VERSION 5.8 ;
BUSBITCHARS "[]" ;
DIVIDERCHAR "/" ;
UNITS
    DATABASE MICRONS 1000 ;
END UNITS

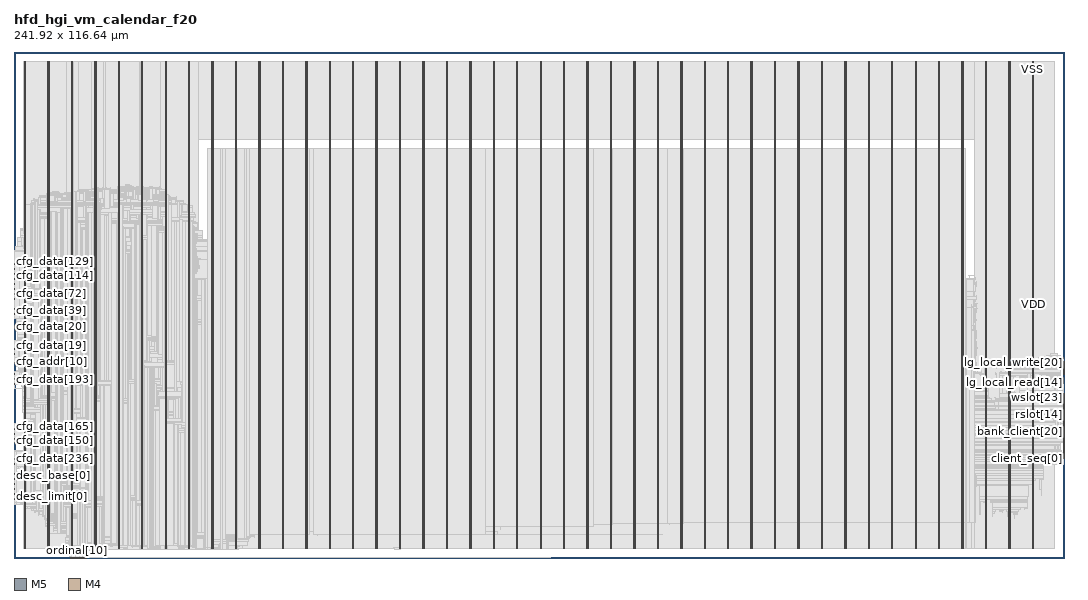
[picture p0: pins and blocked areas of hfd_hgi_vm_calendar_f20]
MACRO hfd_hgi_vm_calendar_f20
  FOREIGN hfd_hgi_vm_calendar_f20 0 0 ;
  CLASS BLOCK ;
  SIZE 241.92 BY 116.64 ;
  PIN active
    DIRECTION OUTPUT ;
    USE SIGNAL ;
    PORT
      LAYER M5 ;
        RECT  13.008 0 13.032 0.084 ;
    END
  END active
  PIN bank_client[0]
    DIRECTION OUTPUT ;
    USE SIGNAL ;
    PORT
      LAYER M4 ;
        RECT  241.836 29.136 241.92 29.16 ;
    END
  END bank_client[0]
  PIN bank_client[10]
    DIRECTION OUTPUT ;
    USE SIGNAL ;
    PORT
      LAYER M4 ;
        RECT  241.836 30.096 241.92 30.12 ;
    END
  END bank_client[10]
  PIN bank_client[11]
    DIRECTION OUTPUT ;
    USE SIGNAL ;
    PORT
      LAYER M4 ;
        RECT  241.836 30.192 241.92 30.216 ;
    END
  END bank_client[11]
  PIN bank_client[12]
    DIRECTION OUTPUT ;
    USE SIGNAL ;
    PORT
      LAYER M4 ;
        RECT  241.836 30.288 241.92 30.312 ;
    END
  END bank_client[12]
  PIN bank_client[13]
    DIRECTION OUTPUT ;
    USE SIGNAL ;
    PORT
      LAYER M4 ;
        RECT  241.836 30.384 241.92 30.408 ;
    END
  END bank_client[13]
  PIN bank_client[14]
    DIRECTION OUTPUT ;
    USE SIGNAL ;
    PORT
      LAYER M4 ;
        RECT  241.836 30.48 241.92 30.504 ;
    END
  END bank_client[14]
  PIN bank_client[15]
    DIRECTION OUTPUT ;
    USE SIGNAL ;
    PORT
      LAYER M4 ;
        RECT  241.836 30.576 241.92 30.6 ;
    END
  END bank_client[15]
  PIN bank_client[16]
    DIRECTION OUTPUT ;
    USE SIGNAL ;
    PORT
      LAYER M4 ;
        RECT  241.836 30.672 241.92 30.696 ;
    END
  END bank_client[16]
  PIN bank_client[17]
    DIRECTION OUTPUT ;
    USE SIGNAL ;
    PORT
      LAYER M4 ;
        RECT  241.836 30.768 241.92 30.792 ;
    END
  END bank_client[17]
  PIN bank_client[18]
    DIRECTION OUTPUT ;
    USE SIGNAL ;
    PORT
      LAYER M4 ;
        RECT  241.836 30.864 241.92 30.888 ;
    END
  END bank_client[18]
  PIN bank_client[19]
    DIRECTION OUTPUT ;
    USE SIGNAL ;
    PORT
      LAYER M4 ;
        RECT  241.836 30.96 241.92 30.984 ;
    END
  END bank_client[19]
  PIN bank_client[1]
    DIRECTION OUTPUT ;
    USE SIGNAL ;
    PORT
      LAYER M4 ;
        RECT  241.836 29.232 241.92 29.256 ;
    END
  END bank_client[1]
  PIN bank_client[20]
    DIRECTION OUTPUT ;
    USE SIGNAL ;
    PORT
      LAYER M4 ;
        RECT  241.836 31.056 241.92 31.08 ;
    END
  END bank_client[20]
  PIN bank_client[21]
    DIRECTION OUTPUT ;
    USE SIGNAL ;
    PORT
      LAYER M4 ;
        RECT  241.836 31.152 241.92 31.176 ;
    END
  END bank_client[21]
  PIN bank_client[22]
    DIRECTION OUTPUT ;
    USE SIGNAL ;
    PORT
      LAYER M4 ;
        RECT  241.836 31.248 241.92 31.272 ;
    END
  END bank_client[22]
  PIN bank_client[23]
    DIRECTION OUTPUT ;
    USE SIGNAL ;
    PORT
      LAYER M4 ;
        RECT  241.836 31.344 241.92 31.368 ;
    END
  END bank_client[23]
  PIN bank_client[2]
    DIRECTION OUTPUT ;
    USE SIGNAL ;
    PORT
      LAYER M4 ;
        RECT  241.836 29.328 241.92 29.352 ;
    END
  END bank_client[2]
  PIN bank_client[3]
    DIRECTION OUTPUT ;
    USE SIGNAL ;
    PORT
      LAYER M4 ;
        RECT  241.836 29.424 241.92 29.448 ;
    END
  END bank_client[3]
  PIN bank_client[4]
    DIRECTION OUTPUT ;
    USE SIGNAL ;
    PORT
      LAYER M4 ;
        RECT  241.836 29.52 241.92 29.544 ;
    END
  END bank_client[4]
  PIN bank_client[5]
    DIRECTION OUTPUT ;
    USE SIGNAL ;
    PORT
      LAYER M4 ;
        RECT  241.836 29.616 241.92 29.64 ;
    END
  END bank_client[5]
  PIN bank_client[6]
    DIRECTION OUTPUT ;
    USE SIGNAL ;
    PORT
      LAYER M4 ;
        RECT  241.836 29.712 241.92 29.736 ;
    END
  END bank_client[6]
  PIN bank_client[7]
    DIRECTION OUTPUT ;
    USE SIGNAL ;
    PORT
      LAYER M4 ;
        RECT  241.836 29.808 241.92 29.832 ;
    END
  END bank_client[7]
  PIN bank_client[8]
    DIRECTION OUTPUT ;
    USE SIGNAL ;
    PORT
      LAYER M4 ;
        RECT  241.836 29.904 241.92 29.928 ;
    END
  END bank_client[8]
  PIN bank_client[9]
    DIRECTION OUTPUT ;
    USE SIGNAL ;
    PORT
      LAYER M4 ;
        RECT  241.836 30 241.92 30.024 ;
    END
  END bank_client[9]
  PIN bank_enable[0]
    DIRECTION OUTPUT ;
    USE SIGNAL ;
    PORT
      LAYER M4 ;
        RECT  241.836 31.44 241.92 31.464 ;
    END
  END bank_enable[0]
  PIN bank_enable[1]
    DIRECTION OUTPUT ;
    USE SIGNAL ;
    PORT
      LAYER M4 ;
        RECT  241.836 31.536 241.92 31.56 ;
    END
  END bank_enable[1]
  PIN bank_enable[2]
    DIRECTION OUTPUT ;
    USE SIGNAL ;
    PORT
      LAYER M4 ;
        RECT  241.836 31.632 241.92 31.656 ;
    END
  END bank_enable[2]
  PIN bank_enable[3]
    DIRECTION OUTPUT ;
    USE SIGNAL ;
    PORT
      LAYER M4 ;
        RECT  241.836 31.728 241.92 31.752 ;
    END
  END bank_enable[3]
  PIN bank_enable[4]
    DIRECTION OUTPUT ;
    USE SIGNAL ;
    PORT
      LAYER M4 ;
        RECT  241.836 31.824 241.92 31.848 ;
    END
  END bank_enable[4]
  PIN bank_enable[5]
    DIRECTION OUTPUT ;
    USE SIGNAL ;
    PORT
      LAYER M4 ;
        RECT  241.836 31.92 241.92 31.944 ;
    END
  END bank_enable[5]
  PIN bank_enable[6]
    DIRECTION OUTPUT ;
    USE SIGNAL ;
    PORT
      LAYER M4 ;
        RECT  241.836 32.016 241.92 32.04 ;
    END
  END bank_enable[6]
  PIN bank_enable[7]
    DIRECTION OUTPUT ;
    USE SIGNAL ;
    PORT
      LAYER M4 ;
        RECT  241.836 32.112 241.92 32.136 ;
    END
  END bank_enable[7]
  PIN calendar_v
    DIRECTION OUTPUT ;
    USE SIGNAL ;
    PORT
      LAYER M5 ;
        RECT  13.104 0 13.128 0.084 ;
    END
  END calendar_v
  PIN cfg_addr[0]
    DIRECTION INPUT ;
    USE SIGNAL ;
    PORT
      LAYER M4 ;
        RECT  0 46.032 0.084 46.056 ;
    END
  END cfg_addr[0]
  PIN cfg_addr[10]
    DIRECTION INPUT ;
    USE SIGNAL ;
    PORT
      LAYER M4 ;
        RECT  0 46.992 0.084 47.016 ;
    END
  END cfg_addr[10]
  PIN cfg_addr[11]
    DIRECTION INPUT ;
    USE SIGNAL ;
    PORT
      LAYER M4 ;
        RECT  0 47.088 0.084 47.112 ;
    END
  END cfg_addr[11]
  PIN cfg_addr[1]
    DIRECTION INPUT ;
    USE SIGNAL ;
    PORT
      LAYER M4 ;
        RECT  0 46.128 0.084 46.152 ;
    END
  END cfg_addr[1]
  PIN cfg_addr[2]
    DIRECTION INPUT ;
    USE SIGNAL ;
    PORT
      LAYER M4 ;
        RECT  0 46.224 0.084 46.248 ;
    END
  END cfg_addr[2]
  PIN cfg_addr[3]
    DIRECTION INPUT ;
    USE SIGNAL ;
    PORT
      LAYER M4 ;
        RECT  0 46.32 0.084 46.344 ;
    END
  END cfg_addr[3]
  PIN cfg_addr[4]
    DIRECTION INPUT ;
    USE SIGNAL ;
    PORT
      LAYER M4 ;
        RECT  0 46.416 0.084 46.44 ;
    END
  END cfg_addr[4]
  PIN cfg_addr[5]
    DIRECTION INPUT ;
    USE SIGNAL ;
    PORT
      LAYER M4 ;
        RECT  0 46.512 0.084 46.536 ;
    END
  END cfg_addr[5]
  PIN cfg_addr[6]
    DIRECTION INPUT ;
    USE SIGNAL ;
    PORT
      LAYER M4 ;
        RECT  0 46.608 0.084 46.632 ;
    END
  END cfg_addr[6]
  PIN cfg_addr[7]
    DIRECTION INPUT ;
    USE SIGNAL ;
    PORT
      LAYER M4 ;
        RECT  0 46.704 0.084 46.728 ;
    END
  END cfg_addr[7]
  PIN cfg_addr[8]
    DIRECTION INPUT ;
    USE SIGNAL ;
    PORT
      LAYER M4 ;
        RECT  0 46.8 0.084 46.824 ;
    END
  END cfg_addr[8]
  PIN cfg_addr[9]
    DIRECTION INPUT ;
    USE SIGNAL ;
    PORT
      LAYER M4 ;
        RECT  0 46.896 0.084 46.92 ;
    END
  END cfg_addr[9]
  PIN cfg_data[0]
    DIRECTION INPUT ;
    USE SIGNAL ;
    PORT
      LAYER M4 ;
        RECT  0 47.184 0.084 47.208 ;
    END
  END cfg_data[0]
  PIN cfg_data[100]
    DIRECTION INPUT ;
    USE SIGNAL ;
    PORT
      LAYER M4 ;
        RECT  0 63.696 0.084 63.72 ;
    END
  END cfg_data[100]
  PIN cfg_data[101]
    DIRECTION INPUT ;
    USE SIGNAL ;
    PORT
      LAYER M4 ;
        RECT  0 63.792 0.084 63.816 ;
    END
  END cfg_data[101]
  PIN cfg_data[102]
    DIRECTION INPUT ;
    USE SIGNAL ;
    PORT
      LAYER M4 ;
        RECT  0 63.888 0.084 63.912 ;
    END
  END cfg_data[102]
  PIN cfg_data[103]
    DIRECTION INPUT ;
    USE SIGNAL ;
    PORT
      LAYER M4 ;
        RECT  0 63.984 0.084 64.008 ;
    END
  END cfg_data[103]
  PIN cfg_data[104]
    DIRECTION INPUT ;
    USE SIGNAL ;
    PORT
      LAYER M4 ;
        RECT  0 64.08 0.084 64.104 ;
    END
  END cfg_data[104]
  PIN cfg_data[105]
    DIRECTION INPUT ;
    USE SIGNAL ;
    PORT
      LAYER M4 ;
        RECT  0 64.176 0.084 64.2 ;
    END
  END cfg_data[105]
  PIN cfg_data[106]
    DIRECTION INPUT ;
    USE SIGNAL ;
    PORT
      LAYER M4 ;
        RECT  0 64.272 0.084 64.296 ;
    END
  END cfg_data[106]
  PIN cfg_data[107]
    DIRECTION INPUT ;
    USE SIGNAL ;
    PORT
      LAYER M4 ;
        RECT  0 64.368 0.084 64.392 ;
    END
  END cfg_data[107]
  PIN cfg_data[108]
    DIRECTION INPUT ;
    USE SIGNAL ;
    PORT
      LAYER M4 ;
        RECT  0 64.464 0.084 64.488 ;
    END
  END cfg_data[108]
  PIN cfg_data[109]
    DIRECTION INPUT ;
    USE SIGNAL ;
    PORT
      LAYER M4 ;
        RECT  0 64.56 0.084 64.584 ;
    END
  END cfg_data[109]
  PIN cfg_data[10]
    DIRECTION INPUT ;
    USE SIGNAL ;
    PORT
      LAYER M4 ;
        RECT  0 48.144 0.084 48.168 ;
    END
  END cfg_data[10]
  PIN cfg_data[110]
    DIRECTION INPUT ;
    USE SIGNAL ;
    PORT
      LAYER M4 ;
        RECT  0 64.656 0.084 64.68 ;
    END
  END cfg_data[110]
  PIN cfg_data[111]
    DIRECTION INPUT ;
    USE SIGNAL ;
    PORT
      LAYER M4 ;
        RECT  0 64.752 0.084 64.776 ;
    END
  END cfg_data[111]
  PIN cfg_data[112]
    DIRECTION INPUT ;
    USE SIGNAL ;
    PORT
      LAYER M4 ;
        RECT  0 64.848 0.084 64.872 ;
    END
  END cfg_data[112]
  PIN cfg_data[113]
    DIRECTION INPUT ;
    USE SIGNAL ;
    PORT
      LAYER M4 ;
        RECT  0 64.944 0.084 64.968 ;
    END
  END cfg_data[113]
  PIN cfg_data[114]
    DIRECTION INPUT ;
    USE SIGNAL ;
    PORT
      LAYER M4 ;
        RECT  0 65.04 0.084 65.064 ;
    END
  END cfg_data[114]
  PIN cfg_data[115]
    DIRECTION INPUT ;
    USE SIGNAL ;
    PORT
      LAYER M4 ;
        RECT  0 65.136 0.084 65.16 ;
    END
  END cfg_data[115]
  PIN cfg_data[116]
    DIRECTION INPUT ;
    USE SIGNAL ;
    PORT
      LAYER M4 ;
        RECT  0 65.232 0.084 65.256 ;
    END
  END cfg_data[116]
  PIN cfg_data[117]
    DIRECTION INPUT ;
    USE SIGNAL ;
    PORT
      LAYER M4 ;
        RECT  0 65.328 0.084 65.352 ;
    END
  END cfg_data[117]
  PIN cfg_data[118]
    DIRECTION INPUT ;
    USE SIGNAL ;
    PORT
      LAYER M4 ;
        RECT  0 65.424 0.084 65.448 ;
    END
  END cfg_data[118]
  PIN cfg_data[119]
    DIRECTION INPUT ;
    USE SIGNAL ;
    PORT
      LAYER M4 ;
        RECT  0 65.52 0.084 65.544 ;
    END
  END cfg_data[119]
  PIN cfg_data[11]
    DIRECTION INPUT ;
    USE SIGNAL ;
    PORT
      LAYER M4 ;
        RECT  0 48.24 0.084 48.264 ;
    END
  END cfg_data[11]
  PIN cfg_data[120]
    DIRECTION INPUT ;
    USE SIGNAL ;
    PORT
      LAYER M4 ;
        RECT  0 65.616 0.084 65.64 ;
    END
  END cfg_data[120]
  PIN cfg_data[121]
    DIRECTION INPUT ;
    USE SIGNAL ;
    PORT
      LAYER M4 ;
        RECT  0 65.712 0.084 65.736 ;
    END
  END cfg_data[121]
  PIN cfg_data[122]
    DIRECTION INPUT ;
    USE SIGNAL ;
    PORT
      LAYER M4 ;
        RECT  0 65.808 0.084 65.832 ;
    END
  END cfg_data[122]
  PIN cfg_data[123]
    DIRECTION INPUT ;
    USE SIGNAL ;
    PORT
      LAYER M4 ;
        RECT  0 65.904 0.084 65.928 ;
    END
  END cfg_data[123]
  PIN cfg_data[124]
    DIRECTION INPUT ;
    USE SIGNAL ;
    PORT
      LAYER M4 ;
        RECT  0 66 0.084 66.024 ;
    END
  END cfg_data[124]
  PIN cfg_data[125]
    DIRECTION INPUT ;
    USE SIGNAL ;
    PORT
      LAYER M4 ;
        RECT  0 66.096 0.084 66.12 ;
    END
  END cfg_data[125]
  PIN cfg_data[126]
    DIRECTION INPUT ;
    USE SIGNAL ;
    PORT
      LAYER M4 ;
        RECT  0 66.192 0.084 66.216 ;
    END
  END cfg_data[126]
  PIN cfg_data[127]
    DIRECTION INPUT ;
    USE SIGNAL ;
    PORT
      LAYER M4 ;
        RECT  0 66.288 0.084 66.312 ;
    END
  END cfg_data[127]
  PIN cfg_data[128]
    DIRECTION INPUT ;
    USE SIGNAL ;
    PORT
      LAYER M4 ;
        RECT  0 66.384 0.084 66.408 ;
    END
  END cfg_data[128]
  PIN cfg_data[129]
    DIRECTION INPUT ;
    USE SIGNAL ;
    PORT
      LAYER M4 ;
        RECT  0 66.48 0.084 66.504 ;
    END
  END cfg_data[129]
  PIN cfg_data[12]
    DIRECTION INPUT ;
    USE SIGNAL ;
    PORT
      LAYER M4 ;
        RECT  0 48.336 0.084 48.36 ;
    END
  END cfg_data[12]
  PIN cfg_data[130]
    DIRECTION INPUT ;
    USE SIGNAL ;
    PORT
      LAYER M4 ;
        RECT  0 66.576 0.084 66.6 ;
    END
  END cfg_data[130]
  PIN cfg_data[131]
    DIRECTION INPUT ;
    USE SIGNAL ;
    PORT
      LAYER M4 ;
        RECT  0 66.672 0.084 66.696 ;
    END
  END cfg_data[131]
  PIN cfg_data[132]
    DIRECTION INPUT ;
    USE SIGNAL ;
    PORT
      LAYER M4 ;
        RECT  0 66.768 0.084 66.792 ;
    END
  END cfg_data[132]
  PIN cfg_data[133]
    DIRECTION INPUT ;
    USE SIGNAL ;
    PORT
      LAYER M4 ;
        RECT  0 66.864 0.084 66.888 ;
    END
  END cfg_data[133]
  PIN cfg_data[134]
    DIRECTION INPUT ;
    USE SIGNAL ;
    PORT
      LAYER M4 ;
        RECT  0 66.96 0.084 66.984 ;
    END
  END cfg_data[134]
  PIN cfg_data[135]
    DIRECTION INPUT ;
    USE SIGNAL ;
    PORT
      LAYER M4 ;
        RECT  0 67.056 0.084 67.08 ;
    END
  END cfg_data[135]
  PIN cfg_data[136]
    DIRECTION INPUT ;
    USE SIGNAL ;
    PORT
      LAYER M4 ;
        RECT  0 67.152 0.084 67.176 ;
    END
  END cfg_data[136]
  PIN cfg_data[137]
    DIRECTION INPUT ;
    USE SIGNAL ;
    PORT
      LAYER M4 ;
        RECT  0 67.248 0.084 67.272 ;
    END
  END cfg_data[137]
  PIN cfg_data[138]
    DIRECTION INPUT ;
    USE SIGNAL ;
    PORT
      LAYER M4 ;
        RECT  0 67.344 0.084 67.368 ;
    END
  END cfg_data[138]
  PIN cfg_data[139]
    DIRECTION INPUT ;
    USE SIGNAL ;
    PORT
      LAYER M4 ;
        RECT  0 67.44 0.084 67.464 ;
    END
  END cfg_data[139]
  PIN cfg_data[13]
    DIRECTION INPUT ;
    USE SIGNAL ;
    PORT
      LAYER M4 ;
        RECT  0 48.432 0.084 48.456 ;
    END
  END cfg_data[13]
  PIN cfg_data[140]
    DIRECTION INPUT ;
    USE SIGNAL ;
    PORT
      LAYER M4 ;
        RECT  0 67.536 0.084 67.56 ;
    END
  END cfg_data[140]
  PIN cfg_data[141]
    DIRECTION INPUT ;
    USE SIGNAL ;
    PORT
      LAYER M4 ;
        RECT  0 67.632 0.084 67.656 ;
    END
  END cfg_data[141]
  PIN cfg_data[142]
    DIRECTION INPUT ;
    USE SIGNAL ;
    PORT
      LAYER M4 ;
        RECT  0 67.728 0.084 67.752 ;
    END
  END cfg_data[142]
  PIN cfg_data[143]
    DIRECTION INPUT ;
    USE SIGNAL ;
    PORT
      LAYER M4 ;
        RECT  0 67.824 0.084 67.848 ;
    END
  END cfg_data[143]
  PIN cfg_data[144]
    DIRECTION INPUT ;
    USE SIGNAL ;
    PORT
      LAYER M4 ;
        RECT  0 67.92 0.084 67.944 ;
    END
  END cfg_data[144]
  PIN cfg_data[145]
    DIRECTION INPUT ;
    USE SIGNAL ;
    PORT
      LAYER M4 ;
        RECT  0 68.016 0.084 68.04 ;
    END
  END cfg_data[145]
  PIN cfg_data[146]
    DIRECTION INPUT ;
    USE SIGNAL ;
    PORT
      LAYER M4 ;
        RECT  0 68.112 0.084 68.136 ;
    END
  END cfg_data[146]
  PIN cfg_data[147]
    DIRECTION INPUT ;
    USE SIGNAL ;
    PORT
      LAYER M4 ;
        RECT  0 68.208 0.084 68.232 ;
    END
  END cfg_data[147]
  PIN cfg_data[148]
    DIRECTION INPUT ;
    USE SIGNAL ;
    PORT
      LAYER M4 ;
        RECT  0 26.832 0.084 26.856 ;
    END
  END cfg_data[148]
  PIN cfg_data[149]
    DIRECTION INPUT ;
    USE SIGNAL ;
    PORT
      LAYER M4 ;
        RECT  0 26.928 0.084 26.952 ;
    END
  END cfg_data[149]
  PIN cfg_data[14]
    DIRECTION INPUT ;
    USE SIGNAL ;
    PORT
      LAYER M4 ;
        RECT  0 48.528 0.084 48.552 ;
    END
  END cfg_data[14]
  PIN cfg_data[150]
    DIRECTION INPUT ;
    USE SIGNAL ;
    PORT
      LAYER M4 ;
        RECT  0 27.024 0.084 27.048 ;
    END
  END cfg_data[150]
  PIN cfg_data[151]
    DIRECTION INPUT ;
    USE SIGNAL ;
    PORT
      LAYER M4 ;
        RECT  0 27.12 0.084 27.144 ;
    END
  END cfg_data[151]
  PIN cfg_data[152]
    DIRECTION INPUT ;
    USE SIGNAL ;
    PORT
      LAYER M4 ;
        RECT  0 27.216 0.084 27.24 ;
    END
  END cfg_data[152]
  PIN cfg_data[153]
    DIRECTION INPUT ;
    USE SIGNAL ;
    PORT
      LAYER M4 ;
        RECT  0 27.312 0.084 27.336 ;
    END
  END cfg_data[153]
  PIN cfg_data[154]
    DIRECTION INPUT ;
    USE SIGNAL ;
    PORT
      LAYER M4 ;
        RECT  0 27.408 0.084 27.432 ;
    END
  END cfg_data[154]
  PIN cfg_data[155]
    DIRECTION INPUT ;
    USE SIGNAL ;
    PORT
      LAYER M4 ;
        RECT  0 27.504 0.084 27.528 ;
    END
  END cfg_data[155]
  PIN cfg_data[156]
    DIRECTION INPUT ;
    USE SIGNAL ;
    PORT
      LAYER M4 ;
        RECT  0 27.6 0.084 27.624 ;
    END
  END cfg_data[156]
  PIN cfg_data[157]
    DIRECTION INPUT ;
    USE SIGNAL ;
    PORT
      LAYER M4 ;
        RECT  0 27.696 0.084 27.72 ;
    END
  END cfg_data[157]
  PIN cfg_data[158]
    DIRECTION INPUT ;
    USE SIGNAL ;
    PORT
      LAYER M4 ;
        RECT  0 27.792 0.084 27.816 ;
    END
  END cfg_data[158]
  PIN cfg_data[159]
    DIRECTION INPUT ;
    USE SIGNAL ;
    PORT
      LAYER M4 ;
        RECT  0 27.888 0.084 27.912 ;
    END
  END cfg_data[159]
  PIN cfg_data[15]
    DIRECTION INPUT ;
    USE SIGNAL ;
    PORT
      LAYER M4 ;
        RECT  0 48.624 0.084 48.648 ;
    END
  END cfg_data[15]
  PIN cfg_data[160]
    DIRECTION INPUT ;
    USE SIGNAL ;
    PORT
      LAYER M4 ;
        RECT  0 27.984 0.084 28.008 ;
    END
  END cfg_data[160]
  PIN cfg_data[161]
    DIRECTION INPUT ;
    USE SIGNAL ;
    PORT
      LAYER M4 ;
        RECT  0 28.08 0.084 28.104 ;
    END
  END cfg_data[161]
  PIN cfg_data[162]
    DIRECTION INPUT ;
    USE SIGNAL ;
    PORT
      LAYER M4 ;
        RECT  0 28.176 0.084 28.2 ;
    END
  END cfg_data[162]
  PIN cfg_data[163]
    DIRECTION INPUT ;
    USE SIGNAL ;
    PORT
      LAYER M4 ;
        RECT  0 28.272 0.084 28.296 ;
    END
  END cfg_data[163]
  PIN cfg_data[164]
    DIRECTION INPUT ;
    USE SIGNAL ;
    PORT
      LAYER M4 ;
        RECT  0 28.368 0.084 28.392 ;
    END
  END cfg_data[164]
  PIN cfg_data[165]
    DIRECTION INPUT ;
    USE SIGNAL ;
    PORT
      LAYER M4 ;
        RECT  0 28.464 0.084 28.488 ;
    END
  END cfg_data[165]
  PIN cfg_data[166]
    DIRECTION INPUT ;
    USE SIGNAL ;
    PORT
      LAYER M4 ;
        RECT  0 28.56 0.084 28.584 ;
    END
  END cfg_data[166]
  PIN cfg_data[167]
    DIRECTION INPUT ;
    USE SIGNAL ;
    PORT
      LAYER M4 ;
        RECT  0 28.656 0.084 28.68 ;
    END
  END cfg_data[167]
  PIN cfg_data[168]
    DIRECTION INPUT ;
    USE SIGNAL ;
    PORT
      LAYER M4 ;
        RECT  0 28.752 0.084 28.776 ;
    END
  END cfg_data[168]
  PIN cfg_data[169]
    DIRECTION INPUT ;
    USE SIGNAL ;
    PORT
      LAYER M4 ;
        RECT  0 28.848 0.084 28.872 ;
    END
  END cfg_data[169]
  PIN cfg_data[16]
    DIRECTION INPUT ;
    USE SIGNAL ;
    PORT
      LAYER M4 ;
        RECT  0 48.72 0.084 48.744 ;
    END
  END cfg_data[16]
  PIN cfg_data[170]
    DIRECTION INPUT ;
    USE SIGNAL ;
    PORT
      LAYER M4 ;
        RECT  0 28.944 0.084 28.968 ;
    END
  END cfg_data[170]
  PIN cfg_data[171]
    DIRECTION INPUT ;
    USE SIGNAL ;
    PORT
      LAYER M4 ;
        RECT  0 29.04 0.084 29.064 ;
    END
  END cfg_data[171]
  PIN cfg_data[172]
    DIRECTION INPUT ;
    USE SIGNAL ;
    PORT
      LAYER M4 ;
        RECT  0 29.136 0.084 29.16 ;
    END
  END cfg_data[172]
  PIN cfg_data[173]
    DIRECTION INPUT ;
    USE SIGNAL ;
    PORT
      LAYER M4 ;
        RECT  0 29.232 0.084 29.256 ;
    END
  END cfg_data[173]
  PIN cfg_data[174]
    DIRECTION INPUT ;
    USE SIGNAL ;
    PORT
      LAYER M4 ;
        RECT  0 29.328 0.084 29.352 ;
    END
  END cfg_data[174]
  PIN cfg_data[175]
    DIRECTION INPUT ;
    USE SIGNAL ;
    PORT
      LAYER M4 ;
        RECT  0 29.424 0.084 29.448 ;
    END
  END cfg_data[175]
  PIN cfg_data[176]
    DIRECTION INPUT ;
    USE SIGNAL ;
    PORT
      LAYER M4 ;
        RECT  0 29.52 0.084 29.544 ;
    END
  END cfg_data[176]
  PIN cfg_data[177]
    DIRECTION INPUT ;
    USE SIGNAL ;
    PORT
      LAYER M4 ;
        RECT  0 29.616 0.084 29.64 ;
    END
  END cfg_data[177]
  PIN cfg_data[178]
    DIRECTION INPUT ;
    USE SIGNAL ;
    PORT
      LAYER M4 ;
        RECT  0 29.712 0.084 29.736 ;
    END
  END cfg_data[178]
  PIN cfg_data[179]
    DIRECTION INPUT ;
    USE SIGNAL ;
    PORT
      LAYER M4 ;
        RECT  0 29.808 0.084 29.832 ;
    END
  END cfg_data[179]
  PIN cfg_data[17]
    DIRECTION INPUT ;
    USE SIGNAL ;
    PORT
      LAYER M4 ;
        RECT  0 48.816 0.084 48.84 ;
    END
  END cfg_data[17]
  PIN cfg_data[180]
    DIRECTION INPUT ;
    USE SIGNAL ;
    PORT
      LAYER M4 ;
        RECT  0 39.888 0.084 39.912 ;
    END
  END cfg_data[180]
  PIN cfg_data[181]
    DIRECTION INPUT ;
    USE SIGNAL ;
    PORT
      LAYER M4 ;
        RECT  0 39.984 0.084 40.008 ;
    END
  END cfg_data[181]
  PIN cfg_data[182]
    DIRECTION INPUT ;
    USE SIGNAL ;
    PORT
      LAYER M4 ;
        RECT  0 40.08 0.084 40.104 ;
    END
  END cfg_data[182]
  PIN cfg_data[183]
    DIRECTION INPUT ;
    USE SIGNAL ;
    PORT
      LAYER M4 ;
        RECT  0 40.176 0.084 40.2 ;
    END
  END cfg_data[183]
  PIN cfg_data[184]
    DIRECTION INPUT ;
    USE SIGNAL ;
    PORT
      LAYER M4 ;
        RECT  0 40.272 0.084 40.296 ;
    END
  END cfg_data[184]
  PIN cfg_data[185]
    DIRECTION INPUT ;
    USE SIGNAL ;
    PORT
      LAYER M4 ;
        RECT  0 40.368 0.084 40.392 ;
    END
  END cfg_data[185]
  PIN cfg_data[186]
    DIRECTION INPUT ;
    USE SIGNAL ;
    PORT
      LAYER M4 ;
        RECT  0 40.464 0.084 40.488 ;
    END
  END cfg_data[186]
  PIN cfg_data[187]
    DIRECTION INPUT ;
    USE SIGNAL ;
    PORT
      LAYER M4 ;
        RECT  0 40.56 0.084 40.584 ;
    END
  END cfg_data[187]
  PIN cfg_data[188]
    DIRECTION INPUT ;
    USE SIGNAL ;
    PORT
      LAYER M4 ;
        RECT  0 40.656 0.084 40.68 ;
    END
  END cfg_data[188]
  PIN cfg_data[189]
    DIRECTION INPUT ;
    USE SIGNAL ;
    PORT
      LAYER M4 ;
        RECT  0 40.752 0.084 40.776 ;
    END
  END cfg_data[189]
  PIN cfg_data[18]
    DIRECTION INPUT ;
    USE SIGNAL ;
    PORT
      LAYER M4 ;
        RECT  0 48.912 0.084 48.936 ;
    END
  END cfg_data[18]
  PIN cfg_data[190]
    DIRECTION INPUT ;
    USE SIGNAL ;
    PORT
      LAYER M4 ;
        RECT  0 40.848 0.084 40.872 ;
    END
  END cfg_data[190]
  PIN cfg_data[191]
    DIRECTION INPUT ;
    USE SIGNAL ;
    PORT
      LAYER M4 ;
        RECT  0 40.944 0.084 40.968 ;
    END
  END cfg_data[191]
  PIN cfg_data[192]
    DIRECTION INPUT ;
    USE SIGNAL ;
    PORT
      LAYER M4 ;
        RECT  0 41.04 0.084 41.064 ;
    END
  END cfg_data[192]
  PIN cfg_data[193]
    DIRECTION INPUT ;
    USE SIGNAL ;
    PORT
      LAYER M4 ;
        RECT  0 41.136 0.084 41.16 ;
    END
  END cfg_data[193]
  PIN cfg_data[194]
    DIRECTION INPUT ;
    USE SIGNAL ;
    PORT
      LAYER M4 ;
        RECT  0 41.232 0.084 41.256 ;
    END
  END cfg_data[194]
  PIN cfg_data[195]
    DIRECTION INPUT ;
    USE SIGNAL ;
    PORT
      LAYER M4 ;
        RECT  0 41.328 0.084 41.352 ;
    END
  END cfg_data[195]
  PIN cfg_data[196]
    DIRECTION INPUT ;
    USE SIGNAL ;
    PORT
      LAYER M4 ;
        RECT  0 41.424 0.084 41.448 ;
    END
  END cfg_data[196]
  PIN cfg_data[197]
    DIRECTION INPUT ;
    USE SIGNAL ;
    PORT
      LAYER M4 ;
        RECT  0 41.52 0.084 41.544 ;
    END
  END cfg_data[197]
  PIN cfg_data[198]
    DIRECTION INPUT ;
    USE SIGNAL ;
    PORT
      LAYER M4 ;
        RECT  0 41.616 0.084 41.64 ;
    END
  END cfg_data[198]
  PIN cfg_data[199]
    DIRECTION INPUT ;
    USE SIGNAL ;
    PORT
      LAYER M4 ;
        RECT  0 41.712 0.084 41.736 ;
    END
  END cfg_data[199]
  PIN cfg_data[19]
    DIRECTION INPUT ;
    USE SIGNAL ;
    PORT
      LAYER M4 ;
        RECT  0 49.008 0.084 49.032 ;
    END
  END cfg_data[19]
  PIN cfg_data[1]
    DIRECTION INPUT ;
    USE SIGNAL ;
    PORT
      LAYER M4 ;
        RECT  0 47.28 0.084 47.304 ;
    END
  END cfg_data[1]
  PIN cfg_data[200]
    DIRECTION INPUT ;
    USE SIGNAL ;
    PORT
      LAYER M4 ;
        RECT  0 41.808 0.084 41.832 ;
    END
  END cfg_data[200]
  PIN cfg_data[201]
    DIRECTION INPUT ;
    USE SIGNAL ;
    PORT
      LAYER M4 ;
        RECT  0 41.904 0.084 41.928 ;
    END
  END cfg_data[201]
  PIN cfg_data[202]
    DIRECTION INPUT ;
    USE SIGNAL ;
    PORT
      LAYER M4 ;
        RECT  0 42 0.084 42.024 ;
    END
  END cfg_data[202]
  PIN cfg_data[203]
    DIRECTION INPUT ;
    USE SIGNAL ;
    PORT
      LAYER M4 ;
        RECT  0 42.096 0.084 42.12 ;
    END
  END cfg_data[203]
  PIN cfg_data[204]
    DIRECTION INPUT ;
    USE SIGNAL ;
    PORT
      LAYER M4 ;
        RECT  0 42.192 0.084 42.216 ;
    END
  END cfg_data[204]
  PIN cfg_data[205]
    DIRECTION INPUT ;
    USE SIGNAL ;
    PORT
      LAYER M4 ;
        RECT  0 42.288 0.084 42.312 ;
    END
  END cfg_data[205]
  PIN cfg_data[206]
    DIRECTION INPUT ;
    USE SIGNAL ;
    PORT
      LAYER M4 ;
        RECT  0 42.384 0.084 42.408 ;
    END
  END cfg_data[206]
  PIN cfg_data[207]
    DIRECTION INPUT ;
    USE SIGNAL ;
    PORT
      LAYER M4 ;
        RECT  0 42.48 0.084 42.504 ;
    END
  END cfg_data[207]
  PIN cfg_data[208]
    DIRECTION INPUT ;
    USE SIGNAL ;
    PORT
      LAYER M4 ;
        RECT  0 42.576 0.084 42.6 ;
    END
  END cfg_data[208]
  PIN cfg_data[209]
    DIRECTION INPUT ;
    USE SIGNAL ;
    PORT
      LAYER M4 ;
        RECT  0 42.672 0.084 42.696 ;
    END
  END cfg_data[209]
  PIN cfg_data[20]
    DIRECTION INPUT ;
    USE SIGNAL ;
    PORT
      LAYER M4 ;
        RECT  0 55.248 0.084 55.272 ;
    END
  END cfg_data[20]
  PIN cfg_data[210]
    DIRECTION INPUT ;
    USE SIGNAL ;
    PORT
      LAYER M4 ;
        RECT  0 42.768 0.084 42.792 ;
    END
  END cfg_data[210]
  PIN cfg_data[211]
    DIRECTION INPUT ;
    USE SIGNAL ;
    PORT
      LAYER M4 ;
        RECT  0 42.864 0.084 42.888 ;
    END
  END cfg_data[211]
  PIN cfg_data[212]
    DIRECTION INPUT ;
    USE SIGNAL ;
    PORT
      LAYER M4 ;
        RECT  0 20.688 0.084 20.712 ;
    END
  END cfg_data[212]
  PIN cfg_data[213]
    DIRECTION INPUT ;
    USE SIGNAL ;
    PORT
      LAYER M4 ;
        RECT  0 20.784 0.084 20.808 ;
    END
  END cfg_data[213]
  PIN cfg_data[214]
    DIRECTION INPUT ;
    USE SIGNAL ;
    PORT
      LAYER M4 ;
        RECT  0 20.88 0.084 20.904 ;
    END
  END cfg_data[214]
  PIN cfg_data[215]
    DIRECTION INPUT ;
    USE SIGNAL ;
    PORT
      LAYER M4 ;
        RECT  0 20.976 0.084 21 ;
    END
  END cfg_data[215]
  PIN cfg_data[216]
    DIRECTION INPUT ;
    USE SIGNAL ;
    PORT
      LAYER M4 ;
        RECT  0 21.072 0.084 21.096 ;
    END
  END cfg_data[216]
  PIN cfg_data[217]
    DIRECTION INPUT ;
    USE SIGNAL ;
    PORT
      LAYER M4 ;
        RECT  0 21.168 0.084 21.192 ;
    END
  END cfg_data[217]
  PIN cfg_data[218]
    DIRECTION INPUT ;
    USE SIGNAL ;
    PORT
      LAYER M4 ;
        RECT  0 21.264 0.084 21.288 ;
    END
  END cfg_data[218]
  PIN cfg_data[219]
    DIRECTION INPUT ;
    USE SIGNAL ;
    PORT
      LAYER M4 ;
        RECT  0 21.36 0.084 21.384 ;
    END
  END cfg_data[219]
  PIN cfg_data[21]
    DIRECTION INPUT ;
    USE SIGNAL ;
    PORT
      LAYER M4 ;
        RECT  0 55.344 0.084 55.368 ;
    END
  END cfg_data[21]
  PIN cfg_data[220]
    DIRECTION INPUT ;
    USE SIGNAL ;
    PORT
      LAYER M4 ;
        RECT  0 21.456 0.084 21.48 ;
    END
  END cfg_data[220]
  PIN cfg_data[221]
    DIRECTION INPUT ;
    USE SIGNAL ;
    PORT
      LAYER M4 ;
        RECT  0 21.552 0.084 21.576 ;
    END
  END cfg_data[221]
  PIN cfg_data[222]
    DIRECTION INPUT ;
    USE SIGNAL ;
    PORT
      LAYER M4 ;
        RECT  0 21.648 0.084 21.672 ;
    END
  END cfg_data[222]
  PIN cfg_data[223]
    DIRECTION INPUT ;
    USE SIGNAL ;
    PORT
      LAYER M4 ;
        RECT  0 21.744 0.084 21.768 ;
    END
  END cfg_data[223]
  PIN cfg_data[224]
    DIRECTION INPUT ;
    USE SIGNAL ;
    PORT
      LAYER M4 ;
        RECT  0 21.84 0.084 21.864 ;
    END
  END cfg_data[224]
  PIN cfg_data[225]
    DIRECTION INPUT ;
    USE SIGNAL ;
    PORT
      LAYER M4 ;
        RECT  0 21.936 0.084 21.96 ;
    END
  END cfg_data[225]
  PIN cfg_data[226]
    DIRECTION INPUT ;
    USE SIGNAL ;
    PORT
      LAYER M4 ;
        RECT  0 22.032 0.084 22.056 ;
    END
  END cfg_data[226]
  PIN cfg_data[227]
    DIRECTION INPUT ;
    USE SIGNAL ;
    PORT
      LAYER M4 ;
        RECT  0 22.128 0.084 22.152 ;
    END
  END cfg_data[227]
  PIN cfg_data[228]
    DIRECTION INPUT ;
    USE SIGNAL ;
    PORT
      LAYER M4 ;
        RECT  0 22.224 0.084 22.248 ;
    END
  END cfg_data[228]
  PIN cfg_data[229]
    DIRECTION INPUT ;
    USE SIGNAL ;
    PORT
      LAYER M4 ;
        RECT  0 22.32 0.084 22.344 ;
    END
  END cfg_data[229]
  PIN cfg_data[22]
    DIRECTION INPUT ;
    USE SIGNAL ;
    PORT
      LAYER M4 ;
        RECT  0 55.44 0.084 55.464 ;
    END
  END cfg_data[22]
  PIN cfg_data[230]
    DIRECTION INPUT ;
    USE SIGNAL ;
    PORT
      LAYER M4 ;
        RECT  0 22.416 0.084 22.44 ;
    END
  END cfg_data[230]
  PIN cfg_data[231]
    DIRECTION INPUT ;
    USE SIGNAL ;
    PORT
      LAYER M4 ;
        RECT  0 22.512 0.084 22.536 ;
    END
  END cfg_data[231]
  PIN cfg_data[232]
    DIRECTION INPUT ;
    USE SIGNAL ;
    PORT
      LAYER M4 ;
        RECT  0 22.608 0.084 22.632 ;
    END
  END cfg_data[232]
  PIN cfg_data[233]
    DIRECTION INPUT ;
    USE SIGNAL ;
    PORT
      LAYER M4 ;
        RECT  0 22.704 0.084 22.728 ;
    END
  END cfg_data[233]
  PIN cfg_data[234]
    DIRECTION INPUT ;
    USE SIGNAL ;
    PORT
      LAYER M4 ;
        RECT  0 22.8 0.084 22.824 ;
    END
  END cfg_data[234]
  PIN cfg_data[235]
    DIRECTION INPUT ;
    USE SIGNAL ;
    PORT
      LAYER M4 ;
        RECT  0 22.896 0.084 22.92 ;
    END
  END cfg_data[235]
  PIN cfg_data[236]
    DIRECTION INPUT ;
    USE SIGNAL ;
    PORT
      LAYER M4 ;
        RECT  0 22.992 0.084 23.016 ;
    END
  END cfg_data[236]
  PIN cfg_data[237]
    DIRECTION INPUT ;
    USE SIGNAL ;
    PORT
      LAYER M4 ;
        RECT  0 23.088 0.084 23.112 ;
    END
  END cfg_data[237]
  PIN cfg_data[238]
    DIRECTION INPUT ;
    USE SIGNAL ;
    PORT
      LAYER M4 ;
        RECT  0 23.184 0.084 23.208 ;
    END
  END cfg_data[238]
  PIN cfg_data[239]
    DIRECTION INPUT ;
    USE SIGNAL ;
    PORT
      LAYER M4 ;
        RECT  0 23.28 0.084 23.304 ;
    END
  END cfg_data[239]
  PIN cfg_data[23]
    DIRECTION INPUT ;
    USE SIGNAL ;
    PORT
      LAYER M4 ;
        RECT  0 55.536 0.084 55.56 ;
    END
  END cfg_data[23]
  PIN cfg_data[240]
    DIRECTION INPUT ;
    USE SIGNAL ;
    PORT
      LAYER M4 ;
        RECT  0 23.376 0.084 23.4 ;
    END
  END cfg_data[240]
  PIN cfg_data[241]
    DIRECTION INPUT ;
    USE SIGNAL ;
    PORT
      LAYER M4 ;
        RECT  0 23.472 0.084 23.496 ;
    END
  END cfg_data[241]
  PIN cfg_data[242]
    DIRECTION INPUT ;
    USE SIGNAL ;
    PORT
      LAYER M4 ;
        RECT  0 23.568 0.084 23.592 ;
    END
  END cfg_data[242]
  PIN cfg_data[243]
    DIRECTION INPUT ;
    USE SIGNAL ;
    PORT
      LAYER M4 ;
        RECT  0 23.664 0.084 23.688 ;
    END
  END cfg_data[243]
  PIN cfg_data[244]
    DIRECTION INPUT ;
    USE SIGNAL ;
    PORT
      LAYER M4 ;
        RECT  0 16.848 0.084 16.872 ;
    END
  END cfg_data[244]
  PIN cfg_data[245]
    DIRECTION INPUT ;
    USE SIGNAL ;
    PORT
      LAYER M4 ;
        RECT  0 16.944 0.084 16.968 ;
    END
  END cfg_data[245]
  PIN cfg_data[246]
    DIRECTION INPUT ;
    USE SIGNAL ;
    PORT
      LAYER M4 ;
        RECT  0 17.04 0.084 17.064 ;
    END
  END cfg_data[246]
  PIN cfg_data[247]
    DIRECTION INPUT ;
    USE SIGNAL ;
    PORT
      LAYER M4 ;
        RECT  0 17.136 0.084 17.16 ;
    END
  END cfg_data[247]
  PIN cfg_data[248]
    DIRECTION INPUT ;
    USE SIGNAL ;
    PORT
      LAYER M4 ;
        RECT  0 17.232 0.084 17.256 ;
    END
  END cfg_data[248]
  PIN cfg_data[249]
    DIRECTION INPUT ;
    USE SIGNAL ;
    PORT
      LAYER M4 ;
        RECT  0 17.328 0.084 17.352 ;
    END
  END cfg_data[249]
  PIN cfg_data[24]
    DIRECTION INPUT ;
    USE SIGNAL ;
    PORT
      LAYER M4 ;
        RECT  0 55.632 0.084 55.656 ;
    END
  END cfg_data[24]
  PIN cfg_data[250]
    DIRECTION INPUT ;
    USE SIGNAL ;
    PORT
      LAYER M4 ;
        RECT  0 17.424 0.084 17.448 ;
    END
  END cfg_data[250]
  PIN cfg_data[251]
    DIRECTION INPUT ;
    USE SIGNAL ;
    PORT
      LAYER M4 ;
        RECT  0 17.52 0.084 17.544 ;
    END
  END cfg_data[251]
  PIN cfg_data[252]
    DIRECTION INPUT ;
    USE SIGNAL ;
    PORT
      LAYER M4 ;
        RECT  0 17.616 0.084 17.64 ;
    END
  END cfg_data[252]
  PIN cfg_data[253]
    DIRECTION INPUT ;
    USE SIGNAL ;
    PORT
      LAYER M4 ;
        RECT  0 17.712 0.084 17.736 ;
    END
  END cfg_data[253]
  PIN cfg_data[254]
    DIRECTION INPUT ;
    USE SIGNAL ;
    PORT
      LAYER M4 ;
        RECT  0 17.808 0.084 17.832 ;
    END
  END cfg_data[254]
  PIN cfg_data[255]
    DIRECTION INPUT ;
    USE SIGNAL ;
    PORT
      LAYER M4 ;
        RECT  0 17.904 0.084 17.928 ;
    END
  END cfg_data[255]
  PIN cfg_data[25]
    DIRECTION INPUT ;
    USE SIGNAL ;
    PORT
      LAYER M4 ;
        RECT  0 55.728 0.084 55.752 ;
    END
  END cfg_data[25]
  PIN cfg_data[26]
    DIRECTION INPUT ;
    USE SIGNAL ;
    PORT
      LAYER M4 ;
        RECT  0 55.824 0.084 55.848 ;
    END
  END cfg_data[26]
  PIN cfg_data[27]
    DIRECTION INPUT ;
    USE SIGNAL ;
    PORT
      LAYER M4 ;
        RECT  0 55.92 0.084 55.944 ;
    END
  END cfg_data[27]
  PIN cfg_data[28]
    DIRECTION INPUT ;
    USE SIGNAL ;
    PORT
      LAYER M4 ;
        RECT  0 56.016 0.084 56.04 ;
    END
  END cfg_data[28]
  PIN cfg_data[29]
    DIRECTION INPUT ;
    USE SIGNAL ;
    PORT
      LAYER M4 ;
        RECT  0 56.112 0.084 56.136 ;
    END
  END cfg_data[29]
  PIN cfg_data[2]
    DIRECTION INPUT ;
    USE SIGNAL ;
    PORT
      LAYER M4 ;
        RECT  0 47.376 0.084 47.4 ;
    END
  END cfg_data[2]
  PIN cfg_data[30]
    DIRECTION INPUT ;
    USE SIGNAL ;
    PORT
      LAYER M4 ;
        RECT  0 56.208 0.084 56.232 ;
    END
  END cfg_data[30]
  PIN cfg_data[31]
    DIRECTION INPUT ;
    USE SIGNAL ;
    PORT
      LAYER M4 ;
        RECT  0 56.304 0.084 56.328 ;
    END
  END cfg_data[31]
  PIN cfg_data[32]
    DIRECTION INPUT ;
    USE SIGNAL ;
    PORT
      LAYER M4 ;
        RECT  0 56.4 0.084 56.424 ;
    END
  END cfg_data[32]
  PIN cfg_data[33]
    DIRECTION INPUT ;
    USE SIGNAL ;
    PORT
      LAYER M4 ;
        RECT  0 56.496 0.084 56.52 ;
    END
  END cfg_data[33]
  PIN cfg_data[34]
    DIRECTION INPUT ;
    USE SIGNAL ;
    PORT
      LAYER M4 ;
        RECT  0 56.592 0.084 56.616 ;
    END
  END cfg_data[34]
  PIN cfg_data[35]
    DIRECTION INPUT ;
    USE SIGNAL ;
    PORT
      LAYER M4 ;
        RECT  0 56.688 0.084 56.712 ;
    END
  END cfg_data[35]
  PIN cfg_data[36]
    DIRECTION INPUT ;
    USE SIGNAL ;
    PORT
      LAYER M4 ;
        RECT  0 56.784 0.084 56.808 ;
    END
  END cfg_data[36]
  PIN cfg_data[37]
    DIRECTION INPUT ;
    USE SIGNAL ;
    PORT
      LAYER M4 ;
        RECT  0 56.88 0.084 56.904 ;
    END
  END cfg_data[37]
  PIN cfg_data[38]
    DIRECTION INPUT ;
    USE SIGNAL ;
    PORT
      LAYER M4 ;
        RECT  0 56.976 0.084 57 ;
    END
  END cfg_data[38]
  PIN cfg_data[39]
    DIRECTION INPUT ;
    USE SIGNAL ;
    PORT
      LAYER M4 ;
        RECT  0 57.072 0.084 57.096 ;
    END
  END cfg_data[39]
  PIN cfg_data[3]
    DIRECTION INPUT ;
    USE SIGNAL ;
    PORT
      LAYER M4 ;
        RECT  0 47.472 0.084 47.496 ;
    END
  END cfg_data[3]
  PIN cfg_data[40]
    DIRECTION INPUT ;
    USE SIGNAL ;
    PORT
      LAYER M4 ;
        RECT  0 57.168 0.084 57.192 ;
    END
  END cfg_data[40]
  PIN cfg_data[41]
    DIRECTION INPUT ;
    USE SIGNAL ;
    PORT
      LAYER M4 ;
        RECT  0 57.264 0.084 57.288 ;
    END
  END cfg_data[41]
  PIN cfg_data[42]
    DIRECTION INPUT ;
    USE SIGNAL ;
    PORT
      LAYER M4 ;
        RECT  0 57.36 0.084 57.384 ;
    END
  END cfg_data[42]
  PIN cfg_data[43]
    DIRECTION INPUT ;
    USE SIGNAL ;
    PORT
      LAYER M4 ;
        RECT  0 57.456 0.084 57.48 ;
    END
  END cfg_data[43]
  PIN cfg_data[44]
    DIRECTION INPUT ;
    USE SIGNAL ;
    PORT
      LAYER M4 ;
        RECT  0 57.552 0.084 57.576 ;
    END
  END cfg_data[44]
  PIN cfg_data[45]
    DIRECTION INPUT ;
    USE SIGNAL ;
    PORT
      LAYER M4 ;
        RECT  0 57.648 0.084 57.672 ;
    END
  END cfg_data[45]
  PIN cfg_data[46]
    DIRECTION INPUT ;
    USE SIGNAL ;
    PORT
      LAYER M4 ;
        RECT  0 57.744 0.084 57.768 ;
    END
  END cfg_data[46]
  PIN cfg_data[47]
    DIRECTION INPUT ;
    USE SIGNAL ;
    PORT
      LAYER M4 ;
        RECT  0 57.84 0.084 57.864 ;
    END
  END cfg_data[47]
  PIN cfg_data[48]
    DIRECTION INPUT ;
    USE SIGNAL ;
    PORT
      LAYER M4 ;
        RECT  0 57.936 0.084 57.96 ;
    END
  END cfg_data[48]
  PIN cfg_data[49]
    DIRECTION INPUT ;
    USE SIGNAL ;
    PORT
      LAYER M4 ;
        RECT  0 58.032 0.084 58.056 ;
    END
  END cfg_data[49]
  PIN cfg_data[4]
    DIRECTION INPUT ;
    USE SIGNAL ;
    PORT
      LAYER M4 ;
        RECT  0 47.568 0.084 47.592 ;
    END
  END cfg_data[4]
  PIN cfg_data[50]
    DIRECTION INPUT ;
    USE SIGNAL ;
    PORT
      LAYER M4 ;
        RECT  0 58.128 0.084 58.152 ;
    END
  END cfg_data[50]
  PIN cfg_data[51]
    DIRECTION INPUT ;
    USE SIGNAL ;
    PORT
      LAYER M4 ;
        RECT  0 58.224 0.084 58.248 ;
    END
  END cfg_data[51]
  PIN cfg_data[52]
    DIRECTION INPUT ;
    USE SIGNAL ;
    PORT
      LAYER M4 ;
        RECT  0 59.088 0.084 59.112 ;
    END
  END cfg_data[52]
  PIN cfg_data[53]
    DIRECTION INPUT ;
    USE SIGNAL ;
    PORT
      LAYER M4 ;
        RECT  0 59.184 0.084 59.208 ;
    END
  END cfg_data[53]
  PIN cfg_data[54]
    DIRECTION INPUT ;
    USE SIGNAL ;
    PORT
      LAYER M4 ;
        RECT  0 59.28 0.084 59.304 ;
    END
  END cfg_data[54]
  PIN cfg_data[55]
    DIRECTION INPUT ;
    USE SIGNAL ;
    PORT
      LAYER M4 ;
        RECT  0 59.376 0.084 59.4 ;
    END
  END cfg_data[55]
  PIN cfg_data[56]
    DIRECTION INPUT ;
    USE SIGNAL ;
    PORT
      LAYER M4 ;
        RECT  0 59.472 0.084 59.496 ;
    END
  END cfg_data[56]
  PIN cfg_data[57]
    DIRECTION INPUT ;
    USE SIGNAL ;
    PORT
      LAYER M4 ;
        RECT  0 59.568 0.084 59.592 ;
    END
  END cfg_data[57]
  PIN cfg_data[58]
    DIRECTION INPUT ;
    USE SIGNAL ;
    PORT
      LAYER M4 ;
        RECT  0 59.664 0.084 59.688 ;
    END
  END cfg_data[58]
  PIN cfg_data[59]
    DIRECTION INPUT ;
    USE SIGNAL ;
    PORT
      LAYER M4 ;
        RECT  0 59.76 0.084 59.784 ;
    END
  END cfg_data[59]
  PIN cfg_data[5]
    DIRECTION INPUT ;
    USE SIGNAL ;
    PORT
      LAYER M4 ;
        RECT  0 47.664 0.084 47.688 ;
    END
  END cfg_data[5]
  PIN cfg_data[60]
    DIRECTION INPUT ;
    USE SIGNAL ;
    PORT
      LAYER M4 ;
        RECT  0 59.856 0.084 59.88 ;
    END
  END cfg_data[60]
  PIN cfg_data[61]
    DIRECTION INPUT ;
    USE SIGNAL ;
    PORT
      LAYER M4 ;
        RECT  0 59.952 0.084 59.976 ;
    END
  END cfg_data[61]
  PIN cfg_data[62]
    DIRECTION INPUT ;
    USE SIGNAL ;
    PORT
      LAYER M4 ;
        RECT  0 60.048 0.084 60.072 ;
    END
  END cfg_data[62]
  PIN cfg_data[63]
    DIRECTION INPUT ;
    USE SIGNAL ;
    PORT
      LAYER M4 ;
        RECT  0 60.144 0.084 60.168 ;
    END
  END cfg_data[63]
  PIN cfg_data[64]
    DIRECTION INPUT ;
    USE SIGNAL ;
    PORT
      LAYER M4 ;
        RECT  0 60.24 0.084 60.264 ;
    END
  END cfg_data[64]
  PIN cfg_data[65]
    DIRECTION INPUT ;
    USE SIGNAL ;
    PORT
      LAYER M4 ;
        RECT  0 60.336 0.084 60.36 ;
    END
  END cfg_data[65]
  PIN cfg_data[66]
    DIRECTION INPUT ;
    USE SIGNAL ;
    PORT
      LAYER M4 ;
        RECT  0 60.432 0.084 60.456 ;
    END
  END cfg_data[66]
  PIN cfg_data[67]
    DIRECTION INPUT ;
    USE SIGNAL ;
    PORT
      LAYER M4 ;
        RECT  0 60.528 0.084 60.552 ;
    END
  END cfg_data[67]
  PIN cfg_data[68]
    DIRECTION INPUT ;
    USE SIGNAL ;
    PORT
      LAYER M4 ;
        RECT  0 60.624 0.084 60.648 ;
    END
  END cfg_data[68]
  PIN cfg_data[69]
    DIRECTION INPUT ;
    USE SIGNAL ;
    PORT
      LAYER M4 ;
        RECT  0 60.72 0.084 60.744 ;
    END
  END cfg_data[69]
  PIN cfg_data[6]
    DIRECTION INPUT ;
    USE SIGNAL ;
    PORT
      LAYER M4 ;
        RECT  0 47.76 0.084 47.784 ;
    END
  END cfg_data[6]
  PIN cfg_data[70]
    DIRECTION INPUT ;
    USE SIGNAL ;
    PORT
      LAYER M4 ;
        RECT  0 60.816 0.084 60.84 ;
    END
  END cfg_data[70]
  PIN cfg_data[71]
    DIRECTION INPUT ;
    USE SIGNAL ;
    PORT
      LAYER M4 ;
        RECT  0 60.912 0.084 60.936 ;
    END
  END cfg_data[71]
  PIN cfg_data[72]
    DIRECTION INPUT ;
    USE SIGNAL ;
    PORT
      LAYER M4 ;
        RECT  0 61.008 0.084 61.032 ;
    END
  END cfg_data[72]
  PIN cfg_data[73]
    DIRECTION INPUT ;
    USE SIGNAL ;
    PORT
      LAYER M4 ;
        RECT  0 61.104 0.084 61.128 ;
    END
  END cfg_data[73]
  PIN cfg_data[74]
    DIRECTION INPUT ;
    USE SIGNAL ;
    PORT
      LAYER M4 ;
        RECT  0 61.2 0.084 61.224 ;
    END
  END cfg_data[74]
  PIN cfg_data[75]
    DIRECTION INPUT ;
    USE SIGNAL ;
    PORT
      LAYER M4 ;
        RECT  0 61.296 0.084 61.32 ;
    END
  END cfg_data[75]
  PIN cfg_data[76]
    DIRECTION INPUT ;
    USE SIGNAL ;
    PORT
      LAYER M4 ;
        RECT  0 61.392 0.084 61.416 ;
    END
  END cfg_data[76]
  PIN cfg_data[77]
    DIRECTION INPUT ;
    USE SIGNAL ;
    PORT
      LAYER M4 ;
        RECT  0 61.488 0.084 61.512 ;
    END
  END cfg_data[77]
  PIN cfg_data[78]
    DIRECTION INPUT ;
    USE SIGNAL ;
    PORT
      LAYER M4 ;
        RECT  0 61.584 0.084 61.608 ;
    END
  END cfg_data[78]
  PIN cfg_data[79]
    DIRECTION INPUT ;
    USE SIGNAL ;
    PORT
      LAYER M4 ;
        RECT  0 61.68 0.084 61.704 ;
    END
  END cfg_data[79]
  PIN cfg_data[7]
    DIRECTION INPUT ;
    USE SIGNAL ;
    PORT
      LAYER M4 ;
        RECT  0 47.856 0.084 47.88 ;
    END
  END cfg_data[7]
  PIN cfg_data[80]
    DIRECTION INPUT ;
    USE SIGNAL ;
    PORT
      LAYER M4 ;
        RECT  0 61.776 0.084 61.8 ;
    END
  END cfg_data[80]
  PIN cfg_data[81]
    DIRECTION INPUT ;
    USE SIGNAL ;
    PORT
      LAYER M4 ;
        RECT  0 61.872 0.084 61.896 ;
    END
  END cfg_data[81]
  PIN cfg_data[82]
    DIRECTION INPUT ;
    USE SIGNAL ;
    PORT
      LAYER M4 ;
        RECT  0 61.968 0.084 61.992 ;
    END
  END cfg_data[82]
  PIN cfg_data[83]
    DIRECTION INPUT ;
    USE SIGNAL ;
    PORT
      LAYER M4 ;
        RECT  0 62.064 0.084 62.088 ;
    END
  END cfg_data[83]
  PIN cfg_data[84]
    DIRECTION INPUT ;
    USE SIGNAL ;
    PORT
      LAYER M4 ;
        RECT  0 62.16 0.084 62.184 ;
    END
  END cfg_data[84]
  PIN cfg_data[85]
    DIRECTION INPUT ;
    USE SIGNAL ;
    PORT
      LAYER M4 ;
        RECT  0 62.256 0.084 62.28 ;
    END
  END cfg_data[85]
  PIN cfg_data[86]
    DIRECTION INPUT ;
    USE SIGNAL ;
    PORT
      LAYER M4 ;
        RECT  0 62.352 0.084 62.376 ;
    END
  END cfg_data[86]
  PIN cfg_data[87]
    DIRECTION INPUT ;
    USE SIGNAL ;
    PORT
      LAYER M4 ;
        RECT  0 62.448 0.084 62.472 ;
    END
  END cfg_data[87]
  PIN cfg_data[88]
    DIRECTION INPUT ;
    USE SIGNAL ;
    PORT
      LAYER M4 ;
        RECT  0 62.544 0.084 62.568 ;
    END
  END cfg_data[88]
  PIN cfg_data[89]
    DIRECTION INPUT ;
    USE SIGNAL ;
    PORT
      LAYER M4 ;
        RECT  0 62.64 0.084 62.664 ;
    END
  END cfg_data[89]
  PIN cfg_data[8]
    DIRECTION INPUT ;
    USE SIGNAL ;
    PORT
      LAYER M4 ;
        RECT  0 47.952 0.084 47.976 ;
    END
  END cfg_data[8]
  PIN cfg_data[90]
    DIRECTION INPUT ;
    USE SIGNAL ;
    PORT
      LAYER M4 ;
        RECT  0 62.736 0.084 62.76 ;
    END
  END cfg_data[90]
  PIN cfg_data[91]
    DIRECTION INPUT ;
    USE SIGNAL ;
    PORT
      LAYER M4 ;
        RECT  0 62.832 0.084 62.856 ;
    END
  END cfg_data[91]
  PIN cfg_data[92]
    DIRECTION INPUT ;
    USE SIGNAL ;
    PORT
      LAYER M4 ;
        RECT  0 62.928 0.084 62.952 ;
    END
  END cfg_data[92]
  PIN cfg_data[93]
    DIRECTION INPUT ;
    USE SIGNAL ;
    PORT
      LAYER M4 ;
        RECT  0 63.024 0.084 63.048 ;
    END
  END cfg_data[93]
  PIN cfg_data[94]
    DIRECTION INPUT ;
    USE SIGNAL ;
    PORT
      LAYER M4 ;
        RECT  0 63.12 0.084 63.144 ;
    END
  END cfg_data[94]
  PIN cfg_data[95]
    DIRECTION INPUT ;
    USE SIGNAL ;
    PORT
      LAYER M4 ;
        RECT  0 63.216 0.084 63.24 ;
    END
  END cfg_data[95]
  PIN cfg_data[96]
    DIRECTION INPUT ;
    USE SIGNAL ;
    PORT
      LAYER M4 ;
        RECT  0 63.312 0.084 63.336 ;
    END
  END cfg_data[96]
  PIN cfg_data[97]
    DIRECTION INPUT ;
    USE SIGNAL ;
    PORT
      LAYER M4 ;
        RECT  0 63.408 0.084 63.432 ;
    END
  END cfg_data[97]
  PIN cfg_data[98]
    DIRECTION INPUT ;
    USE SIGNAL ;
    PORT
      LAYER M4 ;
        RECT  0 63.504 0.084 63.528 ;
    END
  END cfg_data[98]
  PIN cfg_data[99]
    DIRECTION INPUT ;
    USE SIGNAL ;
    PORT
      LAYER M4 ;
        RECT  0 63.6 0.084 63.624 ;
    END
  END cfg_data[99]
  PIN cfg_data[9]
    DIRECTION INPUT ;
    USE SIGNAL ;
    PORT
      LAYER M4 ;
        RECT  0 48.048 0.084 48.072 ;
    END
  END cfg_data[9]
  PIN cfg_target[0]
    DIRECTION INPUT ;
    USE SIGNAL ;
    PORT
      LAYER M4 ;
        RECT  0 18 0.084 18.024 ;
    END
  END cfg_target[0]
  PIN cfg_target[1]
    DIRECTION INPUT ;
    USE SIGNAL ;
    PORT
      LAYER M4 ;
        RECT  0 18.096 0.084 18.12 ;
    END
  END cfg_target[1]
  PIN cfg_target[2]
    DIRECTION INPUT ;
    USE SIGNAL ;
    PORT
      LAYER M4 ;
        RECT  0 18.192 0.084 18.216 ;
    END
  END cfg_target[2]
  PIN cfg_target[3]
    DIRECTION INPUT ;
    USE SIGNAL ;
    PORT
      LAYER M4 ;
        RECT  0 18.288 0.084 18.312 ;
    END
  END cfg_target[3]
  PIN cfg_target[4]
    DIRECTION INPUT ;
    USE SIGNAL ;
    PORT
      LAYER M4 ;
        RECT  0 18.384 0.084 18.408 ;
    END
  END cfg_target[4]
  PIN cfg_target[5]
    DIRECTION INPUT ;
    USE SIGNAL ;
    PORT
      LAYER M4 ;
        RECT  0 18.48 0.084 18.504 ;
    END
  END cfg_target[5]
  PIN cfg_target[6]
    DIRECTION INPUT ;
    USE SIGNAL ;
    PORT
      LAYER M4 ;
        RECT  0 18.576 0.084 18.6 ;
    END
  END cfg_target[6]
  PIN cfg_target[7]
    DIRECTION INPUT ;
    USE SIGNAL ;
    PORT
      LAYER M4 ;
        RECT  0 18.672 0.084 18.696 ;
    END
  END cfg_target[7]
  PIN cfg_v
    DIRECTION INPUT ;
    USE SIGNAL ;
    PORT
      LAYER M4 ;
        RECT  0 18.768 0.084 18.792 ;
    END
  END cfg_v
  PIN client_seq[0]
    DIRECTION OUTPUT ;
    USE SIGNAL ;
    PORT
      LAYER M4 ;
        RECT  241.836 22.992 241.92 23.016 ;
    END
  END client_seq[0]
  PIN client_seq[1]
    DIRECTION OUTPUT ;
    USE SIGNAL ;
    PORT
      LAYER M4 ;
        RECT  241.836 23.088 241.92 23.112 ;
    END
  END client_seq[1]
  PIN client_seq[2]
    DIRECTION OUTPUT ;
    USE SIGNAL ;
    PORT
      LAYER M4 ;
        RECT  241.836 23.184 241.92 23.208 ;
    END
  END client_seq[2]
  PIN client_seq[3]
    DIRECTION OUTPUT ;
    USE SIGNAL ;
    PORT
      LAYER M4 ;
        RECT  241.836 23.28 241.92 23.304 ;
    END
  END client_seq[3]
  PIN client_seq[4]
    DIRECTION OUTPUT ;
    USE SIGNAL ;
    PORT
      LAYER M4 ;
        RECT  241.836 23.376 241.92 23.4 ;
    END
  END client_seq[4]
  PIN client_seq[5]
    DIRECTION OUTPUT ;
    USE SIGNAL ;
    PORT
      LAYER M4 ;
        RECT  241.836 23.472 241.92 23.496 ;
    END
  END client_seq[5]
  PIN client_seq[6]
    DIRECTION OUTPUT ;
    USE SIGNAL ;
    PORT
      LAYER M4 ;
        RECT  241.836 23.568 241.92 23.592 ;
    END
  END client_seq[6]
  PIN client_seq[7]
    DIRECTION OUTPUT ;
    USE SIGNAL ;
    PORT
      LAYER M4 ;
        RECT  241.836 23.664 241.92 23.688 ;
    END
  END client_seq[7]
  PIN client_seq[8]
    DIRECTION OUTPUT ;
    USE SIGNAL ;
    PORT
      LAYER M4 ;
        RECT  241.836 23.76 241.92 23.784 ;
    END
  END client_seq[8]
  PIN client_seq[9]
    DIRECTION OUTPUT ;
    USE SIGNAL ;
    PORT
      LAYER M4 ;
        RECT  241.836 23.856 241.92 23.88 ;
    END
  END client_seq[9]
  PIN clk
    DIRECTION INPUT ;
    USE SIGNAL ;
    PORT
      LAYER M5 ;
        RECT  13.2 0 13.224 0.084 ;
    END
  END clk
  PIN clk_cap
    DIRECTION INPUT ;
    USE SIGNAL ;
    PORT
      LAYER M4 ;
        RECT  0 18.864 0.084 18.888 ;
    END
  END clk_cap
  PIN clk_mem
    DIRECTION INPUT ;
    USE SIGNAL ;
    PORT
      LAYER M4 ;
        RECT  0 18.96 0.084 18.984 ;
    END
  END clk_mem
  PIN clk_tgt
    DIRECTION INPUT ;
    USE SIGNAL ;
    PORT
      LAYER M5 ;
        RECT  13.296 0 13.32 0.084 ;
    END
  END clk_tgt
  PIN desc_base[0]
    DIRECTION INPUT ;
    USE SIGNAL ;
    PORT
      LAYER M4 ;
        RECT  0 19.056 0.084 19.08 ;
    END
  END desc_base[0]
  PIN desc_base[10]
    DIRECTION INPUT ;
    USE SIGNAL ;
    PORT
      LAYER M4 ;
        RECT  0 13.872 0.084 13.896 ;
    END
  END desc_base[10]
  PIN desc_base[11]
    DIRECTION INPUT ;
    USE SIGNAL ;
    PORT
      LAYER M4 ;
        RECT  0 13.968 0.084 13.992 ;
    END
  END desc_base[11]
  PIN desc_base[1]
    DIRECTION INPUT ;
    USE SIGNAL ;
    PORT
      LAYER M4 ;
        RECT  0 19.152 0.084 19.176 ;
    END
  END desc_base[1]
  PIN desc_base[2]
    DIRECTION INPUT ;
    USE SIGNAL ;
    PORT
      LAYER M4 ;
        RECT  0 19.248 0.084 19.272 ;
    END
  END desc_base[2]
  PIN desc_base[3]
    DIRECTION INPUT ;
    USE SIGNAL ;
    PORT
      LAYER M4 ;
        RECT  0 19.344 0.084 19.368 ;
    END
  END desc_base[3]
  PIN desc_base[4]
    DIRECTION INPUT ;
    USE SIGNAL ;
    PORT
      LAYER M4 ;
        RECT  0 19.44 0.084 19.464 ;
    END
  END desc_base[4]
  PIN desc_base[5]
    DIRECTION INPUT ;
    USE SIGNAL ;
    PORT
      LAYER M4 ;
        RECT  0 19.536 0.084 19.56 ;
    END
  END desc_base[5]
  PIN desc_base[6]
    DIRECTION INPUT ;
    USE SIGNAL ;
    PORT
      LAYER M4 ;
        RECT  0 19.632 0.084 19.656 ;
    END
  END desc_base[6]
  PIN desc_base[7]
    DIRECTION INPUT ;
    USE SIGNAL ;
    PORT
      LAYER M4 ;
        RECT  0 19.728 0.084 19.752 ;
    END
  END desc_base[7]
  PIN desc_base[8]
    DIRECTION INPUT ;
    USE SIGNAL ;
    PORT
      LAYER M4 ;
        RECT  0 19.824 0.084 19.848 ;
    END
  END desc_base[8]
  PIN desc_base[9]
    DIRECTION INPUT ;
    USE SIGNAL ;
    PORT
      LAYER M4 ;
        RECT  0 13.776 0.084 13.8 ;
    END
  END desc_base[9]
  PIN desc_limit[0]
    DIRECTION INPUT ;
    USE SIGNAL ;
    PORT
      LAYER M4 ;
        RECT  0 14.064 0.084 14.088 ;
    END
  END desc_limit[0]
  PIN desc_limit[10]
    DIRECTION INPUT ;
    USE SIGNAL ;
    PORT
      LAYER M4 ;
        RECT  0 15.024 0.084 15.048 ;
    END
  END desc_limit[10]
  PIN desc_limit[11]
    DIRECTION INPUT ;
    USE SIGNAL ;
    PORT
      LAYER M4 ;
        RECT  0 15.12 0.084 15.144 ;
    END
  END desc_limit[11]
  PIN desc_limit[12]
    DIRECTION INPUT ;
    USE SIGNAL ;
    PORT
      LAYER M4 ;
        RECT  0 15.216 0.084 15.24 ;
    END
  END desc_limit[12]
  PIN desc_limit[1]
    DIRECTION INPUT ;
    USE SIGNAL ;
    PORT
      LAYER M4 ;
        RECT  0 14.16 0.084 14.184 ;
    END
  END desc_limit[1]
  PIN desc_limit[2]
    DIRECTION INPUT ;
    USE SIGNAL ;
    PORT
      LAYER M4 ;
        RECT  0 14.256 0.084 14.28 ;
    END
  END desc_limit[2]
  PIN desc_limit[3]
    DIRECTION INPUT ;
    USE SIGNAL ;
    PORT
      LAYER M4 ;
        RECT  0 14.352 0.084 14.376 ;
    END
  END desc_limit[3]
  PIN desc_limit[4]
    DIRECTION INPUT ;
    USE SIGNAL ;
    PORT
      LAYER M4 ;
        RECT  0 14.448 0.084 14.472 ;
    END
  END desc_limit[4]
  PIN desc_limit[5]
    DIRECTION INPUT ;
    USE SIGNAL ;
    PORT
      LAYER M4 ;
        RECT  0 14.544 0.084 14.568 ;
    END
  END desc_limit[5]
  PIN desc_limit[6]
    DIRECTION INPUT ;
    USE SIGNAL ;
    PORT
      LAYER M4 ;
        RECT  0 14.64 0.084 14.664 ;
    END
  END desc_limit[6]
  PIN desc_limit[7]
    DIRECTION INPUT ;
    USE SIGNAL ;
    PORT
      LAYER M4 ;
        RECT  0 14.736 0.084 14.76 ;
    END
  END desc_limit[7]
  PIN desc_limit[8]
    DIRECTION INPUT ;
    USE SIGNAL ;
    PORT
      LAYER M4 ;
        RECT  0 14.832 0.084 14.856 ;
    END
  END desc_limit[8]
  PIN desc_limit[9]
    DIRECTION INPUT ;
    USE SIGNAL ;
    PORT
      LAYER M4 ;
        RECT  0 14.928 0.084 14.952 ;
    END
  END desc_limit[9]
  PIN desc_loops[0]
    DIRECTION INPUT ;
    USE SIGNAL ;
    PORT
      LAYER M4 ;
        RECT  0 15.312 0.084 15.336 ;
    END
  END desc_loops[0]
  PIN desc_loops[10]
    DIRECTION INPUT ;
    USE SIGNAL ;
    PORT
      LAYER M4 ;
        RECT  0 16.272 0.084 16.296 ;
    END
  END desc_loops[10]
  PIN desc_loops[11]
    DIRECTION INPUT ;
    USE SIGNAL ;
    PORT
      LAYER M4 ;
        RECT  0 16.368 0.084 16.392 ;
    END
  END desc_loops[11]
  PIN desc_loops[12]
    DIRECTION INPUT ;
    USE SIGNAL ;
    PORT
      LAYER M4 ;
        RECT  0 16.464 0.084 16.488 ;
    END
  END desc_loops[12]
  PIN desc_loops[13]
    DIRECTION INPUT ;
    USE SIGNAL ;
    PORT
      LAYER M4 ;
        RECT  0 16.56 0.084 16.584 ;
    END
  END desc_loops[13]
  PIN desc_loops[14]
    DIRECTION INPUT ;
    USE SIGNAL ;
    PORT
      LAYER M4 ;
        RECT  0 16.656 0.084 16.68 ;
    END
  END desc_loops[14]
  PIN desc_loops[15]
    DIRECTION INPUT ;
    USE SIGNAL ;
    PORT
      LAYER M4 ;
        RECT  0 16.752 0.084 16.776 ;
    END
  END desc_loops[15]
  PIN desc_loops[1]
    DIRECTION INPUT ;
    USE SIGNAL ;
    PORT
      LAYER M4 ;
        RECT  0 15.408 0.084 15.432 ;
    END
  END desc_loops[1]
  PIN desc_loops[2]
    DIRECTION INPUT ;
    USE SIGNAL ;
    PORT
      LAYER M4 ;
        RECT  0 15.504 0.084 15.528 ;
    END
  END desc_loops[2]
  PIN desc_loops[3]
    DIRECTION INPUT ;
    USE SIGNAL ;
    PORT
      LAYER M4 ;
        RECT  0 15.6 0.084 15.624 ;
    END
  END desc_loops[3]
  PIN desc_loops[4]
    DIRECTION INPUT ;
    USE SIGNAL ;
    PORT
      LAYER M4 ;
        RECT  0 15.696 0.084 15.72 ;
    END
  END desc_loops[4]
  PIN desc_loops[5]
    DIRECTION INPUT ;
    USE SIGNAL ;
    PORT
      LAYER M4 ;
        RECT  0 15.792 0.084 15.816 ;
    END
  END desc_loops[5]
  PIN desc_loops[6]
    DIRECTION INPUT ;
    USE SIGNAL ;
    PORT
      LAYER M4 ;
        RECT  0 15.888 0.084 15.912 ;
    END
  END desc_loops[6]
  PIN desc_loops[7]
    DIRECTION INPUT ;
    USE SIGNAL ;
    PORT
      LAYER M4 ;
        RECT  0 15.984 0.084 16.008 ;
    END
  END desc_loops[7]
  PIN desc_loops[8]
    DIRECTION INPUT ;
    USE SIGNAL ;
    PORT
      LAYER M4 ;
        RECT  0 16.08 0.084 16.104 ;
    END
  END desc_loops[8]
  PIN desc_loops[9]
    DIRECTION INPUT ;
    USE SIGNAL ;
    PORT
      LAYER M4 ;
        RECT  0 16.176 0.084 16.2 ;
    END
  END desc_loops[9]
  PIN desc_v
    DIRECTION INPUT ;
    USE SIGNAL ;
    PORT
      LAYER M4 ;
        RECT  0 12.72 0.084 12.744 ;
    END
  END desc_v
  PIN done
    DIRECTION OUTPUT ;
    USE SIGNAL ;
    PORT
      LAYER M5 ;
        RECT  13.392 0 13.416 0.084 ;
    END
  END done
  PIN fault
    DIRECTION OUTPUT ;
    USE SIGNAL ;
    PORT
      LAYER M5 ;
        RECT  13.488 0 13.512 0.084 ;
    END
  END fault
  PIN hub_ring_client[0]
    DIRECTION OUTPUT ;
    USE SIGNAL ;
    PORT
      LAYER M4 ;
        RECT  241.836 23.952 241.92 23.976 ;
    END
  END hub_ring_client[0]
  PIN hub_ring_client[1]
    DIRECTION OUTPUT ;
    USE SIGNAL ;
    PORT
      LAYER M4 ;
        RECT  241.836 24.048 241.92 24.072 ;
    END
  END hub_ring_client[1]
  PIN hub_ring_client[2]
    DIRECTION OUTPUT ;
    USE SIGNAL ;
    PORT
      LAYER M4 ;
        RECT  241.836 24.144 241.92 24.168 ;
    END
  END hub_ring_client[2]
  PIN hub_ring_client[3]
    DIRECTION OUTPUT ;
    USE SIGNAL ;
    PORT
      LAYER M4 ;
        RECT  241.836 24.24 241.92 24.264 ;
    END
  END hub_ring_client[3]
  PIN hub_ring_client[4]
    DIRECTION OUTPUT ;
    USE SIGNAL ;
    PORT
      LAYER M4 ;
        RECT  241.836 24.336 241.92 24.36 ;
    END
  END hub_ring_client[4]
  PIN hub_ring_client[5]
    DIRECTION OUTPUT ;
    USE SIGNAL ;
    PORT
      LAYER M4 ;
        RECT  241.836 24.432 241.92 24.456 ;
    END
  END hub_ring_client[5]
  PIN hub_ring_enable[0]
    DIRECTION OUTPUT ;
    USE SIGNAL ;
    PORT
      LAYER M4 ;
        RECT  241.836 24.528 241.92 24.552 ;
    END
  END hub_ring_enable[0]
  PIN hub_ring_enable[1]
    DIRECTION OUTPUT ;
    USE SIGNAL ;
    PORT
      LAYER M4 ;
        RECT  241.836 24.624 241.92 24.648 ;
    END
  END hub_ring_enable[1]
  PIN launch_v
    DIRECTION INPUT ;
    USE SIGNAL ;
    PORT
      LAYER M4 ;
        RECT  0 12.816 0.084 12.84 ;
    END
  END launch_v
  PIN lg_local_read[0]
    DIRECTION OUTPUT ;
    USE SIGNAL ;
    PORT
      LAYER M4 ;
        RECT  241.836 24.72 241.92 24.744 ;
    END
  END lg_local_read[0]
  PIN lg_local_read[10]
    DIRECTION OUTPUT ;
    USE SIGNAL ;
    PORT
      LAYER M4 ;
        RECT  241.836 25.68 241.92 25.704 ;
    END
  END lg_local_read[10]
  PIN lg_local_read[11]
    DIRECTION OUTPUT ;
    USE SIGNAL ;
    PORT
      LAYER M4 ;
        RECT  241.836 25.776 241.92 25.8 ;
    END
  END lg_local_read[11]
  PIN lg_local_read[12]
    DIRECTION OUTPUT ;
    USE SIGNAL ;
    PORT
      LAYER M4 ;
        RECT  241.836 25.872 241.92 25.896 ;
    END
  END lg_local_read[12]
  PIN lg_local_read[13]
    DIRECTION OUTPUT ;
    USE SIGNAL ;
    PORT
      LAYER M4 ;
        RECT  241.836 25.968 241.92 25.992 ;
    END
  END lg_local_read[13]
  PIN lg_local_read[14]
    DIRECTION OUTPUT ;
    USE SIGNAL ;
    PORT
      LAYER M4 ;
        RECT  241.836 42.192 241.92 42.216 ;
    END
  END lg_local_read[14]
  PIN lg_local_read[15]
    DIRECTION OUTPUT ;
    USE SIGNAL ;
    PORT
      LAYER M4 ;
        RECT  241.836 42.288 241.92 42.312 ;
    END
  END lg_local_read[15]
  PIN lg_local_read[16]
    DIRECTION OUTPUT ;
    USE SIGNAL ;
    PORT
      LAYER M4 ;
        RECT  241.836 42.384 241.92 42.408 ;
    END
  END lg_local_read[16]
  PIN lg_local_read[17]
    DIRECTION OUTPUT ;
    USE SIGNAL ;
    PORT
      LAYER M4 ;
        RECT  241.836 42.48 241.92 42.504 ;
    END
  END lg_local_read[17]
  PIN lg_local_read[18]
    DIRECTION OUTPUT ;
    USE SIGNAL ;
    PORT
      LAYER M4 ;
        RECT  241.836 42.576 241.92 42.6 ;
    END
  END lg_local_read[18]
  PIN lg_local_read[19]
    DIRECTION OUTPUT ;
    USE SIGNAL ;
    PORT
      LAYER M4 ;
        RECT  241.836 42.672 241.92 42.696 ;
    END
  END lg_local_read[19]
  PIN lg_local_read[1]
    DIRECTION OUTPUT ;
    USE SIGNAL ;
    PORT
      LAYER M4 ;
        RECT  241.836 24.816 241.92 24.84 ;
    END
  END lg_local_read[1]
  PIN lg_local_read[20]
    DIRECTION OUTPUT ;
    USE SIGNAL ;
    PORT
      LAYER M4 ;
        RECT  241.836 42.768 241.92 42.792 ;
    END
  END lg_local_read[20]
  PIN lg_local_read[21]
    DIRECTION OUTPUT ;
    USE SIGNAL ;
    PORT
      LAYER M4 ;
        RECT  241.836 42.864 241.92 42.888 ;
    END
  END lg_local_read[21]
  PIN lg_local_read[22]
    DIRECTION OUTPUT ;
    USE SIGNAL ;
    PORT
      LAYER M4 ;
        RECT  241.836 42.96 241.92 42.984 ;
    END
  END lg_local_read[22]
  PIN lg_local_read[23]
    DIRECTION OUTPUT ;
    USE SIGNAL ;
    PORT
      LAYER M4 ;
        RECT  241.836 43.056 241.92 43.08 ;
    END
  END lg_local_read[23]
  PIN lg_local_read[2]
    DIRECTION OUTPUT ;
    USE SIGNAL ;
    PORT
      LAYER M4 ;
        RECT  241.836 24.912 241.92 24.936 ;
    END
  END lg_local_read[2]
  PIN lg_local_read[3]
    DIRECTION OUTPUT ;
    USE SIGNAL ;
    PORT
      LAYER M4 ;
        RECT  241.836 25.008 241.92 25.032 ;
    END
  END lg_local_read[3]
  PIN lg_local_read[4]
    DIRECTION OUTPUT ;
    USE SIGNAL ;
    PORT
      LAYER M4 ;
        RECT  241.836 25.104 241.92 25.128 ;
    END
  END lg_local_read[4]
  PIN lg_local_read[5]
    DIRECTION OUTPUT ;
    USE SIGNAL ;
    PORT
      LAYER M4 ;
        RECT  241.836 25.2 241.92 25.224 ;
    END
  END lg_local_read[5]
  PIN lg_local_read[6]
    DIRECTION OUTPUT ;
    USE SIGNAL ;
    PORT
      LAYER M4 ;
        RECT  241.836 25.296 241.92 25.32 ;
    END
  END lg_local_read[6]
  PIN lg_local_read[7]
    DIRECTION OUTPUT ;
    USE SIGNAL ;
    PORT
      LAYER M4 ;
        RECT  241.836 25.392 241.92 25.416 ;
    END
  END lg_local_read[7]
  PIN lg_local_read[8]
    DIRECTION OUTPUT ;
    USE SIGNAL ;
    PORT
      LAYER M4 ;
        RECT  241.836 25.488 241.92 25.512 ;
    END
  END lg_local_read[8]
  PIN lg_local_read[9]
    DIRECTION OUTPUT ;
    USE SIGNAL ;
    PORT
      LAYER M4 ;
        RECT  241.836 25.584 241.92 25.608 ;
    END
  END lg_local_read[9]
  PIN lg_local_write[0]
    DIRECTION OUTPUT ;
    USE SIGNAL ;
    PORT
      LAYER M4 ;
        RECT  241.836 43.152 241.92 43.176 ;
    END
  END lg_local_write[0]
  PIN lg_local_write[10]
    DIRECTION OUTPUT ;
    USE SIGNAL ;
    PORT
      LAYER M4 ;
        RECT  241.836 44.112 241.92 44.136 ;
    END
  END lg_local_write[10]
  PIN lg_local_write[11]
    DIRECTION OUTPUT ;
    USE SIGNAL ;
    PORT
      LAYER M4 ;
        RECT  241.836 44.208 241.92 44.232 ;
    END
  END lg_local_write[11]
  PIN lg_local_write[12]
    DIRECTION OUTPUT ;
    USE SIGNAL ;
    PORT
      LAYER M4 ;
        RECT  241.836 44.304 241.92 44.328 ;
    END
  END lg_local_write[12]
  PIN lg_local_write[13]
    DIRECTION OUTPUT ;
    USE SIGNAL ;
    PORT
      LAYER M4 ;
        RECT  241.836 44.4 241.92 44.424 ;
    END
  END lg_local_write[13]
  PIN lg_local_write[14]
    DIRECTION OUTPUT ;
    USE SIGNAL ;
    PORT
      LAYER M4 ;
        RECT  241.836 44.496 241.92 44.52 ;
    END
  END lg_local_write[14]
  PIN lg_local_write[15]
    DIRECTION OUTPUT ;
    USE SIGNAL ;
    PORT
      LAYER M4 ;
        RECT  241.836 44.592 241.92 44.616 ;
    END
  END lg_local_write[15]
  PIN lg_local_write[16]
    DIRECTION OUTPUT ;
    USE SIGNAL ;
    PORT
      LAYER M4 ;
        RECT  241.836 44.688 241.92 44.712 ;
    END
  END lg_local_write[16]
  PIN lg_local_write[17]
    DIRECTION OUTPUT ;
    USE SIGNAL ;
    PORT
      LAYER M4 ;
        RECT  241.836 44.784 241.92 44.808 ;
    END
  END lg_local_write[17]
  PIN lg_local_write[18]
    DIRECTION OUTPUT ;
    USE SIGNAL ;
    PORT
      LAYER M4 ;
        RECT  241.836 44.88 241.92 44.904 ;
    END
  END lg_local_write[18]
  PIN lg_local_write[19]
    DIRECTION OUTPUT ;
    USE SIGNAL ;
    PORT
      LAYER M4 ;
        RECT  241.836 44.976 241.92 45 ;
    END
  END lg_local_write[19]
  PIN lg_local_write[1]
    DIRECTION OUTPUT ;
    USE SIGNAL ;
    PORT
      LAYER M4 ;
        RECT  241.836 43.248 241.92 43.272 ;
    END
  END lg_local_write[1]
  PIN lg_local_write[20]
    DIRECTION OUTPUT ;
    USE SIGNAL ;
    PORT
      LAYER M4 ;
        RECT  241.836 45.072 241.92 45.096 ;
    END
  END lg_local_write[20]
  PIN lg_local_write[21]
    DIRECTION OUTPUT ;
    USE SIGNAL ;
    PORT
      LAYER M4 ;
        RECT  241.836 45.168 241.92 45.192 ;
    END
  END lg_local_write[21]
  PIN lg_local_write[22]
    DIRECTION OUTPUT ;
    USE SIGNAL ;
    PORT
      LAYER M4 ;
        RECT  241.836 26.064 241.92 26.088 ;
    END
  END lg_local_write[22]
  PIN lg_local_write[23]
    DIRECTION OUTPUT ;
    USE SIGNAL ;
    PORT
      LAYER M4 ;
        RECT  241.836 26.16 241.92 26.184 ;
    END
  END lg_local_write[23]
  PIN lg_local_write[2]
    DIRECTION OUTPUT ;
    USE SIGNAL ;
    PORT
      LAYER M4 ;
        RECT  241.836 43.344 241.92 43.368 ;
    END
  END lg_local_write[2]
  PIN lg_local_write[3]
    DIRECTION OUTPUT ;
    USE SIGNAL ;
    PORT
      LAYER M4 ;
        RECT  241.836 43.44 241.92 43.464 ;
    END
  END lg_local_write[3]
  PIN lg_local_write[4]
    DIRECTION OUTPUT ;
    USE SIGNAL ;
    PORT
      LAYER M4 ;
        RECT  241.836 43.536 241.92 43.56 ;
    END
  END lg_local_write[4]
  PIN lg_local_write[5]
    DIRECTION OUTPUT ;
    USE SIGNAL ;
    PORT
      LAYER M4 ;
        RECT  241.836 43.632 241.92 43.656 ;
    END
  END lg_local_write[5]
  PIN lg_local_write[6]
    DIRECTION OUTPUT ;
    USE SIGNAL ;
    PORT
      LAYER M4 ;
        RECT  241.836 43.728 241.92 43.752 ;
    END
  END lg_local_write[6]
  PIN lg_local_write[7]
    DIRECTION OUTPUT ;
    USE SIGNAL ;
    PORT
      LAYER M4 ;
        RECT  241.836 43.824 241.92 43.848 ;
    END
  END lg_local_write[7]
  PIN lg_local_write[8]
    DIRECTION OUTPUT ;
    USE SIGNAL ;
    PORT
      LAYER M4 ;
        RECT  241.836 43.92 241.92 43.944 ;
    END
  END lg_local_write[8]
  PIN lg_local_write[9]
    DIRECTION OUTPUT ;
    USE SIGNAL ;
    PORT
      LAYER M4 ;
        RECT  241.836 44.016 241.92 44.04 ;
    END
  END lg_local_write[9]
  PIN ordinal[0]
    DIRECTION OUTPUT ;
    USE SIGNAL ;
    PORT
      LAYER M5 ;
        RECT  13.584 0 13.608 0.084 ;
    END
  END ordinal[0]
  PIN ordinal[10]
    DIRECTION OUTPUT ;
    USE SIGNAL ;
    PORT
      LAYER M5 ;
        RECT  14.544 0 14.568 0.084 ;
    END
  END ordinal[10]
  PIN ordinal[11]
    DIRECTION OUTPUT ;
    USE SIGNAL ;
    PORT
      LAYER M5 ;
        RECT  14.64 0 14.664 0.084 ;
    END
  END ordinal[11]
  PIN ordinal[12]
    DIRECTION OUTPUT ;
    USE SIGNAL ;
    PORT
      LAYER M5 ;
        RECT  14.736 0 14.76 0.084 ;
    END
  END ordinal[12]
  PIN ordinal[13]
    DIRECTION OUTPUT ;
    USE SIGNAL ;
    PORT
      LAYER M5 ;
        RECT  14.832 0 14.856 0.084 ;
    END
  END ordinal[13]
  PIN ordinal[14]
    DIRECTION OUTPUT ;
    USE SIGNAL ;
    PORT
      LAYER M5 ;
        RECT  14.928 0 14.952 0.084 ;
    END
  END ordinal[14]
  PIN ordinal[15]
    DIRECTION OUTPUT ;
    USE SIGNAL ;
    PORT
      LAYER M5 ;
        RECT  15.024 0 15.048 0.084 ;
    END
  END ordinal[15]
  PIN ordinal[16]
    DIRECTION OUTPUT ;
    USE SIGNAL ;
    PORT
      LAYER M5 ;
        RECT  15.12 0 15.144 0.084 ;
    END
  END ordinal[16]
  PIN ordinal[17]
    DIRECTION OUTPUT ;
    USE SIGNAL ;
    PORT
      LAYER M5 ;
        RECT  15.216 0 15.24 0.084 ;
    END
  END ordinal[17]
  PIN ordinal[18]
    DIRECTION OUTPUT ;
    USE SIGNAL ;
    PORT
      LAYER M5 ;
        RECT  15.312 0 15.336 0.084 ;
    END
  END ordinal[18]
  PIN ordinal[19]
    DIRECTION OUTPUT ;
    USE SIGNAL ;
    PORT
      LAYER M5 ;
        RECT  15.408 0 15.432 0.084 ;
    END
  END ordinal[19]
  PIN ordinal[1]
    DIRECTION OUTPUT ;
    USE SIGNAL ;
    PORT
      LAYER M5 ;
        RECT  13.68 0 13.704 0.084 ;
    END
  END ordinal[1]
  PIN ordinal[20]
    DIRECTION OUTPUT ;
    USE SIGNAL ;
    PORT
      LAYER M5 ;
        RECT  15.504 0 15.528 0.084 ;
    END
  END ordinal[20]
  PIN ordinal[21]
    DIRECTION OUTPUT ;
    USE SIGNAL ;
    PORT
      LAYER M5 ;
        RECT  15.6 0 15.624 0.084 ;
    END
  END ordinal[21]
  PIN ordinal[22]
    DIRECTION OUTPUT ;
    USE SIGNAL ;
    PORT
      LAYER M5 ;
        RECT  15.696 0 15.72 0.084 ;
    END
  END ordinal[22]
  PIN ordinal[23]
    DIRECTION OUTPUT ;
    USE SIGNAL ;
    PORT
      LAYER M5 ;
        RECT  15.792 0 15.816 0.084 ;
    END
  END ordinal[23]
  PIN ordinal[24]
    DIRECTION OUTPUT ;
    USE SIGNAL ;
    PORT
      LAYER M5 ;
        RECT  15.888 0 15.912 0.084 ;
    END
  END ordinal[24]
  PIN ordinal[25]
    DIRECTION OUTPUT ;
    USE SIGNAL ;
    PORT
      LAYER M5 ;
        RECT  15.984 0 16.008 0.084 ;
    END
  END ordinal[25]
  PIN ordinal[26]
    DIRECTION OUTPUT ;
    USE SIGNAL ;
    PORT
      LAYER M5 ;
        RECT  16.08 0 16.104 0.084 ;
    END
  END ordinal[26]
  PIN ordinal[27]
    DIRECTION OUTPUT ;
    USE SIGNAL ;
    PORT
      LAYER M5 ;
        RECT  16.176 0 16.2 0.084 ;
    END
  END ordinal[27]
  PIN ordinal[28]
    DIRECTION OUTPUT ;
    USE SIGNAL ;
    PORT
      LAYER M5 ;
        RECT  16.272 0 16.296 0.084 ;
    END
  END ordinal[28]
  PIN ordinal[29]
    DIRECTION OUTPUT ;
    USE SIGNAL ;
    PORT
      LAYER M5 ;
        RECT  16.368 0 16.392 0.084 ;
    END
  END ordinal[29]
  PIN ordinal[2]
    DIRECTION OUTPUT ;
    USE SIGNAL ;
    PORT
      LAYER M5 ;
        RECT  13.776 0 13.8 0.084 ;
    END
  END ordinal[2]
  PIN ordinal[30]
    DIRECTION OUTPUT ;
    USE SIGNAL ;
    PORT
      LAYER M5 ;
        RECT  16.464 0 16.488 0.084 ;
    END
  END ordinal[30]
  PIN ordinal[31]
    DIRECTION OUTPUT ;
    USE SIGNAL ;
    PORT
      LAYER M5 ;
        RECT  16.56 0 16.584 0.084 ;
    END
  END ordinal[31]
  PIN ordinal[3]
    DIRECTION OUTPUT ;
    USE SIGNAL ;
    PORT
      LAYER M5 ;
        RECT  13.872 0 13.896 0.084 ;
    END
  END ordinal[3]
  PIN ordinal[4]
    DIRECTION OUTPUT ;
    USE SIGNAL ;
    PORT
      LAYER M5 ;
        RECT  13.968 0 13.992 0.084 ;
    END
  END ordinal[4]
  PIN ordinal[5]
    DIRECTION OUTPUT ;
    USE SIGNAL ;
    PORT
      LAYER M5 ;
        RECT  14.064 0 14.088 0.084 ;
    END
  END ordinal[5]
  PIN ordinal[6]
    DIRECTION OUTPUT ;
    USE SIGNAL ;
    PORT
      LAYER M5 ;
        RECT  14.16 0 14.184 0.084 ;
    END
  END ordinal[6]
  PIN ordinal[7]
    DIRECTION OUTPUT ;
    USE SIGNAL ;
    PORT
      LAYER M5 ;
        RECT  14.256 0 14.28 0.084 ;
    END
  END ordinal[7]
  PIN ordinal[8]
    DIRECTION OUTPUT ;
    USE SIGNAL ;
    PORT
      LAYER M5 ;
        RECT  14.352 0 14.376 0.084 ;
    END
  END ordinal[8]
  PIN ordinal[9]
    DIRECTION OUTPUT ;
    USE SIGNAL ;
    PORT
      LAYER M5 ;
        RECT  14.448 0 14.472 0.084 ;
    END
  END ordinal[9]
  PIN replay_enable
    DIRECTION OUTPUT ;
    USE SIGNAL ;
    PORT
      LAYER M4 ;
        RECT  241.836 26.256 241.92 26.28 ;
    END
  END replay_enable
  PIN replay_source
    DIRECTION OUTPUT ;
    USE SIGNAL ;
    PORT
      LAYER M4 ;
        RECT  241.836 26.352 241.92 26.376 ;
    END
  END replay_source
  PIN response_enable[0]
    DIRECTION OUTPUT ;
    USE SIGNAL ;
    PORT
      LAYER M4 ;
        RECT  241.836 26.448 241.92 26.472 ;
    END
  END response_enable[0]
  PIN response_enable[1]
    DIRECTION OUTPUT ;
    USE SIGNAL ;
    PORT
      LAYER M4 ;
        RECT  241.836 26.544 241.92 26.568 ;
    END
  END response_enable[1]
  PIN response_enable[2]
    DIRECTION OUTPUT ;
    USE SIGNAL ;
    PORT
      LAYER M4 ;
        RECT  241.836 26.64 241.92 26.664 ;
    END
  END response_enable[2]
  PIN response_enable[3]
    DIRECTION OUTPUT ;
    USE SIGNAL ;
    PORT
      LAYER M4 ;
        RECT  241.836 26.736 241.92 26.76 ;
    END
  END response_enable[3]
  PIN response_enable[4]
    DIRECTION OUTPUT ;
    USE SIGNAL ;
    PORT
      LAYER M4 ;
        RECT  241.836 26.832 241.92 26.856 ;
    END
  END response_enable[4]
  PIN response_seq[0]
    DIRECTION OUTPUT ;
    USE SIGNAL ;
    PORT
      LAYER M4 ;
        RECT  241.836 26.928 241.92 26.952 ;
    END
  END response_seq[0]
  PIN response_seq[1]
    DIRECTION OUTPUT ;
    USE SIGNAL ;
    PORT
      LAYER M4 ;
        RECT  241.836 27.024 241.92 27.048 ;
    END
  END response_seq[1]
  PIN response_seq[2]
    DIRECTION OUTPUT ;
    USE SIGNAL ;
    PORT
      LAYER M4 ;
        RECT  241.836 27.12 241.92 27.144 ;
    END
  END response_seq[2]
  PIN response_seq[3]
    DIRECTION OUTPUT ;
    USE SIGNAL ;
    PORT
      LAYER M4 ;
        RECT  241.836 27.216 241.92 27.24 ;
    END
  END response_seq[3]
  PIN response_seq[4]
    DIRECTION OUTPUT ;
    USE SIGNAL ;
    PORT
      LAYER M4 ;
        RECT  241.836 27.312 241.92 27.336 ;
    END
  END response_seq[4]
  PIN response_seq[5]
    DIRECTION OUTPUT ;
    USE SIGNAL ;
    PORT
      LAYER M4 ;
        RECT  241.836 27.408 241.92 27.432 ;
    END
  END response_seq[5]
  PIN response_seq[6]
    DIRECTION OUTPUT ;
    USE SIGNAL ;
    PORT
      LAYER M4 ;
        RECT  241.836 27.504 241.92 27.528 ;
    END
  END response_seq[6]
  PIN response_seq[7]
    DIRECTION OUTPUT ;
    USE SIGNAL ;
    PORT
      LAYER M4 ;
        RECT  241.836 27.6 241.92 27.624 ;
    END
  END response_seq[7]
  PIN response_seq[8]
    DIRECTION OUTPUT ;
    USE SIGNAL ;
    PORT
      LAYER M4 ;
        RECT  241.836 27.696 241.92 27.72 ;
    END
  END response_seq[8]
  PIN response_seq[9]
    DIRECTION OUTPUT ;
    USE SIGNAL ;
    PORT
      LAYER M4 ;
        RECT  241.836 27.792 241.92 27.816 ;
    END
  END response_seq[9]
  PIN ring_tx_enable[0]
    DIRECTION OUTPUT ;
    USE SIGNAL ;
    PORT
      LAYER M4 ;
        RECT  241.836 27.888 241.92 27.912 ;
    END
  END ring_tx_enable[0]
  PIN ring_tx_enable[1]
    DIRECTION OUTPUT ;
    USE SIGNAL ;
    PORT
      LAYER M4 ;
        RECT  241.836 27.984 241.92 28.008 ;
    END
  END ring_tx_enable[1]
  PIN ring_tx_source[0]
    DIRECTION OUTPUT ;
    USE SIGNAL ;
    PORT
      LAYER M4 ;
        RECT  241.836 28.08 241.92 28.104 ;
    END
  END ring_tx_source[0]
  PIN ring_tx_source[1]
    DIRECTION OUTPUT ;
    USE SIGNAL ;
    PORT
      LAYER M4 ;
        RECT  241.836 28.176 241.92 28.2 ;
    END
  END ring_tx_source[1]
  PIN ring_tx_source[2]
    DIRECTION OUTPUT ;
    USE SIGNAL ;
    PORT
      LAYER M4 ;
        RECT  241.836 28.272 241.92 28.296 ;
    END
  END ring_tx_source[2]
  PIN ring_tx_source[3]
    DIRECTION OUTPUT ;
    USE SIGNAL ;
    PORT
      LAYER M4 ;
        RECT  241.836 28.368 241.92 28.392 ;
    END
  END ring_tx_source[3]
  PIN ring_tx_source[4]
    DIRECTION OUTPUT ;
    USE SIGNAL ;
    PORT
      LAYER M4 ;
        RECT  241.836 28.464 241.92 28.488 ;
    END
  END ring_tx_source[4]
  PIN ring_tx_source[5]
    DIRECTION OUTPUT ;
    USE SIGNAL ;
    PORT
      LAYER M4 ;
        RECT  241.836 28.56 241.92 28.584 ;
    END
  END ring_tx_source[5]
  PIN rslot[0]
    DIRECTION OUTPUT ;
    USE SIGNAL ;
    PORT
      LAYER M4 ;
        RECT  241.836 28.656 241.92 28.68 ;
    END
  END rslot[0]
  PIN rslot[10]
    DIRECTION OUTPUT ;
    USE SIGNAL ;
    PORT
      LAYER M4 ;
        RECT  241.836 32.688 241.92 32.712 ;
    END
  END rslot[10]
  PIN rslot[11]
    DIRECTION OUTPUT ;
    USE SIGNAL ;
    PORT
      LAYER M4 ;
        RECT  241.836 32.784 241.92 32.808 ;
    END
  END rslot[11]
  PIN rslot[12]
    DIRECTION OUTPUT ;
    USE SIGNAL ;
    PORT
      LAYER M4 ;
        RECT  241.836 32.88 241.92 32.904 ;
    END
  END rslot[12]
  PIN rslot[13]
    DIRECTION OUTPUT ;
    USE SIGNAL ;
    PORT
      LAYER M4 ;
        RECT  241.836 32.976 241.92 33 ;
    END
  END rslot[13]
  PIN rslot[14]
    DIRECTION OUTPUT ;
    USE SIGNAL ;
    PORT
      LAYER M4 ;
        RECT  241.836 33.072 241.92 33.096 ;
    END
  END rslot[14]
  PIN rslot[15]
    DIRECTION OUTPUT ;
    USE SIGNAL ;
    PORT
      LAYER M4 ;
        RECT  241.836 33.168 241.92 33.192 ;
    END
  END rslot[15]
  PIN rslot[16]
    DIRECTION OUTPUT ;
    USE SIGNAL ;
    PORT
      LAYER M4 ;
        RECT  241.836 33.264 241.92 33.288 ;
    END
  END rslot[16]
  PIN rslot[17]
    DIRECTION OUTPUT ;
    USE SIGNAL ;
    PORT
      LAYER M4 ;
        RECT  241.836 33.36 241.92 33.384 ;
    END
  END rslot[17]
  PIN rslot[18]
    DIRECTION OUTPUT ;
    USE SIGNAL ;
    PORT
      LAYER M4 ;
        RECT  241.836 33.456 241.92 33.48 ;
    END
  END rslot[18]
  PIN rslot[19]
    DIRECTION OUTPUT ;
    USE SIGNAL ;
    PORT
      LAYER M4 ;
        RECT  241.836 33.552 241.92 33.576 ;
    END
  END rslot[19]
  PIN rslot[1]
    DIRECTION OUTPUT ;
    USE SIGNAL ;
    PORT
      LAYER M4 ;
        RECT  241.836 28.752 241.92 28.776 ;
    END
  END rslot[1]
  PIN rslot[20]
    DIRECTION OUTPUT ;
    USE SIGNAL ;
    PORT
      LAYER M4 ;
        RECT  241.836 33.648 241.92 33.672 ;
    END
  END rslot[20]
  PIN rslot[21]
    DIRECTION OUTPUT ;
    USE SIGNAL ;
    PORT
      LAYER M4 ;
        RECT  241.836 33.744 241.92 33.768 ;
    END
  END rslot[21]
  PIN rslot[22]
    DIRECTION OUTPUT ;
    USE SIGNAL ;
    PORT
      LAYER M4 ;
        RECT  241.836 33.84 241.92 33.864 ;
    END
  END rslot[22]
  PIN rslot[23]
    DIRECTION OUTPUT ;
    USE SIGNAL ;
    PORT
      LAYER M4 ;
        RECT  241.836 33.936 241.92 33.96 ;
    END
  END rslot[23]
  PIN rslot[2]
    DIRECTION OUTPUT ;
    USE SIGNAL ;
    PORT
      LAYER M4 ;
        RECT  241.836 28.848 241.92 28.872 ;
    END
  END rslot[2]
  PIN rslot[3]
    DIRECTION OUTPUT ;
    USE SIGNAL ;
    PORT
      LAYER M4 ;
        RECT  241.836 28.944 241.92 28.968 ;
    END
  END rslot[3]
  PIN rslot[4]
    DIRECTION OUTPUT ;
    USE SIGNAL ;
    PORT
      LAYER M4 ;
        RECT  241.836 29.04 241.92 29.064 ;
    END
  END rslot[4]
  PIN rslot[5]
    DIRECTION OUTPUT ;
    USE SIGNAL ;
    PORT
      LAYER M4 ;
        RECT  241.836 32.208 241.92 32.232 ;
    END
  END rslot[5]
  PIN rslot[6]
    DIRECTION OUTPUT ;
    USE SIGNAL ;
    PORT
      LAYER M4 ;
        RECT  241.836 32.304 241.92 32.328 ;
    END
  END rslot[6]
  PIN rslot[7]
    DIRECTION OUTPUT ;
    USE SIGNAL ;
    PORT
      LAYER M4 ;
        RECT  241.836 32.4 241.92 32.424 ;
    END
  END rslot[7]
  PIN rslot[8]
    DIRECTION OUTPUT ;
    USE SIGNAL ;
    PORT
      LAYER M4 ;
        RECT  241.836 32.496 241.92 32.52 ;
    END
  END rslot[8]
  PIN rslot[9]
    DIRECTION OUTPUT ;
    USE SIGNAL ;
    PORT
      LAYER M4 ;
        RECT  241.836 32.592 241.92 32.616 ;
    END
  END rslot[9]
  PIN rslot_v[0]
    DIRECTION OUTPUT ;
    USE SIGNAL ;
    PORT
      LAYER M4 ;
        RECT  241.836 34.032 241.92 34.056 ;
    END
  END rslot_v[0]
  PIN rslot_v[1]
    DIRECTION OUTPUT ;
    USE SIGNAL ;
    PORT
      LAYER M4 ;
        RECT  241.836 34.128 241.92 34.152 ;
    END
  END rslot_v[1]
  PIN rslot_v[2]
    DIRECTION OUTPUT ;
    USE SIGNAL ;
    PORT
      LAYER M4 ;
        RECT  241.836 34.224 241.92 34.248 ;
    END
  END rslot_v[2]
  PIN rslot_v[3]
    DIRECTION OUTPUT ;
    USE SIGNAL ;
    PORT
      LAYER M4 ;
        RECT  241.836 34.32 241.92 34.344 ;
    END
  END rslot_v[3]
  PIN rslot_v[4]
    DIRECTION OUTPUT ;
    USE SIGNAL ;
    PORT
      LAYER M4 ;
        RECT  241.836 34.416 241.92 34.44 ;
    END
  END rslot_v[4]
  PIN rslot_v[5]
    DIRECTION OUTPUT ;
    USE SIGNAL ;
    PORT
      LAYER M4 ;
        RECT  241.836 34.512 241.92 34.536 ;
    END
  END rslot_v[5]
  PIN rslot_v[6]
    DIRECTION OUTPUT ;
    USE SIGNAL ;
    PORT
      LAYER M4 ;
        RECT  241.836 34.608 241.92 34.632 ;
    END
  END rslot_v[6]
  PIN rslot_v[7]
    DIRECTION OUTPUT ;
    USE SIGNAL ;
    PORT
      LAYER M4 ;
        RECT  241.836 34.704 241.92 34.728 ;
    END
  END rslot_v[7]
  PIN rst_n
    DIRECTION INPUT ;
    USE SIGNAL ;
    PORT
      LAYER M4 ;
        RECT  0 12.912 0.084 12.936 ;
    END
  END rst_n
  PIN tgt[0]
    DIRECTION INPUT ;
    USE SIGNAL ;
    PORT
      LAYER M4 ;
        RECT  0 13.008 0.084 13.032 ;
    END
  END tgt[0]
  PIN tgt[1]
    DIRECTION INPUT ;
    USE SIGNAL ;
    PORT
      LAYER M4 ;
        RECT  0 13.104 0.084 13.128 ;
    END
  END tgt[1]
  PIN tgt[2]
    DIRECTION INPUT ;
    USE SIGNAL ;
    PORT
      LAYER M4 ;
        RECT  0 13.2 0.084 13.224 ;
    END
  END tgt[2]
  PIN tgt[3]
    DIRECTION INPUT ;
    USE SIGNAL ;
    PORT
      LAYER M4 ;
        RECT  0 13.296 0.084 13.32 ;
    END
  END tgt[3]
  PIN tgt[4]
    DIRECTION INPUT ;
    USE SIGNAL ;
    PORT
      LAYER M4 ;
        RECT  0 13.392 0.084 13.416 ;
    END
  END tgt[4]
  PIN tgt[5]
    DIRECTION INPUT ;
    USE SIGNAL ;
    PORT
      LAYER M4 ;
        RECT  0 13.488 0.084 13.512 ;
    END
  END tgt[5]
  PIN tgt[6]
    DIRECTION INPUT ;
    USE SIGNAL ;
    PORT
      LAYER M4 ;
        RECT  0 13.584 0.084 13.608 ;
    END
  END tgt[6]
  PIN tgt[7]
    DIRECTION INPUT ;
    USE SIGNAL ;
    PORT
      LAYER M4 ;
        RECT  0 13.68 0.084 13.704 ;
    END
  END tgt[7]
  PIN tgt_configured
    DIRECTION OUTPUT ;
    USE SIGNAL ;
    PORT
      LAYER M5 ;
        RECT  16.656 0 16.68 0.084 ;
    END
  END tgt_configured
  PIN tgt_fault
    DIRECTION OUTPUT ;
    USE SIGNAL ;
    PORT
      LAYER M5 ;
        RECT  16.752 0 16.776 0.084 ;
    END
  END tgt_fault
  PIN wslot[0]
    DIRECTION OUTPUT ;
    USE SIGNAL ;
    PORT
      LAYER M4 ;
        RECT  241.836 34.8 241.92 34.824 ;
    END
  END wslot[0]
  PIN wslot[10]
    DIRECTION OUTPUT ;
    USE SIGNAL ;
    PORT
      LAYER M4 ;
        RECT  241.836 35.76 241.92 35.784 ;
    END
  END wslot[10]
  PIN wslot[11]
    DIRECTION OUTPUT ;
    USE SIGNAL ;
    PORT
      LAYER M4 ;
        RECT  241.836 35.856 241.92 35.88 ;
    END
  END wslot[11]
  PIN wslot[12]
    DIRECTION OUTPUT ;
    USE SIGNAL ;
    PORT
      LAYER M4 ;
        RECT  241.836 35.952 241.92 35.976 ;
    END
  END wslot[12]
  PIN wslot[13]
    DIRECTION OUTPUT ;
    USE SIGNAL ;
    PORT
      LAYER M4 ;
        RECT  241.836 36.048 241.92 36.072 ;
    END
  END wslot[13]
  PIN wslot[14]
    DIRECTION OUTPUT ;
    USE SIGNAL ;
    PORT
      LAYER M4 ;
        RECT  241.836 36.144 241.92 36.168 ;
    END
  END wslot[14]
  PIN wslot[15]
    DIRECTION OUTPUT ;
    USE SIGNAL ;
    PORT
      LAYER M4 ;
        RECT  241.836 36.24 241.92 36.264 ;
    END
  END wslot[15]
  PIN wslot[16]
    DIRECTION OUTPUT ;
    USE SIGNAL ;
    PORT
      LAYER M4 ;
        RECT  241.836 36.336 241.92 36.36 ;
    END
  END wslot[16]
  PIN wslot[17]
    DIRECTION OUTPUT ;
    USE SIGNAL ;
    PORT
      LAYER M4 ;
        RECT  241.836 36.432 241.92 36.456 ;
    END
  END wslot[17]
  PIN wslot[18]
    DIRECTION OUTPUT ;
    USE SIGNAL ;
    PORT
      LAYER M4 ;
        RECT  241.836 36.528 241.92 36.552 ;
    END
  END wslot[18]
  PIN wslot[19]
    DIRECTION OUTPUT ;
    USE SIGNAL ;
    PORT
      LAYER M4 ;
        RECT  241.836 36.624 241.92 36.648 ;
    END
  END wslot[19]
  PIN wslot[1]
    DIRECTION OUTPUT ;
    USE SIGNAL ;
    PORT
      LAYER M4 ;
        RECT  241.836 34.896 241.92 34.92 ;
    END
  END wslot[1]
  PIN wslot[20]
    DIRECTION OUTPUT ;
    USE SIGNAL ;
    PORT
      LAYER M4 ;
        RECT  241.836 36.72 241.92 36.744 ;
    END
  END wslot[20]
  PIN wslot[21]
    DIRECTION OUTPUT ;
    USE SIGNAL ;
    PORT
      LAYER M4 ;
        RECT  241.836 36.816 241.92 36.84 ;
    END
  END wslot[21]
  PIN wslot[22]
    DIRECTION OUTPUT ;
    USE SIGNAL ;
    PORT
      LAYER M4 ;
        RECT  241.836 36.912 241.92 36.936 ;
    END
  END wslot[22]
  PIN wslot[23]
    DIRECTION OUTPUT ;
    USE SIGNAL ;
    PORT
      LAYER M4 ;
        RECT  241.836 37.008 241.92 37.032 ;
    END
  END wslot[23]
  PIN wslot[2]
    DIRECTION OUTPUT ;
    USE SIGNAL ;
    PORT
      LAYER M4 ;
        RECT  241.836 34.992 241.92 35.016 ;
    END
  END wslot[2]
  PIN wslot[3]
    DIRECTION OUTPUT ;
    USE SIGNAL ;
    PORT
      LAYER M4 ;
        RECT  241.836 35.088 241.92 35.112 ;
    END
  END wslot[3]
  PIN wslot[4]
    DIRECTION OUTPUT ;
    USE SIGNAL ;
    PORT
      LAYER M4 ;
        RECT  241.836 35.184 241.92 35.208 ;
    END
  END wslot[4]
  PIN wslot[5]
    DIRECTION OUTPUT ;
    USE SIGNAL ;
    PORT
      LAYER M4 ;
        RECT  241.836 35.28 241.92 35.304 ;
    END
  END wslot[5]
  PIN wslot[6]
    DIRECTION OUTPUT ;
    USE SIGNAL ;
    PORT
      LAYER M4 ;
        RECT  241.836 35.376 241.92 35.4 ;
    END
  END wslot[6]
  PIN wslot[7]
    DIRECTION OUTPUT ;
    USE SIGNAL ;
    PORT
      LAYER M4 ;
        RECT  241.836 35.472 241.92 35.496 ;
    END
  END wslot[7]
  PIN wslot[8]
    DIRECTION OUTPUT ;
    USE SIGNAL ;
    PORT
      LAYER M4 ;
        RECT  241.836 35.568 241.92 35.592 ;
    END
  END wslot[8]
  PIN wslot[9]
    DIRECTION OUTPUT ;
    USE SIGNAL ;
    PORT
      LAYER M4 ;
        RECT  241.836 35.664 241.92 35.688 ;
    END
  END wslot[9]
  PIN wslot_v[0]
    DIRECTION OUTPUT ;
    USE SIGNAL ;
    PORT
      LAYER M4 ;
        RECT  241.836 37.104 241.92 37.128 ;
    END
  END wslot_v[0]
  PIN wslot_v[1]
    DIRECTION OUTPUT ;
    USE SIGNAL ;
    PORT
      LAYER M4 ;
        RECT  241.836 37.2 241.92 37.224 ;
    END
  END wslot_v[1]
  PIN wslot_v[2]
    DIRECTION OUTPUT ;
    USE SIGNAL ;
    PORT
      LAYER M4 ;
        RECT  241.836 37.296 241.92 37.32 ;
    END
  END wslot_v[2]
  PIN wslot_v[3]
    DIRECTION OUTPUT ;
    USE SIGNAL ;
    PORT
      LAYER M4 ;
        RECT  241.836 37.392 241.92 37.416 ;
    END
  END wslot_v[3]
  PIN wslot_v[4]
    DIRECTION OUTPUT ;
    USE SIGNAL ;
    PORT
      LAYER M4 ;
        RECT  241.836 37.488 241.92 37.512 ;
    END
  END wslot_v[4]
  PIN wslot_v[5]
    DIRECTION OUTPUT ;
    USE SIGNAL ;
    PORT
      LAYER M4 ;
        RECT  241.836 37.584 241.92 37.608 ;
    END
  END wslot_v[5]
  PIN wslot_v[6]
    DIRECTION OUTPUT ;
    USE SIGNAL ;
    PORT
      LAYER M4 ;
        RECT  241.836 37.68 241.92 37.704 ;
    END
  END wslot_v[6]
  PIN wslot_v[7]
    DIRECTION OUTPUT ;
    USE SIGNAL ;
    PORT
      LAYER M4 ;
        RECT  241.836 37.776 241.92 37.8 ;
    END
  END wslot_v[7]
  PIN VDD
    DIRECTION INOUT ;
    USE POWER ;
    PORT
      LAYER M5 ;
        RECT  234.792 2.151 234.912 114.489 ;
        RECT  229.392 2.151 229.512 114.489 ;
        RECT  223.992 2.151 224.112 114.489 ;
        RECT  218.592 2.151 218.712 114.489 ;
        RECT  213.192 2.151 213.312 114.489 ;
        RECT  207.792 2.151 207.912 114.489 ;
        RECT  202.392 2.151 202.512 114.489 ;
        RECT  196.992 2.151 197.112 114.489 ;
        RECT  191.592 2.151 191.712 114.489 ;
        RECT  186.192 2.151 186.312 114.489 ;
        RECT  180.792 2.151 180.912 114.489 ;
        RECT  175.392 2.151 175.512 114.489 ;
        RECT  169.992 2.151 170.112 114.489 ;
        RECT  164.592 2.151 164.712 114.489 ;
        RECT  159.192 2.151 159.312 114.489 ;
        RECT  153.792 2.151 153.912 114.489 ;
        RECT  148.392 2.151 148.512 114.489 ;
        RECT  142.992 2.151 143.112 114.489 ;
        RECT  137.592 2.151 137.712 114.489 ;
        RECT  132.192 2.151 132.312 114.489 ;
        RECT  126.792 2.151 126.912 114.489 ;
        RECT  121.392 2.151 121.512 114.489 ;
        RECT  115.992 2.151 116.112 114.489 ;
        RECT  110.592 2.151 110.712 114.489 ;
        RECT  105.192 2.151 105.312 114.489 ;
        RECT  99.792 2.151 99.912 114.489 ;
        RECT  94.392 2.151 94.512 114.489 ;
        RECT  88.992 2.151 89.112 114.489 ;
        RECT  83.592 2.151 83.712 114.489 ;
        RECT  78.192 2.151 78.312 114.489 ;
        RECT  72.792 2.151 72.912 114.489 ;
        RECT  67.392 2.151 67.512 114.489 ;
        RECT  61.992 2.151 62.112 114.489 ;
        RECT  56.592 2.151 56.712 114.489 ;
        RECT  51.192 2.151 51.312 114.489 ;
        RECT  45.792 2.151 45.912 114.489 ;
        RECT  40.392 2.151 40.512 114.489 ;
        RECT  34.992 2.151 35.112 114.489 ;
        RECT  29.592 2.151 29.712 114.489 ;
        RECT  24.192 2.151 24.312 114.489 ;
        RECT  18.792 2.151 18.912 114.489 ;
        RECT  13.392 2.151 13.512 114.489 ;
        RECT  7.992 2.151 8.112 114.489 ;
        RECT  2.592 2.151 2.712 114.489 ;
    END
  END VDD
  PIN VSS
    DIRECTION INOUT ;
    USE GROUND ;
    PORT
      LAYER M5 ;
        RECT  234.6 2.137 234.72 114.503 ;
        RECT  229.2 2.137 229.32 114.503 ;
        RECT  223.8 2.137 223.92 114.503 ;
        RECT  218.4 2.137 218.52 114.503 ;
        RECT  213 2.137 213.12 114.503 ;
        RECT  207.6 2.137 207.72 114.503 ;
        RECT  202.2 2.137 202.32 114.503 ;
        RECT  196.8 2.137 196.92 114.503 ;
        RECT  191.4 2.137 191.52 114.503 ;
        RECT  186 2.137 186.12 114.503 ;
        RECT  180.6 2.137 180.72 114.503 ;
        RECT  175.2 2.137 175.32 114.503 ;
        RECT  169.8 2.137 169.92 114.503 ;
        RECT  164.4 2.137 164.52 114.503 ;
        RECT  159 2.137 159.12 114.503 ;
        RECT  153.6 2.137 153.72 114.503 ;
        RECT  148.2 2.137 148.32 114.503 ;
        RECT  142.8 2.137 142.92 114.503 ;
        RECT  137.4 2.137 137.52 114.503 ;
        RECT  132 2.137 132.12 114.503 ;
        RECT  126.6 2.137 126.72 114.503 ;
        RECT  121.2 2.137 121.32 114.503 ;
        RECT  115.8 2.137 115.92 114.503 ;
        RECT  110.4 2.137 110.52 114.503 ;
        RECT  105 2.137 105.12 114.503 ;
        RECT  99.6 2.137 99.72 114.503 ;
        RECT  94.2 2.137 94.32 114.503 ;
        RECT  88.8 2.137 88.92 114.503 ;
        RECT  83.4 2.137 83.52 114.503 ;
        RECT  78 2.137 78.12 114.503 ;
        RECT  72.6 2.137 72.72 114.503 ;
        RECT  67.2 2.137 67.32 114.503 ;
        RECT  61.8 2.137 61.92 114.503 ;
        RECT  56.4 2.137 56.52 114.503 ;
        RECT  51 2.137 51.12 114.503 ;
        RECT  45.6 2.137 45.72 114.503 ;
        RECT  40.2 2.137 40.32 114.503 ;
        RECT  34.8 2.137 34.92 114.503 ;
        RECT  29.4 2.137 29.52 114.503 ;
        RECT  24 2.137 24.12 114.503 ;
        RECT  18.6 2.137 18.72 114.503 ;
        RECT  13.2 2.137 13.32 114.503 ;
        RECT  7.8 2.137 7.92 114.503 ;
        RECT  2.4 2.137 2.52 114.503 ;
    END
  END VSS
  OBS
    LAYER LVTN ;
     RECT  6.696 18.225 7.02 18.36 ;
     RECT  8.1 19.98 8.694 20.115 ;
     RECT  5.4 21.06 5.778 21.195 ;
     RECT  8.1 21.06 8.856 21.195 ;
     RECT  6.912 21.6 7.182 21.735 ;
     RECT  6.804 23.085 7.452 23.22 ;
     RECT  8.478 23.22 8.748 23.355 ;
     RECT  7.83 23.625 8.1 23.76 ;
     RECT  6.858 24.3 7.452 24.435 ;
     RECT  8.532 24.3 8.802 24.435 ;
     RECT  3.402 45.9 3.78 46.035 ;
     RECT  5.562 46.98 5.886 47.115 ;
     RECT  8.802 47.385 9.342 47.52 ;
     RECT  5.67 49.68 6.048 49.815 ;
     RECT  3.618 50.22 3.888 50.355 ;
     RECT  3.51 50.76 3.834 50.895 ;
     RECT  3.78 51.165 4.05 51.3 ;
     RECT  6.156 51.3 6.426 51.435 ;
     RECT  2.646 52.92 2.916 53.055 ;
     RECT  3.672 53.46 3.942 53.595 ;
     RECT  6.426 54 6.696 54.135 ;
     RECT  3.618 54.405 3.888 54.54 ;
     RECT  3.726 54.54 3.996 54.675 ;
     RECT  6.75 54.945 7.02 55.08 ;
     RECT  5.886 55.08 6.156 55.215 ;
     RECT  5.886 55.485 6.156 55.62 ;
     RECT  5.67 56.565 5.94 56.7 ;
     RECT  5.4 57.105 5.724 57.24 ;
    LAYER LVTP ;
     RECT  6.696 18.09 7.02 18.225 ;
     RECT  8.1 20.115 8.694 20.25 ;
     RECT  5.4 21.195 5.778 21.33 ;
     RECT  8.1 21.195 8.856 21.33 ;
     RECT  6.912 21.735 7.182 21.87 ;
     RECT  6.804 22.95 7.452 23.085 ;
     RECT  8.478 23.355 8.748 23.49 ;
     RECT  7.83 23.49 8.1 23.625 ;
     RECT  6.858 24.435 7.452 24.57 ;
     RECT  8.532 24.435 8.802 24.57 ;
     RECT  3.402 46.035 3.78 46.17 ;
     RECT  5.562 47.115 5.886 47.25 ;
     RECT  8.802 47.25 9.342 47.385 ;
     RECT  5.67 49.815 6.048 49.95 ;
     RECT  3.618 50.355 3.888 50.49 ;
     RECT  3.51 50.895 3.834 51.03 ;
     RECT  3.78 51.03 4.05 51.165 ;
     RECT  6.156 51.435 6.426 51.57 ;
     RECT  2.646 53.055 2.916 53.19 ;
     RECT  3.672 53.595 3.942 53.73 ;
     RECT  6.426 54.135 6.696 54.27 ;
     RECT  3.618 54.27 3.888 54.405 ;
     RECT  3.726 54.675 3.996 54.81 ;
     RECT  6.75 54.81 7.02 54.945 ;
     RECT  5.886 55.215 6.156 55.485 ;
     RECT  5.67 56.43 5.94 56.565 ;
     RECT  5.4 56.97 5.724 57.105 ;
    LAYER RVTN ;
     RECT  2.16 2.16 239.76 2.295 ;
     RECT  2.16 2.565 239.76 2.835 ;
     RECT  2.16 3.105 239.76 3.375 ;
     RECT  2.16 3.645 239.76 3.915 ;
     RECT  2.16 4.185 239.76 4.455 ;
     RECT  2.16 4.725 239.76 4.995 ;
     RECT  2.16 5.265 239.76 5.535 ;
     RECT  2.16 5.805 239.76 6.075 ;
     RECT  2.16 6.345 239.76 6.615 ;
     RECT  2.16 6.885 239.76 7.155 ;
     RECT  2.16 7.425 239.76 7.695 ;
     RECT  2.16 7.965 239.76 8.235 ;
     RECT  2.16 8.505 239.76 8.775 ;
     RECT  2.16 9.045 239.76 9.315 ;
     RECT  2.16 9.585 239.76 9.855 ;
     RECT  2.16 10.125 239.76 10.395 ;
     RECT  2.16 10.665 239.76 10.935 ;
     RECT  2.16 11.205 239.76 11.475 ;
     RECT  2.16 11.745 239.76 12.015 ;
     RECT  2.16 12.285 239.76 12.555 ;
     RECT  2.16 12.825 239.76 13.095 ;
     RECT  2.16 13.365 239.76 13.635 ;
     RECT  2.16 13.905 239.76 14.175 ;
     RECT  2.16 14.445 239.76 14.715 ;
     RECT  2.16 14.985 239.76 15.255 ;
     RECT  2.16 15.525 239.76 15.795 ;
     RECT  2.16 16.065 239.76 16.335 ;
     RECT  2.16 16.605 239.76 16.875 ;
     RECT  2.16 17.145 239.76 17.415 ;
     RECT  2.16 17.685 239.76 17.955 ;
     RECT  2.16 18.225 6.696 18.36 ;
     RECT  7.02 18.225 239.76 18.36 ;
     RECT  2.16 18.36 239.76 18.495 ;
     RECT  2.16 18.765 239.76 19.035 ;
     RECT  2.16 19.305 239.76 19.575 ;
     RECT  2.16 19.845 239.76 19.98 ;
     RECT  2.16 19.98 8.1 20.115 ;
     RECT  8.694 19.98 239.76 20.115 ;
     RECT  2.16 20.385 239.76 20.655 ;
     RECT  2.16 20.925 239.76 21.06 ;
     RECT  2.16 21.06 5.4 21.195 ;
     RECT  5.778 21.06 8.1 21.195 ;
     RECT  8.856 21.06 239.76 21.195 ;
     RECT  2.16 21.465 239.76 21.6 ;
     RECT  2.16 21.6 6.912 21.735 ;
     RECT  7.182 21.6 42.444 21.735 ;
     RECT  221.292 21.6 239.76 21.735 ;
     RECT  2.16 22.005 42.444 22.275 ;
     RECT  221.292 22.005 239.76 22.275 ;
     RECT  2.16 22.545 42.444 22.815 ;
     RECT  221.292 22.545 239.76 22.815 ;
     RECT  2.16 23.085 6.804 23.22 ;
     RECT  7.452 23.085 42.444 23.22 ;
     RECT  2.16 23.22 8.478 23.355 ;
     RECT  8.748 23.22 42.444 23.355 ;
     RECT  221.292 23.085 239.76 23.355 ;
     RECT  2.16 23.625 7.83 23.76 ;
     RECT  8.1 23.625 42.444 23.76 ;
     RECT  2.16 23.76 42.444 23.895 ;
     RECT  221.292 23.625 239.76 23.895 ;
     RECT  2.16 24.165 42.444 24.3 ;
     RECT  2.16 24.3 6.858 24.435 ;
     RECT  7.452 24.3 8.532 24.435 ;
     RECT  8.802 24.3 42.444 24.435 ;
     RECT  221.292 24.165 239.76 24.435 ;
     RECT  2.16 24.705 42.444 24.975 ;
     RECT  221.292 24.705 239.76 24.975 ;
     RECT  2.16 25.245 42.444 25.515 ;
     RECT  221.292 25.245 239.76 25.515 ;
     RECT  2.16 25.785 42.444 26.055 ;
     RECT  221.292 25.785 239.76 26.055 ;
     RECT  2.16 26.325 42.444 26.595 ;
     RECT  221.292 26.325 239.76 26.595 ;
     RECT  2.16 26.865 42.444 27.135 ;
     RECT  221.292 26.865 239.76 27.135 ;
     RECT  2.16 27.405 42.444 27.675 ;
     RECT  221.292 27.405 239.76 27.675 ;
     RECT  2.16 27.945 42.444 28.215 ;
     RECT  221.292 27.945 239.76 28.215 ;
     RECT  2.16 28.485 42.444 28.755 ;
     RECT  221.292 28.485 239.76 28.755 ;
     RECT  2.16 29.025 42.444 29.295 ;
     RECT  221.292 29.025 239.76 29.295 ;
     RECT  2.16 29.565 42.444 29.835 ;
     RECT  221.292 29.565 239.76 29.835 ;
     RECT  2.16 30.105 42.444 30.375 ;
     RECT  221.292 30.105 239.76 30.375 ;
     RECT  2.16 30.645 42.444 30.915 ;
     RECT  221.292 30.645 239.76 30.915 ;
     RECT  2.16 31.185 42.444 31.455 ;
     RECT  221.292 31.185 239.76 31.455 ;
     RECT  2.16 31.725 42.444 31.995 ;
     RECT  221.292 31.725 239.76 31.995 ;
     RECT  2.16 32.265 42.444 32.535 ;
     RECT  221.292 32.265 239.76 32.535 ;
     RECT  2.16 32.805 42.444 33.075 ;
     RECT  221.292 32.805 239.76 33.075 ;
     RECT  2.16 33.345 42.444 33.615 ;
     RECT  221.292 33.345 239.76 33.615 ;
     RECT  2.16 33.885 42.444 34.155 ;
     RECT  221.292 33.885 239.76 34.155 ;
     RECT  2.16 34.425 42.444 34.695 ;
     RECT  221.292 34.425 239.76 34.695 ;
     RECT  2.16 34.965 42.444 35.235 ;
     RECT  221.292 34.965 239.76 35.235 ;
     RECT  2.16 35.505 42.444 35.775 ;
     RECT  221.292 35.505 239.76 35.775 ;
     RECT  2.16 36.045 42.444 36.315 ;
     RECT  221.292 36.045 239.76 36.315 ;
     RECT  2.16 36.585 42.444 36.855 ;
     RECT  221.292 36.585 239.76 36.855 ;
     RECT  2.16 37.125 42.444 37.395 ;
     RECT  221.292 37.125 239.76 37.395 ;
     RECT  2.16 37.665 42.444 37.935 ;
     RECT  221.292 37.665 239.76 37.935 ;
     RECT  2.16 38.205 42.444 38.475 ;
     RECT  221.292 38.205 239.76 38.475 ;
     RECT  2.16 38.745 42.444 39.015 ;
     RECT  221.292 38.745 239.76 39.015 ;
     RECT  2.16 39.285 42.444 39.555 ;
     RECT  221.292 39.285 239.76 39.555 ;
     RECT  2.16 39.825 42.444 40.095 ;
     RECT  221.292 39.825 239.76 40.095 ;
     RECT  2.16 40.365 42.444 40.635 ;
     RECT  221.292 40.365 239.76 40.635 ;
     RECT  2.16 40.905 42.444 41.175 ;
     RECT  221.292 40.905 239.76 41.175 ;
     RECT  2.16 41.445 42.444 41.715 ;
     RECT  221.292 41.445 239.76 41.715 ;
     RECT  2.16 41.985 42.444 42.255 ;
     RECT  221.292 41.985 239.76 42.255 ;
     RECT  2.16 42.525 42.444 42.795 ;
     RECT  221.292 42.525 239.76 42.795 ;
     RECT  2.16 43.065 42.444 43.335 ;
     RECT  221.292 43.065 239.76 43.335 ;
     RECT  2.16 43.605 42.444 43.875 ;
     RECT  221.292 43.605 239.76 43.875 ;
     RECT  2.16 44.145 42.444 44.415 ;
     RECT  221.292 44.145 239.76 44.415 ;
     RECT  2.16 44.685 42.444 44.955 ;
     RECT  221.292 44.685 239.76 44.955 ;
     RECT  2.16 45.225 42.444 45.495 ;
     RECT  221.292 45.225 239.76 45.495 ;
     RECT  2.16 45.765 42.444 45.9 ;
     RECT  2.16 45.9 3.402 46.035 ;
     RECT  3.78 45.9 42.444 46.035 ;
     RECT  221.292 45.765 239.76 46.035 ;
     RECT  2.16 46.305 42.444 46.575 ;
     RECT  221.292 46.305 239.76 46.575 ;
     RECT  2.16 46.845 42.444 46.98 ;
     RECT  2.16 46.98 5.562 47.115 ;
     RECT  5.886 46.98 42.444 47.115 ;
     RECT  221.292 46.845 239.76 47.115 ;
     RECT  2.16 47.385 8.802 47.52 ;
     RECT  9.342 47.385 42.444 47.52 ;
     RECT  2.16 47.52 42.444 47.655 ;
     RECT  221.292 47.385 239.76 47.655 ;
     RECT  2.16 47.925 42.444 48.195 ;
     RECT  221.292 47.925 239.76 48.195 ;
     RECT  2.16 48.465 42.444 48.735 ;
     RECT  221.292 48.465 239.76 48.735 ;
     RECT  2.16 49.005 42.444 49.275 ;
     RECT  221.292 49.005 239.76 49.275 ;
     RECT  2.16 49.545 42.444 49.68 ;
     RECT  2.16 49.68 5.67 49.815 ;
     RECT  6.048 49.68 42.444 49.815 ;
     RECT  221.292 49.545 239.76 49.815 ;
     RECT  2.16 50.085 42.444 50.22 ;
     RECT  2.16 50.22 3.618 50.355 ;
     RECT  3.888 50.22 42.444 50.355 ;
     RECT  221.292 50.085 239.76 50.355 ;
     RECT  2.16 50.625 42.444 50.76 ;
     RECT  2.16 50.76 3.51 50.895 ;
     RECT  3.834 50.76 42.444 50.895 ;
     RECT  221.292 50.625 239.76 50.895 ;
     RECT  2.16 51.165 3.78 51.3 ;
     RECT  4.05 51.165 42.444 51.3 ;
     RECT  2.16 51.3 6.156 51.435 ;
     RECT  6.426 51.3 42.444 51.435 ;
     RECT  221.292 51.165 239.76 51.435 ;
     RECT  2.16 51.705 42.444 51.975 ;
     RECT  221.292 51.705 239.76 51.975 ;
     RECT  2.16 52.245 42.444 52.515 ;
     RECT  221.292 52.245 239.76 52.515 ;
     RECT  2.16 52.785 42.444 52.92 ;
     RECT  2.16 52.92 2.646 53.055 ;
     RECT  2.916 52.92 42.444 53.055 ;
     RECT  221.292 52.785 239.76 53.055 ;
     RECT  2.16 53.325 42.444 53.46 ;
     RECT  2.16 53.46 3.672 53.595 ;
     RECT  3.942 53.46 42.444 53.595 ;
     RECT  221.292 53.325 239.76 53.595 ;
     RECT  2.16 53.865 42.444 54 ;
     RECT  2.16 54 6.426 54.135 ;
     RECT  6.696 54 42.444 54.135 ;
     RECT  221.292 53.865 239.76 54.135 ;
     RECT  2.16 54.405 3.618 54.54 ;
     RECT  3.888 54.405 42.444 54.54 ;
     RECT  2.16 54.54 3.726 54.675 ;
     RECT  3.996 54.54 42.444 54.675 ;
     RECT  221.292 54.405 239.76 54.675 ;
     RECT  2.16 54.945 6.75 55.08 ;
     RECT  7.02 54.945 42.444 55.08 ;
     RECT  2.16 55.08 5.886 55.215 ;
     RECT  6.156 55.08 42.444 55.215 ;
     RECT  221.292 54.945 239.76 55.215 ;
     RECT  2.16 55.485 5.886 55.62 ;
     RECT  6.156 55.485 42.444 55.62 ;
     RECT  2.16 55.62 42.444 55.755 ;
     RECT  221.292 55.485 239.76 55.755 ;
     RECT  2.16 56.025 42.444 56.295 ;
     RECT  221.292 56.025 239.76 56.295 ;
     RECT  2.16 56.565 5.67 56.7 ;
     RECT  5.94 56.565 42.444 56.7 ;
     RECT  2.16 56.7 42.444 56.835 ;
     RECT  221.292 56.565 239.76 56.835 ;
     RECT  2.16 57.105 5.4 57.24 ;
     RECT  5.724 57.105 42.444 57.24 ;
     RECT  2.16 57.24 42.444 57.375 ;
     RECT  221.292 57.105 239.76 57.375 ;
     RECT  2.16 57.645 42.444 57.915 ;
     RECT  221.292 57.645 239.76 57.915 ;
     RECT  2.16 58.185 42.444 58.455 ;
     RECT  221.292 58.185 239.76 58.455 ;
     RECT  2.16 58.725 42.444 58.995 ;
     RECT  221.292 58.725 239.76 58.995 ;
     RECT  2.16 59.265 42.444 59.535 ;
     RECT  221.292 59.265 239.76 59.535 ;
     RECT  2.16 59.805 42.444 60.075 ;
     RECT  221.292 59.805 239.76 60.075 ;
     RECT  2.16 60.345 42.444 60.615 ;
     RECT  221.292 60.345 239.76 60.615 ;
     RECT  2.16 60.885 42.444 61.155 ;
     RECT  221.292 60.885 239.76 61.155 ;
     RECT  2.16 61.425 42.444 61.695 ;
     RECT  221.292 61.425 239.76 61.695 ;
     RECT  2.16 61.965 42.444 62.235 ;
     RECT  221.292 61.965 239.76 62.235 ;
     RECT  2.16 62.505 42.444 62.775 ;
     RECT  221.292 62.505 239.76 62.775 ;
     RECT  2.16 63.045 42.444 63.315 ;
     RECT  221.292 63.045 239.76 63.315 ;
     RECT  2.16 63.585 42.444 63.855 ;
     RECT  221.292 63.585 239.76 63.855 ;
     RECT  2.16 64.125 42.444 64.395 ;
     RECT  221.292 64.125 239.76 64.395 ;
     RECT  2.16 64.665 42.444 64.935 ;
     RECT  221.292 64.665 239.76 64.935 ;
     RECT  2.16 65.205 42.444 65.475 ;
     RECT  221.292 65.205 239.76 65.475 ;
     RECT  2.16 65.745 42.444 66.015 ;
     RECT  221.292 65.745 239.76 66.015 ;
     RECT  2.16 66.285 42.444 66.555 ;
     RECT  221.292 66.285 239.76 66.555 ;
     RECT  2.16 66.825 42.444 67.095 ;
     RECT  221.292 66.825 239.76 67.095 ;
     RECT  2.16 67.365 42.444 67.635 ;
     RECT  221.292 67.365 239.76 67.635 ;
     RECT  2.16 67.905 42.444 68.175 ;
     RECT  221.292 67.905 239.76 68.175 ;
     RECT  2.16 68.445 42.444 68.715 ;
     RECT  221.292 68.445 239.76 68.715 ;
     RECT  2.16 68.985 42.444 69.255 ;
     RECT  221.292 68.985 239.76 69.255 ;
     RECT  2.16 69.525 42.444 69.795 ;
     RECT  221.292 69.525 239.76 69.795 ;
     RECT  2.16 70.065 42.444 70.335 ;
     RECT  221.292 70.065 239.76 70.335 ;
     RECT  2.16 70.605 42.444 70.875 ;
     RECT  221.292 70.605 239.76 70.875 ;
     RECT  2.16 71.145 42.444 71.415 ;
     RECT  221.292 71.145 239.76 71.415 ;
     RECT  2.16 71.685 42.444 71.955 ;
     RECT  221.292 71.685 239.76 71.955 ;
     RECT  2.16 72.225 42.444 72.495 ;
     RECT  221.292 72.225 239.76 72.495 ;
     RECT  2.16 72.765 42.444 73.035 ;
     RECT  221.292 72.765 239.76 73.035 ;
     RECT  2.16 73.305 42.444 73.575 ;
     RECT  221.292 73.305 239.76 73.575 ;
     RECT  2.16 73.845 42.444 74.115 ;
     RECT  221.292 73.845 239.76 74.115 ;
     RECT  2.16 74.385 42.444 74.655 ;
     RECT  221.292 74.385 239.76 74.655 ;
     RECT  2.16 74.925 42.444 75.195 ;
     RECT  221.292 74.925 239.76 75.195 ;
     RECT  2.16 75.465 42.444 75.735 ;
     RECT  221.292 75.465 239.76 75.735 ;
     RECT  2.16 76.005 42.444 76.275 ;
     RECT  221.292 76.005 239.76 76.275 ;
     RECT  2.16 76.545 42.444 76.815 ;
     RECT  221.292 76.545 239.76 76.815 ;
     RECT  2.16 77.085 42.444 77.355 ;
     RECT  221.292 77.085 239.76 77.355 ;
     RECT  2.16 77.625 42.444 77.895 ;
     RECT  221.292 77.625 239.76 77.895 ;
     RECT  2.16 78.165 42.444 78.435 ;
     RECT  221.292 78.165 239.76 78.435 ;
     RECT  2.16 78.705 42.444 78.975 ;
     RECT  221.292 78.705 239.76 78.975 ;
     RECT  2.16 79.245 42.444 79.515 ;
     RECT  221.292 79.245 239.76 79.515 ;
     RECT  2.16 79.785 42.444 80.055 ;
     RECT  221.292 79.785 239.76 80.055 ;
     RECT  2.16 80.325 42.444 80.595 ;
     RECT  221.292 80.325 239.76 80.595 ;
     RECT  2.16 80.865 42.444 81.135 ;
     RECT  221.292 80.865 239.76 81.135 ;
     RECT  2.16 81.405 42.444 81.675 ;
     RECT  221.292 81.405 239.76 81.675 ;
     RECT  2.16 81.945 42.444 82.215 ;
     RECT  221.292 81.945 239.76 82.215 ;
     RECT  2.16 82.485 42.444 82.755 ;
     RECT  221.292 82.485 239.76 82.755 ;
     RECT  2.16 83.025 42.444 83.295 ;
     RECT  221.292 83.025 239.76 83.295 ;
     RECT  2.16 83.565 42.444 83.835 ;
     RECT  221.292 83.565 239.76 83.835 ;
     RECT  2.16 84.105 42.444 84.375 ;
     RECT  221.292 84.105 239.76 84.375 ;
     RECT  2.16 84.645 42.444 84.915 ;
     RECT  221.292 84.645 239.76 84.915 ;
     RECT  2.16 85.185 42.444 85.455 ;
     RECT  221.292 85.185 239.76 85.455 ;
     RECT  2.16 85.725 42.444 85.995 ;
     RECT  221.292 85.725 239.76 85.995 ;
     RECT  2.16 86.265 42.444 86.535 ;
     RECT  221.292 86.265 239.76 86.535 ;
     RECT  2.16 86.805 42.444 87.075 ;
     RECT  221.292 86.805 239.76 87.075 ;
     RECT  2.16 87.345 42.444 87.615 ;
     RECT  221.292 87.345 239.76 87.615 ;
     RECT  2.16 87.885 42.444 88.155 ;
     RECT  221.292 87.885 239.76 88.155 ;
     RECT  2.16 88.425 42.444 88.695 ;
     RECT  221.292 88.425 239.76 88.695 ;
     RECT  2.16 88.965 42.444 89.235 ;
     RECT  221.292 88.965 239.76 89.235 ;
     RECT  2.16 89.505 42.444 89.775 ;
     RECT  221.292 89.505 239.76 89.775 ;
     RECT  2.16 90.045 42.444 90.315 ;
     RECT  221.292 90.045 239.76 90.315 ;
     RECT  2.16 90.585 42.444 90.855 ;
     RECT  221.292 90.585 239.76 90.855 ;
     RECT  2.16 91.125 42.444 91.395 ;
     RECT  221.292 91.125 239.76 91.395 ;
     RECT  2.16 91.665 42.444 91.935 ;
     RECT  221.292 91.665 239.76 91.935 ;
     RECT  2.16 92.205 42.444 92.475 ;
     RECT  221.292 92.205 239.76 92.475 ;
     RECT  2.16 92.745 42.444 93.015 ;
     RECT  221.292 92.745 239.76 93.015 ;
     RECT  2.16 93.285 42.444 93.555 ;
     RECT  221.292 93.285 239.76 93.555 ;
     RECT  2.16 93.825 42.444 94.095 ;
     RECT  221.292 93.825 239.76 94.095 ;
     RECT  2.16 94.365 42.444 94.635 ;
     RECT  221.292 94.365 239.76 94.635 ;
     RECT  2.16 94.905 42.444 95.175 ;
     RECT  221.292 94.905 239.76 95.175 ;
     RECT  2.16 95.445 42.444 95.715 ;
     RECT  221.292 95.445 239.76 95.715 ;
     RECT  2.16 95.985 42.444 96.255 ;
     RECT  221.292 95.985 239.76 96.255 ;
     RECT  2.16 96.525 239.76 96.795 ;
     RECT  2.16 97.065 239.76 97.335 ;
     RECT  2.16 97.605 239.76 97.875 ;
     RECT  2.16 98.145 239.76 98.415 ;
     RECT  2.16 98.685 239.76 98.955 ;
     RECT  2.16 99.225 239.76 99.495 ;
     RECT  2.16 99.765 239.76 100.035 ;
     RECT  2.16 100.305 239.76 100.575 ;
     RECT  2.16 100.845 239.76 101.115 ;
     RECT  2.16 101.385 239.76 101.655 ;
     RECT  2.16 101.925 239.76 102.195 ;
     RECT  2.16 102.465 239.76 102.735 ;
     RECT  2.16 103.005 239.76 103.275 ;
     RECT  2.16 103.545 239.76 103.815 ;
     RECT  2.16 104.085 239.76 104.355 ;
     RECT  2.16 104.625 239.76 104.895 ;
     RECT  2.16 105.165 239.76 105.435 ;
     RECT  2.16 105.705 239.76 105.975 ;
     RECT  2.16 106.245 239.76 106.515 ;
     RECT  2.16 106.785 239.76 107.055 ;
     RECT  2.16 107.325 239.76 107.595 ;
     RECT  2.16 107.865 239.76 108.135 ;
     RECT  2.16 108.405 239.76 108.675 ;
     RECT  2.16 108.945 239.76 109.215 ;
     RECT  2.16 109.485 239.76 109.755 ;
     RECT  2.16 110.025 239.76 110.295 ;
     RECT  2.16 110.565 239.76 110.835 ;
     RECT  2.16 111.105 239.76 111.375 ;
     RECT  2.16 111.645 239.76 111.915 ;
     RECT  2.16 112.185 239.76 112.455 ;
     RECT  2.16 112.725 239.76 112.995 ;
     RECT  2.16 113.265 239.76 113.535 ;
     RECT  2.16 113.805 239.76 114.075 ;
     RECT  2.16 114.345 239.76 114.48 ;
    LAYER RVTP ;
     RECT  2.16 2.295 239.76 2.565 ;
     RECT  2.16 2.835 239.76 3.105 ;
     RECT  2.16 3.375 239.76 3.645 ;
     RECT  2.16 3.915 239.76 4.185 ;
     RECT  2.16 4.455 239.76 4.725 ;
     RECT  2.16 4.995 239.76 5.265 ;
     RECT  2.16 5.535 239.76 5.805 ;
     RECT  2.16 6.075 239.76 6.345 ;
     RECT  2.16 6.615 239.76 6.885 ;
     RECT  2.16 7.155 239.76 7.425 ;
     RECT  2.16 7.695 239.76 7.965 ;
     RECT  2.16 8.235 239.76 8.505 ;
     RECT  2.16 8.775 239.76 9.045 ;
     RECT  2.16 9.315 239.76 9.585 ;
     RECT  2.16 9.855 239.76 10.125 ;
     RECT  2.16 10.395 239.76 10.665 ;
     RECT  2.16 10.935 239.76 11.205 ;
     RECT  2.16 11.475 239.76 11.745 ;
     RECT  2.16 12.015 239.76 12.285 ;
     RECT  2.16 12.555 239.76 12.825 ;
     RECT  2.16 13.095 239.76 13.365 ;
     RECT  2.16 13.635 239.76 13.905 ;
     RECT  2.16 14.175 239.76 14.445 ;
     RECT  2.16 14.715 239.76 14.985 ;
     RECT  2.16 15.255 239.76 15.525 ;
     RECT  2.16 15.795 239.76 16.065 ;
     RECT  2.16 16.335 239.76 16.605 ;
     RECT  2.16 16.875 239.76 17.145 ;
     RECT  2.16 17.415 239.76 17.685 ;
     RECT  2.16 17.955 239.76 18.09 ;
     RECT  2.16 18.09 6.696 18.225 ;
     RECT  7.02 18.09 239.76 18.225 ;
     RECT  2.16 18.495 239.76 18.765 ;
     RECT  2.16 19.035 239.76 19.305 ;
     RECT  2.16 19.575 239.76 19.845 ;
     RECT  2.16 20.115 8.1 20.25 ;
     RECT  8.694 20.115 239.76 20.25 ;
     RECT  2.16 20.25 239.76 20.385 ;
     RECT  2.16 20.655 239.76 20.925 ;
     RECT  2.16 21.195 5.4 21.33 ;
     RECT  5.778 21.195 8.1 21.33 ;
     RECT  8.856 21.195 239.76 21.33 ;
     RECT  2.16 21.33 239.76 21.465 ;
     RECT  2.16 21.735 6.912 21.87 ;
     RECT  7.182 21.735 42.444 21.87 ;
     RECT  2.16 21.87 42.444 22.005 ;
     RECT  221.292 21.735 239.76 22.005 ;
     RECT  2.16 22.275 42.444 22.545 ;
     RECT  221.292 22.275 239.76 22.545 ;
     RECT  2.16 22.815 42.444 22.95 ;
     RECT  2.16 22.95 6.804 23.085 ;
     RECT  7.452 22.95 42.444 23.085 ;
     RECT  221.292 22.815 239.76 23.085 ;
     RECT  2.16 23.355 8.478 23.49 ;
     RECT  8.748 23.355 42.444 23.49 ;
     RECT  2.16 23.49 7.83 23.625 ;
     RECT  8.1 23.49 42.444 23.625 ;
     RECT  221.292 23.355 239.76 23.625 ;
     RECT  2.16 23.895 42.444 24.165 ;
     RECT  221.292 23.895 239.76 24.165 ;
     RECT  2.16 24.435 6.858 24.57 ;
     RECT  7.452 24.435 8.532 24.57 ;
     RECT  8.802 24.435 42.444 24.57 ;
     RECT  2.16 24.57 42.444 24.705 ;
     RECT  221.292 24.435 239.76 24.705 ;
     RECT  2.16 24.975 42.444 25.245 ;
     RECT  221.292 24.975 239.76 25.245 ;
     RECT  2.16 25.515 42.444 25.785 ;
     RECT  221.292 25.515 239.76 25.785 ;
     RECT  2.16 26.055 42.444 26.325 ;
     RECT  221.292 26.055 239.76 26.325 ;
     RECT  2.16 26.595 42.444 26.865 ;
     RECT  221.292 26.595 239.76 26.865 ;
     RECT  2.16 27.135 42.444 27.405 ;
     RECT  221.292 27.135 239.76 27.405 ;
     RECT  2.16 27.675 42.444 27.945 ;
     RECT  221.292 27.675 239.76 27.945 ;
     RECT  2.16 28.215 42.444 28.485 ;
     RECT  221.292 28.215 239.76 28.485 ;
     RECT  2.16 28.755 42.444 29.025 ;
     RECT  221.292 28.755 239.76 29.025 ;
     RECT  2.16 29.295 42.444 29.565 ;
     RECT  221.292 29.295 239.76 29.565 ;
     RECT  2.16 29.835 42.444 30.105 ;
     RECT  221.292 29.835 239.76 30.105 ;
     RECT  2.16 30.375 42.444 30.645 ;
     RECT  221.292 30.375 239.76 30.645 ;
     RECT  2.16 30.915 42.444 31.185 ;
     RECT  221.292 30.915 239.76 31.185 ;
     RECT  2.16 31.455 42.444 31.725 ;
     RECT  221.292 31.455 239.76 31.725 ;
     RECT  2.16 31.995 42.444 32.265 ;
     RECT  221.292 31.995 239.76 32.265 ;
     RECT  2.16 32.535 42.444 32.805 ;
     RECT  221.292 32.535 239.76 32.805 ;
     RECT  2.16 33.075 42.444 33.345 ;
     RECT  221.292 33.075 239.76 33.345 ;
     RECT  2.16 33.615 42.444 33.885 ;
     RECT  221.292 33.615 239.76 33.885 ;
     RECT  2.16 34.155 42.444 34.425 ;
     RECT  221.292 34.155 239.76 34.425 ;
     RECT  2.16 34.695 42.444 34.965 ;
     RECT  221.292 34.695 239.76 34.965 ;
     RECT  2.16 35.235 42.444 35.505 ;
     RECT  221.292 35.235 239.76 35.505 ;
     RECT  2.16 35.775 42.444 36.045 ;
     RECT  221.292 35.775 239.76 36.045 ;
     RECT  2.16 36.315 42.444 36.585 ;
     RECT  221.292 36.315 239.76 36.585 ;
     RECT  2.16 36.855 42.444 37.125 ;
     RECT  221.292 36.855 239.76 37.125 ;
     RECT  2.16 37.395 42.444 37.665 ;
     RECT  221.292 37.395 239.76 37.665 ;
     RECT  2.16 37.935 42.444 38.205 ;
     RECT  221.292 37.935 239.76 38.205 ;
     RECT  2.16 38.475 42.444 38.745 ;
     RECT  221.292 38.475 239.76 38.745 ;
     RECT  2.16 39.015 42.444 39.285 ;
     RECT  221.292 39.015 239.76 39.285 ;
     RECT  2.16 39.555 42.444 39.825 ;
     RECT  221.292 39.555 239.76 39.825 ;
     RECT  2.16 40.095 42.444 40.365 ;
     RECT  221.292 40.095 239.76 40.365 ;
     RECT  2.16 40.635 42.444 40.905 ;
     RECT  221.292 40.635 239.76 40.905 ;
     RECT  2.16 41.175 42.444 41.445 ;
     RECT  221.292 41.175 239.76 41.445 ;
     RECT  2.16 41.715 42.444 41.985 ;
     RECT  221.292 41.715 239.76 41.985 ;
     RECT  2.16 42.255 42.444 42.525 ;
     RECT  221.292 42.255 239.76 42.525 ;
     RECT  2.16 42.795 42.444 43.065 ;
     RECT  221.292 42.795 239.76 43.065 ;
     RECT  2.16 43.335 42.444 43.605 ;
     RECT  221.292 43.335 239.76 43.605 ;
     RECT  2.16 43.875 42.444 44.145 ;
     RECT  221.292 43.875 239.76 44.145 ;
     RECT  2.16 44.415 42.444 44.685 ;
     RECT  221.292 44.415 239.76 44.685 ;
     RECT  2.16 44.955 42.444 45.225 ;
     RECT  221.292 44.955 239.76 45.225 ;
     RECT  2.16 45.495 42.444 45.765 ;
     RECT  221.292 45.495 239.76 45.765 ;
     RECT  2.16 46.035 3.402 46.17 ;
     RECT  3.78 46.035 42.444 46.17 ;
     RECT  2.16 46.17 42.444 46.305 ;
     RECT  221.292 46.035 239.76 46.305 ;
     RECT  2.16 46.575 42.444 46.845 ;
     RECT  221.292 46.575 239.76 46.845 ;
     RECT  2.16 47.115 5.562 47.25 ;
     RECT  5.886 47.115 42.444 47.25 ;
     RECT  2.16 47.25 8.802 47.385 ;
     RECT  9.342 47.25 42.444 47.385 ;
     RECT  221.292 47.115 239.76 47.385 ;
     RECT  2.16 47.655 42.444 47.925 ;
     RECT  221.292 47.655 239.76 47.925 ;
     RECT  2.16 48.195 42.444 48.465 ;
     RECT  221.292 48.195 239.76 48.465 ;
     RECT  2.16 48.735 42.444 49.005 ;
     RECT  221.292 48.735 239.76 49.005 ;
     RECT  2.16 49.275 42.444 49.545 ;
     RECT  221.292 49.275 239.76 49.545 ;
     RECT  2.16 49.815 5.67 49.95 ;
     RECT  6.048 49.815 42.444 49.95 ;
     RECT  2.16 49.95 42.444 50.085 ;
     RECT  221.292 49.815 239.76 50.085 ;
     RECT  2.16 50.355 3.618 50.49 ;
     RECT  3.888 50.355 42.444 50.49 ;
     RECT  2.16 50.49 42.444 50.625 ;
     RECT  221.292 50.355 239.76 50.625 ;
     RECT  2.16 50.895 3.51 51.03 ;
     RECT  3.834 50.895 42.444 51.03 ;
     RECT  2.16 51.03 3.78 51.165 ;
     RECT  4.05 51.03 42.444 51.165 ;
     RECT  221.292 50.895 239.76 51.165 ;
     RECT  2.16 51.435 6.156 51.57 ;
     RECT  6.426 51.435 42.444 51.57 ;
     RECT  2.16 51.57 42.444 51.705 ;
     RECT  221.292 51.435 239.76 51.705 ;
     RECT  2.16 51.975 42.444 52.245 ;
     RECT  221.292 51.975 239.76 52.245 ;
     RECT  2.16 52.515 42.444 52.785 ;
     RECT  221.292 52.515 239.76 52.785 ;
     RECT  2.16 53.055 2.646 53.19 ;
     RECT  2.916 53.055 42.444 53.19 ;
     RECT  2.16 53.19 42.444 53.325 ;
     RECT  221.292 53.055 239.76 53.325 ;
     RECT  2.16 53.595 3.672 53.73 ;
     RECT  3.942 53.595 42.444 53.73 ;
     RECT  2.16 53.73 42.444 53.865 ;
     RECT  221.292 53.595 239.76 53.865 ;
     RECT  2.16 54.135 6.426 54.27 ;
     RECT  6.696 54.135 42.444 54.27 ;
     RECT  2.16 54.27 3.618 54.405 ;
     RECT  3.888 54.27 42.444 54.405 ;
     RECT  221.292 54.135 239.76 54.405 ;
     RECT  2.16 54.675 3.726 54.81 ;
     RECT  3.996 54.675 42.444 54.81 ;
     RECT  2.16 54.81 6.75 54.945 ;
     RECT  7.02 54.81 42.444 54.945 ;
     RECT  221.292 54.675 239.76 54.945 ;
     RECT  2.16 55.215 5.886 55.485 ;
     RECT  6.156 55.215 42.444 55.485 ;
     RECT  221.292 55.215 239.76 55.485 ;
     RECT  2.16 55.755 42.444 56.025 ;
     RECT  221.292 55.755 239.76 56.025 ;
     RECT  2.16 56.295 42.444 56.43 ;
     RECT  2.16 56.43 5.67 56.565 ;
     RECT  5.94 56.43 42.444 56.565 ;
     RECT  221.292 56.295 239.76 56.565 ;
     RECT  2.16 56.835 42.444 56.97 ;
     RECT  2.16 56.97 5.4 57.105 ;
     RECT  5.724 56.97 42.444 57.105 ;
     RECT  221.292 56.835 239.76 57.105 ;
     RECT  2.16 57.375 42.444 57.645 ;
     RECT  221.292 57.375 239.76 57.645 ;
     RECT  2.16 57.915 42.444 58.185 ;
     RECT  221.292 57.915 239.76 58.185 ;
     RECT  2.16 58.455 42.444 58.725 ;
     RECT  221.292 58.455 239.76 58.725 ;
     RECT  2.16 58.995 42.444 59.265 ;
     RECT  221.292 58.995 239.76 59.265 ;
     RECT  2.16 59.535 42.444 59.805 ;
     RECT  221.292 59.535 239.76 59.805 ;
     RECT  2.16 60.075 42.444 60.345 ;
     RECT  221.292 60.075 239.76 60.345 ;
     RECT  2.16 60.615 42.444 60.885 ;
     RECT  221.292 60.615 239.76 60.885 ;
     RECT  2.16 61.155 42.444 61.425 ;
     RECT  221.292 61.155 239.76 61.425 ;
     RECT  2.16 61.695 42.444 61.965 ;
     RECT  221.292 61.695 239.76 61.965 ;
     RECT  2.16 62.235 42.444 62.505 ;
     RECT  221.292 62.235 239.76 62.505 ;
     RECT  2.16 62.775 42.444 63.045 ;
     RECT  221.292 62.775 239.76 63.045 ;
     RECT  2.16 63.315 42.444 63.585 ;
     RECT  221.292 63.315 239.76 63.585 ;
     RECT  2.16 63.855 42.444 64.125 ;
     RECT  221.292 63.855 239.76 64.125 ;
     RECT  2.16 64.395 42.444 64.665 ;
     RECT  221.292 64.395 239.76 64.665 ;
     RECT  2.16 64.935 42.444 65.205 ;
     RECT  221.292 64.935 239.76 65.205 ;
     RECT  2.16 65.475 42.444 65.745 ;
     RECT  221.292 65.475 239.76 65.745 ;
     RECT  2.16 66.015 42.444 66.285 ;
     RECT  221.292 66.015 239.76 66.285 ;
     RECT  2.16 66.555 42.444 66.825 ;
     RECT  221.292 66.555 239.76 66.825 ;
     RECT  2.16 67.095 42.444 67.365 ;
     RECT  221.292 67.095 239.76 67.365 ;
     RECT  2.16 67.635 42.444 67.905 ;
     RECT  221.292 67.635 239.76 67.905 ;
     RECT  2.16 68.175 42.444 68.445 ;
     RECT  221.292 68.175 239.76 68.445 ;
     RECT  2.16 68.715 42.444 68.985 ;
     RECT  221.292 68.715 239.76 68.985 ;
     RECT  2.16 69.255 42.444 69.525 ;
     RECT  221.292 69.255 239.76 69.525 ;
     RECT  2.16 69.795 42.444 70.065 ;
     RECT  221.292 69.795 239.76 70.065 ;
     RECT  2.16 70.335 42.444 70.605 ;
     RECT  221.292 70.335 239.76 70.605 ;
     RECT  2.16 70.875 42.444 71.145 ;
     RECT  221.292 70.875 239.76 71.145 ;
     RECT  2.16 71.415 42.444 71.685 ;
     RECT  221.292 71.415 239.76 71.685 ;
     RECT  2.16 71.955 42.444 72.225 ;
     RECT  221.292 71.955 239.76 72.225 ;
     RECT  2.16 72.495 42.444 72.765 ;
     RECT  221.292 72.495 239.76 72.765 ;
     RECT  2.16 73.035 42.444 73.305 ;
     RECT  221.292 73.035 239.76 73.305 ;
     RECT  2.16 73.575 42.444 73.845 ;
     RECT  221.292 73.575 239.76 73.845 ;
     RECT  2.16 74.115 42.444 74.385 ;
     RECT  221.292 74.115 239.76 74.385 ;
     RECT  2.16 74.655 42.444 74.925 ;
     RECT  221.292 74.655 239.76 74.925 ;
     RECT  2.16 75.195 42.444 75.465 ;
     RECT  221.292 75.195 239.76 75.465 ;
     RECT  2.16 75.735 42.444 76.005 ;
     RECT  221.292 75.735 239.76 76.005 ;
     RECT  2.16 76.275 42.444 76.545 ;
     RECT  221.292 76.275 239.76 76.545 ;
     RECT  2.16 76.815 42.444 77.085 ;
     RECT  221.292 76.815 239.76 77.085 ;
     RECT  2.16 77.355 42.444 77.625 ;
     RECT  221.292 77.355 239.76 77.625 ;
     RECT  2.16 77.895 42.444 78.165 ;
     RECT  221.292 77.895 239.76 78.165 ;
     RECT  2.16 78.435 42.444 78.705 ;
     RECT  221.292 78.435 239.76 78.705 ;
     RECT  2.16 78.975 42.444 79.245 ;
     RECT  221.292 78.975 239.76 79.245 ;
     RECT  2.16 79.515 42.444 79.785 ;
     RECT  221.292 79.515 239.76 79.785 ;
     RECT  2.16 80.055 42.444 80.325 ;
     RECT  221.292 80.055 239.76 80.325 ;
     RECT  2.16 80.595 42.444 80.865 ;
     RECT  221.292 80.595 239.76 80.865 ;
     RECT  2.16 81.135 42.444 81.405 ;
     RECT  221.292 81.135 239.76 81.405 ;
     RECT  2.16 81.675 42.444 81.945 ;
     RECT  221.292 81.675 239.76 81.945 ;
     RECT  2.16 82.215 42.444 82.485 ;
     RECT  221.292 82.215 239.76 82.485 ;
     RECT  2.16 82.755 42.444 83.025 ;
     RECT  221.292 82.755 239.76 83.025 ;
     RECT  2.16 83.295 42.444 83.565 ;
     RECT  221.292 83.295 239.76 83.565 ;
     RECT  2.16 83.835 42.444 84.105 ;
     RECT  221.292 83.835 239.76 84.105 ;
     RECT  2.16 84.375 42.444 84.645 ;
     RECT  221.292 84.375 239.76 84.645 ;
     RECT  2.16 84.915 42.444 85.185 ;
     RECT  221.292 84.915 239.76 85.185 ;
     RECT  2.16 85.455 42.444 85.725 ;
     RECT  221.292 85.455 239.76 85.725 ;
     RECT  2.16 85.995 42.444 86.265 ;
     RECT  221.292 85.995 239.76 86.265 ;
     RECT  2.16 86.535 42.444 86.805 ;
     RECT  221.292 86.535 239.76 86.805 ;
     RECT  2.16 87.075 42.444 87.345 ;
     RECT  221.292 87.075 239.76 87.345 ;
     RECT  2.16 87.615 42.444 87.885 ;
     RECT  221.292 87.615 239.76 87.885 ;
     RECT  2.16 88.155 42.444 88.425 ;
     RECT  221.292 88.155 239.76 88.425 ;
     RECT  2.16 88.695 42.444 88.965 ;
     RECT  221.292 88.695 239.76 88.965 ;
     RECT  2.16 89.235 42.444 89.505 ;
     RECT  221.292 89.235 239.76 89.505 ;
     RECT  2.16 89.775 42.444 90.045 ;
     RECT  221.292 89.775 239.76 90.045 ;
     RECT  2.16 90.315 42.444 90.585 ;
     RECT  221.292 90.315 239.76 90.585 ;
     RECT  2.16 90.855 42.444 91.125 ;
     RECT  221.292 90.855 239.76 91.125 ;
     RECT  2.16 91.395 42.444 91.665 ;
     RECT  221.292 91.395 239.76 91.665 ;
     RECT  2.16 91.935 42.444 92.205 ;
     RECT  221.292 91.935 239.76 92.205 ;
     RECT  2.16 92.475 42.444 92.745 ;
     RECT  221.292 92.475 239.76 92.745 ;
     RECT  2.16 93.015 42.444 93.285 ;
     RECT  221.292 93.015 239.76 93.285 ;
     RECT  2.16 93.555 42.444 93.825 ;
     RECT  221.292 93.555 239.76 93.825 ;
     RECT  2.16 94.095 42.444 94.365 ;
     RECT  221.292 94.095 239.76 94.365 ;
     RECT  2.16 94.635 42.444 94.905 ;
     RECT  221.292 94.635 239.76 94.905 ;
     RECT  2.16 95.175 42.444 95.445 ;
     RECT  221.292 95.175 239.76 95.445 ;
     RECT  2.16 95.715 42.444 95.985 ;
     RECT  221.292 95.715 239.76 95.985 ;
     RECT  2.16 96.255 42.444 96.39 ;
     RECT  221.292 96.255 239.76 96.39 ;
     RECT  2.16 96.39 239.76 96.525 ;
     RECT  2.16 96.795 239.76 97.065 ;
     RECT  2.16 97.335 239.76 97.605 ;
     RECT  2.16 97.875 239.76 98.145 ;
     RECT  2.16 98.415 239.76 98.685 ;
     RECT  2.16 98.955 239.76 99.225 ;
     RECT  2.16 99.495 239.76 99.765 ;
     RECT  2.16 100.035 239.76 100.305 ;
     RECT  2.16 100.575 239.76 100.845 ;
     RECT  2.16 101.115 239.76 101.385 ;
     RECT  2.16 101.655 239.76 101.925 ;
     RECT  2.16 102.195 239.76 102.465 ;
     RECT  2.16 102.735 239.76 103.005 ;
     RECT  2.16 103.275 239.76 103.545 ;
     RECT  2.16 103.815 239.76 104.085 ;
     RECT  2.16 104.355 239.76 104.625 ;
     RECT  2.16 104.895 239.76 105.165 ;
     RECT  2.16 105.435 239.76 105.705 ;
     RECT  2.16 105.975 239.76 106.245 ;
     RECT  2.16 106.515 239.76 106.785 ;
     RECT  2.16 107.055 239.76 107.325 ;
     RECT  2.16 107.595 239.76 107.865 ;
     RECT  2.16 108.135 239.76 108.405 ;
     RECT  2.16 108.675 239.76 108.945 ;
     RECT  2.16 109.215 239.76 109.485 ;
     RECT  2.16 109.755 239.76 110.025 ;
     RECT  2.16 110.295 239.76 110.565 ;
     RECT  2.16 110.835 239.76 111.105 ;
     RECT  2.16 111.375 239.76 111.645 ;
     RECT  2.16 111.915 239.76 112.185 ;
     RECT  2.16 112.455 239.76 112.725 ;
     RECT  2.16 112.995 239.76 113.265 ;
     RECT  2.16 113.535 239.76 113.805 ;
     RECT  2.16 114.075 239.76 114.345 ;
    LAYER M1 ;
     RECT  2.16 2.151 239.76 21.609 ;
     RECT  44.496 23.76 219.24 94.248 ;
     RECT  2.16 21.609 42.444 96.381 ;
     RECT  221.292 21.609 239.76 96.381 ;
     RECT  2.16 96.381 239.76 114.489 ;
    LAYER M2 ;
     RECT  0.067 61.974 0.103 61.992 ;
     RECT  0.103 12.834 0.139 15.48 ;
     RECT  0.103 20.862 0.139 23.184 ;
     RECT  0.103 24.642 0.139 24.66 ;
     RECT  0.103 27.072 0.139 29.52 ;
     RECT  0.103 40.302 0.139 41.049 ;
     RECT  0.103 41.922 0.139 41.94 ;
     RECT  0.103 42.732 0.139 42.75 ;
     RECT  0.103 45.81 0.139 47.178 ;
     RECT  0.103 55.8 0.139 55.818 ;
     RECT  0.103 61.902 0.139 63.108 ;
     RECT  0.031 64.098 0.167 64.116 ;
     RECT  0.103 16.38 0.175 18.72 ;
     RECT  0.139 55.26 0.175 55.818 ;
     RECT  0.103 56.61 0.175 57.06 ;
     RECT  0.103 70.542 0.175 70.56 ;
     RECT  0.175 59.04 0.211 59.058 ;
     RECT  0.103 66.222 0.211 66.24 ;
     RECT  0.067 67.14 0.211 67.158 ;
     RECT  0.031 68.652 0.211 68.67 ;
     RECT  0.139 69.462 0.211 69.48 ;
     RECT  0.175 70.272 0.211 70.56 ;
     RECT  0.175 16.38 0.247 18.99 ;
     RECT  0.103 19.782 0.247 19.8 ;
     RECT  0.211 68.652 0.283 69.48 ;
     RECT  0.211 66.222 0.319 67.158 ;
     RECT  0.283 68.382 0.319 69.48 ;
     RECT  0.211 70.272 0.319 70.902 ;
     RECT  0.319 68.382 0.391 70.902 ;
     RECT  0.247 71.73 0.391 71.748 ;
     RECT  0.139 12.258 0.535 15.588 ;
     RECT  0.247 16.38 0.535 19.8 ;
     RECT  0.139 27.072 0.535 29.862 ;
     RECT  0.103 30.852 0.535 30.87 ;
     RECT  0.139 40.302 0.535 42.75 ;
     RECT  0.139 45.27 0.535 47.178 ;
     RECT  0.139 61.47 0.535 63.108 ;
     RECT  0.535 45.27 0.571 47.754 ;
     RECT  0.175 55.26 0.607 57.06 ;
     RECT  0.607 55.26 0.707 57.744 ;
     RECT  0.707 55.26 0.787 57.438 ;
     RECT  0.571 52.29 0.859 52.308 ;
     RECT  0.859 52.29 0.895 52.47 ;
     RECT  0.895 52.254 0.931 52.47 ;
     RECT  0.823 73.89 0.931 73.908 ;
     RECT  0.787 54.612 0.967 57.438 ;
     RECT  0.895 64.944 1.003 64.962 ;
     RECT  0.391 68.382 1.003 71.748 ;
     RECT  0.895 72.504 1.003 72.522 ;
     RECT  0.319 66.222 1.039 67.356 ;
     RECT  1.003 68.382 1.039 72.522 ;
     RECT  0.931 52.254 1.075 52.848 ;
     RECT  0.967 53.91 1.075 57.438 ;
     RECT  1.003 64.944 1.075 65.034 ;
     RECT  1.039 66.222 1.075 72.522 ;
     RECT  0.535 40.302 1.111 43.128 ;
     RECT  0.607 44.19 1.111 44.208 ;
     RECT  0.139 20.7 1.147 24.66 ;
     RECT  0.535 61.47 1.147 63.144 ;
     RECT  0.535 30.852 1.183 30.942 ;
     RECT  0.823 49.212 1.183 49.23 ;
     RECT  0.103 50.022 1.183 50.04 ;
     RECT  0.535 26.91 1.219 29.862 ;
     RECT  1.183 30.618 1.219 30.942 ;
     RECT  1.183 49.212 1.255 50.04 ;
     RECT  1.255 48.816 1.291 50.04 ;
     RECT  1.147 50.832 1.291 50.85 ;
     RECT  1.075 64.944 1.363 72.522 ;
     RECT  0.535 12.258 1.399 19.872 ;
     RECT  1.147 20.628 1.399 24.66 ;
     RECT  1.291 48.816 1.399 50.85 ;
     RECT  1.075 52.254 1.507 57.438 ;
     RECT  1.507 52.182 1.543 57.438 ;
     RECT  1.363 64.944 1.543 72.72 ;
     RECT  0.931 73.782 1.543 73.908 ;
     RECT  0.571 45 1.651 47.754 ;
     RECT  1.399 48.708 1.651 50.85 ;
     RECT  1.543 64.944 1.651 73.908 ;
     RECT  1.435 74.7 1.651 74.718 ;
     RECT  1.219 26.91 1.723 30.942 ;
     RECT  1.111 40.302 1.795 44.208 ;
     RECT  1.651 45 1.795 50.85 ;
     RECT  1.795 40.302 1.831 50.85 ;
     RECT  1.651 64.944 1.903 74.718 ;
     RECT  1.399 75.942 1.903 75.96 ;
     RECT  1.831 40.302 1.975 50.994 ;
     RECT  1.543 52.182 1.975 57.978 ;
     RECT  1.975 40.302 2.083 57.978 ;
     RECT  0.211 59.04 2.083 59.598 ;
     RECT  1.903 64.944 2.083 75.96 ;
     RECT  1.399 12.258 2.16 24.66 ;
     RECT  1.723 26.64 2.16 30.942 ;
     RECT  1.903 33.552 2.16 33.57 ;
     RECT  0.139 39.06 2.16 39.078 ;
     RECT  2.083 40.302 2.16 59.598 ;
     RECT  1.831 60.354 2.16 60.372 ;
     RECT  1.147 61.47 2.16 63.27 ;
     RECT  1.147 64.134 2.16 64.152 ;
     RECT  2.083 64.944 2.16 76.032 ;
     RECT  2.155 77.436 2.16 77.454 ;
     RECT  2.16 2.151 12.163 114.489 ;
     RECT  12.163 2.106 13.711 114.489 ;
     RECT  13.711 2.07 14.819 114.489 ;
     RECT  14.819 2.106 17.743 114.489 ;
     RECT  17.743 2.07 18.859 114.489 ;
     RECT  18.859 2.034 20.695 114.489 ;
     RECT  20.695 1.962 20.975 114.489 ;
     RECT  20.975 2.07 28.975 114.489 ;
     RECT  28.975 1.998 29.083 114.489 ;
     RECT  29.083 1.926 33.647 114.489 ;
     RECT  33.647 1.998 42.444 114.489 ;
     RECT  42.444 1.998 42.575 75.456 ;
     RECT  42.575 65.214 42.611 75.456 ;
     RECT  42.611 65.214 42.647 69.444 ;
     RECT  42.647 65.376 42.683 69.444 ;
     RECT  42.611 70.506 42.719 75.456 ;
     RECT  42.575 1.998 42.791 64.386 ;
     RECT  42.719 70.65 42.791 75.456 ;
     RECT  42.683 65.376 42.827 69.174 ;
     RECT  42.791 1.998 42.971 60.264 ;
     RECT  42.791 70.65 42.971 75.384 ;
     RECT  42.971 1.998 43.007 54.396 ;
     RECT  42.971 70.65 43.007 74.304 ;
     RECT  42.827 65.376 43.079 67.284 ;
     RECT  43.007 70.65 43.115 73.224 ;
     RECT  43.007 74.196 43.151 74.304 ;
     RECT  43.115 70.65 43.187 70.668 ;
     RECT  42.791 61.398 43.223 64.386 ;
     RECT  43.223 61.434 43.259 64.386 ;
     RECT  43.007 1.998 43.331 54.324 ;
     RECT  43.259 61.596 43.331 64.386 ;
     RECT  42.971 75.366 43.331 75.384 ;
     RECT  43.331 24.714 43.367 54.324 ;
     RECT  43.367 29.034 43.403 39.348 ;
     RECT  43.151 74.196 43.403 74.214 ;
     RECT  43.403 29.106 43.439 39.348 ;
     RECT  42.971 55.224 43.475 60.264 ;
     RECT  43.367 40.374 43.583 54.324 ;
     RECT  43.583 40.374 43.619 51.084 ;
     RECT  43.115 71.496 43.619 73.224 ;
     RECT  43.583 52.182 43.655 54.324 ;
     RECT  42.827 68.076 43.655 69.174 ;
     RECT  43.655 69.03 43.691 69.174 ;
     RECT  43.439 29.196 43.727 30.474 ;
     RECT  43.331 61.776 43.727 63.954 ;
     RECT  43.655 52.182 43.763 53.928 ;
     RECT  43.331 1.998 44.496 23.886 ;
     RECT  43.367 24.714 44.496 28.206 ;
     RECT  43.727 29.574 44.496 30.474 ;
     RECT  43.439 31.266 44.496 39.348 ;
     RECT  43.619 40.374 44.496 50.994 ;
     RECT  43.763 52.326 44.496 53.928 ;
     RECT  43.475 55.224 44.496 55.782 ;
     RECT  43.475 56.61 44.496 60.264 ;
     RECT  43.727 61.776 44.496 63.576 ;
     RECT  43.079 65.376 44.496 66.888 ;
     RECT  43.655 68.076 44.496 68.094 ;
     RECT  43.691 69.03 44.496 69.048 ;
     RECT  43.619 71.496 44.496 72.414 ;
     RECT  43.619 73.206 44.496 73.224 ;
     RECT  44.496 1.998 46.463 94.248 ;
     RECT  46.463 2.151 219.24 94.248 ;
     RECT  219.24 2.151 219.371 31.374 ;
     RECT  219.371 25.866 219.623 31.374 ;
     RECT  219.24 34.506 220.027 36.414 ;
     RECT  220.027 34.506 220.099 37.044 ;
     RECT  219.623 25.866 220.387 29.394 ;
     RECT  219.623 30.186 220.387 31.374 ;
     RECT  219.371 2.151 220.603 25.074 ;
     RECT  220.387 25.866 220.603 31.374 ;
     RECT  219.24 38.412 221.143 64.314 ;
     RECT  220.099 34.506 221.179 37.314 ;
     RECT  221.143 38.25 221.179 64.314 ;
     RECT  220.027 33.516 221.287 33.534 ;
     RECT  221.179 34.506 221.287 64.314 ;
     RECT  220.603 2.151 221.292 31.374 ;
     RECT  221.287 33.516 221.292 64.314 ;
     RECT  220.027 65.142 221.292 65.16 ;
     RECT  42.444 96.381 221.292 114.489 ;
     RECT  221.292 2.151 239.76 114.489 ;
     RECT  239.76 40.914 239.891 47.214 ;
     RECT  239.891 40.914 239.927 47.142 ;
     RECT  239.76 21.546 239.999 40.014 ;
     RECT  239.927 42.534 239.999 47.034 ;
     RECT  239.999 23.706 240.467 40.014 ;
     RECT  239.999 42.606 240.503 47.034 ;
     RECT  240.467 23.706 240.539 35.496 ;
     RECT  240.467 36.486 240.539 40.014 ;
     RECT  240.503 42.606 240.539 46.602 ;
     RECT  240.539 24.246 240.575 35.496 ;
     RECT  239.927 40.914 240.575 41.742 ;
     RECT  240.539 45.666 240.575 46.602 ;
     RECT  240.575 24.246 240.611 35.424 ;
     RECT  240.539 42.606 240.611 43.704 ;
     RECT  240.611 42.696 240.683 43.704 ;
     RECT  240.539 36.486 240.827 36.504 ;
     RECT  240.539 37.296 240.971 40.014 ;
     RECT  240.611 24.246 241.043 27.666 ;
     RECT  241.043 24.246 241.115 24.462 ;
     RECT  240.611 28.836 241.115 35.424 ;
     RECT  240.683 42.696 241.115 42.714 ;
     RECT  240.539 44.586 241.115 44.604 ;
     RECT  239.999 21.546 241.151 22.914 ;
     RECT  241.043 25.326 241.151 27.666 ;
     RECT  240.971 37.638 241.151 40.014 ;
     RECT  240.575 40.914 241.151 41.202 ;
     RECT  240.575 46.584 241.151 46.602 ;
     RECT  241.151 41.184 241.187 41.202 ;
     RECT  241.151 21.636 241.223 22.914 ;
     RECT  241.151 26.136 241.223 27.468 ;
     RECT  241.223 22.716 241.259 22.914 ;
     RECT  241.223 26.568 241.295 27.468 ;
     RECT  241.151 39.186 241.727 40.014 ;
     RECT  241.259 22.716 241.763 22.806 ;
     RECT  241.115 33.246 241.763 35.424 ;
     RECT  241.727 39.186 241.763 39.204 ;
     RECT  241.115 28.836 241.799 30.438 ;
     RECT  241.115 31.194 241.799 31.914 ;
     RECT  241.763 34.326 241.799 34.344 ;
     RECT  241.763 35.244 241.799 35.424 ;
     RECT  241.151 37.638 241.799 38.304 ;
     RECT  241.763 22.788 241.835 22.806 ;
     RECT  241.295 26.568 241.835 27.126 ;
     RECT  241.799 28.836 241.835 28.854 ;
     RECT  241.799 30.186 241.835 30.204 ;
     RECT  241.799 31.194 241.835 31.446 ;
     RECT  241.763 33.246 241.835 33.264 ;
     RECT  241.799 35.244 241.835 35.262 ;
     RECT  241.799 37.638 241.835 37.656 ;
     RECT  240.683 43.686 241.835 43.704 ;
     RECT  240.575 45.666 241.835 45.684 ;
     RECT  241.223 21.636 241.907 21.654 ;
     RECT  241.807 24.21 241.907 24.228 ;
     RECT  241.771 36.441 241.907 36.459 ;
     RECT  241.727 39.996 241.907 40.014 ;
    LAYER M3 ;
     RECT  13.212 0.043 13.23 0.187 ;
     RECT  13.212 0.187 13.338 0.235 ;
     RECT  12.816 0.235 13.338 0.283 ;
     RECT  12.816 0.283 13.842 0.317 ;
     RECT  13.68 0.317 13.842 0.475 ;
     RECT  13.68 0.475 13.95 0.523 ;
     RECT  14.868 0.283 14.886 0.571 ;
     RECT  13.68 0.523 14.058 1.051 ;
     RECT  13.644 1.051 14.058 1.099 ;
     RECT  12.816 0.317 12.834 1.147 ;
     RECT  13.572 1.099 14.058 1.147 ;
     RECT  14.868 0.571 15.246 1.147 ;
     RECT  16.056 0.571 16.074 1.147 ;
     RECT  12.816 1.147 16.398 1.723 ;
     RECT  12.816 1.723 16.902 1.771 ;
     RECT  12.816 1.771 17.226 1.819 ;
     RECT  12.816 1.819 17.838 1.867 ;
     RECT  29.088 1.921 29.106 1.993 ;
     RECT  33.624 1.921 33.642 1.993 ;
     RECT  46.44 1.993 46.458 2.059 ;
     RECT  18.864 2.029 18.882 2.065 ;
     RECT  20.7 1.957 20.97 2.093 ;
     RECT  12.816 1.867 17.91 2.101 ;
     RECT  18.864 2.065 19.314 2.101 ;
     RECT  34.956 2.065 34.974 2.101 ;
     RECT  12.168 2.101 17.91 2.143 ;
     RECT  18.864 2.101 19.674 2.143 ;
     RECT  28.98 1.993 29.106 2.143 ;
     RECT  45.468 2.029 45.486 2.143 ;
     RECT  88.992 2.059 89.01 2.143 ;
     RECT  32.976 1.993 33.642 2.191 ;
     RECT  34.776 2.101 34.974 2.191 ;
     RECT  38.736 2.101 38.754 2.191 ;
     RECT  99.615 2.143 99.705 2.191 ;
     RECT  110.415 2.143 110.505 2.191 ;
     RECT  30.888 2.065 30.906 2.227 ;
     RECT  31.824 2.191 33.642 2.227 ;
     RECT  42.516 2.101 42.894 2.227 ;
     RECT  45.468 2.143 45.705 2.227 ;
     RECT  46.44 2.059 47.07 2.227 ;
     RECT  99.504 2.191 99.81 2.237 ;
     RECT  110.304 2.191 110.61 2.237 ;
     RECT  112.284 2.191 112.626 2.237 ;
     RECT  12.168 2.143 19.674 2.251 ;
     RECT  25.308 2.191 25.326 2.263 ;
     RECT  34.776 2.191 35.226 2.263 ;
     RECT  38.736 2.191 39.33 2.263 ;
     RECT  112.608 2.237 112.626 2.285 ;
     RECT  30.888 2.227 33.642 2.293 ;
     RECT  25.308 2.263 25.542 2.299 ;
     RECT  42.372 2.227 42.894 2.299 ;
     RECT  44.064 2.227 44.082 2.299 ;
     RECT  45.468 2.227 47.07 2.299 ;
     RECT  48.492 2.191 48.51 2.299 ;
     RECT  37.944 2.263 39.33 2.335 ;
     RECT  45.36 2.299 47.07 2.335 ;
     RECT  41.724 2.299 42.894 2.347 ;
     RECT  43.632 2.299 44.082 2.347 ;
     RECT  45.324 2.335 47.07 2.347 ;
     RECT  12.168 2.251 19.854 2.371 ;
     RECT  20.7 2.093 20.898 2.371 ;
     RECT  25.308 2.299 26.226 2.371 ;
     RECT  37.836 2.335 39.402 2.371 ;
     RECT  40.215 2.143 40.305 2.371 ;
     RECT  41.724 2.347 44.082 2.371 ;
     RECT  44.856 2.347 47.07 2.371 ;
     RECT  51.015 2.143 51.105 2.371 ;
     RECT  2.415 2.143 2.505 2.413 ;
     RECT  7.815 2.143 7.905 2.413 ;
     RECT  24.015 2.143 24.105 2.413 ;
     RECT  24.876 2.371 26.226 2.413 ;
     RECT  28.98 2.143 29.505 2.413 ;
     RECT  37.836 2.371 40.305 2.413 ;
     RECT  51.015 2.371 51.174 2.413 ;
     RECT  56.415 2.143 56.505 2.413 ;
     RECT  61.815 2.143 61.905 2.413 ;
     RECT  67.215 2.143 67.305 2.413 ;
     RECT  72.615 2.143 72.705 2.413 ;
     RECT  78.015 2.143 78.105 2.413 ;
     RECT  83.415 2.143 83.505 2.413 ;
     RECT  88.815 2.143 89.01 2.413 ;
     RECT  94.215 2.143 94.305 2.413 ;
     RECT  99.615 2.237 99.81 2.413 ;
     RECT  105.015 2.143 105.105 2.413 ;
     RECT  110.415 2.237 110.61 2.413 ;
     RECT  115.815 2.143 115.905 2.413 ;
     RECT  121.215 2.143 121.305 2.413 ;
     RECT  126.615 2.143 126.705 2.413 ;
     RECT  132.015 2.143 132.105 2.413 ;
     RECT  137.415 2.143 137.505 2.413 ;
     RECT  142.815 2.143 142.905 2.413 ;
     RECT  148.215 2.143 148.305 2.413 ;
     RECT  153.615 2.143 153.705 2.413 ;
     RECT  159.015 2.143 159.105 2.413 ;
     RECT  164.415 2.143 164.505 2.413 ;
     RECT  169.815 2.143 169.905 2.413 ;
     RECT  175.215 2.143 175.305 2.413 ;
     RECT  180.615 2.143 180.705 2.413 ;
     RECT  186.015 2.143 186.105 2.413 ;
     RECT  191.415 2.143 191.505 2.413 ;
     RECT  196.815 2.143 196.905 2.413 ;
     RECT  202.215 2.143 202.305 2.413 ;
     RECT  207.615 2.143 207.705 2.413 ;
     RECT  213.015 2.143 213.105 2.413 ;
     RECT  218.415 2.143 218.505 2.413 ;
     RECT  223.815 2.143 223.905 2.413 ;
     RECT  229.215 2.143 229.305 2.413 ;
     RECT  234.615 2.143 234.705 2.413 ;
     RECT  88.02 2.371 88.038 2.443 ;
     RECT  30.852 2.293 33.642 2.461 ;
     RECT  87.732 2.443 88.038 2.489 ;
     RECT  48.492 2.299 48.798 2.497 ;
     RECT  51.015 2.413 51.297 2.497 ;
     RECT  88.02 2.489 88.038 2.525 ;
     RECT  47.952 2.497 48.798 2.533 ;
     RECT  30.852 2.461 33.714 2.539 ;
     RECT  28.98 2.413 29.697 2.569 ;
     RECT  37.836 2.413 40.497 2.569 ;
     RECT  50.256 2.371 50.274 2.569 ;
     RECT  51.015 2.497 51.606 2.569 ;
     RECT  27.252 2.497 27.27 2.605 ;
     RECT  28.476 2.569 29.697 2.605 ;
     RECT  30.708 2.539 33.714 2.605 ;
     RECT  27.252 2.605 27.558 2.641 ;
     RECT  28.476 2.605 33.714 2.641 ;
     RECT  37.62 2.569 40.497 2.641 ;
     RECT  41.22 2.371 47.07 2.641 ;
     RECT  47.88 2.533 48.798 2.641 ;
     RECT  50.256 2.569 51.606 2.641 ;
     RECT  22.32 2.569 22.338 2.731 ;
     RECT  34.776 2.263 35.442 2.731 ;
     RECT  37.62 2.641 48.798 2.731 ;
     RECT  50.256 2.641 51.894 2.731 ;
     RECT  22.32 2.731 22.806 2.767 ;
     RECT  27.108 2.641 33.714 2.803 ;
     RECT  24.015 2.413 26.226 2.827 ;
     RECT  11.916 2.371 20.898 2.839 ;
     RECT  22.248 2.767 22.806 2.839 ;
     RECT  23.796 2.827 26.226 2.839 ;
     RECT  37.62 2.731 51.894 2.839 ;
     RECT  52.704 2.371 52.722 2.839 ;
     RECT  36.936 2.839 51.894 2.869 ;
     RECT  52.704 2.839 53.046 2.869 ;
     RECT  11.916 2.839 21.33 2.875 ;
     RECT  22.248 2.839 26.226 2.875 ;
     RECT  27.108 2.803 34.002 2.875 ;
     RECT  34.74 2.731 35.442 2.875 ;
     RECT  36.936 2.869 53.046 2.875 ;
     RECT  11.916 2.875 26.226 2.911 ;
     RECT  27.108 2.875 35.442 2.911 ;
     RECT  36.684 2.875 53.262 2.911 ;
     RECT  11.916 2.911 35.442 3.073 ;
     RECT  11.916 3.073 35.946 3.407 ;
     RECT  11.916 3.407 35.55 3.649 ;
     RECT  36.684 2.911 53.694 3.721 ;
     RECT  36.684 3.721 54.126 3.811 ;
     RECT  11.844 3.649 35.55 3.983 ;
     RECT  36.54 3.811 54.126 4.189 ;
     RECT  28.764 3.983 35.55 4.225 ;
     RECT  36.36 4.189 54.126 4.225 ;
     RECT  28.764 4.225 54.126 4.531 ;
     RECT  11.916 3.983 28.026 4.721 ;
     RECT  28.764 4.531 54.162 4.765 ;
     RECT  12.024 4.721 28.026 4.891 ;
     RECT  28.764 4.765 54.558 4.891 ;
     RECT  55.404 4.801 55.422 4.891 ;
     RECT  12.024 4.891 55.422 5.099 ;
     RECT  12.024 5.099 55.242 5.117 ;
     RECT  67.215 2.413 67.497 5.467 ;
     RECT  69.12 5.431 69.138 5.501 ;
     RECT  67.215 5.467 68.022 5.504 ;
     RECT  46.944 5.117 55.242 5.603 ;
     RECT  46.944 5.603 55.098 5.729 ;
     RECT  11.016 5.755 11.034 5.809 ;
     RECT  12.024 5.117 46.206 5.845 ;
     RECT  46.944 5.729 55.062 5.845 ;
     RECT  61.815 2.413 62.097 5.851 ;
     RECT  10.332 5.809 11.034 5.881 ;
     RECT  12.024 5.845 55.062 5.881 ;
     RECT  10.08 5.881 55.062 5.999 ;
     RECT  10.08 5.999 54.594 6.077 ;
     RECT  106.596 6.043 106.614 6.173 ;
     RECT  9.18 6.007 9.198 6.421 ;
     RECT  10.08 6.077 33.642 6.421 ;
     RECT  9.18 6.421 33.642 6.817 ;
     RECT  34.38 6.077 54.594 6.853 ;
     RECT  105.015 2.413 105.297 6.859 ;
     RECT  9.036 6.817 33.642 6.907 ;
     RECT  34.38 6.853 54.63 6.907 ;
     RECT  56.415 2.413 56.697 6.952 ;
     RECT  67.215 5.504 67.497 6.952 ;
     RECT  78.015 2.413 78.297 6.952 ;
     RECT  88.815 2.413 89.097 6.952 ;
     RECT  99.615 2.413 99.897 6.952 ;
     RECT  7.815 2.413 8.097 7.051 ;
     RECT  9.036 6.907 54.63 7.079 ;
     RECT  102.708 6.955 102.726 7.195 ;
     RECT  108.576 6.907 108.594 7.195 ;
     RECT  102.6 7.195 102.726 7.229 ;
     RECT  104.94 6.859 105.297 7.231 ;
     RECT  7.776 7.051 8.097 7.321 ;
     RECT  56.304 6.952 56.697 7.321 ;
     RECT  56.124 7.321 56.697 7.393 ;
     RECT  102.6 7.229 102.618 7.421 ;
     RECT  106.2 7.195 106.326 7.421 ;
     RECT  9.036 7.079 33.894 7.465 ;
     RECT  55.98 7.393 56.697 7.465 ;
     RECT  121.215 2.413 121.497 7.483 ;
     RECT  7.308 7.321 8.097 7.501 ;
     RECT  8.82 7.465 33.894 7.501 ;
     RECT  55.62 7.465 56.697 7.501 ;
     RECT  67.104 6.952 67.497 7.529 ;
     RECT  77.904 6.952 78.297 7.529 ;
     RECT  88.704 6.952 89.097 7.529 ;
     RECT  99.504 6.952 99.897 7.529 ;
     RECT  121.104 7.483 121.497 7.529 ;
     RECT  104.58 7.231 105.297 7.627 ;
     RECT  106.2 7.421 106.218 7.627 ;
     RECT  130.536 7.483 130.554 7.661 ;
     RECT  34.668 7.079 54.63 7.675 ;
     RECT  55.62 7.501 56.826 7.675 ;
     RECT  34.668 7.675 56.826 7.699 ;
     RECT  57.564 7.675 57.69 7.699 ;
     RECT  137.415 2.413 137.697 7.723 ;
     RECT  148.215 2.413 148.497 7.771 ;
     RECT  7.308 7.501 33.894 7.861 ;
     RECT  34.668 7.699 57.69 7.861 ;
     RECT  150.984 7.735 151.002 7.867 ;
     RECT  58.5 7.861 58.518 7.901 ;
     RECT  7.308 7.861 57.69 7.949 ;
     RECT  150.48 7.867 151.002 7.997 ;
     RECT  102.096 8.011 102.114 8.041 ;
     RECT  70.02 5.071 70.038 8.155 ;
     RECT  101.988 8.041 102.114 8.155 ;
     RECT  102.996 8.011 103.014 8.155 ;
     RECT  94.215 2.413 94.497 8.203 ;
     RECT  69.588 8.155 70.038 8.251 ;
     RECT  59.4 6.385 59.418 8.347 ;
     RECT  61.344 5.851 62.097 8.347 ;
     RECT  67.215 7.529 67.497 8.347 ;
     RECT  72.615 2.413 72.897 8.395 ;
     RECT  78.015 7.529 78.297 8.395 ;
     RECT  83.415 2.413 83.697 8.395 ;
     RECT  88.815 7.529 89.097 8.395 ;
     RECT  99.615 7.529 99.897 8.395 ;
     RECT  107.928 7.195 108.594 8.395 ;
     RECT  69.588 8.251 70.722 8.429 ;
     RECT  83.415 8.395 83.79 8.435 ;
     RECT  88.815 8.395 89.19 8.435 ;
     RECT  93.6 8.203 94.59 8.435 ;
     RECT  99.615 8.395 99.99 8.435 ;
     RECT  58.716 8.347 59.418 8.477 ;
     RECT  61.344 8.347 62.73 8.477 ;
     RECT  67.215 8.347 67.662 8.477 ;
     RECT  70.02 8.429 70.722 8.477 ;
     RECT  222.3 8.299 222.318 8.477 ;
     RECT  107.748 8.395 108.594 8.491 ;
     RECT  104.58 7.627 106.218 8.509 ;
     RECT  72.615 8.395 72.99 8.581 ;
     RECT  74.268 8.251 74.286 8.581 ;
     RECT  7.308 7.949 41.886 8.707 ;
     RECT  42.624 7.949 57.006 8.707 ;
     RECT  104.4 8.509 106.218 8.779 ;
     RECT  137.415 7.723 137.862 8.827 ;
     RECT  7.308 8.707 57.006 8.851 ;
     RECT  78.015 8.395 78.39 8.971 ;
     RECT  80.784 8.941 80.802 9.005 ;
     RECT  107.64 8.491 108.594 9.013 ;
     RECT  109.548 8.311 109.566 9.013 ;
     RECT  78.015 8.971 78.462 9.041 ;
     RECT  78.015 9.041 78.39 9.053 ;
     RECT  79.2 8.941 79.218 9.053 ;
     RECT  7.128 8.851 57.258 9.085 ;
     RECT  67.215 8.477 67.497 9.112 ;
     RECT  78.015 9.053 78.297 9.112 ;
     RECT  88.815 8.435 89.097 9.112 ;
     RECT  99.615 8.435 99.897 9.112 ;
     RECT  121.215 7.529 121.497 9.112 ;
     RECT  132.015 2.413 132.297 9.112 ;
     RECT  79.884 9.067 79.902 9.113 ;
     RECT  142.815 2.413 143.097 9.115 ;
     RECT  67.104 9.112 67.497 9.149 ;
     RECT  153.615 2.413 153.897 9.211 ;
     RECT  164.415 2.413 164.697 9.211 ;
     RECT  175.215 2.413 175.497 9.211 ;
     RECT  186.015 2.413 186.297 9.211 ;
     RECT  196.815 2.413 197.097 9.211 ;
     RECT  207.615 2.413 207.897 9.211 ;
     RECT  218.415 2.413 218.697 9.211 ;
     RECT  175.104 9.211 175.497 9.248 ;
     RECT  185.904 9.211 186.297 9.248 ;
     RECT  196.704 9.211 197.097 9.248 ;
     RECT  207.504 9.211 207.897 9.248 ;
     RECT  83.415 8.435 83.697 9.307 ;
     RECT  218.304 9.211 218.697 9.341 ;
     RECT  7.092 9.085 57.258 9.355 ;
     RECT  107.64 9.013 109.566 9.355 ;
     RECT  101.988 8.155 103.014 9.391 ;
     RECT  99.504 9.112 99.897 9.451 ;
     RECT  110.415 2.413 110.697 9.451 ;
     RECT  115.815 2.413 116.097 9.451 ;
     RECT  121.104 9.112 121.497 9.451 ;
     RECT  125.244 7.675 125.262 9.451 ;
     RECT  131.904 9.112 132.297 9.451 ;
     RECT  6.984 9.355 57.258 9.481 ;
     RECT  114.444 7.435 114.462 9.481 ;
     RECT  114.444 9.481 115.038 9.499 ;
     RECT  83.415 9.307 83.79 9.509 ;
     RECT  110.415 9.451 110.79 9.509 ;
     RECT  121.104 9.451 121.59 9.509 ;
     RECT  125.244 9.451 125.658 9.509 ;
     RECT  131.904 9.451 132.498 9.509 ;
     RECT  113.904 9.499 115.038 9.533 ;
     RECT  68.976 9.499 68.994 9.545 ;
     RECT  82.656 9.544 82.674 9.581 ;
     RECT  99.504 9.451 99.99 9.581 ;
     RECT  116.928 9.544 116.946 9.581 ;
     RECT  118.044 9.481 118.062 9.581 ;
     RECT  59.4 8.477 59.418 9.589 ;
     RECT  133.596 7.147 133.614 9.589 ;
     RECT  136.908 8.827 137.862 9.589 ;
     RECT  150.984 7.997 151.002 9.589 ;
     RECT  6.552 9.481 57.258 9.625 ;
     RECT  59.4 9.589 59.598 9.625 ;
     RECT  60.408 9.595 60.426 9.625 ;
     RECT  113.904 9.533 114.93 9.625 ;
     RECT  148.215 7.771 148.554 9.625 ;
     RECT  70.02 8.477 70.038 9.643 ;
     RECT  104.4 8.779 106.614 9.661 ;
     RECT  133.416 9.589 133.614 9.661 ;
     RECT  229.215 2.413 229.497 9.661 ;
     RECT  59.4 9.625 60.426 9.689 ;
     RECT  70.02 9.643 70.074 9.689 ;
     RECT  77.904 9.112 78.297 9.689 ;
     RECT  88.704 9.112 89.097 9.689 ;
     RECT  99.504 9.581 99.897 9.689 ;
     RECT  118.584 9.589 118.602 9.689 ;
     RECT  121.104 9.509 121.497 9.689 ;
     RECT  130.536 9.589 130.554 9.689 ;
     RECT  131.904 9.509 132.297 9.689 ;
     RECT  136.908 9.589 138.546 9.689 ;
     RECT  150.48 9.589 151.002 9.689 ;
     RECT  153.504 9.211 153.897 9.689 ;
     RECT  162.468 9.589 162.486 9.689 ;
     RECT  164.304 9.211 164.697 9.689 ;
     RECT  6.552 9.625 57.33 9.739 ;
     RECT  115.815 9.451 116.19 9.787 ;
     RECT  117.828 9.751 117.846 9.821 ;
     RECT  115.815 9.787 116.73 9.824 ;
     RECT  107.604 9.355 109.566 9.835 ;
     RECT  110.415 9.509 110.697 9.835 ;
     RECT  133.344 9.661 133.614 9.859 ;
     RECT  101.772 9.391 103.014 9.895 ;
     RECT  5.652 9.895 5.67 9.931 ;
     RECT  5.652 9.931 5.814 9.965 ;
     RECT  6.552 9.739 57.942 10.021 ;
     RECT  123.408 7.339 123.426 10.021 ;
     RECT  148.215 9.625 148.806 10.021 ;
     RECT  171.036 9.835 171.054 10.021 ;
     RECT  166.464 9.835 166.482 10.027 ;
     RECT  159.015 2.413 159.297 10.057 ;
     RECT  230.508 9.085 230.526 10.057 ;
     RECT  6.552 10.021 58.41 10.061 ;
     RECT  59.4 9.689 59.742 10.075 ;
     RECT  122.328 10.021 122.346 10.109 ;
     RECT  123.408 10.021 123.462 10.109 ;
     RECT  230.292 10.057 230.526 10.123 ;
     RECT  230.292 10.123 230.67 10.129 ;
     RECT  166.464 10.027 166.59 10.157 ;
     RECT  171.036 10.021 171.414 10.157 ;
     RECT  225.36 9.625 225.378 10.165 ;
     RECT  77.076 10.093 77.094 10.171 ;
     RECT  230.292 10.129 231.282 10.171 ;
     RECT  6.552 10.061 57.762 10.349 ;
     RECT  57.744 10.349 57.762 10.391 ;
     RECT  125.244 9.509 125.262 10.399 ;
     RECT  146.304 10.093 146.322 10.399 ;
     RECT  91.152 9.859 91.17 10.435 ;
     RECT  146.232 10.399 146.358 10.435 ;
     RECT  148.215 10.021 148.842 10.435 ;
     RECT  133.344 9.859 133.65 10.471 ;
     RECT  99.615 9.689 99.897 10.561 ;
     RECT  107.604 9.835 110.697 10.561 ;
     RECT  133.344 10.471 133.902 10.561 ;
     RECT  228.96 9.661 229.497 10.561 ;
     RECT  230.256 10.171 231.282 10.561 ;
     RECT  72.615 8.581 74.286 10.597 ;
     RECT  98.568 9.895 98.586 10.597 ;
     RECT  186.015 9.248 186.297 10.597 ;
     RECT  118.404 10.411 118.422 10.603 ;
     RECT  225.36 10.165 225.99 10.633 ;
     RECT  100.728 10.597 100.818 10.637 ;
     RECT  118.296 10.603 118.422 10.637 ;
     RECT  72.615 10.597 74.502 10.669 ;
     RECT  100.8 10.637 100.818 10.697 ;
     RECT  101.772 9.895 103.158 10.699 ;
     RECT  104.004 9.661 106.614 10.699 ;
     RECT  228.96 10.561 231.282 10.699 ;
     RECT  4.824 10.561 4.842 10.705 ;
     RECT  5.796 9.965 5.814 10.705 ;
     RECT  227.016 10.669 227.034 10.705 ;
     RECT  227.772 10.435 227.79 10.705 ;
     RECT  4.824 10.705 5.814 10.741 ;
     RECT  6.552 10.349 57.006 10.741 ;
     RECT  101.772 10.699 106.614 10.741 ;
     RECT  228.708 10.699 231.282 10.741 ;
     RECT  67.215 9.149 67.497 10.831 ;
     RECT  78.015 9.689 78.297 10.831 ;
     RECT  88.815 9.689 89.097 10.831 ;
     RECT  99.612 10.561 99.897 10.831 ;
     RECT  101.772 10.741 106.686 10.831 ;
     RECT  227.016 10.705 227.79 10.975 ;
     RECT  59.148 10.075 59.742 10.987 ;
     RECT  63.612 10.057 63.63 10.987 ;
     RECT  4.032 10.975 4.05 11.011 ;
     RECT  4.824 10.741 57.006 11.011 ;
     RECT  101.7 10.831 106.758 11.011 ;
     RECT  63.252 10.987 63.63 11.101 ;
     RECT  136.908 9.689 137.862 11.101 ;
     RECT  146.124 10.435 146.358 11.101 ;
     RECT  63.252 11.101 63.846 11.165 ;
     RECT  63.252 11.165 63.81 11.173 ;
     RECT  88.704 10.831 89.097 11.173 ;
     RECT  142.128 9.115 143.097 11.173 ;
     RECT  150.984 9.689 151.002 11.173 ;
     RECT  159.015 10.057 159.462 11.173 ;
     RECT  227.016 10.975 227.898 11.173 ;
     RECT  228.708 10.741 231.354 11.173 ;
     RECT  87.264 10.363 87.282 11.179 ;
     RECT  218.415 9.341 218.697 11.179 ;
     RECT  135.936 10.561 135.954 11.209 ;
     RECT  136.908 11.101 138.186 11.209 ;
     RECT  144.792 10.093 144.81 11.209 ;
     RECT  146.124 11.101 146.43 11.209 ;
     RECT  225.36 10.633 226.062 11.209 ;
     RECT  227.016 11.173 231.354 11.209 ;
     RECT  115.815 9.824 116.334 11.227 ;
     RECT  225.36 11.209 231.354 11.227 ;
     RECT  234.615 2.413 234.897 11.245 ;
     RECT  121.215 9.689 121.497 11.272 ;
     RECT  132.015 9.689 132.297 11.272 ;
     RECT  153.615 9.689 153.897 11.272 ;
     RECT  164.415 9.689 164.697 11.272 ;
     RECT  175.215 9.248 175.497 11.272 ;
     RECT  196.815 9.248 197.097 11.272 ;
     RECT  207.615 9.248 207.897 11.272 ;
     RECT  98.568 10.597 98.622 11.309 ;
     RECT  146.124 11.209 146.574 11.309 ;
     RECT  2.415 2.413 2.697 11.365 ;
     RECT  4.032 11.011 57.006 11.371 ;
     RECT  121.104 11.272 121.497 11.371 ;
     RECT  131.904 11.272 132.297 11.371 ;
     RECT  164.304 11.272 164.697 11.371 ;
     RECT  175.104 11.272 175.497 11.371 ;
     RECT  196.704 11.272 197.097 11.371 ;
     RECT  207.504 11.272 207.897 11.371 ;
     RECT  218.304 11.179 218.697 11.371 ;
     RECT  150.48 11.173 151.002 11.399 ;
     RECT  153.504 11.272 153.897 11.408 ;
     RECT  115.776 11.227 116.334 11.467 ;
     RECT  117.324 11.245 117.342 11.467 ;
     RECT  121.032 11.371 121.497 11.467 ;
     RECT  121.032 11.467 121.842 11.471 ;
     RECT  131.832 11.371 132.297 11.471 ;
     RECT  164.232 11.371 164.697 11.471 ;
     RECT  175.032 11.371 175.497 11.471 ;
     RECT  196.632 11.371 197.097 11.471 ;
     RECT  207.432 11.371 207.897 11.471 ;
     RECT  61.344 8.477 62.097 11.515 ;
     RECT  63.144 11.173 63.81 11.515 ;
     RECT  113.544 9.625 114.93 11.515 ;
     RECT  232.74 11.275 232.758 11.515 ;
     RECT  200.916 10.399 200.934 11.641 ;
     RECT  57.78 11.551 57.798 11.669 ;
     RECT  3.888 11.371 57.006 11.677 ;
     RECT  65.988 11.641 66.006 11.693 ;
     RECT  61.344 11.515 63.81 11.705 ;
     RECT  118.296 10.637 118.314 11.707 ;
     RECT  119.088 11.245 119.106 11.707 ;
     RECT  225.36 11.227 231.858 11.707 ;
     RECT  232.74 11.515 233.406 11.707 ;
     RECT  153.615 11.408 153.897 11.713 ;
     RECT  177.516 11.137 177.534 11.713 ;
     RECT  65.088 11.707 65.106 11.747 ;
     RECT  98.568 11.309 98.586 11.755 ;
     RECT  101.628 11.011 106.758 11.755 ;
     RECT  107.604 10.561 111.078 11.755 ;
     RECT  2.415 11.365 3.114 11.785 ;
     RECT  3.888 11.677 57.402 11.785 ;
     RECT  123.408 10.109 123.426 11.785 ;
     RECT  155.484 11.011 155.502 11.785 ;
     RECT  171.396 10.157 171.414 11.785 ;
     RECT  175.215 11.471 175.497 11.785 ;
     RECT  203.868 11.677 203.886 11.785 ;
     RECT  121.215 11.471 121.842 11.789 ;
     RECT  153.615 11.713 154.602 11.813 ;
     RECT  70.02 9.689 70.038 11.851 ;
     RECT  77.904 10.831 78.297 11.851 ;
     RECT  90.108 10.411 90.126 11.851 ;
     RECT  91.152 10.435 91.458 11.851 ;
     RECT  72.615 10.669 75.222 11.899 ;
     RECT  83.415 9.509 83.697 11.899 ;
     RECT  113.544 11.515 115.002 11.899 ;
     RECT  115.776 11.467 117.342 11.899 ;
     RECT  95.436 11.137 95.454 11.947 ;
     RECT  113.544 11.899 117.342 11.947 ;
     RECT  150.984 11.399 151.002 11.947 ;
     RECT  179.28 10.057 179.298 11.947 ;
     RECT  2.415 11.785 57.402 11.975 ;
     RECT  86.652 11.179 87.282 11.981 ;
     RECT  90.108 11.851 91.458 11.981 ;
     RECT  163.224 11.101 163.242 11.983 ;
     RECT  185.292 10.597 186.297 11.983 ;
     RECT  63.612 11.705 63.81 11.995 ;
     RECT  167.112 11.137 167.13 12.019 ;
     RECT  123.048 11.785 123.426 12.043 ;
     RECT  93.6 8.435 94.497 12.055 ;
     RECT  113.544 11.947 117.378 12.055 ;
     RECT  141.696 11.173 143.097 12.055 ;
     RECT  193.752 11.749 193.77 12.055 ;
     RECT  148.215 10.435 149.346 12.091 ;
     RECT  203.256 11.785 203.886 12.091 ;
     RECT  67.104 10.831 67.497 12.139 ;
     RECT  70.02 11.851 70.722 12.139 ;
     RECT  76.86 10.171 77.094 12.139 ;
     RECT  77.904 11.851 78.678 12.139 ;
     RECT  67.104 12.139 67.59 12.181 ;
     RECT  101.628 11.755 111.078 12.181 ;
     RECT  133.128 10.561 133.902 12.181 ;
     RECT  141.696 12.055 143.73 12.181 ;
     RECT  182.34 11.641 182.358 12.181 ;
     RECT  200.16 11.713 200.178 12.181 ;
     RECT  200.916 11.641 201.294 12.181 ;
     RECT  202.215 2.413 202.497 12.181 ;
     RECT  203.256 12.091 203.922 12.181 ;
     RECT  218.232 11.371 218.697 12.181 ;
     RECT  155.484 11.785 155.61 12.217 ;
     RECT  184.284 11.677 184.302 12.217 ;
     RECT  185.292 11.983 186.714 12.217 ;
     RECT  101.628 12.181 111.15 12.221 ;
     RECT  123.048 12.043 123.462 12.253 ;
     RECT  135.072 12.217 135.09 12.253 ;
     RECT  135.936 11.209 138.186 12.253 ;
     RECT  169.815 2.413 170.097 12.253 ;
     RECT  171.144 11.785 171.414 12.253 ;
     RECT  207.615 11.471 207.897 12.253 ;
     RECT  61.344 11.705 62.802 12.269 ;
     RECT  67.104 12.181 67.698 12.269 ;
     RECT  70.02 12.139 70.83 12.269 ;
     RECT  58.716 10.987 59.742 12.283 ;
     RECT  60.48 9.895 60.498 12.283 ;
     RECT  85.104 10.165 85.122 12.289 ;
     RECT  125.244 10.399 125.298 12.289 ;
     RECT  196.815 11.471 197.097 12.289 ;
     RECT  2.415 11.975 57.006 12.325 ;
     RECT  72.504 11.899 75.222 12.325 ;
     RECT  125.208 12.289 125.298 12.325 ;
     RECT  152.352 10.651 152.37 12.325 ;
     RECT  167.076 12.019 167.13 12.325 ;
     RECT  196.668 12.289 197.586 12.325 ;
     RECT  217.908 12.181 218.697 12.325 ;
     RECT  146.124 11.309 146.394 12.331 ;
     RECT  150.984 11.947 151.182 12.331 ;
     RECT  175.215 11.785 175.878 12.361 ;
     RECT  72.504 12.325 75.87 12.413 ;
     RECT  83.304 11.899 83.697 12.413 ;
     RECT  113.544 12.055 117.486 12.413 ;
     RECT  163.152 11.983 163.242 12.451 ;
     RECT  164.415 11.471 164.697 12.451 ;
     RECT  188.172 11.101 188.19 12.451 ;
     RECT  217.872 12.325 218.697 12.451 ;
     RECT  2.376 12.325 57.006 12.487 ;
     RECT  99.504 10.831 99.897 12.487 ;
     RECT  140.436 11.419 140.454 12.487 ;
     RECT  217.8 12.451 218.697 12.487 ;
     RECT  125.208 12.325 125.658 12.523 ;
     RECT  132.015 11.471 132.297 12.523 ;
     RECT  133.128 12.181 133.938 12.523 ;
     RECT  135.072 12.253 138.186 12.523 ;
     RECT  148.215 12.091 149.85 12.523 ;
     RECT  165.744 12.055 165.762 12.523 ;
     RECT  196.164 12.325 197.622 12.523 ;
     RECT  115.776 12.413 117.486 12.571 ;
     RECT  118.296 11.707 119.106 12.571 ;
     RECT  97.884 11.755 98.586 12.595 ;
     RECT  205.164 12.217 205.182 12.721 ;
     RECT  172.62 11.947 172.638 12.757 ;
     RECT  196.164 12.523 197.694 12.757 ;
     RECT  180.615 2.413 180.897 12.793 ;
     RECT  153.615 11.813 154.53 12.811 ;
     RECT  155.484 12.217 155.826 12.811 ;
     RECT  0.144 12.253 0.162 12.829 ;
     RECT  147.6 12.523 149.85 12.829 ;
     RECT  174.312 12.091 174.33 12.829 ;
     RECT  175.176 12.361 175.878 12.829 ;
     RECT  225.36 11.707 233.406 12.829 ;
     RECT  124.488 12.523 125.658 12.865 ;
     RECT  126.615 2.413 126.897 12.865 ;
     RECT  187.632 12.451 188.19 12.865 ;
     RECT  112.032 6.619 112.05 12.901 ;
     RECT  132.015 12.523 138.186 12.901 ;
     RECT  153.615 12.811 155.826 12.901 ;
     RECT  158.508 11.173 159.462 12.901 ;
     RECT  223.815 2.413 224.097 12.901 ;
     RECT  88.38 11.173 89.097 12.955 ;
     RECT  121.215 11.789 121.734 12.991 ;
     RECT  224.964 12.829 233.406 13.003 ;
     RECT  131.832 12.901 138.546 13.019 ;
     RECT  153.324 12.901 155.826 13.019 ;
     RECT  67.104 12.269 67.497 13.027 ;
     RECT  140.364 12.487 140.526 13.027 ;
     RECT  222.552 10.093 222.57 13.027 ;
     RECT  223.344 12.901 224.097 13.027 ;
     RECT  153.504 13.019 155.826 13.037 ;
     RECT  85.104 12.289 85.662 13.063 ;
     RECT  204.984 12.721 205.182 13.063 ;
     RECT  61.344 12.269 62.73 13.085 ;
     RECT  70.02 12.269 70.722 13.085 ;
     RECT  76.86 12.139 78.678 13.085 ;
     RECT  88.344 12.955 89.097 13.085 ;
     RECT  70.02 13.085 70.038 13.147 ;
     RECT  58.716 12.283 60.498 13.171 ;
     RECT  61.344 13.085 62.097 13.171 ;
     RECT  1.728 12.487 57.006 13.229 ;
     RECT  180.615 12.793 181.35 13.261 ;
     RECT  101.628 12.221 111.078 13.297 ;
     RECT  127.8 11.749 127.818 13.297 ;
     RECT  169.815 12.253 171.414 13.297 ;
     RECT  193.572 12.055 193.77 13.297 ;
     RECT  194.688 12.361 194.706 13.297 ;
     RECT  66.672 13.027 67.497 13.333 ;
     RECT  97.884 12.595 98.622 13.333 ;
     RECT  99.36 12.487 99.897 13.333 ;
     RECT  224.964 13.003 233.442 13.333 ;
     RECT  65.196 12.859 65.214 13.369 ;
     RECT  66.672 13.333 67.59 13.369 ;
     RECT  180.576 13.261 181.35 13.369 ;
     RECT  182.34 12.181 182.682 13.369 ;
     RECT  222.552 13.027 224.097 13.369 ;
     RECT  224.892 13.333 233.442 13.369 ;
     RECT  72.615 12.413 75.87 13.387 ;
     RECT  58.716 13.171 62.097 13.405 ;
     RECT  85.104 13.063 86.202 13.405 ;
     RECT  87.048 11.981 87.282 13.405 ;
     RECT  88.38 13.085 89.097 13.405 ;
     RECT  130.536 13.297 130.554 13.441 ;
     RECT  130.536 13.441 130.626 13.469 ;
     RECT  0.108 12.829 0.162 13.483 ;
     RECT  1.8 13.229 57.006 13.531 ;
     RECT  57.852 13.405 57.87 13.531 ;
     RECT  139.752 13.027 140.526 13.531 ;
     RECT  222.552 13.369 233.442 13.531 ;
     RECT  58.68 13.405 62.097 13.559 ;
     RECT  130.608 13.469 130.626 13.559 ;
     RECT  121.104 12.991 121.734 13.568 ;
     RECT  1.8 13.531 57.87 13.613 ;
     RECT  76.86 13.085 78.354 13.631 ;
     RECT  85.104 13.405 87.282 13.639 ;
     RECT  85.104 13.639 87.462 13.667 ;
     RECT  88.38 13.405 89.19 13.667 ;
     RECT  2.304 13.613 57.87 13.675 ;
     RECT  211.968 12.361 211.986 13.801 ;
     RECT  92.268 12.865 92.286 13.837 ;
     RECT  93.096 12.055 94.497 13.837 ;
     RECT  2.304 13.675 58.194 13.853 ;
     RECT  95.436 11.947 95.67 13.873 ;
     RECT  124.488 12.865 126.897 13.873 ;
     RECT  156.816 12.043 156.834 13.873 ;
     RECT  174.312 12.829 175.878 13.873 ;
     RECT  193.572 13.297 194.706 13.873 ;
     RECT  66.672 13.369 67.626 13.909 ;
     RECT  193.392 13.873 194.706 13.909 ;
     RECT  217.764 12.487 218.697 13.909 ;
     RECT  120.276 13.837 120.294 13.945 ;
     RECT  2.304 13.853 57.906 13.973 ;
     RECT  180.576 13.369 182.682 13.981 ;
     RECT  199.224 11.137 199.242 13.981 ;
     RECT  200.16 12.181 201.294 13.981 ;
     RECT  222.552 13.531 233.586 14.071 ;
     RECT  97.884 13.333 99.897 14.107 ;
     RECT  211.968 13.801 212.202 14.143 ;
     RECT  69.696 13.147 70.038 14.155 ;
     RECT  70.812 13.435 70.83 14.155 ;
     RECT  95.436 13.873 96.21 14.203 ;
     RECT  112.032 12.901 112.626 14.395 ;
     RECT  2.304 13.973 57.474 14.405 ;
     RECT  146.052 12.331 146.394 14.443 ;
     RECT  150.984 12.331 151.29 14.443 ;
     RECT  121.215 13.568 121.734 14.491 ;
     RECT  2.34 14.405 57.474 14.513 ;
     RECT  184.284 12.217 186.714 14.521 ;
     RECT  59.148 13.559 62.097 14.539 ;
     RECT  83.415 12.413 83.697 14.587 ;
     RECT  113.544 12.413 115.002 14.587 ;
     RECT  115.776 12.571 119.106 14.587 ;
     RECT  121.215 14.491 122.058 14.587 ;
     RECT  146.052 14.443 146.502 14.587 ;
     RECT  83.304 14.587 83.697 14.611 ;
     RECT  85.104 13.667 86.202 14.611 ;
     RECT  87.048 13.667 87.462 14.611 ;
     RECT  90.108 11.981 90.126 14.611 ;
     RECT  90.864 11.981 91.458 14.611 ;
     RECT  63.612 11.995 64.17 14.635 ;
     RECT  113.544 14.587 119.106 14.635 ;
     RECT  119.988 13.945 120.294 14.635 ;
     RECT  83.304 14.611 83.754 14.639 ;
     RECT  206.208 13.567 206.226 14.647 ;
     RECT  58.716 14.539 62.097 14.669 ;
     RECT  113.544 14.635 120.294 14.675 ;
     RECT  76.86 13.631 78.297 14.683 ;
     RECT  79.128 14.521 79.146 14.683 ;
     RECT  83.34 14.639 83.754 14.683 ;
     RECT  147.6 12.829 150.102 14.683 ;
     RECT  150.84 14.443 151.29 14.683 ;
     RECT  152.316 12.325 152.37 14.683 ;
     RECT  85.104 14.611 87.462 14.711 ;
     RECT  90.108 14.611 91.458 14.711 ;
     RECT  146.052 14.587 146.61 14.717 ;
     RECT  127.692 13.297 127.818 14.719 ;
     RECT  129.024 12.991 129.042 14.719 ;
     RECT  2.415 14.513 57.474 14.765 ;
     RECT  80.64 11.209 80.658 14.779 ;
     RECT  2.415 14.765 57.402 14.819 ;
     RECT  76.86 14.683 79.146 14.819 ;
     RECT  83.34 14.683 83.826 14.819 ;
     RECT  66.672 13.909 67.734 14.881 ;
     RECT  69.696 14.155 70.83 14.881 ;
     RECT  92.268 13.837 94.497 14.881 ;
     RECT  152.316 14.683 152.514 14.881 ;
     RECT  69.696 14.881 70.902 14.909 ;
     RECT  111.996 14.395 112.626 14.909 ;
     RECT  127.692 14.719 129.042 14.909 ;
     RECT  66.672 14.881 67.77 14.953 ;
     RECT  112.032 14.909 112.626 14.981 ;
     RECT  202.215 12.181 203.922 14.989 ;
     RECT  123.048 12.253 123.75 15.025 ;
     RECT  124.488 13.873 126.954 15.025 ;
     RECT  173.592 13.873 175.878 15.025 ;
     RECT  206.028 14.647 206.226 15.025 ;
     RECT  207.108 12.253 207.897 15.025 ;
     RECT  131.832 13.019 138.186 15.061 ;
     RECT  156.816 13.873 157.014 15.061 ;
     RECT  206.028 15.025 207.897 15.061 ;
     RECT  208.8 11.101 208.818 15.061 ;
     RECT  152.316 14.881 152.586 15.163 ;
     RECT  167.076 12.325 167.166 15.187 ;
     RECT  167.076 15.187 167.634 15.211 ;
     RECT  95.4 14.203 96.21 15.259 ;
     RECT  65.196 13.369 65.898 15.295 ;
     RECT  66.672 14.953 67.806 15.295 ;
     RECT  88.38 13.667 89.097 15.307 ;
     RECT  90.108 14.711 90.126 15.307 ;
     RECT  113.544 14.675 119.106 15.451 ;
     RECT  119.988 14.675 120.294 15.451 ;
     RECT  217.764 13.909 218.79 15.547 ;
     RECT  1.296 14.731 1.314 15.557 ;
     RECT  204.984 13.063 205.29 15.595 ;
     RECT  206.028 15.061 208.818 15.595 ;
     RECT  2.415 14.819 57.042 15.601 ;
     RECT  152.316 15.163 152.694 15.601 ;
     RECT  153.576 13.037 155.826 15.601 ;
     RECT  163.152 12.451 164.697 15.601 ;
     RECT  130.536 15.025 130.554 15.691 ;
     RECT  139.5 13.531 140.526 15.691 ;
     RECT  146.052 14.717 146.394 15.691 ;
     RECT  214.524 15.595 214.542 15.691 ;
     RECT  162.468 15.601 164.697 15.719 ;
     RECT  113.544 15.451 120.294 15.763 ;
     RECT  121.104 14.587 122.058 15.763 ;
     RECT  144.612 11.209 144.81 15.763 ;
     RECT  145.584 15.691 146.394 15.763 ;
     RECT  214.416 15.691 214.542 15.773 ;
     RECT  130.536 15.691 130.626 15.791 ;
     RECT  131.832 15.061 138.546 15.791 ;
     RECT  214.416 15.773 214.434 15.821 ;
     RECT  217.764 15.547 219.114 15.821 ;
     RECT  113.544 15.763 122.058 15.835 ;
     RECT  236.628 14.491 236.646 15.835 ;
     RECT  2.415 15.601 57.078 15.997 ;
     RECT  85.104 14.711 86.202 16.069 ;
     RECT  87.048 14.711 87.462 16.069 ;
     RECT  2.415 15.997 57.294 16.075 ;
     RECT  2.304 16.075 57.294 16.141 ;
     RECT  123.048 15.025 126.954 16.141 ;
     RECT  127.764 14.909 129.042 16.141 ;
     RECT  139.5 15.691 140.886 16.141 ;
     RECT  141.696 12.181 143.838 16.141 ;
     RECT  167.04 15.211 167.634 16.141 ;
     RECT  85.104 16.069 87.462 16.169 ;
     RECT  123.048 16.141 129.042 16.231 ;
     RECT  180.576 13.981 183.15 16.231 ;
     RECT  184.284 14.521 186.894 16.231 ;
     RECT  131.832 15.791 138.186 16.303 ;
     RECT  177.516 11.713 178.038 16.303 ;
     RECT  179.064 11.947 179.298 16.303 ;
     RECT  101.196 13.297 111.078 16.315 ;
     RECT  112.104 14.981 112.626 16.315 ;
     RECT  59.148 14.669 62.097 16.339 ;
     RECT  147.6 14.683 151.29 16.339 ;
     RECT  167.04 16.141 167.706 16.339 ;
     RECT  168.984 12.991 169.002 16.339 ;
     RECT  169.815 13.297 171.522 16.339 ;
     RECT  88.38 15.307 90.126 16.375 ;
     RECT  90.864 14.711 91.458 16.375 ;
     RECT  2.304 16.141 57.834 16.439 ;
     RECT  87.048 16.169 87.462 16.501 ;
     RECT  88.38 16.375 91.458 16.501 ;
     RECT  92.196 14.881 94.497 16.501 ;
     RECT  95.22 15.259 96.21 16.501 ;
     RECT  139.5 16.141 143.838 16.501 ;
     RECT  144.612 15.763 146.394 16.501 ;
     RECT  152.316 15.601 155.826 16.573 ;
     RECT  156.816 15.061 157.698 16.573 ;
     RECT  176.724 12.181 176.742 16.645 ;
     RECT  2.304 16.439 57.006 16.673 ;
     RECT  76.86 14.819 78.297 16.681 ;
     RECT  139.5 16.501 146.394 16.681 ;
     RECT  147.24 16.339 151.326 16.681 ;
     RECT  163.152 15.719 164.697 16.681 ;
     RECT  172.512 12.757 172.638 16.681 ;
     RECT  221.724 16.501 221.742 16.681 ;
     RECT  222.552 14.071 233.802 16.681 ;
     RECT  172.476 16.681 172.638 16.771 ;
     RECT  211.644 14.143 212.202 16.771 ;
     RECT  213.015 2.413 213.297 16.771 ;
     RECT  123.048 16.231 129.69 16.807 ;
     RECT  130.68 16.411 130.698 16.807 ;
     RECT  152.316 16.573 157.698 16.807 ;
     RECT  158.508 12.901 160.038 16.807 ;
     RECT  214.236 16.771 214.254 16.829 ;
     RECT  101.196 16.315 112.626 16.843 ;
     RECT  113.544 15.835 122.31 16.843 ;
     RECT  221.724 16.681 233.802 16.879 ;
     RECT  58.68 16.339 62.097 16.907 ;
     RECT  221.724 16.879 233.874 16.939 ;
     RECT  234.615 11.245 234.99 16.939 ;
     RECT  72.432 13.387 75.87 17.077 ;
     RECT  76.608 16.681 78.297 17.077 ;
     RECT  123.048 16.807 130.698 17.077 ;
     RECT  85.104 16.169 86.202 17.113 ;
     RECT  211.644 16.771 213.297 17.117 ;
     RECT  97.164 14.107 99.897 17.149 ;
     RECT  217.764 15.821 218.79 17.176 ;
     RECT  217.764 17.176 218.898 17.179 ;
     RECT  2.415 16.673 57.006 17.185 ;
     RECT  57.744 16.439 57.834 17.185 ;
     RECT  92.196 16.501 96.21 17.185 ;
     RECT  97.128 17.149 99.897 17.185 ;
     RECT  101.196 16.843 122.31 17.185 ;
     RECT  217.764 17.179 219.186 17.219 ;
     RECT  100.62 17.185 122.31 17.221 ;
     RECT  123.048 17.077 130.77 17.221 ;
     RECT  2.415 17.185 57.834 17.311 ;
     RECT  92.196 17.185 99.897 17.347 ;
     RECT  100.62 17.221 130.77 17.347 ;
     RECT  69.696 14.909 70.146 17.371 ;
     RECT  70.884 14.909 70.902 17.371 ;
     RECT  162.828 16.681 164.697 17.383 ;
     RECT  165.564 12.523 165.762 17.383 ;
     RECT  167.04 16.339 168.102 17.383 ;
     RECT  191.415 2.413 191.697 17.383 ;
     RECT  131.652 16.303 138.186 17.419 ;
     RECT  139.5 16.681 151.326 17.419 ;
     RECT  220.86 15.223 220.878 17.419 ;
     RECT  0.108 13.483 0.558 17.447 ;
     RECT  65.196 15.295 67.806 17.491 ;
     RECT  68.688 13.981 68.706 17.491 ;
     RECT  92.196 17.347 130.77 17.491 ;
     RECT  131.652 17.419 151.326 17.491 ;
     RECT  65.196 17.491 68.706 17.515 ;
     RECT  69.696 17.371 70.902 17.515 ;
     RECT  72.432 17.077 78.297 17.515 ;
     RECT  79.128 14.819 79.146 17.515 ;
     RECT  83.34 14.819 83.697 17.515 ;
     RECT  85.104 17.113 86.274 17.515 ;
     RECT  2.415 17.311 57.87 17.563 ;
     RECT  2.376 17.563 57.87 17.611 ;
     RECT  191.415 17.383 192.402 17.617 ;
     RECT  162.828 17.383 168.102 17.653 ;
     RECT  168.984 16.339 171.522 17.653 ;
     RECT  2.304 17.611 57.87 17.689 ;
     RECT  87.048 16.501 91.458 17.725 ;
     RECT  92.196 17.491 151.326 17.725 ;
     RECT  82.656 17.515 83.862 17.755 ;
     RECT  173.592 15.025 175.914 17.761 ;
     RECT  176.724 16.645 176.778 17.761 ;
     RECT  216.828 11.749 216.846 17.851 ;
     RECT  221.724 16.939 234.99 17.887 ;
     RECT  173.592 17.761 176.778 17.923 ;
     RECT  177.516 16.303 179.298 17.923 ;
     RECT  196.164 12.757 197.802 17.923 ;
     RECT  211.644 17.117 212.202 17.923 ;
     RECT  87.048 17.725 151.326 17.959 ;
     RECT  152.316 16.807 160.038 17.959 ;
     RECT  0.108 17.447 0.486 17.981 ;
     RECT  199.224 13.981 201.294 17.995 ;
     RECT  202.215 14.989 204.066 17.995 ;
     RECT  172.476 16.771 172.854 18.031 ;
     RECT  173.592 17.923 179.298 18.031 ;
     RECT  59.148 16.907 62.097 18.091 ;
     RECT  62.892 14.635 64.17 18.091 ;
     RECT  80.64 14.779 81.378 18.121 ;
     RECT  82.656 17.755 83.934 18.121 ;
     RECT  180.576 16.231 186.894 18.121 ;
     RECT  59.148 18.091 64.17 18.149 ;
     RECT  62.892 18.149 64.17 18.157 ;
     RECT  65.196 17.515 70.902 18.157 ;
     RECT  162.828 17.653 171.522 18.157 ;
     RECT  190.98 17.617 192.402 18.157 ;
     RECT  236.196 15.835 236.646 18.187 ;
     RECT  84.924 17.515 86.274 18.193 ;
     RECT  161.532 16.843 161.802 18.193 ;
     RECT  190.764 18.157 192.654 18.193 ;
     RECT  221.724 17.887 235.35 18.301 ;
     RECT  236.196 18.187 237.15 18.301 ;
     RECT  84.852 18.193 86.274 18.391 ;
     RECT  87.048 17.959 160.146 18.391 ;
     RECT  193.392 13.909 194.814 18.463 ;
     RECT  195.984 17.923 197.802 18.463 ;
     RECT  180.468 18.121 186.894 18.499 ;
     RECT  187.632 12.865 188.334 18.499 ;
     RECT  210.42 18.391 210.438 18.499 ;
     RECT  80.64 18.121 83.934 18.535 ;
     RECT  84.852 18.391 160.146 18.535 ;
     RECT  199.224 17.995 204.066 18.535 ;
     RECT  204.984 15.595 208.818 18.535 ;
     RECT  211.32 17.923 212.202 18.535 ;
     RECT  213.015 17.117 213.297 18.535 ;
     RECT  220.356 17.419 220.878 18.535 ;
     RECT  72.432 17.515 79.146 18.661 ;
     RECT  80.64 18.535 160.146 18.661 ;
     RECT  217.764 17.219 218.697 18.661 ;
     RECT  219.78 18.535 220.878 18.661 ;
     RECT  0.108 17.981 0.126 18.725 ;
     RECT  193.392 18.463 197.802 18.769 ;
     RECT  211.32 18.535 213.297 18.769 ;
     RECT  72.432 18.661 79.686 18.805 ;
     RECT  193.392 18.769 197.838 18.805 ;
     RECT  210.348 18.499 210.438 18.805 ;
     RECT  72.432 18.805 79.794 18.841 ;
     RECT  80.532 18.661 160.146 18.841 ;
     RECT  172.476 18.031 179.298 18.841 ;
     RECT  193.392 18.805 198.486 18.907 ;
     RECT  199.224 18.535 208.818 18.907 ;
     RECT  210.348 18.805 210.474 18.907 ;
     RECT  59.148 18.149 62.097 18.931 ;
     RECT  62.892 18.157 70.902 18.931 ;
     RECT  72.432 18.841 160.146 18.931 ;
     RECT  162.828 18.157 171.558 18.931 ;
     RECT  0.18 18.955 0.198 18.967 ;
     RECT  59.148 18.931 70.902 18.967 ;
     RECT  59.148 18.967 71.406 19.003 ;
     RECT  161.532 18.193 161.982 19.039 ;
     RECT  216.612 17.851 216.846 19.039 ;
     RECT  217.764 18.661 220.878 19.039 ;
     RECT  180.468 18.499 188.334 19.075 ;
     RECT  215.1 18.421 215.118 19.085 ;
     RECT  216.612 19.039 220.878 19.111 ;
     RECT  221.724 18.301 237.15 19.111 ;
     RECT  2.304 17.689 57.906 19.147 ;
     RECT  211.284 18.769 213.297 19.195 ;
     RECT  59.148 19.003 71.586 19.201 ;
     RECT  72.396 18.931 160.146 19.201 ;
     RECT  161.496 19.039 161.982 19.201 ;
     RECT  162.828 18.931 171.702 19.201 ;
     RECT  210.312 18.907 210.474 19.237 ;
     RECT  211.284 19.195 213.39 19.237 ;
     RECT  193.392 18.907 208.818 19.243 ;
     RECT  59.148 19.201 160.146 19.277 ;
     RECT  161.496 19.201 171.702 19.345 ;
     RECT  138.816 19.277 160.146 19.381 ;
     RECT  190.296 18.193 192.654 19.381 ;
     RECT  0.18 18.967 0.342 19.435 ;
     RECT  138.816 19.381 160.722 19.471 ;
     RECT  161.496 19.345 171.738 19.471 ;
     RECT  190.044 19.381 192.654 19.471 ;
     RECT  193.392 19.243 209.394 19.471 ;
     RECT  214.344 18.571 214.362 19.471 ;
     RECT  2.304 19.147 58.086 19.507 ;
     RECT  172.476 18.841 179.442 19.507 ;
     RECT  190.044 19.471 209.394 19.531 ;
     RECT  210.312 19.237 213.39 19.531 ;
     RECT  190.044 19.531 213.39 19.543 ;
     RECT  172.476 19.507 179.658 19.579 ;
     RECT  180.396 19.075 188.334 19.579 ;
     RECT  214.344 19.471 214.614 19.579 ;
     RECT  216.612 19.111 237.15 19.579 ;
     RECT  2.304 19.507 58.194 19.615 ;
     RECT  59.148 19.277 137.97 19.615 ;
     RECT  0.18 19.435 0.558 19.627 ;
     RECT  1.404 18.187 1.422 19.627 ;
     RECT  189.972 19.543 213.39 19.651 ;
     RECT  214.236 19.579 214.614 19.651 ;
     RECT  0.18 19.627 1.422 19.723 ;
     RECT  189.972 19.651 214.614 19.769 ;
     RECT  0.108 19.723 1.422 19.805 ;
     RECT  138.816 19.471 171.738 19.813 ;
     RECT  172.476 19.579 188.334 19.813 ;
     RECT  215.352 19.813 215.37 19.867 ;
     RECT  0.54 19.805 1.422 19.877 ;
     RECT  138.816 19.813 188.37 19.901 ;
     RECT  2.304 19.615 137.97 20.011 ;
     RECT  138.816 19.901 160.758 20.011 ;
     RECT  161.496 19.901 188.37 20.011 ;
     RECT  189.972 19.769 192.654 20.011 ;
     RECT  193.392 19.769 214.614 20.047 ;
     RECT  215.352 19.867 215.478 20.047 ;
     RECT  2.304 20.011 160.758 20.111 ;
     RECT  161.496 20.011 188.442 20.119 ;
     RECT  161.496 20.119 188.73 20.155 ;
     RECT  189.54 20.011 192.654 20.155 ;
     RECT  193.392 20.047 215.478 20.155 ;
     RECT  216.216 19.579 237.15 20.155 ;
     RECT  1.152 19.877 1.422 20.345 ;
     RECT  161.496 20.155 192.654 20.551 ;
     RECT  193.392 20.155 237.15 20.551 ;
     RECT  1.152 20.345 1.17 20.651 ;
     RECT  158.94 20.111 160.758 20.659 ;
     RECT  161.496 20.551 237.15 20.659 ;
     RECT  2.304 20.111 158.202 20.687 ;
     RECT  0.108 20.683 0.126 20.695 ;
     RECT  0.108 20.695 0.162 20.779 ;
     RECT  2.304 20.687 151.398 20.849 ;
     RECT  158.94 20.659 237.15 20.849 ;
     RECT  152.208 20.687 158.202 20.885 ;
     RECT  0.108 20.779 0.558 20.957 ;
     RECT  130.536 20.849 151.398 20.957 ;
     RECT  152.208 20.885 155.07 20.957 ;
     RECT  2.304 20.849 129.726 20.993 ;
     RECT  2.304 20.993 128.826 21.005 ;
     RECT  2.304 21.005 128.754 21.029 ;
     RECT  152.208 20.957 154.962 21.029 ;
     RECT  161.208 20.849 237.15 21.029 ;
     RECT  2.304 21.029 128.394 21.067 ;
     RECT  155.808 20.885 158.202 21.067 ;
     RECT  158.94 20.849 160.47 21.067 ;
     RECT  2.268 21.067 128.394 21.101 ;
     RECT  172.404 21.029 237.15 21.101 ;
     RECT  130.536 20.957 140.922 21.119 ;
     RECT  141.66 20.957 151.398 21.119 ;
     RECT  2.268 21.101 72.954 21.155 ;
     RECT  73.728 21.101 128.394 21.155 ;
     RECT  130.536 21.119 139.518 21.155 ;
     RECT  144.9 21.119 151.398 21.155 ;
     RECT  155.808 21.067 160.47 21.155 ;
     RECT  161.208 21.029 171.522 21.155 ;
     RECT  141.948 21.119 143.982 21.191 ;
     RECT  164.376 21.155 171.522 21.197 ;
     RECT  73.728 21.155 91.854 21.227 ;
     RECT  130.536 21.155 139.158 21.227 ;
     RECT  172.404 21.101 179.622 21.227 ;
     RECT  92.628 21.155 128.394 21.263 ;
     RECT  161.208 21.155 163.386 21.263 ;
     RECT  172.98 21.227 179.37 21.263 ;
     RECT  180.504 21.101 237.15 21.263 ;
     RECT  73.728 21.227 89.766 21.293 ;
     RECT  73.764 21.293 89.766 21.299 ;
     RECT  109.44 21.263 128.394 21.299 ;
     RECT  187.524 21.263 237.15 21.299 ;
     RECT  146.052 21.155 150.93 21.341 ;
     RECT  109.44 21.299 121.497 21.347 ;
     RECT  2.268 21.155 57.69 21.389 ;
     RECT  58.536 21.155 72.954 21.389 ;
     RECT  73.764 21.299 79.65 21.389 ;
     RECT  80.46 21.299 89.55 21.389 ;
     RECT  90.504 21.227 91.854 21.389 ;
     RECT  92.628 21.263 108.666 21.389 ;
     RECT  122.292 21.299 128.394 21.389 ;
     RECT  149.688 21.341 150.93 21.389 ;
     RECT  156.456 21.155 160.47 21.389 ;
     RECT  161.208 21.263 163.35 21.389 ;
     RECT  172.98 21.263 173.178 21.389 ;
     RECT  174.06 21.263 179.37 21.389 ;
     RECT  180.504 21.263 186.642 21.389 ;
     RECT  58.644 21.389 72.954 21.425 ;
     RECT  73.764 21.389 79.038 21.425 ;
     RECT  80.82 21.389 84.978 21.425 ;
     RECT  92.628 21.389 100.206 21.425 ;
     RECT  109.44 21.347 121.41 21.425 ;
     RECT  122.292 21.389 128.178 21.425 ;
     RECT  130.536 21.227 138.69 21.425 ;
     RECT  142.488 21.191 143.73 21.425 ;
     RECT  144.9 21.155 145.098 21.425 ;
     RECT  146.052 21.341 148.77 21.425 ;
     RECT  149.832 21.389 150.75 21.425 ;
     RECT  152.352 21.029 154.962 21.425 ;
     RECT  156.456 21.389 156.474 21.425 ;
     RECT  174.06 21.389 179.226 21.425 ;
     RECT  180.504 21.389 181.71 21.425 ;
     RECT  187.524 21.299 193.59 21.425 ;
     RECT  194.328 21.299 237.15 21.425 ;
     RECT  123.588 21.425 128.142 21.437 ;
     RECT  133.308 21.425 138.69 21.437 ;
     RECT  152.424 21.425 154.962 21.437 ;
     RECT  164.415 21.197 171.522 21.437 ;
     RECT  182.592 21.389 186.606 21.437 ;
     RECT  187.524 21.425 190.566 21.437 ;
     RECT  58.644 21.425 69.138 21.461 ;
     RECT  86.328 21.389 89.55 21.461 ;
     RECT  127.944 21.437 128.142 21.461 ;
     RECT  133.308 21.437 133.398 21.461 ;
     RECT  134.388 21.437 138.69 21.461 ;
     RECT  146.16 21.425 148.77 21.461 ;
     RECT  149.868 21.425 150.678 21.461 ;
     RECT  152.424 21.437 154.746 21.461 ;
     RECT  161.316 21.389 162.558 21.461 ;
     RECT  165.996 21.437 171.522 21.461 ;
     RECT  176.652 21.425 179.226 21.461 ;
     RECT  189.684 21.437 190.566 21.461 ;
     RECT  191.304 21.425 193.59 21.461 ;
     RECT  194.328 21.425 195.066 21.461 ;
     RECT  196.056 21.425 237.15 21.461 ;
     RECT  130.536 21.425 132.462 21.485 ;
     RECT  182.7 21.437 186.606 21.485 ;
     RECT  86.328 21.461 87.246 21.497 ;
     RECT  90.54 21.389 91.854 21.497 ;
     RECT  123.588 21.437 126.81 21.497 ;
     RECT  134.388 21.461 134.982 21.497 ;
     RECT  144.972 21.425 145.098 21.497 ;
     RECT  158.904 21.389 160.47 21.497 ;
     RECT  163.296 21.389 163.35 21.497 ;
     RECT  174.06 21.425 175.842 21.497 ;
     RECT  180.504 21.425 181.35 21.497 ;
     RECT  196.056 21.461 197.55 21.497 ;
     RECT  198.36 21.461 237.15 21.497 ;
     RECT  239.292 21.469 239.31 21.505 ;
     RECT  2.268 21.389 57.402 21.533 ;
     RECT  59.796 21.461 69.138 21.533 ;
     RECT  69.876 21.425 72.954 21.533 ;
     RECT  82.656 21.425 84.834 21.533 ;
     RECT  86.652 21.497 87.246 21.533 ;
     RECT  97.524 21.425 99.954 21.533 ;
     RECT  100.944 21.389 104.13 21.533 ;
     RECT  118.584 21.425 121.41 21.533 ;
     RECT  123.66 21.497 126.81 21.533 ;
     RECT  136.044 21.461 138.69 21.533 ;
     RECT  146.412 21.461 148.77 21.533 ;
     RECT  149.868 21.461 150.642 21.533 ;
     RECT  152.64 21.461 154.746 21.533 ;
     RECT  157.212 21.389 158.058 21.533 ;
     RECT  163.296 21.497 163.314 21.533 ;
     RECT  182.7 21.485 186.57 21.533 ;
     RECT  187.524 21.437 188.73 21.533 ;
     RECT  194.328 21.461 194.994 21.533 ;
     RECT  198.36 21.497 204.93 21.533 ;
     RECT  176.652 21.461 176.778 21.539 ;
     RECT  239.292 21.505 239.454 21.541 ;
     RECT  2.268 21.533 53.01 21.569 ;
     RECT  58.644 21.461 58.986 21.569 ;
     RECT  70.344 21.533 72.954 21.569 ;
     RECT  80.82 21.425 81.558 21.569 ;
     RECT  86.688 21.533 87.246 21.569 ;
     RECT  92.628 21.425 96.75 21.569 ;
     RECT  122.292 21.425 122.706 21.569 ;
     RECT  123.66 21.533 124.974 21.569 ;
     RECT  134.892 21.497 134.982 21.569 ;
     RECT  136.836 21.533 138.69 21.569 ;
     RECT  140.256 21.119 140.922 21.569 ;
     RECT  146.484 21.533 148.77 21.569 ;
     RECT  154.62 21.533 154.746 21.569 ;
     RECT  174.42 21.497 175.305 21.569 ;
     RECT  177.516 21.461 179.226 21.569 ;
     RECT  182.7 21.533 184.662 21.569 ;
     RECT  185.796 21.533 186.57 21.569 ;
     RECT  187.524 21.533 188.694 21.569 ;
     RECT  190.152 21.461 190.566 21.569 ;
     RECT  196.056 21.497 197.478 21.569 ;
     RECT  206.136 21.497 237.15 21.569 ;
     RECT  54.036 21.533 57.402 21.581 ;
     RECT  58.68 21.569 58.986 21.581 ;
     RECT  92.808 21.569 96.75 21.581 ;
     RECT  118.584 21.533 120.114 21.581 ;
     RECT  120.852 21.533 121.41 21.581 ;
     RECT  123.66 21.569 124.866 21.581 ;
     RECT  125.784 21.533 126.81 21.581 ;
     RECT  137.304 21.569 138.69 21.581 ;
     RECT  146.484 21.569 146.934 21.581 ;
     RECT  149.94 21.533 150.642 21.581 ;
     RECT  166.212 21.461 171.522 21.581 ;
     RECT  178.704 21.569 179.226 21.581 ;
     RECT  185.796 21.569 186.105 21.581 ;
     RECT  206.136 21.569 214.974 21.581 ;
     RECT  61.092 21.533 69.138 21.617 ;
     RECT  94.215 21.581 96.75 21.617 ;
     RECT  109.44 21.425 117.81 21.617 ;
     RECT  120.852 21.581 121.305 21.617 ;
     RECT  125.784 21.581 126.705 21.617 ;
     RECT  130.572 21.485 132.462 21.617 ;
     RECT  137.415 21.581 138.69 21.617 ;
     RECT  142.488 21.425 143.694 21.617 ;
     RECT  164.415 21.437 164.79 21.617 ;
     RECT  174.492 21.569 175.305 21.617 ;
     RECT  185.832 21.581 186.105 21.617 ;
     RECT  191.415 21.461 193.59 21.617 ;
     RECT  206.136 21.581 214.902 21.617 ;
     RECT  2.268 21.569 52.47 21.629 ;
     RECT  84.816 21.533 84.834 21.629 ;
     RECT  86.796 21.569 87.246 21.629 ;
     RECT  130.572 21.617 131.67 21.629 ;
     RECT  143.28 21.617 143.694 21.629 ;
     RECT  152.784 21.533 153.81 21.629 ;
     RECT  161.856 21.461 162.558 21.629 ;
     RECT  177.516 21.569 177.966 21.629 ;
     RECT  194.544 21.533 194.994 21.629 ;
     RECT  198.36 21.533 199.674 21.629 ;
     RECT  200.592 21.533 204.93 21.629 ;
     RECT  2.268 21.629 52.218 21.659 ;
     RECT  70.488 21.569 72.954 21.659 ;
     RECT  90.54 21.497 91.746 21.659 ;
     RECT  104.904 21.389 106.686 21.659 ;
     RECT  118.656 21.581 120.114 21.659 ;
     RECT  130.572 21.629 130.662 21.659 ;
     RECT  137.556 21.617 138.69 21.659 ;
     RECT  143.28 21.629 143.442 21.659 ;
     RECT  149.94 21.581 150.606 21.659 ;
     RECT  157.536 21.533 158.058 21.659 ;
     RECT  161.856 21.629 161.946 21.659 ;
     RECT  167.004 21.581 170.514 21.659 ;
     RECT  177.588 21.629 177.966 21.659 ;
     RECT  183.204 21.569 184.662 21.659 ;
     RECT  190.152 21.569 190.53 21.659 ;
     RECT  191.664 21.617 193.59 21.659 ;
     RECT  200.592 21.629 204.714 21.659 ;
     RECT  94.644 21.617 96.75 21.677 ;
     RECT  146.52 21.581 146.934 21.677 ;
     RECT  200.7 21.659 204.714 21.677 ;
     RECT  62.424 21.617 66.834 21.695 ;
     RECT  82.656 21.533 83.682 21.695 ;
     RECT  88.092 21.461 89.55 21.695 ;
     RECT  92.808 21.581 93.474 21.695 ;
     RECT  104.904 21.659 106.038 21.695 ;
     RECT  148.104 21.569 148.77 21.695 ;
     RECT  158.904 21.497 159.642 21.695 ;
     RECT  167.292 21.659 170.514 21.695 ;
     RECT  180.504 21.497 181.098 21.695 ;
     RECT  62.604 21.695 66.834 21.725 ;
     RECT  88.092 21.695 88.11 21.725 ;
     RECT  198.576 21.629 199.674 21.725 ;
     RECT  206.136 21.617 212.49 21.725 ;
     RECT  2.268 21.659 47.862 21.731 ;
     RECT  101.268 21.533 103.986 21.731 ;
     RECT  122.616 21.569 122.706 21.731 ;
     RECT  179.208 21.581 179.226 21.731 ;
     RECT  190.44 21.659 190.458 21.731 ;
     RECT  191.844 21.659 193.59 21.731 ;
     RECT  196.2 21.569 197.478 21.731 ;
     RECT  200.736 21.677 204.714 21.731 ;
     RECT  207.216 21.725 212.49 21.731 ;
     RECT  0.108 20.957 0.126 21.739 ;
     RECT  54.036 21.581 56.97 21.767 ;
     RECT  58.68 21.581 58.95 21.767 ;
     RECT  70.488 21.659 71.622 21.767 ;
     RECT  98.064 21.533 99.954 21.767 ;
     RECT  133.344 21.461 133.398 21.767 ;
     RECT  137.556 21.659 138.438 21.767 ;
     RECT  203.832 21.731 204.714 21.767 ;
     RECT  207.36 21.731 208.242 21.767 ;
     RECT  59.796 21.533 60.138 21.773 ;
     RECT  82.656 21.695 82.998 21.773 ;
     RECT  200.736 21.731 203.058 21.773 ;
     RECT  204.588 21.767 204.714 21.773 ;
     RECT  238.86 21.541 239.454 21.775 ;
     RECT  62.64 21.725 62.802 21.803 ;
     RECT  63.576 21.725 66.834 21.803 ;
     RECT  73.8 21.425 79.038 21.803 ;
     RECT  90.54 21.659 91.674 21.803 ;
     RECT  122.616 21.731 122.67 21.803 ;
     RECT  132.444 21.617 132.462 21.803 ;
     RECT  137.556 21.767 137.574 21.803 ;
     RECT  159.444 21.695 159.642 21.803 ;
     RECT  160.452 21.497 160.47 21.803 ;
     RECT  168.264 21.695 169.398 21.803 ;
     RECT  174.492 21.617 175.014 21.803 ;
     RECT  187.524 21.569 187.542 21.803 ;
     RECT  191.844 21.731 193.302 21.803 ;
     RECT  203.832 21.767 203.85 21.803 ;
     RECT  204.624 21.773 204.714 21.803 ;
     RECT  238.644 21.775 239.454 21.811 ;
     RECT  213.516 21.617 214.902 21.821 ;
     RECT  0.108 21.739 0.162 21.835 ;
     RECT  45.864 21.731 47.862 21.839 ;
     RECT  54.144 21.767 56.286 21.839 ;
     RECT  65.736 21.803 66.834 21.839 ;
     RECT  90.72 21.803 91.674 21.839 ;
     RECT  120.852 21.617 121.05 21.839 ;
     RECT  128.124 21.461 128.142 21.839 ;
     RECT  149.94 21.659 150.102 21.839 ;
     RECT  172.98 21.389 172.998 21.839 ;
     RECT  183.564 21.659 184.122 21.839 ;
     RECT  188.676 21.569 188.694 21.839 ;
     RECT  201.096 21.773 203.058 21.839 ;
     RECT  209.268 21.731 212.49 21.839 ;
     RECT  63.576 21.803 64.998 21.884 ;
     RECT  95.292 21.677 96.75 21.884 ;
     RECT  107.64 21.389 108.522 21.884 ;
     RECT  129.708 20.993 129.726 21.884 ;
     RECT  142.488 21.617 142.506 21.884 ;
     RECT  204.624 21.803 204.642 21.884 ;
     RECT  209.268 21.839 210.186 21.884 ;
     RECT  148.752 21.695 148.77 21.917 ;
     RECT  191.844 21.803 193.266 21.929 ;
     RECT  213.516 21.821 214.506 21.929 ;
     RECT  2.268 21.731 44.982 21.965 ;
     RECT  86.796 21.629 87.138 21.965 ;
     RECT  110.808 21.617 117.81 21.965 ;
     RECT  133.344 21.767 133.362 21.965 ;
     RECT  210.924 21.839 212.49 21.965 ;
     RECT  73.8 21.803 78.174 22.001 ;
     RECT  119.124 21.659 120.114 22.001 ;
     RECT  171.504 21.581 171.522 22.009 ;
     RECT  241.128 21.541 241.146 22.009 ;
     RECT  241.884 21.631 241.902 22.009 ;
     RECT  46.188 21.839 47.862 22.013 ;
     RECT  98.496 21.767 99.954 22.013 ;
     RECT  0.108 21.835 0.558 22.037 ;
     RECT  2.304 21.965 44.982 22.037 ;
     RECT  90.792 21.839 91.674 22.037 ;
     RECT  122.652 21.803 122.67 22.037 ;
     RECT  164.772 21.617 164.79 22.037 ;
     RECT  238.644 21.811 239.634 22.045 ;
     RECT  103.32 21.731 103.986 22.061 ;
     RECT  98.568 22.013 99.954 22.073 ;
     RECT  120.852 21.839 120.87 22.073 ;
     RECT  198.576 21.725 198.846 22.073 ;
     RECT  201.096 21.839 201.294 22.073 ;
     RECT  0.108 22.037 0.198 22.109 ;
     RECT  66.708 21.839 66.834 22.109 ;
     RECT  107.856 21.884 108.522 22.109 ;
     RECT  111.312 21.965 117.81 22.109 ;
     RECT  170.424 21.695 170.514 22.154 ;
     RECT  211.896 21.965 212.49 22.154 ;
     RECT  123.66 21.581 124.47 22.157 ;
     RECT  202.176 21.839 202.806 22.157 ;
     RECT  215.964 21.569 237.15 22.171 ;
     RECT  238.104 22.045 239.634 22.171 ;
     RECT  143.28 21.659 143.298 22.199 ;
     RECT  98.568 22.073 99.774 22.205 ;
     RECT  46.188 22.013 47.502 22.235 ;
     RECT  123.66 22.157 123.678 22.235 ;
     RECT  54.144 21.839 55.926 22.271 ;
     RECT  64.08 21.884 64.998 22.271 ;
     RECT  73.8 22.001 77.742 22.271 ;
     RECT  90.792 22.037 91.386 22.271 ;
     RECT  101.268 21.731 102.582 22.271 ;
     RECT  109.44 21.617 110.034 22.271 ;
     RECT  168.264 21.803 168.282 22.271 ;
     RECT  183.564 21.839 183.69 22.271 ;
     RECT  192.42 21.929 193.266 22.271 ;
     RECT  206.136 21.725 206.478 22.271 ;
     RECT  67.752 21.617 69.138 22.307 ;
     RECT  80.82 21.569 81.486 22.307 ;
     RECT  171.504 22.009 171.666 22.307 ;
     RECT  213.66 21.929 214.506 22.307 ;
     RECT  77.148 22.271 77.742 22.343 ;
     RECT  111.312 22.109 115.722 22.343 ;
     RECT  199.656 21.725 199.674 22.343 ;
     RECT  66.708 22.109 66.798 22.349 ;
     RECT  152.784 21.629 152.982 22.349 ;
     RECT  70.488 21.767 70.758 22.379 ;
     RECT  140.256 21.569 140.274 22.379 ;
     RECT  150.084 21.839 150.102 22.379 ;
     RECT  210.924 21.965 210.942 22.379 ;
     RECT  212.436 22.154 212.49 22.379 ;
     RECT  65.736 21.839 65.862 22.424 ;
     RECT  70.74 22.379 70.758 22.424 ;
     RECT  105.408 21.695 106.038 22.424 ;
     RECT  169.272 21.803 169.398 22.424 ;
     RECT  183.672 22.271 183.69 22.424 ;
     RECT  192.42 22.271 192.438 22.424 ;
     RECT  48.816 21.659 52.218 22.445 ;
     RECT  59.868 21.773 60.138 22.469 ;
     RECT  66.708 22.349 66.762 22.469 ;
     RECT  116.604 22.109 117.81 22.469 ;
     RECT  131.652 21.629 131.67 22.469 ;
     RECT  152.964 22.349 152.982 22.469 ;
     RECT  101.952 22.271 102.366 22.505 ;
     RECT  111.312 22.343 112.302 22.505 ;
     RECT  138.42 21.767 138.438 22.505 ;
     RECT  159.444 21.803 159.462 22.505 ;
     RECT  81.072 22.307 81.486 22.541 ;
     RECT  89.244 21.695 89.55 22.541 ;
     RECT  105.408 22.424 105.426 22.541 ;
     RECT  72.396 21.659 72.954 22.577 ;
     RECT  95.292 21.884 96.138 22.577 ;
     RECT  124.452 22.157 124.47 22.577 ;
     RECT  157.536 21.659 157.554 22.577 ;
     RECT  169.38 22.424 169.398 22.589 ;
     RECT  207.576 21.767 208.242 22.589 ;
     RECT  54.144 22.271 54.738 22.613 ;
     RECT  59.868 22.469 60.066 22.613 ;
     RECT  72.396 22.577 72.522 22.613 ;
     RECT  79.02 21.803 79.038 22.613 ;
     RECT  194.724 21.629 194.994 22.613 ;
     RECT  206.46 22.271 206.478 22.613 ;
     RECT  117.252 22.469 117.81 22.637 ;
     RECT  119.124 22.001 119.754 22.637 ;
     RECT  72.396 22.613 72.414 22.649 ;
     RECT  73.8 22.271 76.41 22.649 ;
     RECT  174.492 21.803 174.51 22.649 ;
     RECT  198.828 22.073 198.846 22.649 ;
     RECT  73.8 22.649 75.294 22.685 ;
     RECT  49.608 22.445 52.218 22.694 ;
     RECT  54.144 22.613 54.162 22.694 ;
     RECT  67.86 22.307 69.138 22.694 ;
     RECT  109.44 22.271 109.746 22.694 ;
     RECT  202.176 22.157 202.194 22.694 ;
     RECT  214.488 22.307 214.506 22.694 ;
     RECT  59.868 22.613 59.886 22.733 ;
     RECT  55.872 22.271 55.926 22.739 ;
     RECT  215.964 22.171 239.634 22.775 ;
     RECT  113.472 22.343 115.722 22.781 ;
     RECT  62.64 21.803 62.766 22.795 ;
     RECT  98.568 22.205 98.802 22.795 ;
     RECT  185.832 21.617 185.958 22.811 ;
     RECT  209.268 21.884 210.078 22.811 ;
     RECT  2.304 22.037 13.626 22.819 ;
     RECT  14.4 22.037 44.982 22.819 ;
     RECT  65.772 22.424 65.862 22.847 ;
     RECT  73.8 22.685 74.826 22.847 ;
     RECT  102.096 22.505 102.366 22.847 ;
     RECT  113.472 22.781 115.074 22.847 ;
     RECT  196.2 21.731 196.218 22.847 ;
     RECT  207.576 22.589 208.062 22.847 ;
     RECT  62.568 22.795 62.766 22.883 ;
     RECT  77.148 22.343 77.526 22.883 ;
     RECT  193.248 22.271 193.266 22.883 ;
     RECT  212.436 22.379 212.454 22.883 ;
     RECT  48.816 22.445 48.834 22.919 ;
     RECT  62.748 22.883 62.766 22.919 ;
     RECT  66.744 22.469 66.762 22.919 ;
     RECT  119.736 22.637 119.754 22.919 ;
     RECT  167.292 21.695 167.31 22.919 ;
     RECT  185.904 22.811 185.958 22.919 ;
     RECT  194.724 22.613 194.742 22.919 ;
     RECT  46.296 22.235 47.502 22.925 ;
     RECT  61.092 21.617 61.11 22.925 ;
     RECT  49.86 22.694 52.218 22.964 ;
     RECT  102.096 22.847 102.114 22.964 ;
     RECT  113.472 22.847 113.814 22.964 ;
     RECT  125.784 21.617 125.91 22.964 ;
     RECT  185.94 22.919 185.958 22.964 ;
     RECT  207.756 22.847 208.062 22.964 ;
     RECT  50.076 22.964 52.218 23.009 ;
     RECT  67.86 22.694 69.066 23.009 ;
     RECT  107.964 22.109 108.522 23.009 ;
     RECT  114.552 22.847 115.074 23.009 ;
     RECT  125.784 22.964 125.802 23.009 ;
     RECT  170.424 22.154 170.442 23.009 ;
     RECT  216.612 22.775 239.634 23.161 ;
     RECT  2.304 22.819 44.982 23.179 ;
     RECT  2.268 23.179 44.982 23.387 ;
     RECT  2.304 23.387 44.982 23.431 ;
     RECT  0.108 22.109 0.162 23.467 ;
     RECT  216.612 23.161 239.994 23.701 ;
     RECT  241.128 22.009 241.902 23.701 ;
     RECT  2.304 23.431 45.054 23.76 ;
     RECT  46.332 22.925 47.502 23.76 ;
     RECT  50.076 23.009 50.094 23.76 ;
     RECT  50.832 23.009 52.218 23.76 ;
     RECT  55.908 22.739 55.926 23.76 ;
     RECT  58.68 21.767 58.698 23.76 ;
     RECT  64.188 22.271 64.998 23.76 ;
     RECT  65.844 22.847 65.862 23.76 ;
     RECT  67.86 23.009 68.994 23.76 ;
     RECT  71.604 21.767 71.622 23.76 ;
     RECT  73.8 22.847 74.646 23.76 ;
     RECT  76.392 22.649 76.41 23.76 ;
     RECT  81.468 22.541 81.486 23.76 ;
     RECT  82.98 21.773 82.998 23.76 ;
     RECT  87.12 21.965 87.138 23.76 ;
     RECT  89.532 22.541 89.55 23.76 ;
     RECT  90.792 22.271 90.81 23.76 ;
     RECT  92.808 21.695 93.402 23.76 ;
     RECT  96.12 22.577 96.138 23.76 ;
     RECT  98.496 22.795 98.802 23.76 ;
     RECT  99.756 22.205 99.774 23.76 ;
     RECT  103.32 22.061 103.626 23.76 ;
     RECT  108.504 23.009 108.522 23.76 ;
     RECT  109.728 22.694 109.746 23.76 ;
     RECT  111.312 22.505 111.33 23.76 ;
     RECT  112.284 22.505 112.302 23.76 ;
     RECT  113.796 22.964 113.814 23.76 ;
     RECT  115.056 23.009 115.074 23.76 ;
     RECT  117.252 22.637 117.27 23.76 ;
     RECT  136.044 21.533 136.062 23.76 ;
     RECT  154.62 21.569 154.638 23.76 ;
     RECT  171.648 22.307 171.666 23.76 ;
     RECT  176.76 21.539 176.778 23.76 ;
     RECT  181.08 21.695 181.098 23.76 ;
     RECT  197.136 21.731 197.478 23.76 ;
     RECT  201.276 22.073 201.294 23.76 ;
     RECT  207.756 22.964 208.026 23.76 ;
     RECT  209.268 22.811 209.286 23.76 ;
     RECT  210.06 22.811 210.078 23.76 ;
     RECT  213.66 22.307 213.678 23.76 ;
     RECT  216.612 23.701 241.902 23.76 ;
     RECT  0.108 23.467 0.198 23.855 ;
     RECT  0.108 23.855 0.162 23.927 ;
     RECT  1.152 23.083 1.17 24.125 ;
     RECT  2.304 23.76 241.902 24.233 ;
     RECT  2.304 24.233 241.83 24.269 ;
     RECT  2.304 24.269 241.254 24.395 ;
     RECT  2.376 24.395 241.254 24.467 ;
     RECT  0.108 23.927 0.126 24.665 ;
     RECT  2.415 24.467 241.254 24.749 ;
     RECT  2.415 24.749 241.146 24.941 ;
     RECT  2.415 24.941 239.742 25.861 ;
     RECT  240.588 24.941 241.146 25.861 ;
     RECT  2.415 25.861 241.146 26.131 ;
     RECT  2.415 26.131 241.218 26.563 ;
     RECT  2.415 26.563 241.83 26.635 ;
     RECT  1.728 26.635 241.83 26.861 ;
     RECT  0.54 26.905 0.558 27.019 ;
     RECT  0.108 27.019 0.558 27.245 ;
     RECT  1.764 26.861 241.83 27.437 ;
     RECT  2.415 27.437 241.83 28.109 ;
     RECT  2.415 28.109 241.29 28.171 ;
     RECT  2.304 28.171 241.29 28.493 ;
     RECT  0.108 27.245 0.198 28.555 ;
     RECT  2.304 28.493 240.606 28.589 ;
     RECT  0.108 28.555 0.558 29.035 ;
     RECT  0.108 29.035 1.17 29.131 ;
     RECT  2.304 28.589 240.534 29.261 ;
     RECT  0.108 29.131 1.206 29.323 ;
     RECT  2.304 29.261 239.706 29.327 ;
     RECT  2.34 29.327 239.706 29.357 ;
     RECT  240.516 29.261 240.534 29.371 ;
     RECT  241.776 28.831 241.83 29.371 ;
     RECT  240.516 29.371 241.83 29.867 ;
     RECT  2.34 29.357 239.634 30.065 ;
     RECT  0.108 29.323 1.242 30.335 ;
     RECT  2.415 30.065 239.634 30.451 ;
     RECT  0.108 30.335 1.206 30.641 ;
     RECT  0.108 30.641 0.558 30.875 ;
     RECT  0.54 30.875 0.558 30.947 ;
     RECT  241.092 29.867 241.83 30.955 ;
     RECT  2.415 30.451 239.994 31.181 ;
     RECT  241.056 30.955 241.83 31.459 ;
     RECT  2.415 31.181 239.418 31.495 ;
     RECT  240.552 31.459 241.83 31.661 ;
     RECT  2.34 31.495 239.418 32.035 ;
     RECT  241.056 31.661 241.83 32.875 ;
     RECT  2.34 32.035 239.454 32.971 ;
     RECT  240.516 32.875 241.83 32.971 ;
     RECT  2.34 32.971 241.83 33.101 ;
     RECT  2.34 33.101 220.446 33.485 ;
     RECT  2.34 33.485 220.086 33.547 ;
     RECT  221.364 33.101 241.83 33.961 ;
     RECT  221.292 33.961 241.83 34.115 ;
     RECT  1.908 33.547 220.086 34.253 ;
     RECT  221.292 34.115 226.062 34.507 ;
     RECT  220.356 34.603 220.374 34.699 ;
     RECT  220.356 34.699 220.446 34.891 ;
     RECT  221.256 34.507 226.062 34.891 ;
     RECT  1.908 34.253 219.51 34.925 ;
     RECT  220.356 34.891 226.062 34.933 ;
     RECT  226.872 34.115 241.83 34.933 ;
     RECT  1.908 34.925 219.402 35.021 ;
     RECT  220.356 34.933 241.83 35.033 ;
     RECT  226.872 35.033 241.83 35.117 ;
     RECT  241.632 35.117 241.83 35.267 ;
     RECT  1.908 35.021 219.33 35.851 ;
     RECT  220.356 35.033 225.81 35.851 ;
     RECT  226.872 35.117 240.822 35.947 ;
     RECT  241.632 35.267 241.794 35.947 ;
     RECT  220.104 35.851 225.81 35.977 ;
     RECT  226.872 35.947 241.794 35.977 ;
     RECT  220.104 35.977 241.794 36.139 ;
     RECT  220.104 36.139 241.83 36.239 ;
     RECT  1.908 35.851 219.366 36.319 ;
     RECT  220.104 36.239 225.306 36.319 ;
     RECT  226.152 36.239 241.83 36.436 ;
     RECT  1.908 36.319 225.306 36.779 ;
     RECT  1.908 36.779 225.054 36.815 ;
     RECT  226.152 36.436 241.902 36.851 ;
     RECT  227.124 36.851 241.902 36.959 ;
     RECT  226.152 36.851 226.17 37.048 ;
     RECT  1.908 36.815 224.802 37.049 ;
     RECT  225.9 37.048 226.17 37.049 ;
     RECT  225.9 37.049 225.918 37.085 ;
     RECT  1.908 37.049 224.622 37.193 ;
     RECT  43.776 37.193 224.622 37.325 ;
     RECT  43.776 37.325 219.24 37.769 ;
     RECT  227.16 36.959 241.902 37.859 ;
     RECT  227.16 37.859 230.85 37.931 ;
     RECT  228.708 37.931 230.85 38.189 ;
     RECT  44.028 37.769 219.24 38.237 ;
     RECT  1.908 37.193 43.038 38.309 ;
     RECT  44.388 38.237 219.24 38.407 ;
     RECT  220.032 37.325 224.622 38.407 ;
     RECT  44.388 38.407 224.622 38.543 ;
     RECT  44.388 38.543 220.05 38.579 ;
     RECT  228.708 38.189 230.598 38.579 ;
     RECT  231.696 37.859 241.902 38.669 ;
     RECT  231.696 38.669 239.706 38.705 ;
     RECT  1.908 38.309 42.75 38.939 ;
     RECT  221.184 38.543 224.622 38.975 ;
     RECT  44.388 38.579 219.438 38.983 ;
     RECT  240.516 38.669 241.902 39.011 ;
     RECT  221.184 38.975 222.75 39.047 ;
     RECT  1.908 38.939 42.39 39.119 ;
     RECT  221.184 39.047 222.318 39.209 ;
     RECT  43.884 38.983 219.438 39.289 ;
     RECT  1.908 39.119 37.674 39.341 ;
     RECT  43.308 39.289 219.438 39.341 ;
     RECT  223.668 38.975 224.622 39.479 ;
     RECT  241.704 39.011 241.902 39.479 ;
     RECT  221.184 39.209 221.994 39.515 ;
     RECT  44.244 39.341 219.438 39.533 ;
     RECT  221.184 39.515 221.202 39.587 ;
     RECT  234.615 38.705 239.706 39.587 ;
     RECT  240.516 39.011 240.534 39.749 ;
     RECT  44.388 39.533 219.438 39.787 ;
     RECT  234.615 39.587 239.526 39.821 ;
     RECT  237.888 39.821 239.526 39.857 ;
     RECT  38.484 39.119 42.39 39.865 ;
     RECT  43.308 39.341 43.362 39.865 ;
     RECT  237.888 39.857 239.454 39.893 ;
     RECT  1.908 39.341 37.494 39.917 ;
     RECT  0.144 39.055 0.162 39.979 ;
     RECT  237.888 39.893 239.418 40.019 ;
     RECT  241.884 39.479 241.902 40.019 ;
     RECT  239.148 40.019 239.418 40.055 ;
     RECT  238.068 40.019 238.086 40.091 ;
     RECT  0.108 39.979 0.162 40.123 ;
     RECT  239.4 40.055 239.418 40.199 ;
     RECT  0.108 40.123 0.234 40.301 ;
     RECT  38.412 39.865 43.362 40.369 ;
     RECT  44.388 39.787 220.05 40.369 ;
     RECT  38.412 40.369 220.05 40.595 ;
     RECT  1.908 39.917 37.458 40.711 ;
     RECT  38.412 40.595 219.438 40.711 ;
     RECT  239.112 40.909 239.13 40.945 ;
     RECT  238.968 40.945 239.454 40.981 ;
     RECT  0.108 40.301 0.198 41.035 ;
     RECT  38.34 40.711 219.438 41.107 ;
     RECT  234.615 39.821 237.15 41.135 ;
     RECT  234.615 41.135 235.026 41.143 ;
     RECT  236.196 41.135 237.15 41.143 ;
     RECT  236.196 41.143 237.438 41.179 ;
     RECT  241.128 40.909 241.146 41.179 ;
     RECT  1.908 40.711 37.494 41.215 ;
     RECT  238.968 40.981 239.634 41.215 ;
     RECT  236.196 41.179 237.834 41.243 ;
     RECT  1.728 41.215 37.494 41.275 ;
     RECT  38.268 41.107 219.438 41.275 ;
     RECT  237.816 41.243 237.834 41.279 ;
     RECT  238.86 41.215 239.634 41.449 ;
     RECT  238.86 41.449 239.67 41.485 ;
     RECT  238.032 41.485 239.67 41.521 ;
     RECT  231.696 38.705 233.442 41.683 ;
     RECT  238.032 41.521 239.958 41.719 ;
     RECT  241.128 41.179 241.182 41.719 ;
     RECT  221.184 40.939 221.202 41.747 ;
     RECT  231.696 41.683 233.478 41.783 ;
     RECT  228.708 38.579 230.382 41.791 ;
     RECT  231.696 41.783 233.442 42.025 ;
     RECT  228.708 41.791 230.814 42.061 ;
     RECT  231.624 42.025 233.442 42.061 ;
     RECT  1.728 41.275 219.438 42.125 ;
     RECT  227.16 37.931 227.826 42.151 ;
     RECT  228.708 42.061 233.442 42.151 ;
     RECT  234.288 41.143 235.026 42.151 ;
     RECT  238.032 41.719 241.182 42.151 ;
     RECT  222.588 42.061 222.606 42.178 ;
     RECT  1.908 42.125 219.438 42.187 ;
     RECT  220.572 41.995 220.59 42.187 ;
     RECT  222.552 42.178 222.606 42.187 ;
     RECT  223.668 39.479 224.097 42.187 ;
     RECT  226.296 41.659 226.314 42.235 ;
     RECT  237.816 42.151 241.182 42.295 ;
     RECT  226.08 42.235 226.314 42.331 ;
     RECT  236.196 41.243 236.646 42.331 ;
     RECT  237.528 42.295 241.182 42.331 ;
     RECT  234.252 42.151 235.026 42.421 ;
     RECT  226.08 42.331 226.386 42.449 ;
     RECT  1.908 42.187 220.59 42.485 ;
     RECT  222.336 42.187 224.097 42.485 ;
     RECT  226.08 42.449 226.314 42.521 ;
     RECT  227.16 42.151 233.442 42.529 ;
     RECT  234.252 42.421 235.134 42.529 ;
     RECT  0.108 41.035 0.558 42.571 ;
     RECT  221.508 42.571 221.526 42.601 ;
     RECT  222.336 42.485 222.858 42.601 ;
     RECT  227.16 42.529 235.422 42.601 ;
     RECT  236.196 42.331 241.182 42.601 ;
     RECT  227.16 42.601 241.182 42.719 ;
     RECT  38.772 42.485 220.59 42.727 ;
     RECT  0.108 42.571 1.17 42.755 ;
     RECT  221.508 42.601 222.858 42.755 ;
     RECT  226.08 42.521 226.098 42.755 ;
     RECT  227.16 42.719 227.574 42.755 ;
     RECT  0.54 42.755 1.17 42.859 ;
     RECT  1.908 42.485 37.962 42.859 ;
     RECT  227.232 42.755 227.574 42.989 ;
     RECT  227.232 42.989 227.25 43.025 ;
     RECT  0.54 42.859 37.962 43.133 ;
     RECT  38.772 42.727 220.626 43.147 ;
     RECT  221.508 42.755 222.03 43.147 ;
     RECT  38.772 43.147 222.03 43.373 ;
     RECT  228.528 42.719 241.182 43.373 ;
     RECT  1.116 43.133 37.962 43.411 ;
     RECT  38.772 43.373 220.05 43.411 ;
     RECT  221.184 43.373 222.03 43.601 ;
     RECT  228.528 43.373 240.534 43.609 ;
     RECT  1.116 43.411 220.05 43.709 ;
     RECT  223.668 42.485 224.097 43.709 ;
     RECT  222.84 42.755 222.858 43.799 ;
     RECT  221.688 43.601 222.03 43.835 ;
     RECT  226.296 43.681 226.314 43.871 ;
     RECT  228.492 43.609 240.534 43.901 ;
     RECT  225.108 43.915 225.126 43.951 ;
     RECT  225.108 43.951 225.378 44.069 ;
     RECT  225.108 44.069 225.126 44.105 ;
     RECT  1.116 43.709 219.438 44.185 ;
     RECT  228.672 43.901 240.534 44.203 ;
     RECT  241.812 43.681 241.83 44.203 ;
     RECT  228.672 44.203 241.83 44.213 ;
     RECT  221.688 43.835 221.706 44.395 ;
     RECT  229.176 44.213 241.83 44.609 ;
     RECT  221.184 44.395 221.706 44.681 ;
     RECT  232.92 44.609 241.83 44.681 ;
     RECT  229.215 44.609 232.074 44.879 ;
     RECT  232.92 44.681 236.286 44.915 ;
     RECT  0.612 44.185 219.438 44.995 ;
     RECT  221.688 44.681 221.706 45.149 ;
     RECT  229.215 44.879 231.93 45.149 ;
     RECT  229.215 45.149 231.714 45.197 ;
     RECT  0.576 44.995 219.438 45.265 ;
     RECT  229.215 45.197 231.066 45.419 ;
     RECT  230.508 45.419 230.526 45.455 ;
     RECT  232.92 44.915 233.658 45.455 ;
     RECT  235.908 44.915 236.286 45.571 ;
     RECT  237.132 44.681 241.83 45.571 ;
     RECT  234.396 44.915 234.954 45.689 ;
     RECT  235.908 45.571 241.83 45.689 ;
     RECT  233.136 45.455 233.658 45.725 ;
     RECT  0.144 45.265 219.438 45.805 ;
     RECT  233.172 45.725 233.298 45.869 ;
     RECT  233.172 45.869 233.19 45.959 ;
     RECT  234.615 45.689 234.954 45.995 ;
     RECT  235.98 45.689 236.286 46.067 ;
     RECT  236.016 46.067 236.034 46.139 ;
     RECT  0.108 45.805 219.438 46.157 ;
     RECT  237.132 45.689 241.146 46.229 ;
     RECT  237.42 46.229 241.146 46.499 ;
     RECT  221.508 45.451 221.526 46.603 ;
     RECT  237.96 46.499 241.146 46.607 ;
     RECT  221.508 46.603 221.67 46.699 ;
     RECT  237.96 46.607 240.498 46.769 ;
     RECT  238.86 46.769 240.498 47.039 ;
     RECT  238.86 47.039 239.922 47.075 ;
     RECT  0.108 46.157 0.99 47.083 ;
     RECT  1.728 46.157 219.438 47.083 ;
     RECT  239.868 47.075 239.922 47.147 ;
     RECT  221.184 46.699 221.67 47.191 ;
     RECT  0.108 47.083 219.438 47.213 ;
     RECT  239.868 47.147 239.886 47.219 ;
     RECT  221.184 47.191 221.742 47.309 ;
     RECT  221.184 47.309 221.706 47.371 ;
     RECT  221.148 47.371 221.706 47.993 ;
     RECT  0.54 47.213 219.438 48.139 ;
     RECT  221.472 47.993 221.706 48.271 ;
     RECT  221.472 48.271 222.066 48.389 ;
     RECT  221.472 48.389 221.85 48.461 ;
     RECT  221.472 48.461 221.67 48.695 ;
     RECT  220.464 48.235 220.482 49.195 ;
     RECT  220.464 49.195 220.518 49.379 ;
     RECT  221.652 48.695 221.67 49.483 ;
     RECT  220.5 49.379 220.518 49.576 ;
     RECT  221.58 49.483 221.67 49.576 ;
     RECT  220.5 49.576 221.67 49.775 ;
     RECT  0.108 48.139 219.438 50.045 ;
     RECT  0.828 50.045 219.438 50.443 ;
     RECT  220.5 49.775 221.598 50.443 ;
     RECT  0.828 50.443 221.598 50.539 ;
     RECT  0.828 50.539 221.706 50.693 ;
     RECT  221.184 50.693 221.706 50.971 ;
     RECT  221.184 50.971 221.742 51.089 ;
     RECT  221.184 51.089 221.706 51.161 ;
     RECT  0.828 50.693 220.05 51.395 ;
     RECT  221.652 51.161 221.706 51.395 ;
     RECT  220.536 51.787 220.59 52.171 ;
     RECT  221.652 51.395 221.67 52.171 ;
     RECT  0.828 51.395 219.438 52.285 ;
     RECT  220.536 52.171 221.67 52.475 ;
     RECT  220.536 52.475 221.562 52.547 ;
     RECT  220.536 52.547 220.59 52.781 ;
     RECT  220.536 52.781 220.554 53.227 ;
     RECT  0.576 52.285 219.438 53.419 ;
     RECT  220.464 53.227 220.554 53.419 ;
     RECT  0.576 53.419 220.554 53.515 ;
     RECT  221.472 52.547 221.562 53.515 ;
     RECT  0.576 53.515 221.562 54.221 ;
     RECT  0.576 54.221 220.482 54.401 ;
     RECT  221.544 54.221 221.562 54.667 ;
     RECT  221.544 54.667 221.706 54.913 ;
     RECT  221.544 54.913 221.814 55.013 ;
     RECT  221.544 55.013 221.562 55.147 ;
     RECT  0.576 54.401 220.086 55.255 ;
     RECT  0.144 55.255 220.086 55.795 ;
     RECT  221.184 55.147 221.562 55.819 ;
     RECT  0.108 55.795 220.086 55.853 ;
     RECT  0.144 55.853 220.086 55.949 ;
     RECT  221.184 55.819 221.598 56.491 ;
     RECT  0.144 55.949 220.05 56.605 ;
     RECT  221.184 56.491 221.67 56.971 ;
     RECT  0.108 56.605 220.05 57.029 ;
     RECT  0.108 57.029 219.438 57.101 ;
     RECT  0.18 57.101 219.438 57.293 ;
     RECT  221.184 56.971 221.706 57.451 ;
     RECT  220.572 57.451 221.922 57.569 ;
     RECT  220.572 57.569 221.706 57.947 ;
     RECT  0.576 57.293 219.438 58.061 ;
     RECT  221.364 57.947 221.706 58.253 ;
     RECT  220.572 57.947 220.59 58.487 ;
     RECT  1.44 58.061 219.438 58.495 ;
     RECT  1.44 58.495 219.474 58.541 ;
     RECT  221.508 58.253 221.706 58.603 ;
     RECT  221.508 58.603 221.922 58.649 ;
     RECT  221.508 58.649 221.526 58.685 ;
     RECT  0.576 58.061 0.63 59.035 ;
     RECT  221.472 59.197 221.49 59.333 ;
     RECT  0.18 59.035 0.63 59.563 ;
     RECT  1.44 58.541 219.438 59.693 ;
     RECT  0.108 59.563 0.63 59.789 ;
     RECT  221.688 59.659 221.706 60.035 ;
     RECT  1.584 59.693 219.438 60.427 ;
     RECT  221.652 60.235 221.67 60.575 ;
     RECT  0.108 59.789 0.342 61.003 ;
     RECT  1.152 60.427 219.438 61.003 ;
     RECT  221.58 61.483 221.598 61.619 ;
     RECT  220.608 61.501 220.626 61.709 ;
     RECT  0.108 61.003 219.438 61.969 ;
     RECT  0.072 61.969 219.438 61.997 ;
     RECT  221.508 62.059 221.526 62.159 ;
     RECT  221.724 62.581 221.742 62.699 ;
     RECT  220.608 62.671 220.626 62.765 ;
     RECT  0.072 61.997 0.126 62.923 ;
     RECT  0.072 62.923 0.162 63.019 ;
     RECT  0.9 61.997 219.438 63.019 ;
     RECT  221.652 62.923 221.67 63.307 ;
     RECT  221.148 63.307 221.67 63.383 ;
     RECT  221.652 63.383 221.67 63.661 ;
     RECT  221.652 63.661 221.85 63.779 ;
     RECT  0.072 63.019 219.438 63.883 ;
     RECT  0.072 63.883 220.05 64.093 ;
     RECT  0.036 64.093 220.05 64.319 ;
     RECT  221.472 64.171 221.49 64.625 ;
     RECT  220.032 64.319 220.05 65.165 ;
     RECT  0.036 64.319 219.24 68.675 ;
     RECT  0.108 68.675 219.24 70.565 ;
     RECT  0.216 70.565 219.24 70.907 ;
     RECT  0.252 70.907 219.24 71.753 ;
     RECT  0.828 71.753 219.24 72.959 ;
     RECT  44.136 72.959 219.24 73.229 ;
     RECT  0.828 72.959 43.398 73.913 ;
     RECT  1.404 73.913 43.398 74.219 ;
     RECT  1.404 74.219 43.326 75.389 ;
     RECT  1.404 75.389 42.786 75.461 ;
     RECT  1.404 75.461 42.282 75.659 ;
     RECT  1.404 75.659 42.21 75.965 ;
     RECT  2.088 75.965 42.21 76.037 ;
     RECT  2.16 76.037 42.21 77.161 ;
     RECT  2.16 77.161 42.246 77.387 ;
     RECT  2.16 77.387 41.922 77.459 ;
     RECT  2.304 77.459 41.922 77.549 ;
     RECT  2.304 77.549 41.346 77.585 ;
     RECT  2.34 77.585 41.346 77.819 ;
     RECT  2.376 77.819 41.346 78.511 ;
     RECT  2.376 78.511 41.814 78.629 ;
     RECT  2.376 78.629 41.778 79.169 ;
     RECT  2.376 79.169 41.562 79.709 ;
     RECT  2.376 79.709 41.202 80.789 ;
     RECT  2.415 80.789 41.202 81.203 ;
     RECT  2.415 81.203 40.497 81.329 ;
     RECT  41.58 81.211 41.598 81.329 ;
     RECT  2.415 81.329 39.474 81.437 ;
     RECT  2.415 81.437 2.79 81.509 ;
     RECT  3.708 81.437 39.474 81.635 ;
     RECT  3.708 81.635 39.042 81.707 ;
     RECT  4.032 81.707 36.342 81.743 ;
     RECT  4.032 81.743 19.962 81.869 ;
     RECT  20.7 81.743 36.342 81.905 ;
     RECT  37.116 81.707 39.042 82.139 ;
     RECT  37.116 82.139 38.97 82.283 ;
     RECT  38.268 82.283 38.97 82.409 ;
     RECT  4.032 81.869 19.854 82.445 ;
     RECT  38.664 82.409 38.682 82.481 ;
     RECT  26.748 81.905 36.342 82.525 ;
     RECT  37.116 82.283 37.494 82.525 ;
     RECT  20.7 81.905 25.866 82.651 ;
     RECT  4.572 82.445 19.854 82.679 ;
     RECT  26.748 82.525 37.494 82.679 ;
     RECT  4.572 82.679 4.806 82.715 ;
     RECT  5.76 82.679 19.854 82.759 ;
     RECT  4.572 82.715 4.59 82.787 ;
     RECT  5.76 82.759 19.89 82.795 ;
     RECT  20.7 82.651 25.938 82.795 ;
     RECT  26.748 82.679 37.458 82.795 ;
     RECT  5.76 82.795 37.458 83.021 ;
     RECT  5.76 83.021 36.162 83.219 ;
     RECT  37.44 83.021 37.458 83.219 ;
     RECT  5.76 83.219 35.874 83.489 ;
     RECT  5.76 83.489 5.778 83.525 ;
     RECT  6.552 83.489 35.622 83.525 ;
     RECT  6.696 83.525 35.622 83.561 ;
     RECT  7.38 83.561 35.622 83.633 ;
     RECT  7.416 83.633 35.622 83.795 ;
     RECT  7.416 83.795 35.226 83.903 ;
     RECT  7.815 83.903 35.226 84.029 ;
     RECT  11.556 84.029 35.097 84.101 ;
     RECT  11.556 84.101 12.294 84.209 ;
     RECT  7.815 84.029 10.458 84.299 ;
     RECT  11.556 84.209 11.646 84.299 ;
     RECT  13.104 84.101 35.097 84.299 ;
     RECT  8.928 84.299 10.278 84.371 ;
     RECT  9.504 84.371 9.522 84.407 ;
     RECT  13.215 84.299 35.097 84.413 ;
     RECT  13.215 84.413 13.77 84.641 ;
     RECT  14.616 84.413 35.097 84.641 ;
     RECT  14.616 84.641 34.002 84.677 ;
     RECT  14.868 84.677 34.002 84.749 ;
     RECT  14.976 84.749 34.002 84.839 ;
     RECT  16.668 84.839 33.894 84.875 ;
     RECT  17.1 84.875 33.894 84.893 ;
     RECT  14.976 84.839 15.714 84.911 ;
     RECT  17.352 84.893 33.894 84.911 ;
     RECT  15.552 84.911 15.714 84.947 ;
     RECT  15.696 84.947 15.714 84.983 ;
     RECT  17.784 84.911 22.266 84.989 ;
     RECT  23.58 84.911 33.894 84.989 ;
     RECT  17.784 84.989 22.194 85.109 ;
     RECT  23.904 84.989 33.894 85.109 ;
     RECT  22.032 85.109 22.194 85.145 ;
     RECT  17.784 85.109 19.638 85.181 ;
     RECT  20.448 85.109 21.258 85.181 ;
     RECT  22.104 85.145 22.194 85.181 ;
     RECT  18.615 85.181 19.422 85.289 ;
     RECT  22.176 85.181 22.194 85.289 ;
     RECT  17.784 85.181 17.802 85.379 ;
     RECT  18.615 85.289 19.026 85.379 ;
     RECT  20.448 85.181 20.466 85.379 ;
     RECT  23.904 85.109 33.57 85.379 ;
     RECT  21.24 85.181 21.258 85.415 ;
     RECT  28.224 85.379 32.598 85.451 ;
     RECT  23.904 85.379 27.486 85.487 ;
     RECT  28.224 85.451 29.934 85.487 ;
     RECT  31.14 85.451 32.022 85.487 ;
     RECT  33.408 85.379 33.534 85.487 ;
     RECT  23.904 85.487 24.894 85.523 ;
     RECT  25.776 85.487 27.486 85.523 ;
     RECT  33.408 85.487 33.426 85.523 ;
     RECT  28.224 85.487 28.242 85.649 ;
     RECT  29.415 85.487 29.934 85.649 ;
     RECT  31.14 85.487 31.158 85.649 ;
     RECT  25.776 85.523 27.09 85.919 ;
     RECT  25.776 85.919 26.514 85.991 ;
     RECT  26.352 85.991 26.514 86.027 ;
     RECT  26.496 86.027 26.514 86.063 ;
     RECT  44.496 73.229 219.24 94.248 ;
     RECT  45.807 96.373 45.897 96.643 ;
     RECT  51.207 96.373 51.297 96.643 ;
     RECT  56.607 96.373 56.697 96.643 ;
     RECT  62.007 96.373 62.097 96.643 ;
     RECT  67.407 96.373 67.497 96.643 ;
     RECT  72.807 96.373 72.897 96.643 ;
     RECT  78.207 96.373 78.297 96.643 ;
     RECT  83.607 96.373 83.697 96.643 ;
     RECT  89.007 96.373 89.097 96.643 ;
     RECT  94.407 96.373 94.497 96.643 ;
     RECT  99.807 96.373 99.897 96.643 ;
     RECT  105.207 96.373 105.297 96.643 ;
     RECT  110.607 96.373 110.697 96.643 ;
     RECT  116.007 96.373 116.097 96.643 ;
     RECT  121.407 96.373 121.497 96.643 ;
     RECT  126.807 96.373 126.897 96.643 ;
     RECT  132.207 96.373 132.297 96.643 ;
     RECT  137.607 96.373 137.697 96.643 ;
     RECT  143.007 96.373 143.097 96.643 ;
     RECT  148.407 96.373 148.497 96.643 ;
     RECT  153.807 96.373 153.897 96.643 ;
     RECT  159.207 96.373 159.297 96.643 ;
     RECT  164.607 96.373 164.697 96.643 ;
     RECT  170.007 96.373 170.097 96.643 ;
     RECT  175.407 96.373 175.497 96.643 ;
     RECT  180.807 96.373 180.897 96.643 ;
     RECT  186.207 96.373 186.297 96.643 ;
     RECT  191.607 96.373 191.697 96.643 ;
     RECT  197.007 96.373 197.097 96.643 ;
     RECT  202.407 96.373 202.497 96.643 ;
     RECT  207.807 96.373 207.897 96.643 ;
     RECT  213.207 96.373 213.297 96.643 ;
     RECT  218.607 96.373 218.697 96.643 ;
     RECT  2.415 81.509 2.697 114.227 ;
     RECT  7.815 84.299 8.097 114.227 ;
     RECT  13.215 84.641 13.497 114.227 ;
     RECT  18.615 85.379 18.897 114.227 ;
     RECT  24.015 85.523 24.297 114.227 ;
     RECT  29.415 85.649 29.697 114.227 ;
     RECT  34.815 84.641 35.097 114.227 ;
     RECT  40.215 81.329 40.497 114.227 ;
     RECT  45.615 96.643 45.897 114.227 ;
     RECT  51.015 96.643 51.297 114.227 ;
     RECT  56.415 96.643 56.697 114.227 ;
     RECT  61.815 96.643 62.097 114.227 ;
     RECT  67.215 96.643 67.497 114.227 ;
     RECT  72.615 96.643 72.897 114.227 ;
     RECT  78.015 96.643 78.297 114.227 ;
     RECT  83.415 96.643 83.697 114.227 ;
     RECT  88.815 96.643 89.097 114.227 ;
     RECT  94.215 96.643 94.497 114.227 ;
     RECT  99.615 96.643 99.897 114.227 ;
     RECT  105.015 96.643 105.297 114.227 ;
     RECT  110.415 96.643 110.697 114.227 ;
     RECT  115.815 96.643 116.097 114.227 ;
     RECT  121.215 96.643 121.497 114.227 ;
     RECT  126.615 96.643 126.897 114.227 ;
     RECT  132.015 96.643 132.297 114.227 ;
     RECT  137.415 96.643 137.697 114.227 ;
     RECT  142.815 96.643 143.097 114.227 ;
     RECT  148.215 96.643 148.497 114.227 ;
     RECT  153.615 96.643 153.897 114.227 ;
     RECT  159.015 96.643 159.297 114.227 ;
     RECT  164.415 96.643 164.697 114.227 ;
     RECT  169.815 96.643 170.097 114.227 ;
     RECT  175.215 96.643 175.497 114.227 ;
     RECT  180.615 96.643 180.897 114.227 ;
     RECT  186.015 96.643 186.297 114.227 ;
     RECT  191.415 96.643 191.697 114.227 ;
     RECT  196.815 96.643 197.097 114.227 ;
     RECT  202.215 96.643 202.497 114.227 ;
     RECT  207.615 96.643 207.897 114.227 ;
     RECT  213.015 96.643 213.297 114.227 ;
     RECT  218.415 96.643 218.697 114.227 ;
     RECT  223.815 43.709 224.097 114.227 ;
     RECT  229.215 45.419 229.497 114.227 ;
     RECT  234.615 45.995 234.897 114.227 ;
     RECT  2.415 114.227 2.505 114.497 ;
     RECT  7.815 114.227 7.905 114.497 ;
     RECT  13.215 114.227 13.305 114.497 ;
     RECT  18.615 114.227 18.705 114.497 ;
     RECT  24.015 114.227 24.105 114.497 ;
     RECT  29.415 114.227 29.505 114.497 ;
     RECT  34.815 114.227 34.905 114.497 ;
     RECT  40.215 114.227 40.305 114.497 ;
     RECT  45.615 114.227 45.705 114.497 ;
     RECT  51.015 114.227 51.105 114.497 ;
     RECT  56.415 114.227 56.505 114.497 ;
     RECT  61.815 114.227 61.905 114.497 ;
     RECT  67.215 114.227 67.305 114.497 ;
     RECT  72.615 114.227 72.705 114.497 ;
     RECT  78.015 114.227 78.105 114.497 ;
     RECT  83.415 114.227 83.505 114.497 ;
     RECT  88.815 114.227 88.905 114.497 ;
     RECT  94.215 114.227 94.305 114.497 ;
     RECT  99.615 114.227 99.705 114.497 ;
     RECT  105.015 114.227 105.105 114.497 ;
     RECT  110.415 114.227 110.505 114.497 ;
     RECT  115.815 114.227 115.905 114.497 ;
     RECT  121.215 114.227 121.305 114.497 ;
     RECT  126.615 114.227 126.705 114.497 ;
     RECT  132.015 114.227 132.105 114.497 ;
     RECT  137.415 114.227 137.505 114.497 ;
     RECT  142.815 114.227 142.905 114.497 ;
     RECT  148.215 114.227 148.305 114.497 ;
     RECT  153.615 114.227 153.705 114.497 ;
     RECT  159.015 114.227 159.105 114.497 ;
     RECT  164.415 114.227 164.505 114.497 ;
     RECT  169.815 114.227 169.905 114.497 ;
     RECT  175.215 114.227 175.305 114.497 ;
     RECT  180.615 114.227 180.705 114.497 ;
     RECT  186.015 114.227 186.105 114.497 ;
     RECT  191.415 114.227 191.505 114.497 ;
     RECT  196.815 114.227 196.905 114.497 ;
     RECT  202.215 114.227 202.305 114.497 ;
     RECT  207.615 114.227 207.705 114.497 ;
     RECT  213.015 114.227 213.105 114.497 ;
     RECT  218.415 114.227 218.505 114.497 ;
     RECT  223.815 114.227 223.905 114.497 ;
     RECT  229.215 114.227 229.305 114.497 ;
     RECT  234.615 114.227 234.705 114.497 ;
    LAYER M4 ;
     RECT  0.06 12.72 0.133 23.688 ;
     RECT  0.06 46.032 0.137 49.032 ;
     RECT  0.133 12.72 0.569 24.648 ;
     RECT  0.137 46.128 1.145 49.032 ;
     RECT  0.06 39.888 1.217 42.888 ;
     RECT  0.06 55.248 1.217 68.232 ;
     RECT  1.145 46.224 1.289 49.032 ;
     RECT  1.609 73.824 1.621 73.848 ;
     RECT  1.217 39.888 1.669 42.792 ;
     RECT  1.621 72.96 1.669 73.848 ;
     RECT  1.669 72 2.252 73.848 ;
     RECT  2.252 71.28 2.293 73.848 ;
     RECT  1.681 75.504 2.293 75.528 ;
     RECT  1.621 52.752 2.329 52.776 ;
     RECT  1.217 55.248 2.329 68.136 ;
     RECT  2.293 71.28 2.329 73.896 ;
     RECT  2.293 74.88 2.329 75.528 ;
     RECT  1.289 46.224 2.365 48.936 ;
     RECT  2.329 70.8 2.365 75.528 ;
     RECT  2.365 70.272 2.401 75.528 ;
     RECT  0.569 12.72 2.408 19.848 ;
     RECT  0.569 20.976 2.408 24.648 ;
     RECT  0.06 26.832 2.408 29.832 ;
     RECT  2.329 32.208 2.408 32.232 ;
     RECT  2.329 35.28 2.408 35.304 ;
     RECT  2.329 36.864 2.408 36.888 ;
     RECT  2.401 37.872 2.408 37.896 ;
     RECT  1.669 39.552 2.408 42.792 ;
     RECT  2.365 45.552 2.408 49.08 ;
     RECT  2.329 52.032 2.408 52.776 ;
     RECT  2.329 54.384 2.408 68.184 ;
     RECT  2.401 70.272 2.408 76.296 ;
     RECT  2.365 77.952 2.408 77.976 ;
     RECT  2.245 80.544 2.408 80.568 ;
     RECT  2.408 2.148 2.512 114.492 ;
     RECT  2.512 2.418 2.704 114.222 ;
     RECT  2.704 13.584 2.765 26.76 ;
     RECT  2.704 28.272 2.765 30.216 ;
     RECT  2.704 36.816 2.873 61.416 ;
     RECT  2.873 36.816 2.909 60.84 ;
     RECT  2.909 36.816 2.989 60.744 ;
     RECT  2.704 35.28 3.692 35.688 ;
     RECT  2.989 36.816 3.692 58.68 ;
     RECT  2.765 13.584 3.769 13.704 ;
     RECT  2.765 14.784 3.769 26.76 ;
     RECT  2.765 28.464 3.769 30.216 ;
     RECT  2.704 32.208 3.769 33.192 ;
     RECT  3.769 31.92 3.809 33.192 ;
     RECT  2.704 62.448 3.841 81.432 ;
     RECT  3.769 13.584 3.953 30.216 ;
     RECT  3.841 62.448 3.985 81.48 ;
     RECT  3.953 14.064 4.057 30.216 ;
     RECT  3.692 35.28 4.057 58.68 ;
     RECT  2.989 59.856 4.057 60.744 ;
     RECT  2.704 11.376 4.124 11.448 ;
     RECT  2.704 12.528 4.172 12.552 ;
     RECT  4.057 35.184 4.172 58.68 ;
     RECT  3.809 32.976 4.201 33.192 ;
     RECT  4.057 59.856 4.237 60.984 ;
     RECT  3.985 61.968 4.237 81.48 ;
     RECT  4.237 59.856 4.313 81.48 ;
     RECT  4.172 35.04 4.345 58.68 ;
     RECT  4.313 59.856 4.345 63.24 ;
     RECT  4.124 11.04 4.381 11.448 ;
     RECT  4.057 14.064 4.381 30.84 ;
     RECT  3.809 31.92 4.381 31.944 ;
     RECT  4.345 35.04 4.385 63.24 ;
     RECT  4.385 35.04 4.547 60.024 ;
     RECT  4.385 61.008 4.565 63.24 ;
     RECT  4.381 14.064 4.637 31.944 ;
     RECT  4.565 61.248 4.637 63.24 ;
     RECT  4.637 61.488 4.673 63.24 ;
     RECT  4.547 35.04 4.813 35.304 ;
     RECT  4.313 64.32 4.813 81.48 ;
     RECT  4.637 15.456 4.817 31.944 ;
     RECT  4.813 34.752 4.853 35.304 ;
     RECT  4.813 64.32 4.885 82.056 ;
     RECT  4.817 15.6 4.981 31.944 ;
     RECT  4.201 32.976 4.981 33.24 ;
     RECT  4.981 15.6 4.993 33.24 ;
     RECT  4.172 12.528 5.029 13.08 ;
     RECT  4.637 14.064 5.029 14.136 ;
     RECT  4.381 11.04 5.173 11.496 ;
     RECT  5.029 12.528 5.173 14.136 ;
     RECT  4.853 34.752 5.353 35.256 ;
     RECT  4.885 64.32 5.507 82.104 ;
     RECT  4.547 36.48 5.653 60.024 ;
     RECT  5.641 9.936 5.669 9.96 ;
     RECT  5.173 11.04 5.669 14.136 ;
     RECT  5.653 36.432 5.713 60.024 ;
     RECT  5.507 81.408 5.749 82.104 ;
     RECT  5.669 9.936 5.753 14.136 ;
     RECT  5.713 36.432 5.753 60.6 ;
     RECT  4.673 62.112 5.789 63.24 ;
     RECT  5.507 64.32 5.789 80.28 ;
     RECT  5.753 11.424 5.929 14.136 ;
     RECT  5.789 79.44 6.005 80.28 ;
     RECT  5.753 36.72 6.037 60.6 ;
     RECT  4.993 15.6 6.073 33.624 ;
     RECT  5.353 34.608 6.073 35.256 ;
     RECT  5.789 62.208 6.073 63.24 ;
     RECT  5.789 64.32 6.073 78.168 ;
     RECT  6.073 62.208 6.149 78.168 ;
     RECT  5.749 81.408 6.149 82.968 ;
     RECT  6.037 36.72 6.181 60.744 ;
     RECT  6.181 36.72 6.365 60.984 ;
     RECT  5.929 11.424 6.505 14.28 ;
     RECT  6.073 15.6 6.505 35.256 ;
     RECT  6.365 37.152 6.509 60.984 ;
     RECT  5.753 9.936 6.721 9.96 ;
     RECT  6.505 11.424 6.721 35.256 ;
     RECT  6.721 9.936 6.829 35.448 ;
     RECT  6.509 37.392 7.093 60.984 ;
     RECT  6.149 62.208 7.093 78.12 ;
     RECT  6.829 9.792 7.261 35.448 ;
     RECT  6.005 79.44 7.297 79.464 ;
     RECT  6.149 82.272 7.405 82.968 ;
     RECT  7.657 7.92 7.808 7.944 ;
     RECT  7.261 9.072 7.808 35.448 ;
     RECT  7.093 37.392 7.808 78.12 ;
     RECT  7.297 79.2 7.808 79.464 ;
     RECT  7.405 81.504 7.808 82.968 ;
     RECT  7.808 2.148 7.912 114.492 ;
     RECT  7.912 2.418 8.104 114.222 ;
     RECT  8.104 10.08 8.237 29.352 ;
     RECT  8.104 30.336 8.309 79.848 ;
     RECT  8.237 10.176 8.345 29.352 ;
     RECT  8.309 38.208 8.597 79.848 ;
     RECT  8.309 30.336 8.627 37.128 ;
     RECT  8.104 7.92 9.097 8.52 ;
     RECT  8.104 82.224 9.349 83.592 ;
     RECT  9.349 82.08 9.353 83.592 ;
     RECT  9.097 7.92 9.356 9.096 ;
     RECT  8.345 10.176 9.385 29.304 ;
     RECT  8.627 30.336 9.385 36.36 ;
     RECT  9.356 7.872 9.493 9.096 ;
     RECT  8.597 38.208 9.493 79.752 ;
     RECT  9.493 7.008 9.529 9.096 ;
     RECT  9.385 10.176 9.529 36.36 ;
     RECT  9.529 7.008 9.637 36.36 ;
     RECT  9.493 37.44 9.637 79.752 ;
     RECT  9.353 82.08 9.641 83.256 ;
     RECT  9.637 7.008 9.749 79.752 ;
     RECT  9.641 82.08 9.929 83.064 ;
     RECT  8.104 5.712 10.069 5.736 ;
     RECT  9.749 7.008 10.069 79.704 ;
     RECT  10.069 5.712 10.649 79.704 ;
     RECT  10.649 8.496 10.717 79.704 ;
     RECT  10.717 8.496 10.789 80.376 ;
     RECT  10.649 5.712 10.829 7.368 ;
     RECT  9.929 82.368 10.835 83.064 ;
     RECT  10.789 8.496 11.045 80.616 ;
     RECT  10.835 82.992 11.173 83.064 ;
     RECT  11.045 17.616 11.253 80.616 ;
     RECT  11.045 8.496 11.297 16.632 ;
     RECT  11.253 30.48 11.369 80.616 ;
     RECT  11.297 12.864 11.693 16.632 ;
     RECT  10.829 7.056 11.905 7.368 ;
     RECT  11.297 8.496 11.909 11.832 ;
     RECT  10.829 5.712 11.996 5.784 ;
     RECT  11.905 6.816 12.013 7.368 ;
     RECT  11.909 8.496 12.013 11.688 ;
     RECT  11.253 17.616 12.121 29.352 ;
     RECT  11.173 82.992 12.125 83.832 ;
     RECT  12.125 83.088 12.161 83.832 ;
     RECT  11.996 5.184 12.193 5.784 ;
     RECT  12.013 6.816 12.193 11.688 ;
     RECT  12.121 16.8 12.265 29.352 ;
     RECT  11.369 30.48 12.265 37.608 ;
     RECT  12.265 16.8 12.373 37.608 ;
     RECT  11.369 38.688 12.373 80.616 ;
     RECT  12.037 3.984 12.517 4.008 ;
     RECT  12.517 3.84 12.589 4.008 ;
     RECT  12.589 3.84 12.877 4.056 ;
     RECT  12.193 5.184 12.877 11.688 ;
     RECT  12.805 0.24 12.997 0.264 ;
     RECT  12.877 3.84 13.057 11.688 ;
     RECT  11.693 12.864 13.093 15.768 ;
     RECT  12.373 16.8 13.093 80.616 ;
     RECT  12.161 83.808 13.093 83.832 ;
     RECT  12.997 0.24 13.133 1.176 ;
     RECT  13.133 0.24 13.138 1.128 ;
     RECT  13.138 0.144 13.201 1.128 ;
     RECT  13.057 3.84 13.208 11.736 ;
     RECT  13.093 12.864 13.208 80.616 ;
     RECT  13.093 82.272 13.208 82.296 ;
     RECT  13.093 83.808 13.208 84.168 ;
     RECT  13.208 2.148 13.312 114.492 ;
     RECT  13.312 2.148 13.504 114.222 ;
     RECT  13.504 17.664 13.619 84.408 ;
     RECT  13.504 16.368 13.889 16.392 ;
     RECT  13.619 34.368 14.213 84.408 ;
     RECT  13.201 0.048 14.245 1.128 ;
     RECT  14.213 41.04 14.249 84.408 ;
     RECT  13.619 17.664 14.285 33.336 ;
     RECT  14.213 34.368 14.429 39.912 ;
     RECT  14.249 41.088 14.429 84.408 ;
     RECT  14.429 41.136 14.435 84.408 ;
     RECT  14.285 17.664 14.569 31.224 ;
     RECT  13.504 2.88 14.581 9.096 ;
     RECT  13.504 10.176 14.581 14.664 ;
     RECT  14.435 41.136 14.717 81.096 ;
     RECT  14.435 82.272 15.005 84.408 ;
     RECT  14.569 17.424 15.037 31.224 ;
     RECT  15.037 17.04 15.068 31.224 ;
     RECT  14.581 2.88 15.109 14.664 ;
     RECT  15.068 16.128 15.109 31.224 ;
     RECT  14.245 0.048 15.205 1.704 ;
     RECT  15.109 2.88 15.244 31.224 ;
     RECT  14.717 41.136 15.329 77.304 ;
     RECT  15.244 2.88 15.395 31.176 ;
     RECT  15.395 2.88 15.401 15 ;
     RECT  14.285 32.448 15.433 33.336 ;
     RECT  14.429 34.368 15.433 39.816 ;
     RECT  15.329 41.136 15.577 75.768 ;
     RECT  15.401 14.4 15.761 15 ;
     RECT  15.205 0.048 15.781 1.752 ;
     RECT  15.401 2.88 15.781 13.176 ;
     RECT  15.433 32.448 15.829 39.816 ;
     RECT  15.577 41.04 15.829 75.768 ;
     RECT  14.717 78.432 15.973 81.096 ;
     RECT  15.005 82.272 16.081 83.88 ;
     RECT  16.081 82.272 16.117 84.456 ;
     RECT  15.781 0.048 16.337 13.176 ;
     RECT  15.761 14.448 16.405 15 ;
     RECT  15.395 16.272 16.405 31.176 ;
     RECT  15.329 76.8 16.405 77.304 ;
     RECT  15.973 78.432 16.405 81.144 ;
     RECT  16.337 0.048 16.409 12.024 ;
     RECT  15.829 32.448 16.441 75.768 ;
     RECT  16.441 32.208 16.513 75.768 ;
     RECT  16.405 76.8 16.513 81.144 ;
     RECT  16.409 1.728 16.553 12.024 ;
     RECT  16.117 82.224 16.553 84.456 ;
     RECT  16.553 83.04 16.589 84.456 ;
     RECT  16.513 32.208 16.697 81.144 ;
     RECT  16.337 13.056 16.765 13.176 ;
     RECT  16.405 14.448 16.765 31.176 ;
     RECT  16.697 32.208 16.765 79.704 ;
     RECT  16.765 13.056 16.835 79.704 ;
     RECT  16.553 1.728 16.913 11.688 ;
     RECT  16.589 84.384 17.017 84.456 ;
     RECT  16.697 80.832 17.053 81.144 ;
     RECT  16.835 13.152 17.075 79.704 ;
     RECT  17.017 84.384 17.089 84.552 ;
     RECT  17.053 80.832 17.165 82.008 ;
     RECT  16.913 1.776 17.237 2.424 ;
     RECT  16.589 83.04 17.629 83.352 ;
     RECT  17.089 84.384 17.773 84.888 ;
     RECT  17.237 1.824 17.849 2.424 ;
     RECT  17.849 1.872 17.881 2.424 ;
     RECT  16.913 3.6 17.881 11.688 ;
     RECT  17.881 1.872 17.917 11.688 ;
     RECT  17.917 1.872 17.921 11.976 ;
     RECT  17.921 2.148 17.953 11.976 ;
     RECT  17.075 13.152 17.953 79.608 ;
     RECT  17.953 2.148 18.277 79.608 ;
     RECT  17.165 80.832 18.277 81.144 ;
     RECT  18.277 2.148 18.469 81.144 ;
     RECT  17.629 82.944 18.469 83.352 ;
     RECT  18.469 2.148 18.608 83.352 ;
     RECT  17.773 84.384 18.608 84.984 ;
     RECT  18.608 2.148 18.712 114.492 ;
     RECT  18.712 2.418 18.904 114.222 ;
     RECT  18.904 13.152 18.965 36.36 ;
     RECT  18.965 14.256 19.001 36.36 ;
     RECT  18.904 37.392 19.043 84.984 ;
     RECT  19.043 37.392 19.139 84.36 ;
     RECT  19.139 40.848 19.397 84.36 ;
     RECT  18.904 2.418 19.613 11.832 ;
     RECT  19.139 37.392 19.685 39.816 ;
     RECT  19.397 40.848 19.721 81.672 ;
     RECT  19.721 40.848 19.901 81.096 ;
     RECT  19.82 2.256 19.907 2.28 ;
     RECT  19.001 14.256 20.005 36.072 ;
     RECT  19.685 37.392 20.005 39.768 ;
     RECT  19.613 3.264 20.153 11.832 ;
     RECT  19.901 80.256 20.153 81.096 ;
     RECT  20.153 3.312 20.401 11.832 ;
     RECT  20.401 3.312 20.437 12.072 ;
     RECT  18.965 13.152 20.437 13.176 ;
     RECT  19.397 82.752 20.437 84.36 ;
     RECT  20.437 3.312 20.653 13.176 ;
     RECT  20.005 14.256 20.653 39.768 ;
     RECT  20.153 80.496 20.761 81.096 ;
     RECT  20.437 82.752 20.761 84.984 ;
     RECT  19.901 40.848 20.765 79.224 ;
     RECT  20.653 3.312 20.873 39.768 ;
     RECT  20.765 40.848 21.301 78.984 ;
     RECT  21.301 40.8 21.805 78.984 ;
     RECT  20.761 80.496 21.917 84.984 ;
     RECT  20.873 3.312 22.273 4.008 ;
     RECT  20.873 4.992 22.273 39.768 ;
     RECT  21.917 81.072 22.313 84.984 ;
     RECT  21.805 40.8 22.385 79.512 ;
     RECT  22.273 3.312 22.417 39.768 ;
     RECT  22.385 40.8 22.417 77.016 ;
     RECT  22.313 81.072 22.853 83.928 ;
     RECT  22.853 81.072 23.353 81.144 ;
     RECT  22.417 3.312 23.641 77.016 ;
     RECT  23.641 3.312 23.785 77.16 ;
     RECT  23.785 2.832 23.893 77.16 ;
     RECT  22.385 78.144 23.893 79.512 ;
     RECT  22.853 82.704 23.929 83.928 ;
     RECT  22.313 84.96 23.929 84.984 ;
     RECT  23.893 2.832 24.008 79.512 ;
     RECT  23.353 80.88 24.008 81.144 ;
     RECT  23.929 82.704 24.008 84.984 ;
     RECT  24.008 2.148 24.112 114.492 ;
     RECT  24.112 2.418 24.304 114.222 ;
     RECT  24.304 84.048 24.545 84.984 ;
     RECT  24.304 2.832 24.941 81.336 ;
     RECT  24.941 2.832 25.085 76.968 ;
     RECT  25.085 2.832 25.121 76.392 ;
     RECT  24.304 82.416 25.193 83.016 ;
     RECT  24.941 78.144 25.229 81.336 ;
     RECT  25.229 78.144 25.265 80.04 ;
     RECT  25.121 36.864 25.337 76.392 ;
     RECT  25.193 82.704 25.549 83.016 ;
     RECT  24.545 84.048 25.549 84.408 ;
     RECT  25.549 82.704 25.589 84.408 ;
     RECT  25.337 36.864 25.661 75.912 ;
     RECT  25.661 36.864 25.667 72.792 ;
     RECT  25.589 82.752 25.805 84.408 ;
     RECT  25.667 71.136 25.949 72.792 ;
     RECT  25.265 78.144 26.053 79.992 ;
     RECT  25.121 2.832 26.101 35.688 ;
     RECT  25.667 36.864 26.101 70.152 ;
     RECT  25.229 81.312 26.197 81.336 ;
     RECT  25.805 83.184 26.269 84.408 ;
     RECT  26.101 2.832 26.489 70.152 ;
     RECT  26.053 77.52 26.579 79.992 ;
     RECT  26.489 41.184 26.597 70.152 ;
     RECT  25.661 74.064 26.629 75.912 ;
     RECT  26.579 77.52 26.701 78.888 ;
     RECT  26.629 74.064 26.773 75.96 ;
     RECT  26.597 41.232 26.809 70.152 ;
     RECT  25.949 71.136 26.809 71.976 ;
     RECT  26.197 81.12 26.809 81.336 ;
     RECT  26.701 76.992 26.813 78.888 ;
     RECT  26.809 81.12 26.845 81.96 ;
     RECT  26.489 2.832 26.921 40.152 ;
     RECT  26.809 41.232 26.989 71.976 ;
     RECT  26.773 72.96 26.989 75.96 ;
     RECT  26.845 80.304 27.065 81.96 ;
     RECT  26.813 76.992 27.173 77.016 ;
     RECT  26.921 2.832 27.281 13.32 ;
     RECT  26.269 83.184 27.349 84.504 ;
     RECT  25.765 85.488 27.349 85.512 ;
     RECT  27.349 82.608 27.497 85.512 ;
     RECT  27.065 80.304 27.605 81.336 ;
     RECT  26.921 14.352 27.745 40.152 ;
     RECT  26.989 41.232 27.745 75.96 ;
     RECT  27.745 14.352 27.853 75.96 ;
     RECT  27.497 82.608 27.929 84.984 ;
     RECT  27.281 2.928 27.997 13.32 ;
     RECT  27.853 14.352 27.997 76.92 ;
     RECT  27.997 2.928 28.109 76.92 ;
     RECT  26.813 78.48 28.177 78.888 ;
     RECT  28.177 78.48 28.321 79.224 ;
     RECT  27.929 82.608 28.465 83.784 ;
     RECT  28.321 78.192 28.789 79.224 ;
     RECT  28.465 82.512 28.789 83.784 ;
     RECT  28.109 2.928 28.825 12.024 ;
     RECT  28.109 13.152 28.969 76.92 ;
     RECT  28.789 78.096 28.969 79.224 ;
     RECT  28.969 13.152 29.173 79.224 ;
     RECT  28.825 2.784 29.408 12.024 ;
     RECT  29.173 13.152 29.408 79.272 ;
     RECT  27.605 80.304 29.408 80.904 ;
     RECT  28.789 82.464 29.408 83.784 ;
     RECT  27.929 84.96 29.408 84.984 ;
     RECT  29.408 2.148 29.512 114.492 ;
     RECT  29.512 2.418 29.704 114.222 ;
     RECT  29.704 2.784 29.765 73.368 ;
     RECT  29.765 2.784 30.179 44.28 ;
     RECT  29.765 45.504 30.419 73.368 ;
     RECT  29.704 80.304 30.449 80.808 ;
     RECT  29.704 81.84 30.521 82.68 ;
     RECT  29.704 74.352 30.593 79.08 ;
     RECT  30.419 45.504 30.611 50.184 ;
     RECT  30.521 82.416 30.665 82.68 ;
     RECT  30.179 2.784 30.697 43.896 ;
     RECT  30.593 74.352 30.737 76.968 ;
     RECT  30.611 45.504 30.769 50.136 ;
     RECT  30.419 51.168 30.769 73.368 ;
     RECT  30.737 74.352 30.769 76.632 ;
     RECT  30.593 78.144 30.809 79.08 ;
     RECT  30.697 2.544 30.841 43.896 ;
     RECT  30.769 45.36 30.853 50.136 ;
     RECT  30.449 80.304 30.877 80.328 ;
     RECT  29.704 84.336 31.021 84.456 ;
     RECT  30.853 45.312 31.187 50.136 ;
     RECT  31.187 45.312 31.241 47.64 ;
     RECT  30.665 82.512 31.273 82.68 ;
     RECT  31.021 84.336 31.273 85.128 ;
     RECT  30.841 2.304 31.283 43.896 ;
     RECT  31.283 2.304 31.349 43.848 ;
     RECT  31.241 47.424 31.379 47.64 ;
     RECT  30.877 80.256 31.453 80.328 ;
     RECT  31.241 45.312 31.597 46.296 ;
     RECT  31.187 48.72 31.633 50.136 ;
     RECT  30.769 51.168 31.633 76.632 ;
     RECT  31.349 2.304 31.673 43.8 ;
     RECT  31.633 48.72 31.673 76.632 ;
     RECT  30.809 78.624 31.813 79.08 ;
     RECT  31.673 2.4 31.817 43.8 ;
     RECT  31.273 82.512 31.853 85.128 ;
     RECT  31.813 78.144 31.957 79.08 ;
     RECT  31.453 80.208 31.957 81.192 ;
     RECT  31.817 2.544 32.069 43.8 ;
     RECT  31.853 82.512 32.204 82.68 ;
     RECT  31.379 47.616 32.281 47.64 ;
     RECT  31.673 48.72 32.281 49.8 ;
     RECT  32.069 35.136 32.389 43.8 ;
     RECT  32.389 35.136 32.435 43.944 ;
     RECT  31.853 83.76 32.609 85.128 ;
     RECT  32.069 2.544 32.645 33.96 ;
     RECT  32.435 35.136 32.771 40.248 ;
     RECT  32.281 47.616 32.821 49.8 ;
     RECT  31.673 50.928 32.821 76.632 ;
     RECT  32.771 39.744 32.897 40.248 ;
     RECT  32.609 83.76 32.933 84.888 ;
     RECT  31.957 78.144 33.037 81.192 ;
     RECT  33.037 77.952 33.041 81.192 ;
     RECT  32.771 35.136 33.059 38.664 ;
     RECT  32.821 47.616 33.073 76.632 ;
     RECT  31.597 45.024 33.113 46.296 ;
     RECT  33.059 35.136 33.181 36.648 ;
     RECT  33.041 77.952 33.181 81.048 ;
     RECT  33.059 37.728 33.203 38.664 ;
     RECT  33.073 47.28 33.217 76.632 ;
     RECT  32.204 82.176 33.257 82.68 ;
     RECT  32.435 41.376 33.293 43.944 ;
     RECT  33.217 46.896 33.401 76.632 ;
     RECT  32.933 83.808 33.473 84.888 ;
     RECT  33.181 35.04 33.493 36.648 ;
     RECT  32.645 2.88 33.541 33.96 ;
     RECT  33.493 34.944 33.541 36.648 ;
     RECT  33.473 84 33.545 84.888 ;
     RECT  33.181 77.904 33.761 81.048 ;
     RECT  33.203 38.4 33.865 38.664 ;
     RECT  32.897 39.744 33.865 40.008 ;
     RECT  33.293 41.376 33.865 43.8 ;
     RECT  33.113 45.024 34.153 45.816 ;
     RECT  33.401 46.896 34.153 75.048 ;
     RECT  33.865 38.4 34.165 38.76 ;
     RECT  33.865 39.744 34.165 43.8 ;
     RECT  33.401 76.464 34.261 76.632 ;
     RECT  33.761 77.904 34.261 78.744 ;
     RECT  34.153 45.024 34.621 75.048 ;
     RECT  33.257 82.416 34.621 82.68 ;
     RECT  34.165 38.4 34.728 43.8 ;
     RECT  34.728 38.4 34.729 43.944 ;
     RECT  34.621 45.024 34.729 75.24 ;
     RECT  34.621 82.416 34.729 83.064 ;
     RECT  33.541 2.88 34.808 36.648 ;
     RECT  34.729 38.4 34.808 75.24 ;
     RECT  34.261 76.464 34.808 78.744 ;
     RECT  33.761 79.728 34.808 81.048 ;
     RECT  34.729 82.416 34.808 83.352 ;
     RECT  33.545 84.336 34.808 84.888 ;
     RECT  34.808 2.148 34.912 114.492 ;
     RECT  34.912 2.418 35.104 114.222 ;
     RECT  35.104 2.88 35.201 37.032 ;
     RECT  35.201 32.208 35.309 37.032 ;
     RECT  35.309 32.208 35.381 36.84 ;
     RECT  35.381 32.208 35.489 36.648 ;
     RECT  35.104 45.456 35.548 83.736 ;
     RECT  35.548 82.416 35.561 83.736 ;
     RECT  35.489 32.208 35.597 36.504 ;
     RECT  35.561 82.416 35.885 83.352 ;
     RECT  35.885 82.416 36.101 83.064 ;
     RECT  36.101 82.464 36.137 83.064 ;
     RECT  35.548 45.456 36.281 81.432 ;
     RECT  36.137 82.464 36.317 83.016 ;
     RECT  35.201 2.88 36.713 30.888 ;
     RECT  35.597 32.208 36.853 32.856 ;
     RECT  35.597 33.84 36.853 36.504 ;
     RECT  35.104 39.216 37.033 44.472 ;
     RECT  36.281 45.456 37.033 77.496 ;
     RECT  36.713 3.264 37.073 30.888 ;
     RECT  36.317 82.992 37.145 83.016 ;
     RECT  36.853 32.208 37.321 36.504 ;
     RECT  37.033 38.352 37.505 77.496 ;
     RECT  36.281 78.528 37.621 81.432 ;
     RECT  37.505 38.352 37.685 39.336 ;
     RECT  37.073 3.264 37.717 30.84 ;
     RECT  37.717 2.784 37.829 30.84 ;
     RECT  37.321 32.208 37.861 36.648 ;
     RECT  37.505 40.752 38.041 77.496 ;
     RECT  37.621 78.528 38.041 82.248 ;
     RECT  38.041 40.752 38.081 82.248 ;
     RECT  38.081 40.752 38.189 81.432 ;
     RECT  37.829 2.784 38.405 28.824 ;
     RECT  37.861 32.208 38.437 36.936 ;
     RECT  38.189 79.008 38.513 81.432 ;
     RECT  38.437 32.208 38.545 37.272 ;
     RECT  37.685 38.352 38.545 39.24 ;
     RECT  37.829 29.904 38.557 30.84 ;
     RECT  38.545 32.208 38.689 39.24 ;
     RECT  38.189 40.752 38.729 77.976 ;
     RECT  38.689 31.152 38.761 39.24 ;
     RECT  38.729 40.752 38.761 77.592 ;
     RECT  38.513 79.872 38.909 81.432 ;
     RECT  38.405 2.832 39.26 28.824 ;
     RECT  38.557 29.904 39.26 30.072 ;
     RECT  39.26 2.832 39.589 30.072 ;
     RECT  38.761 31.152 39.589 77.592 ;
     RECT  38.909 79.872 40.069 81.336 ;
     RECT  39.589 2.832 40.165 77.592 ;
     RECT  40.165 2.784 40.208 77.592 ;
     RECT  40.069 79.776 40.208 81.336 ;
     RECT  40.208 2.148 40.312 114.492 ;
     RECT  40.312 2.418 40.504 114.222 ;
     RECT  40.504 2.784 40.643 78.12 ;
     RECT  40.643 2.784 41.213 77.592 ;
     RECT  41.213 2.784 41.321 76.632 ;
     RECT  41.321 2.784 41.533 76.344 ;
     RECT  41.533 2.736 41.609 76.344 ;
     RECT  41.609 75.84 41.681 76.104 ;
     RECT  41.609 2.736 41.713 64.392 ;
     RECT  41.681 75.84 41.861 75.864 ;
     RECT  41.609 65.568 41.897 74.808 ;
     RECT  41.897 65.568 41.933 71.352 ;
     RECT  41.897 72.384 41.933 74.808 ;
     RECT  41.713 2.304 41.969 64.392 ;
     RECT  41.933 65.568 41.987 69.576 ;
     RECT  41.969 5.856 42.041 64.392 ;
     RECT  41.933 72.816 42.074 74.808 ;
     RECT  41.933 70.848 42.113 71.352 ;
     RECT  41.987 65.568 42.149 69.384 ;
     RECT  42.113 70.848 42.149 70.872 ;
     RECT  42.041 5.856 42.185 59.304 ;
     RECT  42.074 72.816 42.221 74.76 ;
     RECT  42.221 74.688 42.29 74.76 ;
     RECT  42.041 60.432 42.293 64.392 ;
     RECT  42.149 66 42.329 69.384 ;
     RECT  42.221 72.816 42.365 73.272 ;
     RECT  42.329 66 42.371 68.952 ;
     RECT  42.29 74.688 42.373 74.712 ;
     RECT  42.371 66.72 42.617 68.952 ;
     RECT  42.617 66.72 42.761 67.32 ;
     RECT  42.761 67.296 42.797 67.32 ;
     RECT  42.617 68.928 42.977 68.952 ;
     RECT  42.185 5.856 43.153 53.736 ;
     RECT  42.185 55.008 43.153 59.304 ;
     RECT  42.293 60.432 43.261 64.104 ;
     RECT  43.153 5.856 43.297 59.304 ;
     RECT  43.261 60.336 43.297 64.104 ;
     RECT  41.969 2.304 43.661 4.392 ;
     RECT  43.661 2.352 43.873 4.392 ;
     RECT  43.297 5.856 43.873 64.104 ;
     RECT  43.873 2.352 44.233 64.104 ;
     RECT  44.233 2.352 44.568 64.296 ;
     RECT  42.365 73.248 44.568 73.272 ;
     RECT  44.568 2.352 45.493 94.248 ;
     RECT  45.493 2.256 45.608 94.248 ;
     RECT  45.608 2.148 45.712 94.248 ;
     RECT  45.608 96.648 45.712 114.492 ;
     RECT  45.712 96.648 45.8 114.222 ;
     RECT  45.712 2.256 45.904 94.248 ;
     RECT  45.8 96.378 45.904 114.222 ;
     RECT  45.904 2.256 45.965 3.096 ;
     RECT  45.965 2.496 47.041 3.096 ;
     RECT  47.041 2.064 47.293 3.096 ;
     RECT  47.293 2.064 47.509 3.384 ;
     RECT  45.904 4.368 47.509 94.248 ;
     RECT  47.509 2.064 47.945 94.248 ;
     RECT  47.945 4.368 48.737 94.248 ;
     RECT  47.945 2.064 48.985 3.384 ;
     RECT  48.737 4.368 48.985 4.392 ;
     RECT  48.985 2.064 49.277 4.392 ;
     RECT  49.277 2.064 49.377 4.008 ;
     RECT  49.377 3.984 50.569 4.008 ;
     RECT  49.377 2.064 51.008 2.856 ;
     RECT  50.569 3.984 51.008 4.248 ;
     RECT  48.737 5.472 51.008 94.248 ;
     RECT  51.008 96.648 51.112 114.492 ;
     RECT  51.112 96.648 51.2 114.222 ;
     RECT  51.008 2.064 51.304 94.248 ;
     RECT  51.2 96.378 51.304 114.222 ;
     RECT  51.304 4.224 51.491 94.248 ;
     RECT  51.304 2.064 51.635 2.088 ;
     RECT  52.364 2.88 52.451 2.904 ;
     RECT  51.491 4.464 53.165 94.248 ;
     RECT  53.165 4.512 53.669 94.248 ;
     RECT  53.669 5.04 54.281 94.248 ;
     RECT  54.281 5.472 56.408 94.248 ;
     RECT  56.408 2.148 56.512 94.248 ;
     RECT  56.408 96.648 56.512 114.492 ;
     RECT  56.512 96.648 56.6 114.222 ;
     RECT  56.512 2.418 56.704 94.248 ;
     RECT  56.6 96.378 56.704 114.222 ;
     RECT  56.704 5.472 61.808 94.248 ;
     RECT  61.808 2.148 61.912 94.248 ;
     RECT  61.808 96.648 61.912 114.492 ;
     RECT  61.912 96.648 62 114.222 ;
     RECT  61.912 2.418 62.104 94.248 ;
     RECT  62 96.378 62.104 114.222 ;
     RECT  62.104 5.472 67.208 94.248 ;
     RECT  67.208 2.148 67.312 94.248 ;
     RECT  67.208 96.648 67.312 114.492 ;
     RECT  67.312 96.648 67.4 114.222 ;
     RECT  67.312 2.418 67.504 94.248 ;
     RECT  67.4 96.378 67.504 114.222 ;
     RECT  67.504 5.472 68.033 94.248 ;
     RECT  68.033 6.144 69.109 94.248 ;
     RECT  69.109 5.472 72.608 94.248 ;
     RECT  72.608 2.148 72.712 94.248 ;
     RECT  72.608 96.648 72.712 114.492 ;
     RECT  72.712 96.648 72.8 114.222 ;
     RECT  72.712 2.418 72.904 94.248 ;
     RECT  72.8 96.378 72.904 114.222 ;
     RECT  72.904 5.472 78.008 94.248 ;
     RECT  78.008 2.148 78.112 94.248 ;
     RECT  78.008 96.648 78.112 114.492 ;
     RECT  78.112 96.648 78.2 114.222 ;
     RECT  78.112 2.418 78.304 94.248 ;
     RECT  78.2 96.378 78.304 114.222 ;
     RECT  78.304 5.472 83.408 94.248 ;
     RECT  83.408 2.148 83.512 94.248 ;
     RECT  83.408 96.648 83.512 114.492 ;
     RECT  83.512 96.648 83.6 114.222 ;
     RECT  83.512 2.418 83.704 94.248 ;
     RECT  83.6 96.378 83.704 114.222 ;
     RECT  87.445 2.496 87.692 2.52 ;
     RECT  87.692 2.448 87.733 2.52 ;
     RECT  87.733 2.064 88.808 2.52 ;
     RECT  83.704 5.472 88.808 94.248 ;
     RECT  88.808 96.648 88.912 114.492 ;
     RECT  88.912 96.648 89 114.222 ;
     RECT  88.808 2.064 89.021 94.248 ;
     RECT  89.021 2.208 89.104 94.248 ;
     RECT  89 96.378 89.104 114.222 ;
     RECT  89.104 2.208 94.208 2.232 ;
     RECT  89.104 5.472 94.208 94.248 ;
     RECT  94.208 2.148 94.312 94.248 ;
     RECT  94.208 96.648 94.312 114.492 ;
     RECT  94.312 96.648 94.4 114.222 ;
     RECT  94.312 2.208 94.504 94.248 ;
     RECT  94.4 96.378 94.504 114.222 ;
     RECT  94.504 2.208 99.608 2.232 ;
     RECT  94.504 5.472 99.608 94.248 ;
     RECT  99.608 2.148 99.712 94.248 ;
     RECT  99.608 96.648 99.712 114.492 ;
     RECT  99.712 96.648 99.8 114.222 ;
     RECT  99.712 2.208 99.904 94.248 ;
     RECT  99.8 96.378 99.904 114.222 ;
     RECT  99.904 2.208 105.008 2.232 ;
     RECT  99.904 5.472 105.008 94.248 ;
     RECT  105.008 2.148 105.112 94.248 ;
     RECT  105.008 96.648 105.112 114.492 ;
     RECT  105.112 96.648 105.2 114.222 ;
     RECT  105.112 2.208 105.304 94.248 ;
     RECT  105.2 96.378 105.304 114.222 ;
     RECT  105.304 5.472 108.605 94.248 ;
     RECT  105.304 2.208 110.408 2.232 ;
     RECT  108.605 5.472 110.408 6.072 ;
     RECT  108.605 7.152 110.408 94.248 ;
     RECT  110.408 2.148 110.512 94.248 ;
     RECT  110.408 96.648 110.512 114.492 ;
     RECT  110.512 96.648 110.6 114.222 ;
     RECT  110.512 2.208 110.704 94.248 ;
     RECT  110.6 96.378 110.704 114.222 ;
     RECT  110.704 5.472 111.443 6.072 ;
     RECT  110.704 2.208 112.313 2.232 ;
     RECT  112.597 2.256 112.681 2.28 ;
     RECT  16.409 0.048 114.275 0.216 ;
     RECT  111.443 5.472 115.808 5.496 ;
     RECT  110.704 7.152 115.808 94.248 ;
     RECT  115.808 2.148 115.912 94.248 ;
     RECT  115.808 96.648 115.912 114.492 ;
     RECT  115.912 96.648 116 114.222 ;
     RECT  115.912 2.418 116.104 94.248 ;
     RECT  116 96.378 116.104 114.222 ;
     RECT  116.104 5.472 121.208 5.496 ;
     RECT  116.104 7.152 121.208 94.248 ;
     RECT  121.208 2.148 121.312 94.248 ;
     RECT  121.208 96.648 121.312 114.492 ;
     RECT  121.312 96.648 121.4 114.222 ;
     RECT  121.312 2.418 121.504 94.248 ;
     RECT  121.4 96.378 121.504 114.222 ;
     RECT  114.275 0.048 123.539 0.072 ;
     RECT  121.504 5.472 126.608 5.496 ;
     RECT  121.504 7.152 126.608 94.248 ;
     RECT  126.608 2.148 126.712 94.248 ;
     RECT  126.608 96.648 126.712 114.492 ;
     RECT  126.712 96.648 126.8 114.222 ;
     RECT  126.712 2.418 126.904 94.248 ;
     RECT  126.8 96.378 126.904 114.222 ;
     RECT  126.904 5.472 132.008 5.496 ;
     RECT  126.904 7.152 132.008 94.248 ;
     RECT  132.008 2.148 132.112 94.248 ;
     RECT  132.008 96.648 132.112 114.492 ;
     RECT  132.112 96.648 132.2 114.222 ;
     RECT  132.112 2.418 132.304 94.248 ;
     RECT  132.2 96.378 132.304 114.222 ;
     RECT  132.304 7.152 133.625 94.248 ;
     RECT  132.304 5.472 137.408 5.496 ;
     RECT  133.625 7.728 137.408 94.248 ;
     RECT  137.408 2.148 137.512 94.248 ;
     RECT  137.408 96.648 137.512 114.492 ;
     RECT  137.512 96.648 137.6 114.222 ;
     RECT  137.512 2.418 137.704 94.248 ;
     RECT  137.6 96.378 137.704 114.222 ;
     RECT  137.704 7.728 137.873 94.248 ;
     RECT  137.704 5.472 142.808 5.496 ;
     RECT  137.873 7.872 142.808 94.248 ;
     RECT  142.808 2.148 142.912 94.248 ;
     RECT  142.808 96.648 142.912 114.492 ;
     RECT  142.912 96.648 143 114.222 ;
     RECT  142.912 2.418 143.104 94.248 ;
     RECT  143 96.378 143.104 114.222 ;
     RECT  143.104 5.472 148.208 5.496 ;
     RECT  143.104 7.872 148.208 94.248 ;
     RECT  148.208 2.148 148.312 94.248 ;
     RECT  148.208 96.648 148.312 114.492 ;
     RECT  148.312 96.648 148.4 114.222 ;
     RECT  148.312 2.418 148.504 94.248 ;
     RECT  148.4 96.378 148.504 114.222 ;
     RECT  148.504 5.472 149.315 5.496 ;
     RECT  148.504 7.872 150.509 94.248 ;
     RECT  150.509 7.968 153.608 94.248 ;
     RECT  153.608 2.148 153.712 94.248 ;
     RECT  153.608 96.648 153.712 114.492 ;
     RECT  153.712 96.648 153.8 114.222 ;
     RECT  153.712 2.418 153.904 94.248 ;
     RECT  153.8 96.378 153.904 114.222 ;
     RECT  153.904 7.968 154.163 94.248 ;
     RECT  154.163 8.16 159.008 94.248 ;
     RECT  159.008 2.148 159.112 94.248 ;
     RECT  159.008 96.648 159.112 114.492 ;
     RECT  159.112 96.648 159.2 114.222 ;
     RECT  159.112 2.418 159.304 94.248 ;
     RECT  159.2 96.378 159.304 114.222 ;
     RECT  159.304 8.16 164.408 94.248 ;
     RECT  164.408 2.148 164.512 94.248 ;
     RECT  164.408 96.648 164.512 114.492 ;
     RECT  164.512 96.648 164.6 114.222 ;
     RECT  164.512 2.418 164.704 94.248 ;
     RECT  164.6 96.378 164.704 114.222 ;
     RECT  164.704 8.16 169.808 94.248 ;
     RECT  169.808 2.148 169.912 94.248 ;
     RECT  169.808 96.648 169.912 114.492 ;
     RECT  169.912 96.648 170 114.222 ;
     RECT  169.912 2.418 170.104 94.248 ;
     RECT  170 96.378 170.104 114.222 ;
     RECT  170.104 8.16 175.208 94.248 ;
     RECT  175.208 2.148 175.312 94.248 ;
     RECT  175.208 96.648 175.312 114.492 ;
     RECT  175.312 96.648 175.4 114.222 ;
     RECT  175.312 2.418 175.504 94.248 ;
     RECT  175.4 96.378 175.504 114.222 ;
     RECT  175.504 8.16 180.608 94.248 ;
     RECT  180.608 2.148 180.712 94.248 ;
     RECT  180.608 96.648 180.712 114.492 ;
     RECT  180.712 96.648 180.8 114.222 ;
     RECT  180.712 2.418 180.904 94.248 ;
     RECT  180.8 96.378 180.904 114.222 ;
     RECT  180.904 8.16 186.008 94.248 ;
     RECT  186.008 2.148 186.112 94.248 ;
     RECT  186.008 96.648 186.112 114.492 ;
     RECT  186.112 96.648 186.2 114.222 ;
     RECT  186.112 2.418 186.304 94.248 ;
     RECT  186.2 96.378 186.304 114.222 ;
     RECT  186.304 8.16 191.408 94.248 ;
     RECT  191.408 2.148 191.512 94.248 ;
     RECT  191.408 96.648 191.512 114.492 ;
     RECT  191.512 96.648 191.6 114.222 ;
     RECT  191.512 2.418 191.704 94.248 ;
     RECT  191.6 96.378 191.704 114.222 ;
     RECT  191.704 8.16 196.808 94.248 ;
     RECT  196.808 2.148 196.912 94.248 ;
     RECT  196.808 96.648 196.912 114.492 ;
     RECT  196.912 96.648 197 114.222 ;
     RECT  196.912 2.418 197.104 94.248 ;
     RECT  197 96.378 197.104 114.222 ;
     RECT  197.104 8.16 202.208 94.248 ;
     RECT  202.208 2.148 202.312 94.248 ;
     RECT  202.208 96.648 202.312 114.492 ;
     RECT  202.312 96.648 202.4 114.222 ;
     RECT  202.312 2.418 202.504 94.248 ;
     RECT  202.4 96.378 202.504 114.222 ;
     RECT  202.504 8.16 207.608 94.248 ;
     RECT  207.608 2.148 207.712 94.248 ;
     RECT  207.608 96.648 207.712 114.492 ;
     RECT  207.712 96.648 207.8 114.222 ;
     RECT  207.712 2.418 207.904 94.248 ;
     RECT  207.8 96.378 207.904 114.222 ;
     RECT  207.904 8.16 213.008 94.248 ;
     RECT  213.008 2.148 213.112 94.248 ;
     RECT  213.008 96.648 213.112 114.492 ;
     RECT  213.112 96.648 213.2 114.222 ;
     RECT  213.112 2.418 213.304 94.248 ;
     RECT  213.2 96.378 213.304 114.222 ;
     RECT  213.304 8.16 218.408 94.248 ;
     RECT  218.408 2.148 218.512 94.248 ;
     RECT  218.408 96.648 218.512 114.492 ;
     RECT  218.512 96.648 218.6 114.222 ;
     RECT  218.512 2.418 218.704 94.248 ;
     RECT  218.6 96.378 218.704 114.222 ;
     RECT  218.704 8.16 219.168 94.248 ;
     RECT  219.168 8.16 219.449 64.2 ;
     RECT  219.449 44.4 219.485 58.536 ;
     RECT  219.449 8.16 220.061 39.816 ;
     RECT  219.485 44.4 220.493 57.672 ;
     RECT  219.449 40.944 220.601 43.368 ;
     RECT  220.601 42.576 220.637 43.368 ;
     RECT  220.493 53.52 221.177 57.672 ;
     RECT  219.449 61.488 221.177 64.2 ;
     RECT  220.601 40.944 221.213 41.448 ;
     RECT  220.493 44.4 221.213 52.392 ;
     RECT  221.177 53.52 221.213 53.544 ;
     RECT  221.177 54.672 221.213 57.576 ;
     RECT  220.061 8.16 221.285 39.336 ;
     RECT  221.213 44.88 221.501 52.392 ;
     RECT  221.177 64.176 221.501 64.2 ;
     RECT  221.501 44.88 221.537 46.632 ;
     RECT  221.501 47.856 221.537 47.88 ;
     RECT  221.177 61.488 221.537 62.952 ;
     RECT  221.285 8.16 221.555 19.32 ;
     RECT  221.501 49.008 221.609 49.512 ;
     RECT  221.213 55.824 221.609 57.288 ;
     RECT  221.537 61.488 221.609 61.512 ;
     RECT  221.537 46.608 221.681 46.632 ;
     RECT  221.609 49.008 221.681 49.032 ;
     RECT  221.501 50.544 221.681 52.392 ;
     RECT  221.609 56.496 221.681 57.288 ;
     RECT  219.449 59.664 221.681 60.264 ;
     RECT  221.537 62.928 221.681 62.952 ;
     RECT  221.537 44.88 221.717 45.192 ;
     RECT  221.681 50.544 221.717 51.24 ;
     RECT  221.213 54.672 221.717 54.696 ;
     RECT  221.681 56.976 221.717 57.288 ;
     RECT  221.681 59.664 221.717 59.688 ;
     RECT  221.285 20.304 221.753 39.336 ;
     RECT  221.753 20.304 221.897 38.376 ;
     RECT  221.497 58.608 221.933 58.632 ;
     RECT  221.965 39.36 222.049 39.384 ;
     RECT  221.897 20.304 222.227 38.232 ;
     RECT  220.637 42.576 222.325 43.32 ;
     RECT  221.555 8.208 222.371 19.32 ;
     RECT  222.227 20.304 222.437 35.688 ;
     RECT  222.227 37.056 222.545 38.232 ;
     RECT  222.325 42.192 222.709 43.32 ;
     RECT  222.371 8.448 222.865 19.32 ;
     RECT  222.437 20.304 222.865 31.464 ;
     RECT  222.437 32.592 223.196 35.688 ;
     RECT  222.545 37.056 223.196 37.56 ;
     RECT  222.865 8.448 223.405 31.464 ;
     RECT  223.196 32.592 223.405 37.56 ;
     RECT  223.405 8.448 223.808 37.56 ;
     RECT  222.709 41.664 223.808 43.32 ;
     RECT  221.717 45.168 223.808 45.192 ;
     RECT  223.808 2.148 223.912 114.492 ;
     RECT  223.912 2.418 224.104 114.222 ;
     RECT  224.104 20.688 224.381 37.08 ;
     RECT  224.381 28.656 224.489 37.08 ;
     RECT  224.381 20.688 224.561 27.48 ;
     RECT  224.104 8.448 224.915 9.096 ;
     RECT  224.561 20.688 225.065 27.096 ;
     RECT  224.489 34.656 225.065 37.08 ;
     RECT  224.915 9.072 225.107 9.096 ;
     RECT  224.104 41.664 225.137 43.944 ;
     RECT  224.104 16.032 225.425 19.128 ;
     RECT  224.489 28.656 225.425 33.624 ;
     RECT  225.425 16.08 225.641 19.128 ;
     RECT  225.065 20.688 225.677 21 ;
     RECT  225.425 28.656 225.749 33.432 ;
     RECT  225.749 30.336 225.893 33.432 ;
     RECT  225.065 37.056 225.929 37.08 ;
     RECT  225.677 20.688 225.965 20.712 ;
     RECT  225.065 22.08 226.177 27.096 ;
     RECT  226.177 22.08 226.285 27.432 ;
     RECT  225.749 28.656 226.325 28.776 ;
     RECT  225.137 41.664 226.325 43.32 ;
     RECT  224.104 10.128 226.469 14.808 ;
     RECT  226.285 21.888 226.829 27.432 ;
     RECT  226.325 28.752 227.221 28.776 ;
     RECT  225.893 30.576 227.473 33.432 ;
     RECT  225.065 34.656 227.513 35.736 ;
     RECT  225.641 16.8 227.549 19.128 ;
     RECT  227.473 30.528 227.585 33.432 ;
     RECT  226.469 10.128 227.837 14.712 ;
     RECT  227.585 31.872 228.121 33.432 ;
     RECT  227.513 34.656 228.121 35.064 ;
     RECT  228.121 31.872 228.161 35.064 ;
     RECT  226.829 21.888 228.181 27.24 ;
     RECT  227.221 28.752 228.181 29.496 ;
     RECT  226.325 41.76 228.481 43.32 ;
     RECT  228.181 21.888 228.589 29.496 ;
     RECT  227.585 30.528 228.589 30.6 ;
     RECT  228.589 21.888 228.733 30.6 ;
     RECT  227.837 10.128 229.208 13.08 ;
     RECT  227.837 14.448 229.208 14.712 ;
     RECT  227.549 16.8 229.208 17.16 ;
     RECT  227.549 18.192 229.208 19.128 ;
     RECT  228.733 21.888 229.208 30.888 ;
     RECT  228.161 31.872 229.208 34.488 ;
     RECT  229.201 38.16 229.208 38.184 ;
     RECT  228.481 41.76 229.208 43.896 ;
     RECT  224.104 45.168 229.208 45.192 ;
     RECT  229.208 2.148 229.312 114.492 ;
     RECT  229.312 2.418 229.504 114.222 ;
     RECT  229.504 33.6 229.637 35.736 ;
     RECT  229.504 36.72 229.715 37.128 ;
     RECT  229.715 36.816 229.753 37.128 ;
     RECT  229.637 34.272 229.781 35.736 ;
     RECT  229.504 12.864 229.961 13.08 ;
     RECT  229.504 21.984 229.997 32.616 ;
     RECT  229.504 10.128 230.285 10.2 ;
     RECT  229.504 14.448 230.291 14.712 ;
     RECT  229.997 21.984 230.393 30.792 ;
     RECT  229.504 45.168 230.537 45.432 ;
     RECT  230.393 24.912 230.645 30.792 ;
     RECT  229.504 41.664 230.645 43.32 ;
     RECT  230.285 10.128 230.681 10.152 ;
     RECT  229.753 36.816 230.717 36.84 ;
     RECT  229.504 16.8 230.753 17.16 ;
     RECT  230.537 45.168 230.821 45.192 ;
     RECT  229.504 38.16 230.861 38.184 ;
     RECT  229.997 31.776 230.965 32.616 ;
     RECT  229.781 34.272 230.965 34.632 ;
     RECT  230.393 21.984 231.005 23.928 ;
     RECT  230.645 25.056 231.145 30.792 ;
     RECT  230.965 31.776 231.145 34.632 ;
     RECT  230.753 16.8 231.155 16.968 ;
     RECT  231.145 25.056 231.185 34.632 ;
     RECT  231.185 26.256 231.253 34.632 ;
     RECT  231.253 26.256 231.293 34.728 ;
     RECT  231.253 37.056 231.337 37.08 ;
     RECT  231.005 22.32 231.395 23.928 ;
     RECT  231.185 25.056 231.401 25.128 ;
     RECT  231.293 31.776 231.545 34.728 ;
     RECT  231.155 16.896 231.653 16.968 ;
     RECT  231.545 31.776 231.653 34.392 ;
     RECT  230.645 41.664 231.653 43.272 ;
     RECT  231.653 43.248 231.685 43.272 ;
     RECT  230.821 44.88 231.725 45.192 ;
     RECT  229.781 35.712 231.865 35.736 ;
     RECT  229.504 11.232 231.869 11.736 ;
     RECT  231.685 43.248 231.941 43.848 ;
     RECT  231.725 44.88 231.941 44.904 ;
     RECT  231.401 25.056 232.009 25.08 ;
     RECT  231.869 11.28 232.229 11.736 ;
     RECT  231.293 26.256 232.265 30.744 ;
     RECT  230.291 14.496 232.409 14.712 ;
     RECT  231.395 22.32 232.477 23.352 ;
     RECT  232.009 24.528 232.477 25.08 ;
     RECT  232.265 28.8 232.481 30.744 ;
     RECT  232.229 11.28 232.769 11.544 ;
     RECT  231.865 35.712 232.873 36.6 ;
     RECT  231.653 41.664 232.877 42.264 ;
     RECT  232.877 42.24 232.981 42.264 ;
     RECT  231.941 43.392 232.981 43.848 ;
     RECT  232.981 42.24 232.985 43.848 ;
     RECT  232.873 35.712 233.125 37.416 ;
     RECT  232.477 22.32 233.201 25.08 ;
     RECT  232.985 42.768 233.237 43.848 ;
     RECT  233.125 35.712 233.269 37.608 ;
     RECT  229.961 13.008 233.345 13.08 ;
     RECT  232.769 11.52 233.417 11.544 ;
     RECT  233.345 13.008 233.453 13.032 ;
     RECT  231.653 31.776 233.485 34.152 ;
     RECT  233.269 35.712 233.485 38.184 ;
     RECT  233.201 22.32 233.597 24.648 ;
     RECT  232.265 26.256 233.737 27.768 ;
     RECT  233.737 26.256 234.181 27.816 ;
     RECT  232.481 28.8 234.181 30.408 ;
     RECT  233.237 42.768 234.241 43.416 ;
     RECT  229.504 18.192 234.277 19.128 ;
     RECT  234.181 26.256 234.277 30.408 ;
     RECT  232.409 14.496 234.608 14.52 ;
     RECT  231.653 16.944 234.608 16.968 ;
     RECT  234.277 18.192 234.608 19.272 ;
     RECT  233.597 22.32 234.608 22.344 ;
     RECT  233.597 23.616 234.608 24.648 ;
     RECT  234.277 26.112 234.608 30.648 ;
     RECT  233.485 31.776 234.608 38.184 ;
     RECT  234.241 42.768 234.608 43.656 ;
     RECT  233.197 44.88 234.608 44.904 ;
     RECT  234.608 2.148 234.712 114.492 ;
     RECT  234.712 2.418 234.904 114.222 ;
     RECT  234.904 37.344 234.929 38.184 ;
     RECT  234.904 23.52 234.965 24.648 ;
     RECT  234.904 18.192 235.037 19.272 ;
     RECT  234.965 24.624 235.109 24.648 ;
     RECT  234.965 23.52 235.181 23.64 ;
     RECT  234.904 44.88 235.217 44.904 ;
     RECT  234.904 43.392 235.541 43.416 ;
     RECT  235.037 19.248 235.685 19.272 ;
     RECT  234.904 26.112 235.933 30.408 ;
     RECT  234.904 31.776 235.933 34.2 ;
     RECT  235.933 26.112 236.005 34.2 ;
     RECT  234.904 35.472 236.005 35.784 ;
     RECT  236.005 26.112 236.369 36.216 ;
     RECT  234.929 37.344 236.437 37.512 ;
     RECT  236.369 26.256 236.473 36.216 ;
     RECT  236.437 37.344 236.473 37.992 ;
     RECT  234.904 14.496 236.657 14.52 ;
     RECT  236.473 26.256 236.761 37.992 ;
     RECT  235.037 18.192 237.161 18.216 ;
     RECT  234.904 22.32 237.197 22.344 ;
     RECT  236.761 26.256 237.373 38.184 ;
     RECT  237.373 25.968 237.409 38.184 ;
     RECT  237.409 25.296 237.737 38.184 ;
     RECT  237.737 25.296 237.877 37.992 ;
     RECT  237.877 25.104 237.985 37.992 ;
     RECT  237.661 43.536 238.345 43.56 ;
     RECT  237.985 23.472 238.381 23.496 ;
     RECT  237.985 24.576 238.381 37.992 ;
     RECT  238.345 43.536 238.381 43.752 ;
     RECT  238.381 42.72 238.493 43.752 ;
     RECT  238.381 23.472 238.889 37.992 ;
     RECT  238.493 42.96 239.317 43.752 ;
     RECT  238.889 23.472 239.353 37.608 ;
     RECT  239.317 42.96 239.353 43.944 ;
     RECT  239.353 42.96 239.533 44.52 ;
     RECT  239.353 23.28 239.605 37.608 ;
     RECT  239.533 42.384 239.605 44.52 ;
     RECT  239.605 42.192 239.857 44.52 ;
     RECT  239.857 42.192 240.469 44.808 ;
     RECT  239.605 23.088 240.505 37.608 ;
     RECT  240.469 42.192 240.541 45.096 ;
     RECT  240.505 23.088 241.801 37.8 ;
     RECT  241.801 22.992 241.884 37.8 ;
     RECT  240.541 42.192 241.884 45.192 ;
    LAYER M5 ;
     RECT  13.008 0.016 16.776 1.187 ;
     RECT  13.104 1.187 16.776 1.907 ;
     RECT  51.6 2.053 51.624 2.137 ;
     RECT  2.4 2.137 2.52 2.151 ;
     RECT  7.8 2.137 7.92 2.151 ;
     RECT  18.6 2.137 18.72 2.151 ;
     RECT  24 2.137 24.12 2.151 ;
     RECT  29.4 2.137 29.52 2.151 ;
     RECT  34.8 2.137 34.92 2.151 ;
     RECT  40.2 2.137 40.32 2.151 ;
     RECT  45.6 2.137 45.72 2.151 ;
     RECT  56.4 2.137 56.52 2.151 ;
     RECT  61.8 2.137 61.92 2.151 ;
     RECT  67.2 2.137 67.32 2.151 ;
     RECT  72.6 2.137 72.72 2.151 ;
     RECT  78 2.137 78.12 2.151 ;
     RECT  83.4 2.137 83.52 2.151 ;
     RECT  88.8 2.137 88.92 2.151 ;
     RECT  94.2 2.137 94.32 2.151 ;
     RECT  99.6 2.137 99.72 2.151 ;
     RECT  105 2.137 105.12 2.151 ;
     RECT  110.4 2.137 110.52 2.151 ;
     RECT  115.8 2.137 115.92 2.151 ;
     RECT  121.2 2.137 121.32 2.151 ;
     RECT  126.6 2.137 126.72 2.151 ;
     RECT  132 2.137 132.12 2.151 ;
     RECT  137.4 2.137 137.52 2.151 ;
     RECT  142.8 2.137 142.92 2.151 ;
     RECT  148.2 2.137 148.32 2.151 ;
     RECT  153.6 2.137 153.72 2.151 ;
     RECT  159 2.137 159.12 2.151 ;
     RECT  164.4 2.137 164.52 2.151 ;
     RECT  169.8 2.137 169.92 2.151 ;
     RECT  175.2 2.137 175.32 2.151 ;
     RECT  180.6 2.137 180.72 2.151 ;
     RECT  186 2.137 186.12 2.151 ;
     RECT  191.4 2.137 191.52 2.151 ;
     RECT  196.8 2.137 196.92 2.151 ;
     RECT  202.2 2.137 202.32 2.151 ;
     RECT  207.6 2.137 207.72 2.151 ;
     RECT  213 2.137 213.12 2.151 ;
     RECT  218.4 2.137 218.52 2.151 ;
     RECT  223.8 2.137 223.92 2.151 ;
     RECT  229.2 2.137 229.32 2.151 ;
     RECT  234.6 2.137 234.72 2.151 ;
     RECT  18.6 2.151 18.912 2.245 ;
     RECT  87.744 2.053 87.768 2.485 ;
     RECT  40.2 2.151 40.512 2.821 ;
     RECT  51 2.137 51.624 2.869 ;
     RECT  13.104 1.907 16.68 2.915 ;
     RECT  15.696 2.915 16.2 2.963 ;
     RECT  40.2 2.821 40.632 3.299 ;
     RECT  18.6 2.245 19.896 3.443 ;
     RECT  37.728 2.773 37.752 3.443 ;
     RECT  49.296 2.821 49.32 3.443 ;
     RECT  29.4 2.151 29.712 3.733 ;
     RECT  44.304 2.341 44.328 3.875 ;
     RECT  28.608 3.733 29.712 3.925 ;
     RECT  13.104 2.915 14.664 4.019 ;
     RECT  21.84 3.397 21.864 4.019 ;
     RECT  13.104 4.019 13.512 4.067 ;
     RECT  14.592 4.019 14.664 4.067 ;
     RECT  40.2 3.299 40.512 4.117 ;
     RECT  34.8 2.151 35.112 4.165 ;
     RECT  18.6 3.443 19.176 4.211 ;
     RECT  34.8 4.165 35.4 4.499 ;
     RECT  51 2.869 52.44 4.499 ;
     RECT  16.08 2.963 16.2 4.501 ;
     RECT  28.608 3.925 29.832 4.547 ;
     RECT  18.6 4.211 18.912 4.549 ;
     RECT  12.048 3.973 12.072 5.219 ;
     RECT  38.208 4.501 38.232 5.459 ;
     RECT  148.2 2.151 148.512 5.461 ;
     RECT  14.592 4.067 14.616 5.507 ;
     RECT  17.856 4.549 18.912 5.557 ;
     RECT  48.48 5.221 48.504 5.605 ;
     RECT  51 4.499 51.624 5.653 ;
     RECT  7.8 2.151 8.112 5.701 ;
     RECT  48.48 5.605 48.984 5.747 ;
     RECT  110.4 2.151 110.712 6.037 ;
     RECT  13.2 4.067 13.512 6.085 ;
     RECT  41.76 5.221 41.784 6.179 ;
     RECT  16.08 4.501 16.488 6.229 ;
     RECT  40.08 4.117 40.512 6.229 ;
     RECT  44.256 5.461 44.28 6.229 ;
     RECT  48.48 5.747 48.504 6.323 ;
     RECT  15.456 6.229 16.488 6.661 ;
     RECT  17.712 5.557 18.912 6.661 ;
     RECT  45.6 2.151 45.912 6.661 ;
     RECT  24 2.151 24.312 6.853 ;
     RECT  38.304 6.229 40.512 6.853 ;
     RECT  13.2 6.085 13.608 6.899 ;
     RECT  15.456 6.661 18.912 6.899 ;
     RECT  24 6.853 25.128 6.995 ;
     RECT  24 6.995 25.032 7.139 ;
     RECT  38.112 6.853 40.512 7.141 ;
     RECT  47.808 7.045 47.832 7.285 ;
     RECT  10.08 6.229 10.104 7.379 ;
     RECT  33.504 6.805 33.528 7.381 ;
     RECT  34.8 4.499 35.112 7.381 ;
     RECT  56.4 2.151 56.712 7.381 ;
     RECT  19.968 6.805 19.992 7.427 ;
     RECT  33.504 7.381 35.112 7.429 ;
     RECT  37.68 7.141 40.512 7.477 ;
     RECT  47.808 7.285 47.88 7.619 ;
     RECT  15.456 6.899 16.488 7.621 ;
     RECT  33.072 7.429 35.112 7.621 ;
     RECT  132 2.151 132.312 7.621 ;
     RECT  37.584 7.477 40.512 7.813 ;
     RECT  7.8 5.701 8.856 7.861 ;
     RECT  56.304 7.381 56.712 7.861 ;
     RECT  42.48 7.381 42.504 7.909 ;
     RECT  44.064 6.229 44.28 7.909 ;
     RECT  153.6 2.151 153.912 7.957 ;
     RECT  37.584 7.813 40.968 8.005 ;
     RECT  15.408 7.621 16.488 8.051 ;
     RECT  28.608 4.547 29.712 8.051 ;
     RECT  33.072 7.621 35.208 8.147 ;
     RECT  37.584 8.005 41.352 8.197 ;
     RECT  50.064 5.653 51.624 8.197 ;
     RECT  221.52 8.149 221.544 8.197 ;
     RECT  42.48 7.909 44.28 8.243 ;
     RECT  33.072 8.147 33.528 8.245 ;
     RECT  16.464 8.051 16.488 8.341 ;
     RECT  17.664 6.899 18.912 8.341 ;
     RECT  45.6 6.661 46.536 8.341 ;
     RECT  50.064 8.197 52.008 8.341 ;
     RECT  55.968 7.861 56.712 8.341 ;
     RECT  61.8 2.151 62.112 8.341 ;
     RECT  34.704 8.147 35.208 8.389 ;
     RECT  37.584 8.197 41.496 8.437 ;
     RECT  175.2 2.151 175.512 8.437 ;
     RECT  223.8 2.151 224.112 8.437 ;
     RECT  43.44 8.243 44.28 8.483 ;
     RECT  55.968 8.341 56.808 8.483 ;
     RECT  61.8 8.341 62.232 8.483 ;
     RECT  153.6 7.957 154.152 8.485 ;
     RECT  7.8 7.861 9.432 8.531 ;
     RECT  49.872 8.341 52.008 8.531 ;
     RECT  37.584 8.437 42.408 8.533 ;
     RECT  99.6 2.151 99.912 8.533 ;
     RECT  47.856 7.619 47.88 8.579 ;
     RECT  15.408 8.051 15.48 8.675 ;
     RECT  34.704 8.389 35.832 8.773 ;
     RECT  37.056 8.533 42.408 8.773 ;
     RECT  43.584 8.483 44.28 9.013 ;
     RECT  45.504 8.341 46.536 9.013 ;
     RECT  126.6 2.151 126.912 9.013 ;
     RECT  43.584 9.013 46.536 9.061 ;
     RECT  223.8 8.437 224.904 9.061 ;
     RECT  13.2 6.899 13.512 9.205 ;
     RECT  221.52 8.197 222.36 9.205 ;
     RECT  24 7.139 24.744 9.253 ;
     RECT  169.8 2.151 170.112 9.301 ;
     RECT  218.4 2.151 218.712 9.349 ;
     RECT  221.52 9.205 222.552 9.493 ;
     RECT  99.6 8.533 100.824 9.541 ;
     RECT  221.52 9.493 222.648 9.541 ;
     RECT  106.512 9.301 106.536 9.587 ;
     RECT  159 2.151 159.312 9.589 ;
     RECT  164.4 2.151 164.712 9.637 ;
     RECT  23.328 9.253 24.744 9.683 ;
     RECT  14.592 9.061 14.616 9.779 ;
     RECT  221.52 9.541 222.744 9.781 ;
     RECT  223.8 9.061 225.096 9.781 ;
     RECT  50.064 8.531 52.008 9.829 ;
     RECT  10.944 9.397 10.968 9.925 ;
     RECT  43.584 9.061 47.208 9.925 ;
     RECT  49.008 9.877 49.032 9.925 ;
     RECT  30.72 8.437 30.744 9.971 ;
     RECT  24 9.683 24.744 10.021 ;
     RECT  25.728 9.109 25.752 10.021 ;
     RECT  34.704 8.773 42.408 10.069 ;
     RECT  43.584 9.925 49.032 10.069 ;
     RECT  101.808 9.541 101.832 10.069 ;
     RECT  55.968 8.483 56.712 10.117 ;
     RECT  107.568 9.061 107.592 10.117 ;
     RECT  169.8 9.301 170.808 10.117 ;
     RECT  34.704 10.069 49.032 10.163 ;
     RECT  7.8 8.531 8.856 10.165 ;
     RECT  105 2.151 105.312 10.165 ;
     RECT  106.32 9.781 106.344 10.165 ;
     RECT  13.104 9.205 13.512 10.213 ;
     RECT  24 10.021 25.752 10.597 ;
     RECT  50.064 9.829 52.104 10.597 ;
     RECT  16.464 8.341 18.912 10.643 ;
     RECT  29.4 8.051 29.712 10.741 ;
     RECT  24 10.597 25.944 10.835 ;
     RECT  18.6 10.643 18.912 10.837 ;
     RECT  10.704 9.925 10.968 10.883 ;
     RECT  49.008 10.163 49.032 11.027 ;
     RECT  5.712 9.925 5.736 11.029 ;
     RECT  158.736 9.589 159.312 11.125 ;
     RECT  16.464 10.643 17.112 11.171 ;
     RECT  108.768 9.541 108.792 11.173 ;
     RECT  7.8 10.165 9.384 11.221 ;
     RECT  16.464 11.171 16.584 11.221 ;
     RECT  115.8 2.151 116.112 11.221 ;
     RECT  2.4 2.151 2.712 11.365 ;
     RECT  4.176 11.029 5.736 11.365 ;
     RECT  50.064 10.597 52.68 11.411 ;
     RECT  7.392 11.221 9.384 11.413 ;
     RECT  52.656 11.411 52.68 11.605 ;
     RECT  53.808 10.501 53.832 11.605 ;
     RECT  18.6 10.837 19.08 11.651 ;
     RECT  52.656 11.605 53.832 11.651 ;
     RECT  55.872 10.117 56.712 11.651 ;
     RECT  2.4 11.365 5.736 11.653 ;
     RECT  56.4 11.651 56.712 11.653 ;
     RECT  52.656 11.651 53.16 11.747 ;
     RECT  34.704 10.163 47.88 11.893 ;
     RECT  117.456 11.701 117.48 11.987 ;
     RECT  29.4 10.741 30.552 11.989 ;
     RECT  70.656 10.597 70.68 11.989 ;
     RECT  16.176 11.221 16.584 12.035 ;
     RECT  29.4 11.989 30.744 12.035 ;
     RECT  50.064 11.411 51.528 12.085 ;
     RECT  61.8 8.483 62.112 12.085 ;
     RECT  26.784 11.797 26.808 12.131 ;
     RECT  10.944 10.883 10.968 12.179 ;
     RECT  52.656 11.747 53.064 12.227 ;
     RECT  158.736 11.125 159.864 12.229 ;
     RECT  30.72 12.035 30.744 12.275 ;
     RECT  49.824 12.085 51.528 12.275 ;
     RECT  70.656 11.989 70.728 12.275 ;
     RECT  158.736 12.229 159.96 12.277 ;
     RECT  61.8 12.085 62.232 12.515 ;
     RECT  63.792 11.845 63.816 12.515 ;
     RECT  118.56 11.461 118.584 12.515 ;
     RECT  12.24 10.213 13.512 12.517 ;
     RECT  32.736 8.245 33.528 12.517 ;
     RECT  34.704 11.893 48.408 12.517 ;
     RECT  32.736 12.517 48.408 12.611 ;
     RECT  32.736 12.611 47.88 12.803 ;
     RECT  7.392 11.413 9.96 12.805 ;
     RECT  21.12 12.373 21.144 12.853 ;
     RECT  12.24 12.517 13.896 12.899 ;
     RECT  2.4 11.653 6.168 12.949 ;
     RECT  7.248 12.805 9.96 13.045 ;
     RECT  16.464 12.035 16.584 13.045 ;
     RECT  18.6 11.651 18.912 13.045 ;
     RECT  2.4 12.949 6.264 13.121 ;
     RECT  7.248 13.045 10.872 13.121 ;
     RECT  22.464 10.741 22.488 13.235 ;
     RECT  13.104 12.899 13.896 13.283 ;
     RECT  49.824 12.275 51.48 13.331 ;
     RECT  49.824 13.331 51.432 13.717 ;
     RECT  52.656 12.227 52.68 13.717 ;
     RECT  52.656 13.717 53.112 14.101 ;
     RECT  221.52 9.781 225.096 14.101 ;
     RECT  20.928 12.853 21.144 14.197 ;
     RECT  52.656 14.101 53.304 14.197 ;
     RECT  2.4 13.121 10.872 14.291 ;
     RECT  229.2 2.151 229.512 14.437 ;
     RECT  16.464 13.045 16.824 14.483 ;
     RECT  55.392 14.245 55.416 14.483 ;
     RECT  56.4 11.653 56.808 14.485 ;
     RECT  218.4 9.349 219.288 14.629 ;
     RECT  108.624 11.173 108.792 14.677 ;
     RECT  18.192 13.045 18.912 14.723 ;
     RECT  229.2 14.437 230.28 14.723 ;
     RECT  49.008 13.717 51.432 14.725 ;
     RECT  32.736 12.803 47.592 14.773 ;
     RECT  48.912 14.725 51.432 14.773 ;
     RECT  12 14.725 12.024 14.867 ;
     RECT  31.824 14.773 47.592 14.869 ;
     RECT  48.816 14.773 51.432 14.915 ;
     RECT  31.824 14.869 47.736 14.917 ;
     RECT  31.776 14.917 47.736 15.059 ;
     RECT  31.776 15.059 47.64 15.251 ;
     RECT  49.008 14.915 51.432 15.395 ;
     RECT  49.824 15.395 51.432 15.397 ;
     RECT  52.656 14.197 53.736 15.397 ;
     RECT  15.36 13.381 15.384 15.443 ;
     RECT  218.4 14.629 219.864 15.493 ;
     RECT  220.848 14.101 225.096 15.493 ;
     RECT  83.4 2.151 83.712 15.541 ;
     RECT  214.416 15.493 214.44 15.541 ;
     RECT  80.64 11.173 80.664 15.685 ;
     RECT  87.456 2.485 87.768 15.731 ;
     RECT  214.32 15.541 214.44 15.779 ;
     RECT  80.64 15.685 81.528 15.781 ;
     RECT  80.64 15.781 82.056 15.827 ;
     RECT  214.32 15.779 214.344 15.827 ;
     RECT  49.824 15.397 53.736 15.971 ;
     RECT  56.016 14.485 56.808 15.971 ;
     RECT  29.4 12.035 29.712 15.973 ;
     RECT  13.104 13.283 13.512 16.019 ;
     RECT  20.784 14.197 21.144 16.019 ;
     RECT  7.2 14.291 10.872 16.069 ;
     RECT  56.256 15.971 56.808 16.261 ;
     RECT  75.456 11.989 75.48 16.261 ;
     RECT  56.256 16.261 57.576 16.403 ;
     RECT  2.4 14.291 6.168 16.405 ;
     RECT  7.2 16.069 11.016 16.405 ;
     RECT  2.4 16.405 11.016 16.547 ;
     RECT  0.288 16.453 0.312 16.645 ;
     RECT  22.992 15.829 23.016 16.693 ;
     RECT  24 10.835 25.368 16.693 ;
     RECT  0.288 16.645 0.36 16.741 ;
     RECT  49.824 15.971 51.312 16.741 ;
     RECT  2.4 16.547 10.92 16.883 ;
     RECT  49.248 16.741 51.312 16.883 ;
     RECT  56.256 16.403 57.096 16.883 ;
     RECT  107.328 10.117 107.592 16.885 ;
     RECT  0.192 16.741 0.36 17.029 ;
     RECT  21.12 16.019 21.144 17.029 ;
     RECT  15.12 16.117 15.144 17.075 ;
     RECT  18.6 14.723 18.912 17.077 ;
     RECT  7.2 16.883 10.92 17.171 ;
     RECT  28.464 15.973 29.712 17.171 ;
     RECT  31.776 15.251 47.592 17.317 ;
     RECT  178.656 8.965 178.68 17.317 ;
     RECT  0.144 17.029 0.36 17.461 ;
     RECT  56.4 16.883 57.096 17.507 ;
     RECT  2.4 16.883 6.168 17.509 ;
     RECT  49.824 16.883 51.312 17.509 ;
     RECT  67.2 2.151 67.512 17.509 ;
     RECT  0.144 17.461 0.408 17.557 ;
     RECT  49.824 17.509 51.432 17.605 ;
     RECT  7.2 17.171 10.872 17.651 ;
     RECT  105 10.165 106.344 17.699 ;
     RECT  27.648 17.413 27.672 17.701 ;
     RECT  22.992 16.693 25.368 17.795 ;
     RECT  31.68 17.317 47.592 17.893 ;
     RECT  49.824 17.605 51.528 17.939 ;
     RECT  92.4 17.893 92.424 18.037 ;
     RECT  132 7.621 132.552 18.037 ;
     RECT  16.8 14.483 16.824 18.131 ;
     RECT  31.68 17.893 48.264 18.179 ;
     RECT  49.824 17.939 51.432 18.179 ;
     RECT  67.2 17.509 67.608 18.179 ;
     RECT  2.304 17.509 6.168 18.181 ;
     RECT  7.2 17.651 10.632 18.181 ;
     RECT  27.072 17.701 27.672 18.181 ;
     RECT  80.64 15.827 80.664 18.181 ;
     RECT  94.2 2.151 94.512 18.181 ;
     RECT  103.248 9.493 103.272 18.181 ;
     RECT  105 17.699 106.248 18.181 ;
     RECT  107.328 16.885 107.64 18.181 ;
     RECT  108.624 14.677 108.84 18.181 ;
     RECT  80.64 18.181 80.904 18.227 ;
     RECT  72.6 2.151 72.912 18.229 ;
     RECT  114.24 0.181 114.264 18.275 ;
     RECT  29.04 17.171 29.712 18.325 ;
     RECT  91.632 18.037 92.424 18.373 ;
     RECT  93.792 18.181 94.512 18.373 ;
     RECT  103.248 18.181 106.248 18.419 ;
     RECT  76.848 14.101 76.872 18.421 ;
     RECT  78 2.151 78.312 18.421 ;
     RECT  103.248 18.419 105.312 18.421 ;
     RECT  115.8 11.221 116.232 18.421 ;
     RECT  87.744 15.731 87.768 18.469 ;
     RECT  88.8 2.151 89.112 18.469 ;
     RECT  91.632 18.373 94.512 18.469 ;
     RECT  83.232 15.541 83.712 18.517 ;
     RECT  21.12 17.029 21.528 18.563 ;
     RECT  61.8 12.515 62.112 18.565 ;
     RECT  91.392 18.469 94.512 18.565 ;
     RECT  97.392 14.629 97.416 18.565 ;
     RECT  99.504 9.541 100.824 18.565 ;
     RECT  84.96 18.229 84.984 18.613 ;
     RECT  140.208 18.421 140.232 18.613 ;
     RECT  115.8 18.421 116.28 18.659 ;
     RECT  82.032 15.827 82.056 18.661 ;
     RECT  99.168 18.565 100.824 18.661 ;
     RECT  101.808 10.069 101.976 18.661 ;
     RECT  140.208 18.613 140.472 18.661 ;
     RECT  140.208 18.661 140.76 18.707 ;
     RECT  115.8 18.659 116.232 18.709 ;
     RECT  218.4 15.493 225.096 18.709 ;
     RECT  26.928 18.181 27.672 18.757 ;
     RECT  28.8 18.325 29.712 18.757 ;
     RECT  121.2 2.151 121.512 18.757 ;
     RECT  123.504 0.037 123.528 18.757 ;
     RECT  126.6 9.013 127.368 18.757 ;
     RECT  142.8 2.151 143.112 18.757 ;
     RECT  128.976 18.661 129 18.803 ;
     RECT  2.304 18.181 10.632 18.851 ;
     RECT  56.4 17.507 56.808 18.853 ;
     RECT  87.744 18.469 89.112 18.853 ;
     RECT  107.328 18.181 108.84 18.853 ;
     RECT  123.504 18.757 123.624 18.853 ;
     RECT  49.824 18.179 51.312 18.899 ;
     RECT  61.8 18.565 63.096 18.899 ;
     RECT  76.848 18.421 78.312 18.901 ;
     RECT  112.608 2.245 112.632 18.901 ;
     RECT  103.152 18.421 105.312 18.947 ;
     RECT  107.04 18.853 108.84 18.947 ;
     RECT  3.84 18.851 10.632 18.949 ;
     RECT  72.6 18.229 73.032 18.997 ;
     RECT  137.4 2.151 137.712 18.997 ;
     RECT  0.144 17.557 0.552 19.043 ;
     RECT  3.84 18.949 10.92 19.091 ;
     RECT  63.168 18.949 63.192 19.091 ;
     RECT  71.664 18.997 73.032 19.091 ;
     RECT  81.984 18.661 82.056 19.093 ;
     RECT  180.6 2.151 180.912 19.093 ;
     RECT  71.664 19.091 72.912 19.139 ;
     RECT  112.608 18.901 112.92 19.139 ;
     RECT  26.928 18.757 29.712 19.141 ;
     RECT  74.736 16.261 75.48 19.141 ;
     RECT  97.392 18.565 98.088 19.141 ;
     RECT  52.656 15.971 53.736 19.189 ;
     RECT  0.144 19.043 0.456 19.235 ;
     RECT  148.2 5.461 149.304 19.237 ;
     RECT  169.8 10.117 170.952 19.237 ;
     RECT  207.6 2.151 207.912 19.237 ;
     RECT  96.96 19.141 98.088 19.283 ;
     RECT  132 18.037 132.984 19.285 ;
     RECT  135.216 18.949 135.24 19.331 ;
     RECT  52.656 19.189 53.88 19.333 ;
     RECT  67.2 18.179 67.512 19.333 ;
     RECT  142.8 18.757 143.304 19.333 ;
     RECT  145.632 18.757 145.656 19.333 ;
     RECT  31.68 18.179 47.832 19.379 ;
     RECT  64.032 19.141 64.056 19.379 ;
     RECT  202.2 2.151 202.512 19.381 ;
     RECT  80.88 18.227 80.904 19.427 ;
     RECT  108.624 18.947 108.84 19.427 ;
     RECT  115.104 18.709 116.232 19.427 ;
     RECT  76.848 18.901 79.272 19.477 ;
     RECT  83.232 18.517 83.832 19.477 ;
     RECT  84.96 18.613 85.128 19.477 ;
     RECT  107.04 18.947 107.64 19.477 ;
     RECT  211.536 17.077 211.56 19.523 ;
     RECT  31.68 19.379 47.592 19.525 ;
     RECT  26.928 19.141 30.408 19.573 ;
     RECT  31.632 19.525 47.592 19.573 ;
     RECT  83.232 19.477 85.128 19.573 ;
     RECT  158.736 12.277 160.056 19.573 ;
     RECT  2.304 18.851 2.856 19.619 ;
     RECT  3.84 19.091 10.632 19.619 ;
     RECT  201.216 19.381 202.512 19.619 ;
     RECT  141.84 19.333 143.304 19.621 ;
     RECT  91.392 18.565 94.632 19.667 ;
     RECT  99.168 18.661 101.976 19.715 ;
     RECT  108.672 19.427 108.84 19.715 ;
     RECT  81.888 19.093 82.056 19.717 ;
     RECT  83.232 19.573 85.224 19.763 ;
     RECT  91.392 19.667 91.416 19.763 ;
     RECT  141.84 19.621 143.4 19.763 ;
     RECT  18.6 17.077 19.8 19.765 ;
     RECT  131.856 19.285 132.984 19.765 ;
     RECT  134.208 12.757 134.232 19.765 ;
     RECT  26.928 19.573 47.592 19.811 ;
     RECT  140.352 18.707 140.76 19.811 ;
     RECT  16.224 18.709 16.248 19.813 ;
     RECT  67.104 19.333 67.512 19.813 ;
     RECT  153.6 8.485 154.2 19.813 ;
     RECT  161.952 19.717 161.976 19.813 ;
     RECT  50.112 18.899 51.312 19.859 ;
     RECT  69.6 18.661 69.624 19.859 ;
     RECT  80.928 19.717 82.056 19.859 ;
     RECT  97.104 19.283 98.088 19.859 ;
     RECT  140.352 19.811 140.712 19.859 ;
     RECT  56.4 18.853 56.904 19.861 ;
     RECT  161.712 19.813 161.976 19.861 ;
     RECT  92.4 19.667 94.632 19.907 ;
     RECT  17.808 19.765 19.8 19.909 ;
     RECT  158.736 19.573 160.152 19.909 ;
     RECT  186 2.151 186.312 19.909 ;
     RECT  0.144 19.235 0.408 19.955 ;
     RECT  55.296 19.141 55.32 19.955 ;
     RECT  218.304 18.709 225.096 19.957 ;
     RECT  31.68 19.811 47.592 20.003 ;
     RECT  92.784 19.907 94.632 20.003 ;
     RECT  101.808 19.715 101.976 20.003 ;
     RECT  106.608 19.477 107.64 20.003 ;
     RECT  108.768 19.715 108.84 20.003 ;
     RECT  123.504 18.853 123.72 20.003 ;
     RECT  161.184 19.861 161.976 20.003 ;
     RECT  74.688 19.141 75.48 20.051 ;
     RECT  97.392 19.859 98.088 20.051 ;
     RECT  158.64 19.909 160.152 20.053 ;
     RECT  213 2.151 213.312 20.053 ;
     RECT  68.976 19.957 69 20.099 ;
     RECT  59.856 18.997 59.88 20.101 ;
     RECT  72.6 19.139 72.912 20.101 ;
     RECT  31.68 20.003 47.208 20.147 ;
     RECT  17.52 19.909 19.8 20.149 ;
     RECT  21.12 18.563 21.144 20.149 ;
     RECT  105 18.947 105.312 20.149 ;
     RECT  202.2 19.619 202.512 20.149 ;
     RECT  87.168 18.853 89.112 20.195 ;
     RECT  148.08 19.237 149.304 20.195 ;
     RECT  81.888 19.859 82.056 20.197 ;
     RECT  83.232 19.763 84.408 20.197 ;
     RECT  130.656 20.101 130.68 20.197 ;
     RECT  59.568 20.101 59.88 20.243 ;
     RECT  92.88 20.003 94.632 20.243 ;
     RECT  131.856 19.765 134.232 20.245 ;
     RECT  173.136 19.141 173.16 20.245 ;
     RECT  99.168 19.715 100.824 20.291 ;
     RECT  131.856 20.245 134.712 20.291 ;
     RECT  158.64 20.053 160.728 20.291 ;
     RECT  202.2 20.149 202.632 20.291 ;
     RECT  48.816 19.957 48.84 20.293 ;
     RECT  106.608 20.003 106.632 20.339 ;
     RECT  112.608 19.139 112.632 20.339 ;
     RECT  184.272 20.053 184.296 20.339 ;
     RECT  213 20.053 214.296 20.339 ;
     RECT  16.032 19.813 16.248 20.341 ;
     RECT  17.52 20.149 21.144 20.341 ;
     RECT  105 20.149 105.528 20.387 ;
     RECT  118.56 19.429 118.584 20.387 ;
     RECT  129.456 20.245 129.48 20.387 ;
     RECT  130.56 20.197 130.68 20.387 ;
     RECT  133.392 20.291 134.712 20.387 ;
     RECT  141.84 19.763 143.208 20.387 ;
     RECT  145.104 19.333 145.656 20.387 ;
     RECT  210.336 20.101 210.36 20.387 ;
     RECT  126.6 18.757 127.704 20.389 ;
     RECT  153.6 19.813 154.248 20.389 ;
     RECT  52.416 19.333 53.88 20.435 ;
     RECT  173.136 20.245 173.496 20.435 ;
     RECT  180.384 19.093 180.912 20.435 ;
     RECT  148.2 20.195 149.304 20.437 ;
     RECT  71.808 20.101 72.912 20.483 ;
     RECT  169.584 19.237 170.952 20.483 ;
     RECT  50.496 19.859 51.312 20.485 ;
     RECT  52.416 20.435 52.68 20.485 ;
     RECT  175.2 8.437 175.848 20.485 ;
     RECT  16.032 20.341 21.144 20.531 ;
     RECT  93.792 20.243 94.632 20.531 ;
     RECT  126.6 20.389 127.848 20.531 ;
     RECT  210.432 20.389 210.456 20.531 ;
     RECT  207.6 19.237 208.104 20.533 ;
     RECT  74.736 20.051 75.48 20.579 ;
     RECT  93.792 20.531 94.512 20.579 ;
     RECT  103.152 18.947 103.272 20.579 ;
     RECT  108.768 20.003 108.792 20.579 ;
     RECT  139.104 19.093 139.128 20.579 ;
     RECT  145.632 20.387 145.656 20.579 ;
     RECT  153.504 20.389 154.488 20.579 ;
     RECT  199.344 19.237 199.368 20.579 ;
     RECT  206.88 20.533 208.104 20.579 ;
     RECT  99.168 20.291 100.536 20.627 ;
     RECT  193.152 19.237 193.176 20.627 ;
     RECT  13.2 16.019 13.512 20.629 ;
     RECT  3.936 19.619 10.632 20.675 ;
     RECT  121.104 18.757 121.512 20.675 ;
     RECT  157.584 11.653 157.608 20.675 ;
     RECT  166.416 20.581 166.44 20.677 ;
     RECT  48.816 20.293 49.032 20.723 ;
     RECT  128.4 20.581 128.424 20.723 ;
     RECT  185.664 19.909 186.312 20.723 ;
     RECT  26.928 19.811 30.408 20.771 ;
     RECT  50.496 20.485 52.68 20.771 ;
     RECT  153.504 20.579 154.248 20.771 ;
     RECT  49.008 20.723 49.032 20.773 ;
     RECT  76.848 19.477 79.32 20.819 ;
     RECT  140.688 19.859 140.712 20.819 ;
     RECT  158.64 20.291 160.248 20.819 ;
     RECT  166.368 20.677 166.44 20.819 ;
     RECT  2.4 19.619 2.856 20.821 ;
     RECT  3.936 20.675 8.856 20.821 ;
     RECT  136.704 18.997 137.712 20.867 ;
     RECT  142.8 20.387 143.208 20.867 ;
     RECT  148.2 20.437 150.216 20.867 ;
     RECT  153.6 20.771 154.248 20.867 ;
     RECT  162.48 20.581 162.504 20.867 ;
     RECT  23.616 17.795 25.368 20.917 ;
     RECT  166.416 20.819 166.44 20.963 ;
     RECT  146.496 20.725 146.52 21.011 ;
     RECT  206.88 20.579 208.008 21.011 ;
     RECT  23.088 20.917 25.368 21.013 ;
     RECT  81.888 20.197 84.408 21.059 ;
     RECT  207.6 21.011 208.008 21.059 ;
     RECT  218.208 19.957 225.096 21.059 ;
     RECT  49.008 20.773 49.224 21.061 ;
     RECT  53.856 20.435 53.88 21.061 ;
     RECT  90.528 20.149 90.552 21.107 ;
     RECT  114.048 18.757 114.072 21.107 ;
     RECT  51 20.771 52.68 21.155 ;
     RECT  76.848 20.819 76.872 21.155 ;
     RECT  78 20.819 79.32 21.155 ;
     RECT  83.232 21.059 84.408 21.155 ;
     RECT  175.104 20.485 175.848 21.155 ;
     RECT  205.2 21.013 206.04 21.155 ;
     RECT  23.088 21.013 25.896 21.157 ;
     RECT  26.928 20.771 27.672 21.157 ;
     RECT  123.504 20.003 123.528 21.157 ;
     RECT  16.224 20.531 21.144 21.203 ;
     RECT  31.68 20.147 47.112 21.203 ;
     RECT  53.856 21.061 54.744 21.203 ;
     RECT  59.856 20.243 59.88 21.203 ;
     RECT  67.056 19.813 67.512 21.203 ;
     RECT  70.656 12.275 70.68 21.203 ;
     RECT  74.736 20.579 74.76 21.203 ;
     RECT  123.36 21.157 123.528 21.203 ;
     RECT  164.4 9.637 165 21.203 ;
     RECT  169.8 20.483 170.952 21.203 ;
     RECT  178.656 17.317 179.256 21.203 ;
     RECT  205.2 21.155 205.224 21.205 ;
     RECT  87.744 20.195 89.112 21.299 ;
     RECT  97.392 20.051 97.416 21.299 ;
     RECT  99.6 20.627 100.536 21.299 ;
     RECT  101.952 20.003 101.976 21.299 ;
     RECT  103.152 20.579 103.176 21.299 ;
     RECT  107.616 20.003 107.64 21.299 ;
     RECT  110.4 6.037 111.432 21.299 ;
     RECT  123.36 21.203 123.384 21.299 ;
     RECT  126.6 20.531 127.176 21.299 ;
     RECT  131.856 20.291 132.408 21.299 ;
     RECT  133.392 20.387 134.232 21.299 ;
     RECT  169.8 21.203 170.808 21.299 ;
     RECT  133.392 21.299 133.416 21.347 ;
     RECT  150.48 21.157 150.504 21.347 ;
     RECT  153.6 20.867 154.2 21.347 ;
     RECT  218.256 21.059 225.096 21.347 ;
     RECT  56.4 19.861 57.432 21.395 ;
     RECT  81.888 21.059 81.912 21.395 ;
     RECT  88.32 21.299 89.112 21.395 ;
     RECT  132 21.299 132.408 21.395 ;
     RECT  52.656 21.155 52.68 21.397 ;
     RECT  202.2 20.291 202.512 21.397 ;
     RECT  56.4 21.395 56.808 21.443 ;
     RECT  159 20.819 160.248 21.443 ;
     RECT  204.624 21.205 205.224 21.443 ;
     RECT  78 21.155 78.936 21.491 ;
     RECT  148.2 20.867 149.304 21.491 ;
     RECT  0.288 19.955 0.408 21.493 ;
     RECT  23.088 21.157 27.672 21.541 ;
     RECT  49.008 21.061 49.896 21.587 ;
     RECT  175.2 21.155 175.848 21.587 ;
     RECT  52.656 21.397 53.064 21.635 ;
     RECT  54.72 21.203 54.744 21.635 ;
     RECT  13.104 20.629 13.512 21.637 ;
     RECT  17.52 21.203 21.144 21.683 ;
     RECT  178.416 21.397 178.44 21.683 ;
     RECT  182.688 21.397 182.712 21.683 ;
     RECT  202.2 21.397 203.304 21.683 ;
     RECT  204.624 21.443 204.84 21.731 ;
     RECT  49.872 21.587 49.896 21.779 ;
     RECT  83.4 21.155 84.408 21.779 ;
     RECT  51 21.155 51.576 21.827 ;
     RECT  31.68 21.203 46.68 22.019 ;
     RECT  14.832 21.541 14.856 22.259 ;
     RECT  218.304 21.347 225.096 22.259 ;
     RECT  0.144 21.493 0.408 22.403 ;
     RECT  52.656 21.635 52.68 22.499 ;
     RECT  2.4 20.821 8.856 22.549 ;
     RECT  10.032 20.675 10.632 22.549 ;
     RECT  218.4 22.259 225.096 22.741 ;
     RECT  231.12 16.789 231.144 22.741 ;
     RECT  23.04 21.541 27.672 22.789 ;
     RECT  29.04 20.771 30.408 22.789 ;
     RECT  0.144 22.403 0.312 22.835 ;
     RECT  17.52 21.683 19.56 22.835 ;
     RECT  45.6 22.019 46.68 22.835 ;
     RECT  229.2 14.723 229.512 22.933 ;
     RECT  21.12 21.683 21.144 23.077 ;
     RECT  17.808 22.835 19.56 23.125 ;
     RECT  21.024 23.077 21.144 23.125 ;
     RECT  17.808 23.125 21.144 23.267 ;
     RECT  12 19.669 12.024 23.315 ;
     RECT  21.024 23.267 21.144 23.315 ;
     RECT  31.68 22.019 44.52 23.555 ;
     RECT  23.04 22.789 30.408 23.651 ;
     RECT  31.68 23.555 44.472 23.651 ;
     RECT  231.12 22.741 231.384 23.893 ;
     RECT  26.976 23.651 30.408 23.939 ;
     RECT  230.976 23.893 231.384 23.939 ;
     RECT  0.144 22.835 0.216 23.987 ;
     RECT  23.04 23.651 25.752 24.085 ;
     RECT  13.056 21.637 13.512 24.229 ;
     RECT  22.32 24.085 25.752 24.275 ;
     RECT  229.2 22.933 229.608 24.275 ;
     RECT  17.808 23.267 19.752 24.373 ;
     RECT  12.96 24.229 13.512 24.421 ;
     RECT  16.224 21.203 16.248 24.469 ;
     RECT  23.04 24.275 25.752 24.611 ;
     RECT  0.144 23.987 0.168 24.659 ;
     RECT  2.4 22.549 10.632 24.707 ;
     RECT  21.12 23.315 21.144 24.805 ;
     RECT  16.08 24.469 16.248 24.949 ;
     RECT  17.616 24.373 19.752 24.949 ;
     RECT  27.264 23.939 30.408 24.995 ;
     RECT  31.68 23.651 44.424 25.045 ;
     RECT  230.976 23.939 231.144 25.139 ;
     RECT  23.04 24.611 25.56 25.187 ;
     RECT  21.12 24.805 21.912 25.333 ;
     RECT  16.08 24.949 19.752 25.573 ;
     RECT  21.12 25.333 22.776 25.573 ;
     RECT  31.584 25.045 44.424 25.619 ;
     RECT  23.76 25.187 25.56 25.621 ;
     RECT  27.264 24.995 27.672 25.621 ;
     RECT  16.08 25.573 22.776 25.717 ;
     RECT  12.336 24.421 13.512 25.957 ;
     RECT  2.4 24.707 3.432 26.005 ;
     RECT  4.416 24.707 10.632 26.005 ;
     RECT  15.744 25.717 22.776 26.051 ;
     RECT  23.76 25.621 27.672 26.101 ;
     RECT  29.04 24.995 30.408 26.101 ;
     RECT  2.4 26.005 10.632 26.291 ;
     RECT  23.76 26.101 30.408 26.627 ;
     RECT  229.2 24.275 229.512 26.677 ;
     RECT  15.936 26.051 22.776 26.819 ;
     RECT  21.12 26.819 22.776 26.869 ;
     RECT  23.76 26.627 27.672 26.869 ;
     RECT  227.472 26.725 227.496 27.205 ;
     RECT  14.496 27.061 14.52 27.251 ;
     RECT  227.472 27.205 228.216 27.251 ;
     RECT  12.288 25.957 13.512 27.253 ;
     RECT  21.12 26.869 27.672 27.299 ;
     RECT  15.936 26.819 19.56 27.347 ;
     RECT  28.992 26.627 30.408 27.347 ;
     RECT  27.6 27.299 27.672 27.491 ;
     RECT  229.2 26.677 229.752 27.683 ;
     RECT  234.6 2.151 234.912 27.685 ;
     RECT  16.224 27.347 19.56 27.829 ;
     RECT  21.12 27.299 26.568 27.875 ;
     RECT  27.648 27.491 27.672 27.925 ;
     RECT  12.144 27.253 13.512 28.355 ;
     RECT  234.192 27.685 234.912 28.355 ;
     RECT  16.224 27.829 19.848 28.357 ;
     RECT  21.12 27.875 25.176 28.357 ;
     RECT  237.84 28.261 237.864 28.403 ;
     RECT  2.4 26.291 2.904 28.453 ;
     RECT  3.984 26.291 10.632 28.453 ;
     RECT  228.192 27.251 228.216 28.835 ;
     RECT  2.4 28.453 10.632 28.981 ;
     RECT  26.4 27.875 26.568 29.077 ;
     RECT  27.648 27.925 27.72 29.077 ;
     RECT  29.04 27.347 30.408 29.077 ;
     RECT  31.584 25.619 44.376 29.077 ;
     RECT  2.4 28.981 11.208 29.267 ;
     RECT  229.2 27.683 229.512 29.461 ;
     RECT  29.04 29.077 44.376 29.507 ;
     RECT  29.04 29.507 44.328 29.509 ;
     RECT  26.4 29.077 27.72 29.603 ;
     RECT  27.648 29.603 27.72 29.653 ;
     RECT  28.896 29.509 44.328 29.653 ;
     RECT  228.528 29.461 229.512 29.653 ;
     RECT  2.4 29.267 8.568 29.747 ;
     RECT  9.552 29.267 11.208 29.939 ;
     RECT  12.336 28.355 13.512 30.181 ;
     RECT  228.528 29.653 229.848 30.227 ;
     RECT  228.528 30.227 229.512 30.517 ;
     RECT  228 30.517 229.512 30.563 ;
     RECT  27.648 29.653 44.328 30.757 ;
     RECT  4.08 29.747 8.568 30.851 ;
     RECT  218.4 22.741 225.144 30.851 ;
     RECT  4.128 30.851 8.568 30.947 ;
     RECT  27.648 30.757 44.424 31.043 ;
     RECT  9.552 29.939 10.632 31.189 ;
     RECT  27.648 31.043 44.328 31.379 ;
     RECT  5.184 30.947 8.568 31.861 ;
     RECT  9.552 31.189 10.872 31.861 ;
     RECT  218.4 30.851 225.096 31.861 ;
     RECT  228 30.563 228.024 31.907 ;
     RECT  4.128 30.947 4.152 31.909 ;
     RECT  5.184 31.861 11.304 31.909 ;
     RECT  27.648 31.379 27.816 32.437 ;
     RECT  28.896 31.379 44.328 32.437 ;
     RECT  15.168 29.365 15.192 32.531 ;
     RECT  237.84 32.485 237.864 32.627 ;
     RECT  4.128 31.909 11.304 33.155 ;
     RECT  5.184 33.155 11.304 33.251 ;
     RECT  218.4 31.861 225.144 33.299 ;
     RECT  218.4 33.299 225.096 33.443 ;
     RECT  218.4 33.443 220.968 33.587 ;
     RECT  9.984 33.251 11.304 33.683 ;
     RECT  12.336 30.181 13.608 33.683 ;
     RECT  12.336 33.683 13.512 33.925 ;
     RECT  231.12 25.139 231.144 34.213 ;
     RECT  231.12 34.213 231.288 34.259 ;
     RECT  229.2 30.563 229.512 34.453 ;
     RECT  5.184 33.251 8.808 34.693 ;
     RECT  5.184 34.693 8.904 34.835 ;
     RECT  11.808 33.925 13.512 34.835 ;
     RECT  219.696 33.587 220.968 34.835 ;
     RECT  229.2 34.453 229.752 34.835 ;
     RECT  4.128 33.155 4.152 35.029 ;
     RECT  5.184 34.835 8.568 35.029 ;
     RECT  222 33.443 225.096 35.125 ;
     RECT  220.848 34.835 220.968 35.171 ;
     RECT  222 35.125 225.144 35.267 ;
     RECT  16.224 28.357 25.176 35.461 ;
     RECT  234.6 28.355 234.912 35.701 ;
     RECT  241.728 35.653 241.752 35.843 ;
     RECT  15.84 35.461 25.176 35.893 ;
     RECT  26.4 29.603 26.568 35.893 ;
     RECT  4.128 35.029 8.568 36.373 ;
     RECT  12.096 34.835 13.512 36.515 ;
     RECT  233.616 35.701 234.912 36.515 ;
     RECT  229.2 34.835 229.512 36.709 ;
     RECT  12.192 36.515 13.512 36.851 ;
     RECT  2.4 29.747 2.712 37.045 ;
     RECT  3.744 36.373 8.568 37.045 ;
     RECT  12.336 36.851 13.512 37.045 ;
     RECT  220.944 35.171 220.968 37.091 ;
     RECT  231.264 34.259 231.288 37.091 ;
     RECT  2.4 37.045 8.568 37.093 ;
     RECT  229.2 36.709 229.704 37.139 ;
     RECT  27.648 32.437 44.328 37.141 ;
     RECT  27.648 37.141 44.424 37.331 ;
     RECT  2.4 37.093 8.616 37.619 ;
     RECT  15.84 35.893 26.568 37.765 ;
     RECT  27.648 37.331 44.184 37.765 ;
     RECT  12.336 37.045 13.656 37.861 ;
     RECT  2.4 37.619 4.152 37.907 ;
     RECT  15.84 37.765 44.184 38.051 ;
     RECT  229.2 37.139 229.512 38.149 ;
     RECT  3.744 37.907 4.152 38.195 ;
     RECT  15.84 38.051 26.568 38.339 ;
     RECT  4.128 38.195 4.152 38.725 ;
     RECT  5.184 37.619 8.616 38.725 ;
     RECT  222 35.267 225.096 39.395 ;
     RECT  27.648 38.051 44.184 39.443 ;
     RECT  2.4 37.907 2.712 39.445 ;
     RECT  4.128 38.725 8.616 39.445 ;
     RECT  43.584 39.443 44.184 39.493 ;
     RECT  2.4 39.445 8.616 39.541 ;
     RECT  1.68 39.541 8.616 39.589 ;
     RECT  43.584 39.493 44.376 39.683 ;
     RECT  9.984 33.683 10.632 39.925 ;
     RECT  43.584 39.683 44.184 40.067 ;
     RECT  16.848 38.339 26.568 40.117 ;
     RECT  27.648 39.443 42.36 40.117 ;
     RECT  15.792 38.581 15.816 40.405 ;
     RECT  16.848 40.117 42.36 40.405 ;
     RECT  12.336 37.861 14.088 40.597 ;
     RECT  9.984 39.925 10.728 40.837 ;
     RECT  11.76 40.597 14.088 40.837 ;
     RECT  1.68 39.589 8.952 41.075 ;
     RECT  15.792 40.405 42.36 41.557 ;
     RECT  15.6 41.557 42.36 41.651 ;
     RECT  9.984 40.837 14.088 41.939 ;
     RECT  15.6 41.651 41.928 42.227 ;
     RECT  222.336 39.395 225.096 42.227 ;
     RECT  229.2 38.149 229.608 42.227 ;
     RECT  11.472 41.939 14.088 42.419 ;
     RECT  12.768 42.419 14.088 42.565 ;
     RECT  15.6 42.227 41.496 42.565 ;
     RECT  12.768 42.565 41.496 42.707 ;
     RECT  1.68 41.075 4.152 42.709 ;
     RECT  5.184 41.075 8.952 42.709 ;
     RECT  1.68 42.709 8.952 42.755 ;
     RECT  27.648 42.707 41.496 42.803 ;
     RECT  43.632 40.067 44.184 42.853 ;
     RECT  11.472 42.419 11.496 42.995 ;
     RECT  43.632 42.853 44.424 43.043 ;
     RECT  222.624 42.227 225.096 43.091 ;
     RECT  223.104 43.091 225.096 43.139 ;
     RECT  27.84 42.803 40.68 43.331 ;
     RECT  219.696 34.835 219.864 43.331 ;
     RECT  37.872 43.331 40.68 43.379 ;
     RECT  27.84 43.331 36.744 43.427 ;
     RECT  27.84 43.427 36.216 43.571 ;
     RECT  12.768 42.707 26.472 43.669 ;
     RECT  3.984 42.755 8.952 43.955 ;
     RECT  43.632 43.043 44.184 43.955 ;
     RECT  223.8 43.139 225.096 43.955 ;
     RECT  1.68 42.755 2.712 44.341 ;
     RECT  12.144 43.669 26.472 44.725 ;
     RECT  9.984 41.939 10.392 44.965 ;
     RECT  12.144 44.725 26.52 44.965 ;
     RECT  219.696 43.331 219.72 45.203 ;
     RECT  43.008 44.437 43.032 45.253 ;
     RECT  4.128 43.955 8.952 45.445 ;
     RECT  9.984 44.965 26.52 45.445 ;
     RECT  1.68 44.341 2.808 45.541 ;
     RECT  4.128 45.445 26.52 45.541 ;
     RECT  42.144 45.253 43.032 45.541 ;
     RECT  1.68 45.541 26.52 45.683 ;
     RECT  37.872 43.379 40.512 45.685 ;
     RECT  41.952 45.541 43.032 45.685 ;
     RECT  44.16 43.955 44.184 45.685 ;
     RECT  37.872 45.685 43.032 46.117 ;
     RECT  44.16 45.685 44.376 46.213 ;
     RECT  37.872 46.117 43.08 46.261 ;
     RECT  37.632 46.261 43.08 46.309 ;
     RECT  44.16 46.213 44.424 46.403 ;
     RECT  37.632 46.309 43.128 46.645 ;
     RECT  44.16 46.403 44.376 46.645 ;
     RECT  11.424 45.683 26.52 46.835 ;
     RECT  37.632 46.645 44.376 47.363 ;
     RECT  37.92 47.363 44.376 47.989 ;
     RECT  11.856 46.835 26.52 48.277 ;
     RECT  37.92 47.989 44.424 48.467 ;
     RECT  27.888 43.571 36.216 48.469 ;
     RECT  1.68 45.683 10.392 48.661 ;
     RECT  11.472 48.277 26.52 48.661 ;
     RECT  27.888 48.469 36.792 48.901 ;
     RECT  37.92 48.467 44.376 48.901 ;
     RECT  1.68 48.661 26.52 50.053 ;
     RECT  27.888 48.901 44.376 50.053 ;
     RECT  1.68 50.053 44.376 52.403 ;
     RECT  27.888 52.403 44.376 52.691 ;
     RECT  1.68 52.403 26.808 52.741 ;
     RECT  1.632 52.741 26.808 53.219 ;
     RECT  27.888 52.691 44.328 53.843 ;
     RECT  27.888 53.843 44.28 54.371 ;
     RECT  17.904 53.219 26.376 54.517 ;
     RECT  27.888 54.371 35.112 54.517 ;
     RECT  1.632 53.219 16.872 55.237 ;
     RECT  17.904 54.517 35.112 55.237 ;
     RECT  1.632 55.237 35.112 55.283 ;
     RECT  36.336 54.371 44.28 55.331 ;
     RECT  36.72 55.331 44.28 55.427 ;
     RECT  1.632 55.283 26.376 56.485 ;
     RECT  37.776 55.427 44.28 56.819 ;
     RECT  37.776 56.819 44.184 56.915 ;
     RECT  1.632 56.485 26.568 57.013 ;
     RECT  36.72 55.427 36.744 57.059 ;
     RECT  37.776 56.915 42.792 57.059 ;
     RECT  44.112 56.915 44.184 57.107 ;
     RECT  1.632 57.013 26.808 57.205 ;
     RECT  27.888 55.283 35.112 57.205 ;
     RECT  1.632 57.205 35.112 57.251 ;
     RECT  1.632 57.251 10.44 57.299 ;
     RECT  11.424 57.251 35.112 57.395 ;
     RECT  27.888 57.395 35.112 57.445 ;
     RECT  11.424 57.395 26.808 57.587 ;
     RECT  37.776 57.059 37.992 57.635 ;
     RECT  17.904 57.587 26.808 57.731 ;
     RECT  17.904 57.731 26.376 57.875 ;
     RECT  11.424 57.587 16.872 58.067 ;
     RECT  1.632 57.299 10.392 58.307 ;
     RECT  1.632 58.307 8.112 58.691 ;
     RECT  39.216 57.059 42.792 58.691 ;
     RECT  9.12 58.307 10.392 58.739 ;
     RECT  42.192 58.691 42.792 58.739 ;
     RECT  27.888 57.445 35.4 58.787 ;
     RECT  42.336 58.739 42.792 59.027 ;
     RECT  39.216 58.691 40.776 59.219 ;
     RECT  4.848 58.691 8.112 59.315 ;
     RECT  39.216 59.219 40.632 59.315 ;
     RECT  42.768 59.027 42.792 59.315 ;
     RECT  11.472 58.067 16.872 59.509 ;
     RECT  17.904 57.875 22.968 59.509 ;
     RECT  11.472 59.509 22.968 59.651 ;
     RECT  1.632 58.691 3.48 59.891 ;
     RECT  11.472 59.651 16.92 59.987 ;
     RECT  9.504 58.739 10.392 59.989 ;
     RECT  27.888 58.787 35.352 60.181 ;
     RECT  39.984 59.315 40.632 60.277 ;
     RECT  39.792 60.277 40.632 60.373 ;
     RECT  1.632 59.891 2.952 60.419 ;
     RECT  5.376 59.315 8.112 60.661 ;
     RECT  9.36 59.989 10.392 60.661 ;
     RECT  17.904 59.651 22.968 60.661 ;
     RECT  24 57.875 26.376 60.661 ;
     RECT  39.792 60.373 40.776 60.661 ;
     RECT  5.376 60.661 10.392 60.803 ;
     RECT  36.96 59.221 36.984 60.803 ;
     RECT  39.792 60.661 40.872 60.853 ;
     RECT  39.792 60.853 41.496 60.949 ;
     RECT  39.792 60.949 42.072 61.139 ;
     RECT  0.144 61.237 0.168 61.427 ;
     RECT  38.736 61.381 38.76 61.573 ;
     RECT  39.792 61.139 41.016 61.573 ;
     RECT  38.736 61.573 41.016 62.101 ;
     RECT  42.048 61.139 42.072 62.149 ;
     RECT  38.448 62.101 41.016 62.197 ;
     RECT  42.048 62.149 42.168 62.197 ;
     RECT  1.632 60.419 2.712 62.581 ;
     RECT  6.96 60.803 10.392 62.821 ;
     RECT  27.888 60.181 35.736 63.299 ;
     RECT  6.96 62.821 10.44 63.493 ;
     RECT  11.472 59.987 16.872 63.493 ;
     RECT  33.552 63.299 35.736 63.637 ;
     RECT  36.912 62.197 36.936 63.637 ;
     RECT  6.96 63.493 16.872 63.733 ;
     RECT  17.904 60.661 26.376 63.733 ;
     RECT  1.632 62.581 2.856 63.781 ;
     RECT  6.96 63.733 26.376 64.357 ;
     RECT  5.376 60.803 5.64 64.405 ;
     RECT  27.888 63.299 32.568 64.451 ;
     RECT  33.552 63.637 36.936 64.451 ;
     RECT  5.232 64.405 5.64 64.453 ;
     RECT  33.744 64.451 36.936 64.501 ;
     RECT  38.448 62.197 42.168 64.501 ;
     RECT  5.232 64.453 5.688 64.645 ;
     RECT  4.992 64.645 5.688 64.741 ;
     RECT  6.864 64.357 26.376 64.741 ;
     RECT  1.632 63.781 3.528 64.981 ;
     RECT  4.992 64.741 26.376 64.981 ;
     RECT  28.176 64.451 32.568 65.027 ;
     RECT  1.632 64.981 26.376 65.221 ;
     RECT  1.632 65.221 26.568 65.459 ;
     RECT  33.744 64.501 42.168 65.989 ;
     RECT  1.632 65.459 25.272 66.035 ;
     RECT  28.176 65.027 32.04 66.133 ;
     RECT  26.256 65.459 26.568 66.229 ;
     RECT  28.176 66.133 32.136 66.469 ;
     RECT  26.256 66.229 26.904 66.517 ;
     RECT  28.176 66.469 32.472 66.517 ;
     RECT  26.256 66.517 32.472 66.611 ;
     RECT  18.192 66.035 25.272 66.661 ;
     RECT  26.256 66.611 32.136 66.661 ;
     RECT  18.192 66.661 32.136 66.851 ;
     RECT  1.632 66.035 16.872 67.237 ;
     RECT  18.192 66.851 31.704 67.379 ;
     RECT  1.632 67.237 17.064 67.669 ;
     RECT  18.192 67.379 30.168 67.669 ;
     RECT  1.632 67.669 30.168 68.051 ;
     RECT  33.744 65.989 42.36 68.435 ;
     RECT  26.544 68.051 30.168 68.915 ;
     RECT  33.888 68.435 42.36 69.299 ;
     RECT  1.632 68.051 25.464 69.445 ;
     RECT  33.888 69.299 36.744 70.019 ;
     RECT  1.632 69.445 25.512 70.067 ;
     RECT  34.32 70.019 36.744 70.309 ;
     RECT  37.872 69.299 42.36 70.309 ;
     RECT  34.32 70.309 42.36 70.499 ;
     RECT  26.88 68.915 30.168 70.931 ;
     RECT  34.32 70.499 35.736 71.075 ;
     RECT  21.888 70.067 25.512 71.077 ;
     RECT  34.8 71.075 35.736 71.219 ;
     RECT  1.632 70.067 20.856 71.315 ;
     RECT  36.72 70.499 42.36 71.651 ;
     RECT  21.888 71.077 25.656 71.747 ;
     RECT  21.888 71.747 22.632 71.891 ;
     RECT  24 71.747 25.656 71.987 ;
     RECT  31.68 67.379 31.704 71.989 ;
     RECT  24 71.987 25.464 72.179 ;
     RECT  1.632 71.315 17.256 72.275 ;
     RECT  14.736 72.275 17.256 72.419 ;
     RECT  36.72 71.651 36.744 72.613 ;
     RECT  37.872 71.651 42.36 72.613 ;
     RECT  1.632 72.275 13.704 72.803 ;
     RECT  36.72 72.613 42.36 72.899 ;
     RECT  26.88 70.931 27.672 72.947 ;
     RECT  1.632 72.803 13.608 72.995 ;
     RECT  26.88 72.947 27.624 72.995 ;
     RECT  2.208 72.995 13.608 73.139 ;
     RECT  36.72 72.899 37.176 73.189 ;
     RECT  14.736 72.419 16.104 73.235 ;
     RECT  34.8 71.219 35.352 73.235 ;
     RECT  44.16 57.107 44.184 73.283 ;
     RECT  17.232 72.419 17.256 73.477 ;
     RECT  22.608 71.891 22.632 73.477 ;
     RECT  24 72.179 24.312 73.477 ;
     RECT  2.256 73.139 13.608 73.523 ;
     RECT  18.6 71.315 20.856 73.571 ;
     RECT  17.088 73.477 17.256 73.811 ;
     RECT  38.448 72.899 42.36 73.859 ;
     RECT  25.44 72.179 25.464 73.861 ;
     RECT  25.344 73.861 25.464 74.003 ;
     RECT  22.608 73.477 24.312 74.101 ;
     RECT  25.344 74.003 25.368 74.101 ;
     RECT  2.256 73.523 11.496 74.147 ;
     RECT  14.736 73.235 14.856 74.147 ;
     RECT  28.752 70.931 30.168 74.147 ;
     RECT  31.68 71.989 32.52 74.147 ;
     RECT  12.624 73.523 13.608 74.387 ;
     RECT  22.608 74.101 25.368 74.483 ;
     RECT  12.72 74.387 13.608 74.677 ;
     RECT  18.6 73.571 19.752 74.677 ;
     RECT  20.832 73.571 20.856 74.677 ;
     RECT  42.24 73.859 42.36 74.723 ;
     RECT  42.24 74.723 42.264 74.771 ;
     RECT  38.448 73.859 40.728 74.867 ;
     RECT  11.472 74.147 11.496 74.963 ;
     RECT  16.08 73.235 16.104 74.963 ;
     RECT  12.72 74.677 13.704 75.205 ;
     RECT  14.736 74.147 14.76 75.205 ;
     RECT  34.8 73.235 35.112 75.205 ;
     RECT  2.256 74.147 10.392 75.299 ;
     RECT  29.184 74.147 30.168 75.299 ;
     RECT  38.448 74.867 40.632 75.299 ;
     RECT  2.256 75.299 10.056 75.347 ;
     RECT  18.6 74.677 20.856 75.395 ;
     RECT  22.608 74.483 25.128 75.395 ;
     RECT  22.608 75.395 22.632 75.539 ;
     RECT  23.904 75.395 25.128 75.779 ;
     RECT  36.336 73.189 37.176 75.829 ;
     RECT  24 75.779 25.128 75.875 ;
     RECT  12.72 75.205 14.76 75.923 ;
     RECT  36.096 75.829 37.176 75.923 ;
     RECT  20.832 75.395 20.856 76.019 ;
     RECT  2.256 75.347 9.624 76.499 ;
     RECT  17.232 73.811 17.256 76.549 ;
     RECT  18.6 75.395 19.752 76.549 ;
     RECT  17.232 76.549 19.752 76.981 ;
     RECT  12.72 75.923 13.608 77.027 ;
     RECT  13.104 77.027 13.608 77.123 ;
     RECT  2.256 76.499 8.112 77.171 ;
     RECT  11.424 75.493 11.448 77.315 ;
     RECT  13.104 77.123 13.512 77.315 ;
     RECT  36.096 75.923 37.128 77.507 ;
     RECT  16.896 76.981 20.472 77.555 ;
     RECT  38.832 75.299 40.632 77.555 ;
     RECT  39.456 77.555 40.632 77.603 ;
     RECT  2.256 77.171 6.168 78.035 ;
     RECT  9.168 76.499 9.624 78.037 ;
     RECT  17.232 77.555 20.472 78.083 ;
     RECT  18.6 78.083 20.472 78.131 ;
     RECT  24 75.875 24.792 78.131 ;
     RECT  40.2 77.603 40.632 78.131 ;
     RECT  27.312 72.995 27.624 78.469 ;
     RECT  17.232 78.083 17.256 78.613 ;
     RECT  2.256 78.035 5.64 78.707 ;
     RECT  26.544 78.469 27.624 78.707 ;
     RECT  34.704 75.205 35.112 78.853 ;
     RECT  36.096 77.507 36.36 78.853 ;
     RECT  34.704 78.853 36.36 78.899 ;
     RECT  29.184 75.299 29.712 78.997 ;
     RECT  17.04 78.613 17.256 79.045 ;
     RECT  9.168 78.037 9.72 79.139 ;
     RECT  9.168 79.139 9.384 79.235 ;
     RECT  14.736 75.923 14.76 79.237 ;
     RECT  14.496 79.237 14.76 79.283 ;
     RECT  17.04 79.045 17.496 79.283 ;
     RECT  18.6 78.131 19.416 79.283 ;
     RECT  29.184 78.997 30.36 79.283 ;
     RECT  4.704 78.707 5.64 79.715 ;
     RECT  17.04 79.283 17.064 79.715 ;
     RECT  26.544 78.707 27.432 79.715 ;
     RECT  40.2 78.131 40.512 79.765 ;
     RECT  24 78.131 24.504 79.813 ;
     RECT  33.552 79.189 33.576 80.195 ;
     RECT  2.256 78.707 3.624 80.435 ;
     RECT  2.256 80.435 3.048 80.483 ;
     RECT  2.256 80.483 2.712 80.579 ;
     RECT  4.704 79.715 5.496 80.579 ;
     RECT  27.408 79.715 27.432 80.579 ;
     RECT  29.4 79.283 30.36 80.579 ;
     RECT  24 79.813 24.552 80.627 ;
     RECT  4.704 80.579 4.728 80.963 ;
     RECT  34.704 78.899 35.928 81.011 ;
     RECT  40.08 79.765 40.512 81.347 ;
     RECT  13.2 77.315 13.512 81.349 ;
     RECT  14.496 79.283 14.52 81.349 ;
     RECT  7.44 77.171 8.112 81.539 ;
     RECT  18.6 79.283 19.032 81.973 ;
     RECT  22.704 81.205 22.728 82.067 ;
     RECT  9.36 79.235 9.384 82.115 ;
     RECT  37.632 78.613 37.656 82.259 ;
     RECT  10.8 80.341 10.824 82.403 ;
     RECT  32.256 79.045 32.28 82.645 ;
     RECT  5.76 81.445 5.784 82.691 ;
     RECT  7.488 81.539 8.112 82.691 ;
     RECT  31.776 82.645 32.28 82.691 ;
     RECT  18.48 81.973 19.032 83.075 ;
     RECT  34.704 81.011 35.496 83.075 ;
     RECT  13.2 81.349 14.52 83.123 ;
     RECT  11.184 82.981 11.208 83.843 ;
     RECT  31.776 82.691 31.8 84.035 ;
     RECT  13.2 83.123 14.424 84.419 ;
     RECT  34.704 83.075 35.112 84.899 ;
     RECT  18.6 83.075 19.032 84.995 ;
     RECT  27.36 82.597 27.384 85.523 ;
     RECT  2.4 80.579 2.712 114.489 ;
     RECT  7.8 82.691 8.112 114.489 ;
     RECT  13.2 84.419 13.512 114.489 ;
     RECT  18.6 84.995 18.912 114.489 ;
     RECT  24 80.627 24.312 114.489 ;
     RECT  29.4 80.579 29.712 114.489 ;
     RECT  34.8 84.899 35.112 114.489 ;
     RECT  40.2 81.347 40.512 114.489 ;
     RECT  45.6 22.835 45.912 114.489 ;
     RECT  51 21.827 51.312 114.489 ;
     RECT  56.4 21.443 56.712 114.489 ;
     RECT  61.8 18.899 62.112 114.489 ;
     RECT  67.2 21.203 67.512 114.489 ;
     RECT  72.6 20.483 72.912 114.489 ;
     RECT  78 21.491 78.312 114.489 ;
     RECT  83.4 21.779 83.712 114.489 ;
     RECT  88.8 21.395 89.112 114.489 ;
     RECT  94.2 20.579 94.512 114.489 ;
     RECT  99.6 21.299 99.912 114.489 ;
     RECT  105 20.387 105.312 114.489 ;
     RECT  110.4 21.299 110.712 114.489 ;
     RECT  115.8 19.427 116.112 114.489 ;
     RECT  121.2 20.675 121.512 114.489 ;
     RECT  126.6 21.299 126.912 114.489 ;
     RECT  132 21.395 132.312 114.489 ;
     RECT  137.4 20.867 137.712 114.489 ;
     RECT  142.8 20.867 143.112 114.489 ;
     RECT  148.2 21.491 148.512 114.489 ;
     RECT  153.6 21.347 153.912 114.489 ;
     RECT  159 21.443 159.312 114.489 ;
     RECT  164.4 21.203 164.712 114.489 ;
     RECT  169.8 21.299 170.112 114.489 ;
     RECT  175.2 21.587 175.512 114.489 ;
     RECT  180.6 20.435 180.912 114.489 ;
     RECT  186 20.723 186.312 114.489 ;
     RECT  191.4 2.151 191.712 114.489 ;
     RECT  196.8 2.151 197.112 114.489 ;
     RECT  202.2 21.683 202.512 114.489 ;
     RECT  207.6 21.059 207.912 114.489 ;
     RECT  213 20.339 213.312 114.489 ;
     RECT  218.4 33.587 218.712 114.489 ;
     RECT  223.8 43.955 224.112 114.489 ;
     RECT  229.2 42.227 229.512 114.489 ;
     RECT  234.6 36.515 234.912 114.489 ;
     RECT  2.4 114.489 2.52 114.503 ;
     RECT  7.8 114.489 7.92 114.503 ;
     RECT  13.2 114.489 13.32 114.503 ;
     RECT  18.6 114.489 18.72 114.503 ;
     RECT  24 114.489 24.12 114.503 ;
     RECT  29.4 114.489 29.52 114.503 ;
     RECT  34.8 114.489 34.92 114.503 ;
     RECT  40.2 114.489 40.32 114.503 ;
     RECT  45.6 114.489 45.72 114.503 ;
     RECT  51 114.489 51.12 114.503 ;
     RECT  56.4 114.489 56.52 114.503 ;
     RECT  61.8 114.489 61.92 114.503 ;
     RECT  67.2 114.489 67.32 114.503 ;
     RECT  72.6 114.489 72.72 114.503 ;
     RECT  78 114.489 78.12 114.503 ;
     RECT  83.4 114.489 83.52 114.503 ;
     RECT  88.8 114.489 88.92 114.503 ;
     RECT  94.2 114.489 94.32 114.503 ;
     RECT  99.6 114.489 99.72 114.503 ;
     RECT  105 114.489 105.12 114.503 ;
     RECT  110.4 114.489 110.52 114.503 ;
     RECT  115.8 114.489 115.92 114.503 ;
     RECT  121.2 114.489 121.32 114.503 ;
     RECT  126.6 114.489 126.72 114.503 ;
     RECT  132 114.489 132.12 114.503 ;
     RECT  137.4 114.489 137.52 114.503 ;
     RECT  142.8 114.489 142.92 114.503 ;
     RECT  148.2 114.489 148.32 114.503 ;
     RECT  153.6 114.489 153.72 114.503 ;
     RECT  159 114.489 159.12 114.503 ;
     RECT  164.4 114.489 164.52 114.503 ;
     RECT  169.8 114.489 169.92 114.503 ;
     RECT  175.2 114.489 175.32 114.503 ;
     RECT  180.6 114.489 180.72 114.503 ;
     RECT  186 114.489 186.12 114.503 ;
     RECT  191.4 114.489 191.52 114.503 ;
     RECT  196.8 114.489 196.92 114.503 ;
     RECT  202.2 114.489 202.32 114.503 ;
     RECT  207.6 114.489 207.72 114.503 ;
     RECT  213 114.489 213.12 114.503 ;
     RECT  218.4 114.489 218.52 114.503 ;
     RECT  223.8 114.489 223.92 114.503 ;
     RECT  229.2 114.489 229.32 114.503 ;
     RECT  234.6 114.489 234.72 114.503 ;
  END
END hfd_hgi_vm_calendar_f20
END LIBRARY
